VERSION 5.7 ;
BUSBITCHARS "[]" ;
DIVIDERCHAR "/" ;

PROPERTYDEFINITIONS
  MACRO CatenaDesignType STRING ;
END PROPERTYDEFINITIONS

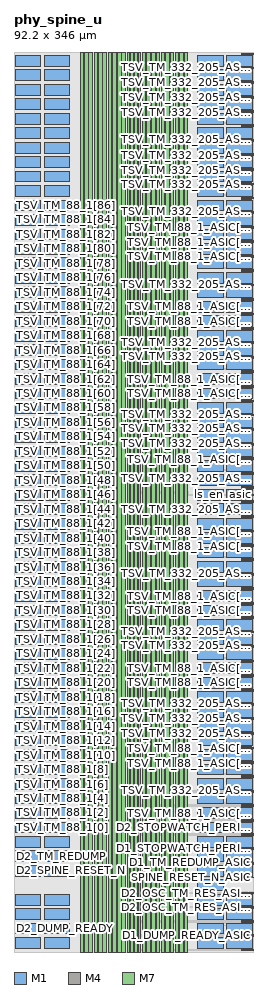
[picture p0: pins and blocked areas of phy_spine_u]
MACRO phy_spine_u
  CLASS RING ;
  ORIGIN 0 0 ;
  FOREIGN phy_spine_u 0 0 ;
  SIZE 92.2 BY 346 ;
  SYMMETRY X Y R90 ;
  PIN D1_DUMP_READY
    DIRECTION INPUT ;
    USE SIGNAL ;
    PORT
      LAYER M1 ;
        RECT 70.7 6.925 80.38 11.045 ;
    END
  END D1_DUMP_READY
  PIN D1_OSC_TM_RES[0]
    DIRECTION INPUT ;
    USE SIGNAL ;
    PORT
      LAYER M1 ;
        RECT 70.7 18.045 80.38 22.165 ;
    END
  END D1_OSC_TM_RES[0]
  PIN D1_OSC_TM_RES[1]
    DIRECTION INPUT ;
    USE SIGNAL ;
    PORT
      LAYER M1 ;
        RECT 70.7 12.485 80.38 16.605 ;
    END
  END D1_OSC_TM_RES[1]
  PIN D1_SPINE_RESET_N
    DIRECTION OUTPUT ;
    USE SIGNAL ;
    PORT
      LAYER M1 ;
        RECT 70.7 29.165 80.38 33.285 ;
    END
  END D1_SPINE_RESET_N
  PIN D1_STOPWATCH_PERIOD
    DIRECTION OUTPUT ;
    USE SIGNAL ;
    PORT
      LAYER M1 ;
        RECT 70.7 40.285 80.38 44.405 ;
    END
  END D1_STOPWATCH_PERIOD
  PIN D1_STOPWATCH_RINGO
    DIRECTION INPUT ;
    USE SIGNAL ;
    PORT
      LAYER M1 ;
        RECT 70.7 1.365 80.38 5.485 ;
    END
  END D1_STOPWATCH_RINGO
  PIN D1_TM_REDUMP
    DIRECTION OUTPUT ;
    USE SIGNAL ;
    PORT
      LAYER M1 ;
        RECT 70.7 34.725 80.38 38.845 ;
    END
  END D1_TM_REDUMP
  PIN D2_DUMP_READY
    DIRECTION INPUT ;
    USE SIGNAL ;
    PORT
      LAYER M1 ;
        RECT 11.79 6.925 21.47 11.045 ;
    END
  END D2_DUMP_READY
  PIN D2_OSC_TM_RES[0]
    DIRECTION INPUT ;
    USE SIGNAL ;
    PORT
      LAYER M1 ;
        RECT 11.79 18.045 21.47 22.165 ;
    END
  END D2_OSC_TM_RES[0]
  PIN D2_OSC_TM_RES[1]
    DIRECTION INPUT ;
    USE SIGNAL ;
    PORT
      LAYER M1 ;
        RECT 11.79 12.485 21.47 16.605 ;
    END
  END D2_OSC_TM_RES[1]
  PIN D2_SPINE_RESET_N
    DIRECTION OUTPUT ;
    USE SIGNAL ;
    PORT
      LAYER M1 ;
        RECT 11.79 29.165 21.47 33.285 ;
    END
  END D2_SPINE_RESET_N
  PIN D2_STOPWATCH_PERIOD
    DIRECTION OUTPUT ;
    USE SIGNAL ;
    PORT
      LAYER M1 ;
        RECT 11.79 40.285 21.47 44.405 ;
    END
  END D2_STOPWATCH_PERIOD
  PIN D2_STOPWATCH_RINGO
    DIRECTION INPUT ;
    USE SIGNAL ;
    PORT
      LAYER M1 ;
        RECT 11.79 1.365 21.47 5.485 ;
    END
  END D2_STOPWATCH_RINGO
  PIN D2_TM_REDUMP
    DIRECTION OUTPUT ;
    USE SIGNAL ;
    PORT
      LAYER M1 ;
        RECT 11.79 34.725 21.47 38.845 ;
    END
  END D2_TM_REDUMP
  PIN D3_DUMP_READY
    DIRECTION INPUT ;
    USE SIGNAL ;
    PORT
      LAYER M1 ;
        RECT 0.67 6.925 10.35 11.045 ;
    END
  END D3_DUMP_READY
  PIN D3_OSC_TM_RES[0]
    DIRECTION INPUT ;
    USE SIGNAL ;
    PORT
      LAYER M1 ;
        RECT 0.67 18.045 10.35 22.165 ;
    END
  END D3_OSC_TM_RES[0]
  PIN D3_OSC_TM_RES[1]
    DIRECTION INPUT ;
    USE SIGNAL ;
    PORT
      LAYER M1 ;
        RECT 0.67 12.485 10.35 16.605 ;
    END
  END D3_OSC_TM_RES[1]
  PIN D3_SPINE_RESET_N
    DIRECTION OUTPUT ;
    USE SIGNAL ;
    PORT
      LAYER M1 ;
        RECT 0.67 29.165 10.35 33.285 ;
    END
  END D3_SPINE_RESET_N
  PIN D3_STOPWATCH_PERIOD
    DIRECTION OUTPUT ;
    USE SIGNAL ;
    PORT
      LAYER M1 ;
        RECT 0.67 40.285 10.35 44.405 ;
    END
  END D3_STOPWATCH_PERIOD
  PIN D3_STOPWATCH_RINGO
    DIRECTION INPUT ;
    USE SIGNAL ;
    PORT
      LAYER M1 ;
        RECT 0.67 1.365 10.35 5.485 ;
    END
  END D3_STOPWATCH_RINGO
  PIN D3_TM_REDUMP
    DIRECTION OUTPUT ;
    USE SIGNAL ;
    PORT
      LAYER M1 ;
        RECT 0.67 34.725 10.35 38.845 ;
    END
  END D3_TM_REDUMP
  PIN DUMP_READY
    DIRECTION INPUT ;
    USE SIGNAL ;
    PORT
      LAYER M1 ;
        RECT 81.82 6.925 91.5 11.045 ;
    END
  END DUMP_READY
  PIN OSC_TM_RES[0]
    DIRECTION INPUT ;
    USE SIGNAL ;
    PORT
      LAYER M1 ;
        RECT 81.82 18.045 91.5 22.165 ;
    END
  END OSC_TM_RES[0]
  PIN OSC_TM_RES[1]
    DIRECTION INPUT ;
    USE SIGNAL ;
    PORT
      LAYER M1 ;
        RECT 81.82 12.485 91.5 16.605 ;
    END
  END OSC_TM_RES[1]
  PIN SPINE_RESET_N
    DIRECTION OUTPUT ;
    USE SIGNAL ;
    PORT
      LAYER M1 ;
        RECT 81.82 29.165 91.5 33.285 ;
    END
  END SPINE_RESET_N
  PIN STOPWATCH_PERIOD
    DIRECTION OUTPUT ;
    USE SIGNAL ;
    PORT
      LAYER M1 ;
        RECT 81.82 40.285 91.5 44.405 ;
    END
  END STOPWATCH_PERIOD
  PIN STOPWATCH_RINGO
    DIRECTION INPUT ;
    USE SIGNAL ;
    PORT
      LAYER M1 ;
        RECT 81.82 1.365 91.5 5.485 ;
    END
  END STOPWATCH_RINGO
  PIN TM_REDUMP
    DIRECTION OUTPUT ;
    USE SIGNAL ;
    PORT
      LAYER M1 ;
        RECT 81.82 34.725 91.5 38.845 ;
    END
  END TM_REDUMP
  PIN TSV_TM_332_205[0]
    DIRECTION OUTPUT ;
    USE SIGNAL ;
    PORT
      LAYER M1 ;
        RECT 81.82 45.845 91.5 49.965 ;
    END
  END TSV_TM_332_205[0]
  PIN TSV_TM_332_205[100]
    DIRECTION OUTPUT ;
    USE SIGNAL ;
    PORT
      LAYER M1 ;
        RECT 81.82 323.845 91.5 327.965 ;
    END
  END TSV_TM_332_205[100]
  PIN TSV_TM_332_205[101]
    DIRECTION OUTPUT ;
    USE SIGNAL ;
    PORT
      LAYER M1 ;
        RECT 70.7 323.845 80.38 327.965 ;
    END
  END TSV_TM_332_205[101]
  PIN TSV_TM_332_205[102]
    DIRECTION OUTPUT ;
    USE SIGNAL ;
    PORT
      LAYER M1 ;
        RECT 81.82 329.405 91.5 333.525 ;
    END
  END TSV_TM_332_205[102]
  PIN TSV_TM_332_205[103]
    DIRECTION OUTPUT ;
    USE SIGNAL ;
    PORT
      LAYER M1 ;
        RECT 70.7 329.405 80.38 333.525 ;
    END
  END TSV_TM_332_205[103]
  PIN TSV_TM_332_205[104]
    DIRECTION OUTPUT ;
    USE SIGNAL ;
    PORT
      LAYER M1 ;
        RECT 81.82 334.965 91.5 339.085 ;
    END
  END TSV_TM_332_205[104]
  PIN TSV_TM_332_205[105]
    DIRECTION OUTPUT ;
    USE SIGNAL ;
    PORT
      LAYER M1 ;
        RECT 70.7 334.965 80.38 339.085 ;
    END
  END TSV_TM_332_205[105]
  PIN TSV_TM_332_205[106]
    DIRECTION OUTPUT ;
    USE SIGNAL ;
    PORT
      LAYER M1 ;
        RECT 81.82 340.525 91.5 344.645 ;
    END
  END TSV_TM_332_205[106]
  PIN TSV_TM_332_205[107]
    DIRECTION OUTPUT ;
    USE SIGNAL ;
    PORT
      LAYER M1 ;
        RECT 70.7 340.525 80.38 344.645 ;
    END
  END TSV_TM_332_205[107]
  PIN TSV_TM_332_205[108]
    DIRECTION OUTPUT ;
    USE SIGNAL ;
    PORT
      LAYER M1 ;
        RECT 11.79 340.525 21.47 344.645 ;
    END
  END TSV_TM_332_205[108]
  PIN TSV_TM_332_205[109]
    DIRECTION OUTPUT ;
    USE SIGNAL ;
    PORT
      LAYER M1 ;
        RECT 0.67 340.525 10.35 344.645 ;
    END
  END TSV_TM_332_205[109]
  PIN TSV_TM_332_205[10]
    DIRECTION OUTPUT ;
    USE SIGNAL ;
    PORT
      LAYER M1 ;
        RECT 81.82 73.645 91.5 77.765 ;
    END
  END TSV_TM_332_205[10]
  PIN TSV_TM_332_205[110]
    DIRECTION OUTPUT ;
    USE SIGNAL ;
    PORT
      LAYER M1 ;
        RECT 11.79 334.965 21.47 339.085 ;
    END
  END TSV_TM_332_205[110]
  PIN TSV_TM_332_205[111]
    DIRECTION OUTPUT ;
    USE SIGNAL ;
    PORT
      LAYER M1 ;
        RECT 0.67 334.965 10.35 339.085 ;
    END
  END TSV_TM_332_205[111]
  PIN TSV_TM_332_205[112]
    DIRECTION OUTPUT ;
    USE SIGNAL ;
    PORT
      LAYER M1 ;
        RECT 11.79 329.405 21.47 333.525 ;
    END
  END TSV_TM_332_205[112]
  PIN TSV_TM_332_205[113]
    DIRECTION OUTPUT ;
    USE SIGNAL ;
    PORT
      LAYER M1 ;
        RECT 0.67 329.405 10.35 333.525 ;
    END
  END TSV_TM_332_205[113]
  PIN TSV_TM_332_205[114]
    DIRECTION OUTPUT ;
    USE SIGNAL ;
    PORT
      LAYER M1 ;
        RECT 11.79 323.845 21.47 327.965 ;
    END
  END TSV_TM_332_205[114]
  PIN TSV_TM_332_205[115]
    DIRECTION OUTPUT ;
    USE SIGNAL ;
    PORT
      LAYER M1 ;
        RECT 0.67 323.845 10.35 327.965 ;
    END
  END TSV_TM_332_205[115]
  PIN TSV_TM_332_205[116]
    DIRECTION OUTPUT ;
    USE SIGNAL ;
    PORT
      LAYER M1 ;
        RECT 11.79 318.285 21.47 322.405 ;
    END
  END TSV_TM_332_205[116]
  PIN TSV_TM_332_205[117]
    DIRECTION OUTPUT ;
    USE SIGNAL ;
    PORT
      LAYER M1 ;
        RECT 0.67 318.285 10.35 322.405 ;
    END
  END TSV_TM_332_205[117]
  PIN TSV_TM_332_205[118]
    DIRECTION OUTPUT ;
    USE SIGNAL ;
    PORT
      LAYER M1 ;
        RECT 11.79 312.725 21.47 316.845 ;
    END
  END TSV_TM_332_205[118]
  PIN TSV_TM_332_205[119]
    DIRECTION OUTPUT ;
    USE SIGNAL ;
    PORT
      LAYER M1 ;
        RECT 0.67 312.725 10.35 316.845 ;
    END
  END TSV_TM_332_205[119]
  PIN TSV_TM_332_205[11]
    DIRECTION OUTPUT ;
    USE SIGNAL ;
    PORT
      LAYER M1 ;
        RECT 70.7 73.645 80.38 77.765 ;
    END
  END TSV_TM_332_205[11]
  PIN TSV_TM_332_205[120]
    DIRECTION OUTPUT ;
    USE SIGNAL ;
    PORT
      LAYER M1 ;
        RECT 11.79 307.165 21.47 311.285 ;
    END
  END TSV_TM_332_205[120]
  PIN TSV_TM_332_205[121]
    DIRECTION OUTPUT ;
    USE SIGNAL ;
    PORT
      LAYER M1 ;
        RECT 0.67 307.165 10.35 311.285 ;
    END
  END TSV_TM_332_205[121]
  PIN TSV_TM_332_205[122]
    DIRECTION OUTPUT ;
    USE SIGNAL ;
    PORT
      LAYER M1 ;
        RECT 11.79 301.605 21.47 305.725 ;
    END
  END TSV_TM_332_205[122]
  PIN TSV_TM_332_205[123]
    DIRECTION OUTPUT ;
    USE SIGNAL ;
    PORT
      LAYER M1 ;
        RECT 0.67 301.605 10.35 305.725 ;
    END
  END TSV_TM_332_205[123]
  PIN TSV_TM_332_205[124]
    DIRECTION OUTPUT ;
    USE SIGNAL ;
    PORT
      LAYER M1 ;
        RECT 11.79 296.045 21.47 300.165 ;
    END
  END TSV_TM_332_205[124]
  PIN TSV_TM_332_205[125]
    DIRECTION OUTPUT ;
    USE SIGNAL ;
    PORT
      LAYER M1 ;
        RECT 0.67 296.045 10.35 300.165 ;
    END
  END TSV_TM_332_205[125]
  PIN TSV_TM_332_205[126]
    DIRECTION OUTPUT ;
    USE SIGNAL ;
    PORT
      LAYER M1 ;
        RECT 11.79 290.485 21.47 294.605 ;
    END
  END TSV_TM_332_205[126]
  PIN TSV_TM_332_205[127]
    DIRECTION OUTPUT ;
    USE SIGNAL ;
    PORT
      LAYER M1 ;
        RECT 0.67 290.485 10.35 294.605 ;
    END
  END TSV_TM_332_205[127]
  PIN TSV_TM_332_205[12]
    DIRECTION OUTPUT ;
    USE SIGNAL ;
    PORT
      LAYER M1 ;
        RECT 81.82 79.205 91.5 83.325 ;
    END
  END TSV_TM_332_205[12]
  PIN TSV_TM_332_205[13]
    DIRECTION OUTPUT ;
    USE SIGNAL ;
    PORT
      LAYER M1 ;
        RECT 70.7 79.205 80.38 83.325 ;
    END
  END TSV_TM_332_205[13]
  PIN TSV_TM_332_205[14]
    DIRECTION OUTPUT ;
    USE SIGNAL ;
    PORT
      LAYER M1 ;
        RECT 81.82 84.765 91.5 88.885 ;
    END
  END TSV_TM_332_205[14]
  PIN TSV_TM_332_205[15]
    DIRECTION OUTPUT ;
    USE SIGNAL ;
    PORT
      LAYER M1 ;
        RECT 70.7 84.765 80.38 88.885 ;
    END
  END TSV_TM_332_205[15]
  PIN TSV_TM_332_205[16]
    DIRECTION OUTPUT ;
    USE SIGNAL ;
    PORT
      LAYER M1 ;
        RECT 81.82 90.325 91.5 94.445 ;
    END
  END TSV_TM_332_205[16]
  PIN TSV_TM_332_205[17]
    DIRECTION OUTPUT ;
    USE SIGNAL ;
    PORT
      LAYER M1 ;
        RECT 70.7 90.325 80.38 94.445 ;
    END
  END TSV_TM_332_205[17]
  PIN TSV_TM_332_205[18]
    DIRECTION OUTPUT ;
    USE SIGNAL ;
    PORT
      LAYER M1 ;
        RECT 81.82 95.885 91.5 100.005 ;
    END
  END TSV_TM_332_205[18]
  PIN TSV_TM_332_205[19]
    DIRECTION OUTPUT ;
    USE SIGNAL ;
    PORT
      LAYER M1 ;
        RECT 70.7 95.885 80.38 100.005 ;
    END
  END TSV_TM_332_205[19]
  PIN TSV_TM_332_205[1]
    DIRECTION OUTPUT ;
    USE SIGNAL ;
    PORT
      LAYER M1 ;
        RECT 70.7 45.845 80.38 49.965 ;
    END
  END TSV_TM_332_205[1]
  PIN TSV_TM_332_205[20]
    DIRECTION OUTPUT ;
    USE SIGNAL ;
    PORT
      LAYER M1 ;
        RECT 81.82 101.445 91.5 105.565 ;
    END
  END TSV_TM_332_205[20]
  PIN TSV_TM_332_205[21]
    DIRECTION OUTPUT ;
    USE SIGNAL ;
    PORT
      LAYER M1 ;
        RECT 70.7 101.445 80.38 105.565 ;
    END
  END TSV_TM_332_205[21]
  PIN TSV_TM_332_205[22]
    DIRECTION OUTPUT ;
    USE SIGNAL ;
    PORT
      LAYER M1 ;
        RECT 81.82 107.005 91.5 111.125 ;
    END
  END TSV_TM_332_205[22]
  PIN TSV_TM_332_205[23]
    DIRECTION OUTPUT ;
    USE SIGNAL ;
    PORT
      LAYER M1 ;
        RECT 70.7 107.005 80.38 111.125 ;
    END
  END TSV_TM_332_205[23]
  PIN TSV_TM_332_205[24]
    DIRECTION OUTPUT ;
    USE SIGNAL ;
    PORT
      LAYER M1 ;
        RECT 81.82 112.565 91.5 116.685 ;
    END
  END TSV_TM_332_205[24]
  PIN TSV_TM_332_205[25]
    DIRECTION OUTPUT ;
    USE SIGNAL ;
    PORT
      LAYER M1 ;
        RECT 70.7 112.565 80.38 116.685 ;
    END
  END TSV_TM_332_205[25]
  PIN TSV_TM_332_205[26]
    DIRECTION OUTPUT ;
    USE SIGNAL ;
    PORT
      LAYER M1 ;
        RECT 81.82 118.125 91.5 122.245 ;
    END
  END TSV_TM_332_205[26]
  PIN TSV_TM_332_205[27]
    DIRECTION OUTPUT ;
    USE SIGNAL ;
    PORT
      LAYER M1 ;
        RECT 70.7 118.125 80.38 122.245 ;
    END
  END TSV_TM_332_205[27]
  PIN TSV_TM_332_205[28]
    DIRECTION OUTPUT ;
    USE SIGNAL ;
    PORT
      LAYER M1 ;
        RECT 81.82 123.685 91.5 127.805 ;
    END
  END TSV_TM_332_205[28]
  PIN TSV_TM_332_205[29]
    DIRECTION OUTPUT ;
    USE SIGNAL ;
    PORT
      LAYER M1 ;
        RECT 70.7 123.685 80.38 127.805 ;
    END
  END TSV_TM_332_205[29]
  PIN TSV_TM_332_205[2]
    DIRECTION OUTPUT ;
    USE SIGNAL ;
    PORT
      LAYER M1 ;
        RECT 81.82 51.405 91.5 55.525 ;
    END
  END TSV_TM_332_205[2]
  PIN TSV_TM_332_205[30]
    DIRECTION OUTPUT ;
    USE SIGNAL ;
    PORT
      LAYER M1 ;
        RECT 81.82 129.245 91.5 133.365 ;
    END
  END TSV_TM_332_205[30]
  PIN TSV_TM_332_205[31]
    DIRECTION OUTPUT ;
    USE SIGNAL ;
    PORT
      LAYER M1 ;
        RECT 70.7 129.245 80.38 133.365 ;
    END
  END TSV_TM_332_205[31]
  PIN TSV_TM_332_205[32]
    DIRECTION OUTPUT ;
    USE SIGNAL ;
    PORT
      LAYER M1 ;
        RECT 81.82 134.805 91.5 138.925 ;
    END
  END TSV_TM_332_205[32]
  PIN TSV_TM_332_205[33]
    DIRECTION OUTPUT ;
    USE SIGNAL ;
    PORT
      LAYER M1 ;
        RECT 70.7 134.805 80.38 138.925 ;
    END
  END TSV_TM_332_205[33]
  PIN TSV_TM_332_205[34]
    DIRECTION OUTPUT ;
    USE SIGNAL ;
    PORT
      LAYER M1 ;
        RECT 81.82 140.365 91.5 144.485 ;
    END
  END TSV_TM_332_205[34]
  PIN TSV_TM_332_205[35]
    DIRECTION OUTPUT ;
    USE SIGNAL ;
    PORT
      LAYER M1 ;
        RECT 70.7 140.365 80.38 144.485 ;
    END
  END TSV_TM_332_205[35]
  PIN TSV_TM_332_205[36]
    DIRECTION OUTPUT ;
    USE SIGNAL ;
    PORT
      LAYER M1 ;
        RECT 81.82 145.925 91.5 150.045 ;
    END
  END TSV_TM_332_205[36]
  PIN TSV_TM_332_205[37]
    DIRECTION OUTPUT ;
    USE SIGNAL ;
    PORT
      LAYER M1 ;
        RECT 70.7 145.925 80.38 150.045 ;
    END
  END TSV_TM_332_205[37]
  PIN TSV_TM_332_205[38]
    DIRECTION OUTPUT ;
    USE SIGNAL ;
    PORT
      LAYER M1 ;
        RECT 81.82 151.485 91.5 155.605 ;
    END
  END TSV_TM_332_205[38]
  PIN TSV_TM_332_205[39]
    DIRECTION OUTPUT ;
    USE SIGNAL ;
    PORT
      LAYER M1 ;
        RECT 70.7 151.485 80.38 155.605 ;
    END
  END TSV_TM_332_205[39]
  PIN TSV_TM_332_205[3]
    DIRECTION OUTPUT ;
    USE SIGNAL ;
    PORT
      LAYER M1 ;
        RECT 70.7 51.405 80.38 55.525 ;
    END
  END TSV_TM_332_205[3]
  PIN TSV_TM_332_205[40]
    DIRECTION OUTPUT ;
    USE SIGNAL ;
    PORT
      LAYER M1 ;
        RECT 81.82 157.045 91.5 161.165 ;
    END
  END TSV_TM_332_205[40]
  PIN TSV_TM_332_205[41]
    DIRECTION OUTPUT ;
    USE SIGNAL ;
    PORT
      LAYER M1 ;
        RECT 70.7 157.045 80.38 161.165 ;
    END
  END TSV_TM_332_205[41]
  PIN TSV_TM_332_205[42]
    DIRECTION OUTPUT ;
    USE SIGNAL ;
    PORT
      LAYER M1 ;
        RECT 81.82 162.605 91.5 166.725 ;
    END
  END TSV_TM_332_205[42]
  PIN TSV_TM_332_205[43]
    DIRECTION OUTPUT ;
    USE SIGNAL ;
    PORT
      LAYER M1 ;
        RECT 70.7 162.605 80.38 166.725 ;
    END
  END TSV_TM_332_205[43]
  PIN TSV_TM_332_205[44]
    DIRECTION OUTPUT ;
    USE SIGNAL ;
    PORT
      LAYER M1 ;
        RECT 81.82 168.165 91.5 172.285 ;
    END
  END TSV_TM_332_205[44]
  PIN TSV_TM_332_205[45]
    DIRECTION OUTPUT ;
    USE SIGNAL ;
    PORT
      LAYER M1 ;
        RECT 70.7 168.165 80.38 172.285 ;
    END
  END TSV_TM_332_205[45]
  PIN TSV_TM_332_205[46]
    DIRECTION OUTPUT ;
    USE SIGNAL ;
    PORT
      LAYER M1 ;
        RECT 81.82 173.725 91.5 177.845 ;
    END
  END TSV_TM_332_205[46]
  PIN TSV_TM_332_205[47]
    DIRECTION OUTPUT ;
    USE SIGNAL ;
    PORT
      LAYER M1 ;
        RECT 70.7 173.725 80.38 177.845 ;
    END
  END TSV_TM_332_205[47]
  PIN TSV_TM_332_205[48]
    DIRECTION OUTPUT ;
    USE SIGNAL ;
    PORT
      LAYER M1 ;
        RECT 81.82 179.285 91.5 183.405 ;
    END
  END TSV_TM_332_205[48]
  PIN TSV_TM_332_205[49]
    DIRECTION OUTPUT ;
    USE SIGNAL ;
    PORT
      LAYER M1 ;
        RECT 70.7 179.285 80.38 183.405 ;
    END
  END TSV_TM_332_205[49]
  PIN TSV_TM_332_205[4]
    DIRECTION OUTPUT ;
    USE SIGNAL ;
    PORT
      LAYER M1 ;
        RECT 81.82 56.965 91.5 61.085 ;
    END
  END TSV_TM_332_205[4]
  PIN TSV_TM_332_205[50]
    DIRECTION OUTPUT ;
    USE SIGNAL ;
    PORT
      LAYER M1 ;
        RECT 81.82 184.845 91.5 188.965 ;
    END
  END TSV_TM_332_205[50]
  PIN TSV_TM_332_205[51]
    DIRECTION OUTPUT ;
    USE SIGNAL ;
    PORT
      LAYER M1 ;
        RECT 70.7 184.845 80.38 188.965 ;
    END
  END TSV_TM_332_205[51]
  PIN TSV_TM_332_205[52]
    DIRECTION OUTPUT ;
    USE SIGNAL ;
    PORT
      LAYER M1 ;
        RECT 81.82 190.405 91.5 194.525 ;
    END
  END TSV_TM_332_205[52]
  PIN TSV_TM_332_205[53]
    DIRECTION OUTPUT ;
    USE SIGNAL ;
    PORT
      LAYER M1 ;
        RECT 70.7 190.405 80.38 194.525 ;
    END
  END TSV_TM_332_205[53]
  PIN TSV_TM_332_205[54]
    DIRECTION OUTPUT ;
    USE SIGNAL ;
    PORT
      LAYER M1 ;
        RECT 81.82 195.965 91.5 200.085 ;
    END
  END TSV_TM_332_205[54]
  PIN TSV_TM_332_205[55]
    DIRECTION OUTPUT ;
    USE SIGNAL ;
    PORT
      LAYER M1 ;
        RECT 70.7 195.965 80.38 200.085 ;
    END
  END TSV_TM_332_205[55]
  PIN TSV_TM_332_205[56]
    DIRECTION OUTPUT ;
    USE SIGNAL ;
    PORT
      LAYER M1 ;
        RECT 81.82 201.525 91.5 205.645 ;
    END
  END TSV_TM_332_205[56]
  PIN TSV_TM_332_205[57]
    DIRECTION OUTPUT ;
    USE SIGNAL ;
    PORT
      LAYER M1 ;
        RECT 70.7 201.525 80.38 205.645 ;
    END
  END TSV_TM_332_205[57]
  PIN TSV_TM_332_205[58]
    DIRECTION OUTPUT ;
    USE SIGNAL ;
    PORT
      LAYER M1 ;
        RECT 81.82 207.085 91.5 211.205 ;
    END
  END TSV_TM_332_205[58]
  PIN TSV_TM_332_205[59]
    DIRECTION OUTPUT ;
    USE SIGNAL ;
    PORT
      LAYER M1 ;
        RECT 70.7 207.085 80.38 211.205 ;
    END
  END TSV_TM_332_205[59]
  PIN TSV_TM_332_205[5]
    DIRECTION OUTPUT ;
    USE SIGNAL ;
    PORT
      LAYER M1 ;
        RECT 70.7 56.965 80.38 61.085 ;
    END
  END TSV_TM_332_205[5]
  PIN TSV_TM_332_205[60]
    DIRECTION OUTPUT ;
    USE SIGNAL ;
    PORT
      LAYER M1 ;
        RECT 81.82 212.645 91.5 216.765 ;
    END
  END TSV_TM_332_205[60]
  PIN TSV_TM_332_205[61]
    DIRECTION OUTPUT ;
    USE SIGNAL ;
    PORT
      LAYER M1 ;
        RECT 70.7 212.645 80.38 216.765 ;
    END
  END TSV_TM_332_205[61]
  PIN TSV_TM_332_205[62]
    DIRECTION OUTPUT ;
    USE SIGNAL ;
    PORT
      LAYER M1 ;
        RECT 81.82 218.205 91.5 222.325 ;
    END
  END TSV_TM_332_205[62]
  PIN TSV_TM_332_205[63]
    DIRECTION OUTPUT ;
    USE SIGNAL ;
    PORT
      LAYER M1 ;
        RECT 70.7 218.205 80.38 222.325 ;
    END
  END TSV_TM_332_205[63]
  PIN TSV_TM_332_205[64]
    DIRECTION OUTPUT ;
    USE SIGNAL ;
    PORT
      LAYER M1 ;
        RECT 81.82 223.765 91.5 227.885 ;
    END
  END TSV_TM_332_205[64]
  PIN TSV_TM_332_205[65]
    DIRECTION OUTPUT ;
    USE SIGNAL ;
    PORT
      LAYER M1 ;
        RECT 70.7 223.765 80.38 227.885 ;
    END
  END TSV_TM_332_205[65]
  PIN TSV_TM_332_205[66]
    DIRECTION OUTPUT ;
    USE SIGNAL ;
    PORT
      LAYER M1 ;
        RECT 81.82 229.325 91.5 233.445 ;
    END
  END TSV_TM_332_205[66]
  PIN TSV_TM_332_205[67]
    DIRECTION OUTPUT ;
    USE SIGNAL ;
    PORT
      LAYER M1 ;
        RECT 70.7 229.325 80.38 233.445 ;
    END
  END TSV_TM_332_205[67]
  PIN TSV_TM_332_205[68]
    DIRECTION OUTPUT ;
    USE SIGNAL ;
    PORT
      LAYER M1 ;
        RECT 81.82 234.885 91.5 239.005 ;
    END
  END TSV_TM_332_205[68]
  PIN TSV_TM_332_205[69]
    DIRECTION OUTPUT ;
    USE SIGNAL ;
    PORT
      LAYER M1 ;
        RECT 70.7 234.885 80.38 239.005 ;
    END
  END TSV_TM_332_205[69]
  PIN TSV_TM_332_205[6]
    DIRECTION OUTPUT ;
    USE SIGNAL ;
    PORT
      LAYER M1 ;
        RECT 81.82 62.525 91.5 66.645 ;
    END
  END TSV_TM_332_205[6]
  PIN TSV_TM_332_205[70]
    DIRECTION OUTPUT ;
    USE SIGNAL ;
    PORT
      LAYER M1 ;
        RECT 81.82 240.445 91.5 244.565 ;
    END
  END TSV_TM_332_205[70]
  PIN TSV_TM_332_205[71]
    DIRECTION OUTPUT ;
    USE SIGNAL ;
    PORT
      LAYER M1 ;
        RECT 70.7 240.445 80.38 244.565 ;
    END
  END TSV_TM_332_205[71]
  PIN TSV_TM_332_205[72]
    DIRECTION OUTPUT ;
    USE SIGNAL ;
    PORT
      LAYER M1 ;
        RECT 81.82 246.005 91.5 250.125 ;
    END
  END TSV_TM_332_205[72]
  PIN TSV_TM_332_205[73]
    DIRECTION OUTPUT ;
    USE SIGNAL ;
    PORT
      LAYER M1 ;
        RECT 70.7 246.005 80.38 250.125 ;
    END
  END TSV_TM_332_205[73]
  PIN TSV_TM_332_205[74]
    DIRECTION OUTPUT ;
    USE SIGNAL ;
    PORT
      LAYER M1 ;
        RECT 81.82 251.565 91.5 255.685 ;
    END
  END TSV_TM_332_205[74]
  PIN TSV_TM_332_205[75]
    DIRECTION OUTPUT ;
    USE SIGNAL ;
    PORT
      LAYER M1 ;
        RECT 70.7 251.565 80.38 255.685 ;
    END
  END TSV_TM_332_205[75]
  PIN TSV_TM_332_205[76]
    DIRECTION OUTPUT ;
    USE SIGNAL ;
    PORT
      LAYER M1 ;
        RECT 81.82 257.125 91.5 261.245 ;
    END
  END TSV_TM_332_205[76]
  PIN TSV_TM_332_205[77]
    DIRECTION OUTPUT ;
    USE SIGNAL ;
    PORT
      LAYER M1 ;
        RECT 70.7 257.125 80.38 261.245 ;
    END
  END TSV_TM_332_205[77]
  PIN TSV_TM_332_205[78]
    DIRECTION OUTPUT ;
    USE SIGNAL ;
    PORT
      LAYER M1 ;
        RECT 81.82 262.685 91.5 266.805 ;
    END
  END TSV_TM_332_205[78]
  PIN TSV_TM_332_205[79]
    DIRECTION OUTPUT ;
    USE SIGNAL ;
    PORT
      LAYER M1 ;
        RECT 70.7 262.685 80.38 266.805 ;
    END
  END TSV_TM_332_205[79]
  PIN TSV_TM_332_205[7]
    DIRECTION OUTPUT ;
    USE SIGNAL ;
    PORT
      LAYER M1 ;
        RECT 70.7 62.525 80.38 66.645 ;
    END
  END TSV_TM_332_205[7]
  PIN TSV_TM_332_205[80]
    DIRECTION OUTPUT ;
    USE SIGNAL ;
    PORT
      LAYER M1 ;
        RECT 81.82 268.245 91.5 272.365 ;
    END
  END TSV_TM_332_205[80]
  PIN TSV_TM_332_205[81]
    DIRECTION OUTPUT ;
    USE SIGNAL ;
    PORT
      LAYER M1 ;
        RECT 70.7 268.245 80.38 272.365 ;
    END
  END TSV_TM_332_205[81]
  PIN TSV_TM_332_205[82]
    DIRECTION OUTPUT ;
    USE SIGNAL ;
    PORT
      LAYER M1 ;
        RECT 81.82 273.805 91.5 277.925 ;
    END
  END TSV_TM_332_205[82]
  PIN TSV_TM_332_205[83]
    DIRECTION OUTPUT ;
    USE SIGNAL ;
    PORT
      LAYER M1 ;
        RECT 70.7 273.805 80.38 277.925 ;
    END
  END TSV_TM_332_205[83]
  PIN TSV_TM_332_205[84]
    DIRECTION OUTPUT ;
    USE SIGNAL ;
    PORT
      LAYER M1 ;
        RECT 81.82 279.365 91.5 283.485 ;
    END
  END TSV_TM_332_205[84]
  PIN TSV_TM_332_205[85]
    DIRECTION OUTPUT ;
    USE SIGNAL ;
    PORT
      LAYER M1 ;
        RECT 70.7 279.365 80.38 283.485 ;
    END
  END TSV_TM_332_205[85]
  PIN TSV_TM_332_205[86]
    DIRECTION OUTPUT ;
    USE SIGNAL ;
    PORT
      LAYER M1 ;
        RECT 81.82 284.925 91.5 289.045 ;
    END
  END TSV_TM_332_205[86]
  PIN TSV_TM_332_205[87]
    DIRECTION OUTPUT ;
    USE SIGNAL ;
    PORT
      LAYER M1 ;
        RECT 70.7 284.925 80.38 289.045 ;
    END
  END TSV_TM_332_205[87]
  PIN TSV_TM_332_205[88]
    DIRECTION OUTPUT ;
    USE SIGNAL ;
    PORT
      LAYER M1 ;
        RECT 81.82 290.485 91.5 294.605 ;
    END
  END TSV_TM_332_205[88]
  PIN TSV_TM_332_205[89]
    DIRECTION OUTPUT ;
    USE SIGNAL ;
    PORT
      LAYER M1 ;
        RECT 70.7 290.485 80.38 294.605 ;
    END
  END TSV_TM_332_205[89]
  PIN TSV_TM_332_205[8]
    DIRECTION OUTPUT ;
    USE SIGNAL ;
    PORT
      LAYER M1 ;
        RECT 81.82 68.085 91.5 72.205 ;
    END
  END TSV_TM_332_205[8]
  PIN TSV_TM_332_205[90]
    DIRECTION OUTPUT ;
    USE SIGNAL ;
    PORT
      LAYER M1 ;
        RECT 81.82 296.045 91.5 300.165 ;
    END
  END TSV_TM_332_205[90]
  PIN TSV_TM_332_205[91]
    DIRECTION OUTPUT ;
    USE SIGNAL ;
    PORT
      LAYER M1 ;
        RECT 70.7 296.045 80.38 300.165 ;
    END
  END TSV_TM_332_205[91]
  PIN TSV_TM_332_205[92]
    DIRECTION OUTPUT ;
    USE SIGNAL ;
    PORT
      LAYER M1 ;
        RECT 81.82 301.605 91.5 305.725 ;
    END
  END TSV_TM_332_205[92]
  PIN TSV_TM_332_205[93]
    DIRECTION OUTPUT ;
    USE SIGNAL ;
    PORT
      LAYER M1 ;
        RECT 70.7 301.605 80.38 305.725 ;
    END
  END TSV_TM_332_205[93]
  PIN TSV_TM_332_205[94]
    DIRECTION OUTPUT ;
    USE SIGNAL ;
    PORT
      LAYER M1 ;
        RECT 81.82 307.165 91.5 311.285 ;
    END
  END TSV_TM_332_205[94]
  PIN TSV_TM_332_205[95]
    DIRECTION OUTPUT ;
    USE SIGNAL ;
    PORT
      LAYER M1 ;
        RECT 70.7 307.165 80.38 311.285 ;
    END
  END TSV_TM_332_205[95]
  PIN TSV_TM_332_205[96]
    DIRECTION OUTPUT ;
    USE SIGNAL ;
    PORT
      LAYER M1 ;
        RECT 81.82 312.725 91.5 316.845 ;
    END
  END TSV_TM_332_205[96]
  PIN TSV_TM_332_205[97]
    DIRECTION OUTPUT ;
    USE SIGNAL ;
    PORT
      LAYER M1 ;
        RECT 70.7 312.725 80.38 316.845 ;
    END
  END TSV_TM_332_205[97]
  PIN TSV_TM_332_205[98]
    DIRECTION OUTPUT ;
    USE SIGNAL ;
    PORT
      LAYER M1 ;
        RECT 81.82 318.285 91.5 322.405 ;
    END
  END TSV_TM_332_205[98]
  PIN TSV_TM_332_205[99]
    DIRECTION OUTPUT ;
    USE SIGNAL ;
    PORT
      LAYER M1 ;
        RECT 70.7 318.285 80.38 322.405 ;
    END
  END TSV_TM_332_205[99]
  PIN TSV_TM_332_205[9]
    DIRECTION OUTPUT ;
    USE SIGNAL ;
    PORT
      LAYER M1 ;
        RECT 70.7 68.085 80.38 72.205 ;
    END
  END TSV_TM_332_205[9]
  PIN TSV_TM_88_1[0]
    DIRECTION OUTPUT ;
    USE SIGNAL ;
    PORT
      LAYER M1 ;
        RECT 11.79 45.845 21.47 49.965 ;
    END
  END TSV_TM_88_1[0]
  PIN TSV_TM_88_1[10]
    DIRECTION OUTPUT ;
    USE SIGNAL ;
    PORT
      LAYER M1 ;
        RECT 11.79 73.645 21.47 77.765 ;
    END
  END TSV_TM_88_1[10]
  PIN TSV_TM_88_1[11]
    DIRECTION OUTPUT ;
    USE SIGNAL ;
    PORT
      LAYER M1 ;
        RECT 0.67 73.645 10.35 77.765 ;
    END
  END TSV_TM_88_1[11]
  PIN TSV_TM_88_1[12]
    DIRECTION OUTPUT ;
    USE SIGNAL ;
    PORT
      LAYER M1 ;
        RECT 11.79 79.205 21.47 83.325 ;
    END
  END TSV_TM_88_1[12]
  PIN TSV_TM_88_1[13]
    DIRECTION OUTPUT ;
    USE SIGNAL ;
    PORT
      LAYER M1 ;
        RECT 0.67 79.205 10.35 83.325 ;
    END
  END TSV_TM_88_1[13]
  PIN TSV_TM_88_1[14]
    DIRECTION OUTPUT ;
    USE SIGNAL ;
    PORT
      LAYER M1 ;
        RECT 11.79 84.765 21.47 88.885 ;
    END
  END TSV_TM_88_1[14]
  PIN TSV_TM_88_1[15]
    DIRECTION OUTPUT ;
    USE SIGNAL ;
    PORT
      LAYER M1 ;
        RECT 0.67 84.765 10.35 88.885 ;
    END
  END TSV_TM_88_1[15]
  PIN TSV_TM_88_1[16]
    DIRECTION OUTPUT ;
    USE SIGNAL ;
    PORT
      LAYER M1 ;
        RECT 11.79 90.325 21.47 94.445 ;
    END
  END TSV_TM_88_1[16]
  PIN TSV_TM_88_1[17]
    DIRECTION OUTPUT ;
    USE SIGNAL ;
    PORT
      LAYER M1 ;
        RECT 0.67 90.325 10.35 94.445 ;
    END
  END TSV_TM_88_1[17]
  PIN TSV_TM_88_1[18]
    DIRECTION OUTPUT ;
    USE SIGNAL ;
    PORT
      LAYER M1 ;
        RECT 11.79 95.885 21.47 100.005 ;
    END
  END TSV_TM_88_1[18]
  PIN TSV_TM_88_1[19]
    DIRECTION OUTPUT ;
    USE SIGNAL ;
    PORT
      LAYER M1 ;
        RECT 0.67 95.885 10.35 100.005 ;
    END
  END TSV_TM_88_1[19]
  PIN TSV_TM_88_1[1]
    DIRECTION OUTPUT ;
    USE SIGNAL ;
    PORT
      LAYER M1 ;
        RECT 0.67 45.845 10.35 49.965 ;
    END
  END TSV_TM_88_1[1]
  PIN TSV_TM_88_1[20]
    DIRECTION OUTPUT ;
    USE SIGNAL ;
    PORT
      LAYER M1 ;
        RECT 11.79 101.445 21.47 105.565 ;
    END
  END TSV_TM_88_1[20]
  PIN TSV_TM_88_1[21]
    DIRECTION OUTPUT ;
    USE SIGNAL ;
    PORT
      LAYER M1 ;
        RECT 0.67 101.445 10.35 105.565 ;
    END
  END TSV_TM_88_1[21]
  PIN TSV_TM_88_1[22]
    DIRECTION OUTPUT ;
    USE SIGNAL ;
    PORT
      LAYER M1 ;
        RECT 11.79 107.005 21.47 111.125 ;
    END
  END TSV_TM_88_1[22]
  PIN TSV_TM_88_1[23]
    DIRECTION OUTPUT ;
    USE SIGNAL ;
    PORT
      LAYER M1 ;
        RECT 0.67 107.005 10.35 111.125 ;
    END
  END TSV_TM_88_1[23]
  PIN TSV_TM_88_1[24]
    DIRECTION OUTPUT ;
    USE SIGNAL ;
    PORT
      LAYER M1 ;
        RECT 11.79 112.565 21.47 116.685 ;
    END
  END TSV_TM_88_1[24]
  PIN TSV_TM_88_1[25]
    DIRECTION OUTPUT ;
    USE SIGNAL ;
    PORT
      LAYER M1 ;
        RECT 0.67 112.565 10.35 116.685 ;
    END
  END TSV_TM_88_1[25]
  PIN TSV_TM_88_1[26]
    DIRECTION OUTPUT ;
    USE SIGNAL ;
    PORT
      LAYER M1 ;
        RECT 11.79 118.125 21.47 122.245 ;
    END
  END TSV_TM_88_1[26]
  PIN TSV_TM_88_1[27]
    DIRECTION OUTPUT ;
    USE SIGNAL ;
    PORT
      LAYER M1 ;
        RECT 0.67 118.125 10.35 122.245 ;
    END
  END TSV_TM_88_1[27]
  PIN TSV_TM_88_1[28]
    DIRECTION OUTPUT ;
    USE SIGNAL ;
    PORT
      LAYER M1 ;
        RECT 11.79 123.685 21.47 127.805 ;
    END
  END TSV_TM_88_1[28]
  PIN TSV_TM_88_1[29]
    DIRECTION OUTPUT ;
    USE SIGNAL ;
    PORT
      LAYER M1 ;
        RECT 0.67 123.685 10.35 127.805 ;
    END
  END TSV_TM_88_1[29]
  PIN TSV_TM_88_1[2]
    DIRECTION OUTPUT ;
    USE SIGNAL ;
    PORT
      LAYER M1 ;
        RECT 11.79 51.405 21.47 55.525 ;
    END
  END TSV_TM_88_1[2]
  PIN TSV_TM_88_1[30]
    DIRECTION OUTPUT ;
    USE SIGNAL ;
    PORT
      LAYER M1 ;
        RECT 11.79 129.245 21.47 133.365 ;
    END
  END TSV_TM_88_1[30]
  PIN TSV_TM_88_1[31]
    DIRECTION OUTPUT ;
    USE SIGNAL ;
    PORT
      LAYER M1 ;
        RECT 0.67 129.245 10.35 133.365 ;
    END
  END TSV_TM_88_1[31]
  PIN TSV_TM_88_1[32]
    DIRECTION OUTPUT ;
    USE SIGNAL ;
    PORT
      LAYER M1 ;
        RECT 11.79 134.805 21.47 138.925 ;
    END
  END TSV_TM_88_1[32]
  PIN TSV_TM_88_1[33]
    DIRECTION OUTPUT ;
    USE SIGNAL ;
    PORT
      LAYER M1 ;
        RECT 0.67 134.805 10.35 138.925 ;
    END
  END TSV_TM_88_1[33]
  PIN TSV_TM_88_1[34]
    DIRECTION OUTPUT ;
    USE SIGNAL ;
    PORT
      LAYER M1 ;
        RECT 11.79 140.365 21.47 144.485 ;
    END
  END TSV_TM_88_1[34]
  PIN TSV_TM_88_1[35]
    DIRECTION OUTPUT ;
    USE SIGNAL ;
    PORT
      LAYER M1 ;
        RECT 0.67 140.365 10.35 144.485 ;
    END
  END TSV_TM_88_1[35]
  PIN TSV_TM_88_1[36]
    DIRECTION OUTPUT ;
    USE SIGNAL ;
    PORT
      LAYER M1 ;
        RECT 11.79 145.925 21.47 150.045 ;
    END
  END TSV_TM_88_1[36]
  PIN TSV_TM_88_1[37]
    DIRECTION OUTPUT ;
    USE SIGNAL ;
    PORT
      LAYER M1 ;
        RECT 0.67 145.925 10.35 150.045 ;
    END
  END TSV_TM_88_1[37]
  PIN TSV_TM_88_1[38]
    DIRECTION OUTPUT ;
    USE SIGNAL ;
    PORT
      LAYER M1 ;
        RECT 11.79 151.485 21.47 155.605 ;
    END
  END TSV_TM_88_1[38]
  PIN TSV_TM_88_1[39]
    DIRECTION OUTPUT ;
    USE SIGNAL ;
    PORT
      LAYER M1 ;
        RECT 0.67 151.485 10.35 155.605 ;
    END
  END TSV_TM_88_1[39]
  PIN TSV_TM_88_1[3]
    DIRECTION OUTPUT ;
    USE SIGNAL ;
    PORT
      LAYER M1 ;
        RECT 0.67 51.405 10.35 55.525 ;
    END
  END TSV_TM_88_1[3]
  PIN TSV_TM_88_1[40]
    DIRECTION OUTPUT ;
    USE SIGNAL ;
    PORT
      LAYER M1 ;
        RECT 11.79 157.045 21.47 161.165 ;
    END
  END TSV_TM_88_1[40]
  PIN TSV_TM_88_1[41]
    DIRECTION OUTPUT ;
    USE SIGNAL ;
    PORT
      LAYER M1 ;
        RECT 0.67 157.045 10.35 161.165 ;
    END
  END TSV_TM_88_1[41]
  PIN TSV_TM_88_1[42]
    DIRECTION OUTPUT ;
    USE SIGNAL ;
    PORT
      LAYER M1 ;
        RECT 11.79 162.605 21.47 166.725 ;
    END
  END TSV_TM_88_1[42]
  PIN TSV_TM_88_1[43]
    DIRECTION OUTPUT ;
    USE SIGNAL ;
    PORT
      LAYER M1 ;
        RECT 0.67 162.605 10.35 166.725 ;
    END
  END TSV_TM_88_1[43]
  PIN TSV_TM_88_1[44]
    DIRECTION OUTPUT ;
    USE SIGNAL ;
    PORT
      LAYER M1 ;
        RECT 11.79 168.165 21.47 172.285 ;
    END
  END TSV_TM_88_1[44]
  PIN TSV_TM_88_1[45]
    DIRECTION OUTPUT ;
    USE SIGNAL ;
    PORT
      LAYER M1 ;
        RECT 0.67 168.165 10.35 172.285 ;
    END
  END TSV_TM_88_1[45]
  PIN TSV_TM_88_1[46]
    DIRECTION OUTPUT ;
    USE SIGNAL ;
    PORT
      LAYER M1 ;
        RECT 11.79 173.725 21.47 177.845 ;
    END
  END TSV_TM_88_1[46]
  PIN TSV_TM_88_1[47]
    DIRECTION OUTPUT ;
    USE SIGNAL ;
    PORT
      LAYER M1 ;
        RECT 0.67 173.725 10.35 177.845 ;
    END
  END TSV_TM_88_1[47]
  PIN TSV_TM_88_1[48]
    DIRECTION OUTPUT ;
    USE SIGNAL ;
    PORT
      LAYER M1 ;
        RECT 11.79 179.285 21.47 183.405 ;
    END
  END TSV_TM_88_1[48]
  PIN TSV_TM_88_1[49]
    DIRECTION OUTPUT ;
    USE SIGNAL ;
    PORT
      LAYER M1 ;
        RECT 0.67 179.285 10.35 183.405 ;
    END
  END TSV_TM_88_1[49]
  PIN TSV_TM_88_1[4]
    DIRECTION OUTPUT ;
    USE SIGNAL ;
    PORT
      LAYER M1 ;
        RECT 11.79 56.965 21.47 61.085 ;
    END
  END TSV_TM_88_1[4]
  PIN TSV_TM_88_1[50]
    DIRECTION OUTPUT ;
    USE SIGNAL ;
    PORT
      LAYER M1 ;
        RECT 11.79 184.845 21.47 188.965 ;
    END
  END TSV_TM_88_1[50]
  PIN TSV_TM_88_1[51]
    DIRECTION OUTPUT ;
    USE SIGNAL ;
    PORT
      LAYER M1 ;
        RECT 0.67 184.845 10.35 188.965 ;
    END
  END TSV_TM_88_1[51]
  PIN TSV_TM_88_1[52]
    DIRECTION OUTPUT ;
    USE SIGNAL ;
    PORT
      LAYER M1 ;
        RECT 11.79 190.405 21.47 194.525 ;
    END
  END TSV_TM_88_1[52]
  PIN TSV_TM_88_1[53]
    DIRECTION OUTPUT ;
    USE SIGNAL ;
    PORT
      LAYER M1 ;
        RECT 0.67 190.405 10.35 194.525 ;
    END
  END TSV_TM_88_1[53]
  PIN TSV_TM_88_1[54]
    DIRECTION OUTPUT ;
    USE SIGNAL ;
    PORT
      LAYER M1 ;
        RECT 11.79 195.965 21.47 200.085 ;
    END
  END TSV_TM_88_1[54]
  PIN TSV_TM_88_1[55]
    DIRECTION OUTPUT ;
    USE SIGNAL ;
    PORT
      LAYER M1 ;
        RECT 0.67 195.965 10.35 200.085 ;
    END
  END TSV_TM_88_1[55]
  PIN TSV_TM_88_1[56]
    DIRECTION OUTPUT ;
    USE SIGNAL ;
    PORT
      LAYER M1 ;
        RECT 11.79 201.525 21.47 205.645 ;
    END
  END TSV_TM_88_1[56]
  PIN TSV_TM_88_1[57]
    DIRECTION OUTPUT ;
    USE SIGNAL ;
    PORT
      LAYER M1 ;
        RECT 0.67 201.525 10.35 205.645 ;
    END
  END TSV_TM_88_1[57]
  PIN TSV_TM_88_1[58]
    DIRECTION OUTPUT ;
    USE SIGNAL ;
    PORT
      LAYER M1 ;
        RECT 11.79 207.085 21.47 211.205 ;
    END
  END TSV_TM_88_1[58]
  PIN TSV_TM_88_1[59]
    DIRECTION OUTPUT ;
    USE SIGNAL ;
    PORT
      LAYER M1 ;
        RECT 0.67 207.085 10.35 211.205 ;
    END
  END TSV_TM_88_1[59]
  PIN TSV_TM_88_1[5]
    DIRECTION OUTPUT ;
    USE SIGNAL ;
    PORT
      LAYER M1 ;
        RECT 0.67 56.965 10.35 61.085 ;
    END
  END TSV_TM_88_1[5]
  PIN TSV_TM_88_1[60]
    DIRECTION OUTPUT ;
    USE SIGNAL ;
    PORT
      LAYER M1 ;
        RECT 11.79 212.645 21.47 216.765 ;
    END
  END TSV_TM_88_1[60]
  PIN TSV_TM_88_1[61]
    DIRECTION OUTPUT ;
    USE SIGNAL ;
    PORT
      LAYER M1 ;
        RECT 0.67 212.645 10.35 216.765 ;
    END
  END TSV_TM_88_1[61]
  PIN TSV_TM_88_1[62]
    DIRECTION OUTPUT ;
    USE SIGNAL ;
    PORT
      LAYER M1 ;
        RECT 11.79 218.205 21.47 222.325 ;
    END
  END TSV_TM_88_1[62]
  PIN TSV_TM_88_1[63]
    DIRECTION OUTPUT ;
    USE SIGNAL ;
    PORT
      LAYER M1 ;
        RECT 0.67 218.205 10.35 222.325 ;
    END
  END TSV_TM_88_1[63]
  PIN TSV_TM_88_1[64]
    DIRECTION OUTPUT ;
    USE SIGNAL ;
    PORT
      LAYER M1 ;
        RECT 11.79 223.765 21.47 227.885 ;
    END
  END TSV_TM_88_1[64]
  PIN TSV_TM_88_1[65]
    DIRECTION OUTPUT ;
    USE SIGNAL ;
    PORT
      LAYER M1 ;
        RECT 0.67 223.765 10.35 227.885 ;
    END
  END TSV_TM_88_1[65]
  PIN TSV_TM_88_1[66]
    DIRECTION OUTPUT ;
    USE SIGNAL ;
    PORT
      LAYER M1 ;
        RECT 11.79 229.325 21.47 233.445 ;
    END
  END TSV_TM_88_1[66]
  PIN TSV_TM_88_1[67]
    DIRECTION OUTPUT ;
    USE SIGNAL ;
    PORT
      LAYER M1 ;
        RECT 0.67 229.325 10.35 233.445 ;
    END
  END TSV_TM_88_1[67]
  PIN TSV_TM_88_1[68]
    DIRECTION OUTPUT ;
    USE SIGNAL ;
    PORT
      LAYER M1 ;
        RECT 11.79 234.885 21.47 239.005 ;
    END
  END TSV_TM_88_1[68]
  PIN TSV_TM_88_1[69]
    DIRECTION OUTPUT ;
    USE SIGNAL ;
    PORT
      LAYER M1 ;
        RECT 0.67 234.885 10.35 239.005 ;
    END
  END TSV_TM_88_1[69]
  PIN TSV_TM_88_1[6]
    DIRECTION OUTPUT ;
    USE SIGNAL ;
    PORT
      LAYER M1 ;
        RECT 11.79 62.525 21.47 66.645 ;
    END
  END TSV_TM_88_1[6]
  PIN TSV_TM_88_1[70]
    DIRECTION OUTPUT ;
    USE SIGNAL ;
    PORT
      LAYER M1 ;
        RECT 11.79 240.445 21.47 244.565 ;
    END
  END TSV_TM_88_1[70]
  PIN TSV_TM_88_1[71]
    DIRECTION OUTPUT ;
    USE SIGNAL ;
    PORT
      LAYER M1 ;
        RECT 0.67 240.445 10.35 244.565 ;
    END
  END TSV_TM_88_1[71]
  PIN TSV_TM_88_1[72]
    DIRECTION OUTPUT ;
    USE SIGNAL ;
    PORT
      LAYER M1 ;
        RECT 11.79 246.005 21.47 250.125 ;
    END
  END TSV_TM_88_1[72]
  PIN TSV_TM_88_1[73]
    DIRECTION OUTPUT ;
    USE SIGNAL ;
    PORT
      LAYER M1 ;
        RECT 0.67 246.005 10.35 250.125 ;
    END
  END TSV_TM_88_1[73]
  PIN TSV_TM_88_1[74]
    DIRECTION OUTPUT ;
    USE SIGNAL ;
    PORT
      LAYER M1 ;
        RECT 11.79 251.565 21.47 255.685 ;
    END
  END TSV_TM_88_1[74]
  PIN TSV_TM_88_1[75]
    DIRECTION OUTPUT ;
    USE SIGNAL ;
    PORT
      LAYER M1 ;
        RECT 0.67 251.565 10.35 255.685 ;
    END
  END TSV_TM_88_1[75]
  PIN TSV_TM_88_1[76]
    DIRECTION OUTPUT ;
    USE SIGNAL ;
    PORT
      LAYER M1 ;
        RECT 11.79 257.125 21.47 261.245 ;
    END
  END TSV_TM_88_1[76]
  PIN TSV_TM_88_1[77]
    DIRECTION OUTPUT ;
    USE SIGNAL ;
    PORT
      LAYER M1 ;
        RECT 0.67 257.125 10.35 261.245 ;
    END
  END TSV_TM_88_1[77]
  PIN TSV_TM_88_1[78]
    DIRECTION OUTPUT ;
    USE SIGNAL ;
    PORT
      LAYER M1 ;
        RECT 11.79 262.685 21.47 266.805 ;
    END
  END TSV_TM_88_1[78]
  PIN TSV_TM_88_1[79]
    DIRECTION OUTPUT ;
    USE SIGNAL ;
    PORT
      LAYER M1 ;
        RECT 0.67 262.685 10.35 266.805 ;
    END
  END TSV_TM_88_1[79]
  PIN TSV_TM_88_1[7]
    DIRECTION OUTPUT ;
    USE SIGNAL ;
    PORT
      LAYER M1 ;
        RECT 0.67 62.525 10.35 66.645 ;
    END
  END TSV_TM_88_1[7]
  PIN TSV_TM_88_1[80]
    DIRECTION OUTPUT ;
    USE SIGNAL ;
    PORT
      LAYER M1 ;
        RECT 11.79 268.245 21.47 272.365 ;
    END
  END TSV_TM_88_1[80]
  PIN TSV_TM_88_1[81]
    DIRECTION OUTPUT ;
    USE SIGNAL ;
    PORT
      LAYER M1 ;
        RECT 0.67 268.245 10.35 272.365 ;
    END
  END TSV_TM_88_1[81]
  PIN TSV_TM_88_1[82]
    DIRECTION OUTPUT ;
    USE SIGNAL ;
    PORT
      LAYER M1 ;
        RECT 11.79 273.805 21.47 277.925 ;
    END
  END TSV_TM_88_1[82]
  PIN TSV_TM_88_1[83]
    DIRECTION OUTPUT ;
    USE SIGNAL ;
    PORT
      LAYER M1 ;
        RECT 0.67 273.805 10.35 277.925 ;
    END
  END TSV_TM_88_1[83]
  PIN TSV_TM_88_1[84]
    DIRECTION OUTPUT ;
    USE SIGNAL ;
    PORT
      LAYER M1 ;
        RECT 11.79 279.365 21.47 283.485 ;
    END
  END TSV_TM_88_1[84]
  PIN TSV_TM_88_1[85]
    DIRECTION OUTPUT ;
    USE SIGNAL ;
    PORT
      LAYER M1 ;
        RECT 0.67 279.365 10.35 283.485 ;
    END
  END TSV_TM_88_1[85]
  PIN TSV_TM_88_1[86]
    DIRECTION OUTPUT ;
    USE SIGNAL ;
    PORT
      LAYER M1 ;
        RECT 11.79 284.925 21.47 289.045 ;
    END
  END TSV_TM_88_1[86]
  PIN TSV_TM_88_1[87]
    DIRECTION OUTPUT ;
    USE SIGNAL ;
    PORT
      LAYER M1 ;
        RECT 0.67 284.925 10.35 289.045 ;
    END
  END TSV_TM_88_1[87]
  PIN TSV_TM_88_1[8]
    DIRECTION OUTPUT ;
    USE SIGNAL ;
    PORT
      LAYER M1 ;
        RECT 11.79 68.085 21.47 72.205 ;
    END
  END TSV_TM_88_1[8]
  PIN TSV_TM_88_1[9]
    DIRECTION OUTPUT ;
    USE SIGNAL ;
    PORT
      LAYER M1 ;
        RECT 0.67 68.085 10.35 72.205 ;
    END
  END TSV_TM_88_1[9]
  PIN VMON
    DIRECTION INOUT ;
    USE SIGNAL ;
    PORT
      LAYER M1 ;
        RECT 70.7 23.605 80.38 27.725 ;
    END
  END VMON
  PIN D1_DUMP_READY_ASIC
    DIRECTION OUTPUT ;
    USE SIGNAL ;
    PORT
      LAYER M4 ;
        RECT 90.8 6.495 92.2 6.595 ;
        RECT 87.505 6.455 90.9 6.555 ;
    END
  END D1_DUMP_READY_ASIC
  PIN D1_OSC_TM_RES_ASIC[0]
    DIRECTION OUTPUT ;
    USE SIGNAL ;
    PORT
      LAYER M4 ;
        RECT 91.4 17.495 92.2 17.595 ;
        RECT 87.505 17.575 91.5 17.675 ;
    END
  END D1_OSC_TM_RES_ASIC[0]
  PIN D1_OSC_TM_RES_ASIC[1]
    DIRECTION OUTPUT ;
    USE SIGNAL ;
    PORT
      LAYER M4 ;
        RECT 91.4 11.895 92.2 11.995 ;
        RECT 87.505 12.015 91.5 12.115 ;
        RECT 91.4 11.895 91.5 12.115 ;
    END
  END D1_OSC_TM_RES_ASIC[1]
  PIN D1_SPINE_RESET_N_ASIC
    DIRECTION INPUT ;
    USE SIGNAL ;
    PORT
      LAYER M4 ;
        RECT 87.505 28.695 92.2 28.795 ;
    END
  END D1_SPINE_RESET_N_ASIC
  PIN D1_STOPWATCH_PERIOD_ASIC
    DIRECTION INPUT ;
    USE SIGNAL ;
    PORT
      LAYER M4 ;
        RECT 90.665 39.895 92.2 39.995 ;
        RECT 87.505 39.815 90.765 39.915 ;
    END
  END D1_STOPWATCH_PERIOD_ASIC
  PIN D1_STOPWATCH_RINGO_ASIC
    DIRECTION OUTPUT ;
    USE SIGNAL ;
    PORT
      LAYER M4 ;
        RECT 87.505 0.895 92.2 0.995 ;
    END
  END D1_STOPWATCH_RINGO_ASIC
  PIN D1_TM_REDUMP_ASIC
    DIRECTION INPUT ;
    USE SIGNAL ;
    PORT
      LAYER M4 ;
        RECT 90.665 34.295 92.2 34.395 ;
        RECT 87.505 34.255 90.765 34.355 ;
    END
  END D1_TM_REDUMP_ASIC
  PIN D2_DUMP_READY_ASIC
    DIRECTION OUTPUT ;
    USE SIGNAL ;
    PORT
      LAYER M4 ;
        RECT 90.8 11.295 92.2 11.395 ;
        RECT 87.505 11.415 90.9 11.515 ;
        RECT 90.8 11.295 90.9 11.515 ;
    END
  END D2_DUMP_READY_ASIC
  PIN D2_OSC_TM_RES_ASIC[0]
    DIRECTION OUTPUT ;
    USE SIGNAL ;
    PORT
      LAYER M4 ;
        RECT 90.825 22.495 92.2 22.595 ;
        RECT 87.505 22.535 90.925 22.635 ;
    END
  END D2_OSC_TM_RES_ASIC[0]
  PIN D2_OSC_TM_RES_ASIC[1]
    DIRECTION OUTPUT ;
    USE SIGNAL ;
    PORT
      LAYER M4 ;
        RECT 90.8 16.895 92.2 16.995 ;
        RECT 87.505 16.975 90.9 17.075 ;
    END
  END D2_OSC_TM_RES_ASIC[1]
  PIN D2_SPINE_RESET_N_ASIC
    DIRECTION INPUT ;
    USE SIGNAL ;
    PORT
      LAYER M4 ;
        RECT 91.265 33.695 92.2 33.795 ;
        RECT 87.505 33.655 91.365 33.755 ;
    END
  END D2_SPINE_RESET_N_ASIC
  PIN D2_STOPWATCH_PERIOD_ASIC
    DIRECTION INPUT ;
    USE SIGNAL ;
    PORT
      LAYER M4 ;
        RECT 90.665 44.695 92.2 44.795 ;
        RECT 87.505 44.775 90.765 44.875 ;
    END
  END D2_STOPWATCH_PERIOD_ASIC
  PIN D2_STOPWATCH_RINGO_ASIC
    DIRECTION OUTPUT ;
    USE SIGNAL ;
    PORT
      LAYER M4 ;
        RECT 91.4 5.895 92.2 5.995 ;
        RECT 87.505 5.855 91.5 5.955 ;
    END
  END D2_STOPWATCH_RINGO_ASIC
  PIN D2_TM_REDUMP_ASIC
    DIRECTION INPUT ;
    USE SIGNAL ;
    PORT
      LAYER M4 ;
        RECT 91.265 39.295 92.2 39.395 ;
        RECT 87.505 39.215 91.365 39.315 ;
    END
  END D2_TM_REDUMP_ASIC
  PIN D3_DUMP_READY_ASIC
    DIRECTION OUTPUT ;
    USE SIGNAL ;
    PORT
      LAYER M4 ;
        RECT 91 11.495 92.2 11.595 ;
        RECT 87.505 11.615 91.1 11.715 ;
        RECT 91 11.495 91.1 11.715 ;
    END
  END D3_DUMP_READY_ASIC
  PIN D3_OSC_TM_RES_ASIC[0]
    DIRECTION OUTPUT ;
    USE SIGNAL ;
    PORT
      LAYER M4 ;
        RECT 91.025 22.695 92.2 22.795 ;
        RECT 87.505 22.735 91.125 22.835 ;
    END
  END D3_OSC_TM_RES_ASIC[0]
  PIN D3_OSC_TM_RES_ASIC[1]
    DIRECTION OUTPUT ;
    USE SIGNAL ;
    PORT
      LAYER M4 ;
        RECT 91 17.095 92.2 17.195 ;
        RECT 87.505 17.175 91.1 17.275 ;
    END
  END D3_OSC_TM_RES_ASIC[1]
  PIN D3_SPINE_RESET_N_ASIC
    DIRECTION INPUT ;
    USE SIGNAL ;
    PORT
      LAYER M4 ;
        RECT 91.065 33.895 92.2 33.995 ;
        RECT 87.505 33.855 91.165 33.955 ;
    END
  END D3_SPINE_RESET_N_ASIC
  PIN D3_STOPWATCH_PERIOD_ASIC
    DIRECTION INPUT ;
    USE SIGNAL ;
    PORT
      LAYER M4 ;
        RECT 90.865 44.895 92.2 44.995 ;
        RECT 87.505 44.975 90.965 45.075 ;
    END
  END D3_STOPWATCH_PERIOD_ASIC
  PIN D3_STOPWATCH_RINGO_ASIC
    DIRECTION OUTPUT ;
    USE SIGNAL ;
    PORT
      LAYER M4 ;
        RECT 91.2 6.095 92.2 6.195 ;
        RECT 87.505 6.055 91.3 6.155 ;
    END
  END D3_STOPWATCH_RINGO_ASIC
  PIN D3_TM_REDUMP_ASIC
    DIRECTION INPUT ;
    USE SIGNAL ;
    PORT
      LAYER M4 ;
        RECT 91.065 39.495 92.2 39.595 ;
        RECT 87.505 39.415 91.165 39.515 ;
    END
  END D3_TM_REDUMP_ASIC
  PIN DUMP_READY_ASIC
    DIRECTION OUTPUT ;
    USE SIGNAL ;
    PORT
      LAYER M4 ;
        RECT 91 6.295 92.2 6.395 ;
        RECT 87.505 6.255 91.1 6.355 ;
    END
  END DUMP_READY_ASIC
  PIN OSC_TM_RES_ASIC[0]
    DIRECTION OUTPUT ;
    USE SIGNAL ;
    PORT
      LAYER M4 ;
        RECT 91.2 17.295 92.2 17.395 ;
        RECT 87.505 17.375 91.3 17.475 ;
    END
  END OSC_TM_RES_ASIC[0]
  PIN OSC_TM_RES_ASIC[1]
    DIRECTION OUTPUT ;
    USE SIGNAL ;
    PORT
      LAYER M4 ;
        RECT 91.2 11.695 92.2 11.795 ;
        RECT 87.505 11.815 91.3 11.915 ;
        RECT 91.2 11.695 91.3 11.915 ;
    END
  END OSC_TM_RES_ASIC[1]
  PIN SPINE_RESET_N_ASIC
    DIRECTION INPUT ;
    USE SIGNAL ;
    PORT
      LAYER M4 ;
        RECT 87.505 28.495 92.2 28.595 ;
    END
  END SPINE_RESET_N_ASIC
  PIN STOPWATCH_PERIOD_ASIC
    DIRECTION INPUT ;
    USE SIGNAL ;
    PORT
      LAYER M4 ;
        RECT 90.865 39.695 92.2 39.795 ;
        RECT 87.505 39.615 90.965 39.715 ;
    END
  END STOPWATCH_PERIOD_ASIC
  PIN STOPWATCH_RINGO_ASIC
    DIRECTION OUTPUT ;
    USE SIGNAL ;
    PORT
      LAYER M4 ;
        RECT 87.505 0.695 92.2 0.795 ;
    END
  END STOPWATCH_RINGO_ASIC
  PIN TM_REDUMP_ASIC
    DIRECTION INPUT ;
    USE SIGNAL ;
    PORT
      LAYER M4 ;
        RECT 90.865 34.095 92.2 34.195 ;
        RECT 87.505 34.055 90.965 34.155 ;
    END
  END TM_REDUMP_ASIC
  PIN TSV_TM_332_205_ASIC[0]
    DIRECTION INPUT ;
    USE SIGNAL ;
    PORT
      LAYER M4 ;
        RECT 91.065 45.095 92.2 45.195 ;
        RECT 87.505 45.175 91.165 45.275 ;
    END
  END TSV_TM_332_205_ASIC[0]
  PIN TSV_TM_332_205_ASIC[100]
    DIRECTION INPUT ;
    USE SIGNAL ;
    PORT
      LAYER M4 ;
        RECT 91.065 323.095 92.2 323.195 ;
        RECT 87.505 323.175 91.165 323.275 ;
    END
  END TSV_TM_332_205_ASIC[100]
  PIN TSV_TM_332_205_ASIC[101]
    DIRECTION INPUT ;
    USE SIGNAL ;
    PORT
      LAYER M4 ;
        RECT 91.265 323.295 92.2 323.395 ;
        RECT 87.505 323.375 91.365 323.475 ;
    END
  END TSV_TM_332_205_ASIC[101]
  PIN TSV_TM_332_205_ASIC[102]
    DIRECTION INPUT ;
    USE SIGNAL ;
    PORT
      LAYER M4 ;
        RECT 91.065 328.695 92.2 328.795 ;
        RECT 87.505 328.735 91.165 328.835 ;
    END
  END TSV_TM_332_205_ASIC[102]
  PIN TSV_TM_332_205_ASIC[103]
    DIRECTION INPUT ;
    USE SIGNAL ;
    PORT
      LAYER M4 ;
        RECT 91.265 328.895 92.2 328.995 ;
        RECT 87.505 328.935 91.365 329.035 ;
    END
  END TSV_TM_332_205_ASIC[103]
  PIN TSV_TM_332_205_ASIC[104]
    DIRECTION INPUT ;
    USE SIGNAL ;
    PORT
      LAYER M4 ;
        RECT 87.505 334.295 92.2 334.395 ;
    END
  END TSV_TM_332_205_ASIC[104]
  PIN TSV_TM_332_205_ASIC[105]
    DIRECTION INPUT ;
    USE SIGNAL ;
    PORT
      LAYER M4 ;
        RECT 87.505 334.495 92.2 334.595 ;
    END
  END TSV_TM_332_205_ASIC[105]
  PIN TSV_TM_332_205_ASIC[106]
    DIRECTION INPUT ;
    USE SIGNAL ;
    PORT
      LAYER M4 ;
        RECT 90.865 339.895 92.2 339.995 ;
        RECT 87.505 339.855 90.965 339.955 ;
    END
  END TSV_TM_332_205_ASIC[106]
  PIN TSV_TM_332_205_ASIC[107]
    DIRECTION INPUT ;
    USE SIGNAL ;
    PORT
      LAYER M4 ;
        RECT 90.665 340.095 92.2 340.195 ;
        RECT 87.505 340.055 90.765 340.155 ;
    END
  END TSV_TM_332_205_ASIC[107]
  PIN TSV_TM_332_205_ASIC[108]
    DIRECTION INPUT ;
    USE SIGNAL ;
    PORT
      LAYER M4 ;
        RECT 91.065 345.295 92.2 345.395 ;
        RECT 87.505 345.215 91.165 345.315 ;
    END
  END TSV_TM_332_205_ASIC[108]
  PIN TSV_TM_332_205_ASIC[109]
    DIRECTION INPUT ;
    USE SIGNAL ;
    PORT
      LAYER M4 ;
        RECT 91.265 345.095 92.2 345.195 ;
        RECT 87.505 345.015 91.365 345.115 ;
    END
  END TSV_TM_332_205_ASIC[109]
  PIN TSV_TM_332_205_ASIC[10]
    DIRECTION INPUT ;
    USE SIGNAL ;
    PORT
      LAYER M4 ;
        RECT 91.065 72.895 92.2 72.995 ;
        RECT 87.505 72.975 91.165 73.075 ;
    END
  END TSV_TM_332_205_ASIC[10]
  PIN TSV_TM_332_205_ASIC[110]
    DIRECTION INPUT ;
    USE SIGNAL ;
    PORT
      LAYER M4 ;
        RECT 91.065 339.695 92.2 339.795 ;
        RECT 87.505 339.655 91.165 339.755 ;
    END
  END TSV_TM_332_205_ASIC[110]
  PIN TSV_TM_332_205_ASIC[111]
    DIRECTION INPUT ;
    USE SIGNAL ;
    PORT
      LAYER M4 ;
        RECT 91.265 339.495 92.2 339.595 ;
        RECT 87.505 339.455 91.365 339.555 ;
    END
  END TSV_TM_332_205_ASIC[111]
  PIN TSV_TM_332_205_ASIC[112]
    DIRECTION INPUT ;
    USE SIGNAL ;
    PORT
      LAYER M4 ;
        RECT 87.505 334.095 92.2 334.195 ;
    END
  END TSV_TM_332_205_ASIC[112]
  PIN TSV_TM_332_205_ASIC[113]
    DIRECTION INPUT ;
    USE SIGNAL ;
    PORT
      LAYER M4 ;
        RECT 87.505 333.895 92.2 333.995 ;
    END
  END TSV_TM_332_205_ASIC[113]
  PIN TSV_TM_332_205_ASIC[114]
    DIRECTION INPUT ;
    USE SIGNAL ;
    PORT
      LAYER M4 ;
        RECT 90.865 328.495 92.2 328.595 ;
        RECT 87.505 328.535 90.965 328.635 ;
    END
  END TSV_TM_332_205_ASIC[114]
  PIN TSV_TM_332_205_ASIC[115]
    DIRECTION INPUT ;
    USE SIGNAL ;
    PORT
      LAYER M4 ;
        RECT 90.665 328.295 92.2 328.395 ;
        RECT 87.505 328.335 90.765 328.435 ;
    END
  END TSV_TM_332_205_ASIC[115]
  PIN TSV_TM_332_205_ASIC[116]
    DIRECTION INPUT ;
    USE SIGNAL ;
    PORT
      LAYER M4 ;
        RECT 90.865 322.895 92.2 322.995 ;
        RECT 87.505 322.975 90.965 323.075 ;
    END
  END TSV_TM_332_205_ASIC[116]
  PIN TSV_TM_332_205_ASIC[117]
    DIRECTION INPUT ;
    USE SIGNAL ;
    PORT
      LAYER M4 ;
        RECT 90.665 322.695 92.2 322.795 ;
        RECT 87.505 322.775 90.765 322.875 ;
    END
  END TSV_TM_332_205_ASIC[117]
  PIN TSV_TM_332_205_ASIC[118]
    DIRECTION INPUT ;
    USE SIGNAL ;
    PORT
      LAYER M4 ;
        RECT 91.065 317.495 92.2 317.595 ;
        RECT 87.505 317.415 91.165 317.515 ;
    END
  END TSV_TM_332_205_ASIC[118]
  PIN TSV_TM_332_205_ASIC[119]
    DIRECTION INPUT ;
    USE SIGNAL ;
    PORT
      LAYER M4 ;
        RECT 91.265 317.295 92.2 317.395 ;
        RECT 87.505 317.215 91.365 317.315 ;
    END
  END TSV_TM_332_205_ASIC[119]
  PIN TSV_TM_332_205_ASIC[11]
    DIRECTION INPUT ;
    USE SIGNAL ;
    PORT
      LAYER M4 ;
        RECT 91.265 73.095 92.2 73.195 ;
        RECT 87.505 73.175 91.365 73.275 ;
    END
  END TSV_TM_332_205_ASIC[11]
  PIN TSV_TM_332_205_ASIC[120]
    DIRECTION INPUT ;
    USE SIGNAL ;
    PORT
      LAYER M4 ;
        RECT 91.065 311.895 92.2 311.995 ;
        RECT 87.505 311.855 91.165 311.955 ;
    END
  END TSV_TM_332_205_ASIC[120]
  PIN TSV_TM_332_205_ASIC[121]
    DIRECTION INPUT ;
    USE SIGNAL ;
    PORT
      LAYER M4 ;
        RECT 91.265 311.695 92.2 311.795 ;
        RECT 87.505 311.655 91.365 311.755 ;
    END
  END TSV_TM_332_205_ASIC[121]
  PIN TSV_TM_332_205_ASIC[122]
    DIRECTION INPUT ;
    USE SIGNAL ;
    PORT
      LAYER M4 ;
        RECT 87.505 306.295 92.2 306.395 ;
    END
  END TSV_TM_332_205_ASIC[122]
  PIN TSV_TM_332_205_ASIC[123]
    DIRECTION INPUT ;
    USE SIGNAL ;
    PORT
      LAYER M4 ;
        RECT 87.505 306.095 92.2 306.195 ;
    END
  END TSV_TM_332_205_ASIC[123]
  PIN TSV_TM_332_205_ASIC[124]
    DIRECTION INPUT ;
    USE SIGNAL ;
    PORT
      LAYER M4 ;
        RECT 90.865 300.695 92.2 300.795 ;
        RECT 87.505 300.735 90.965 300.835 ;
    END
  END TSV_TM_332_205_ASIC[124]
  PIN TSV_TM_332_205_ASIC[125]
    DIRECTION INPUT ;
    USE SIGNAL ;
    PORT
      LAYER M4 ;
        RECT 90.665 300.495 92.2 300.595 ;
        RECT 87.505 300.535 90.765 300.635 ;
    END
  END TSV_TM_332_205_ASIC[125]
  PIN TSV_TM_332_205_ASIC[126]
    DIRECTION INPUT ;
    USE SIGNAL ;
    PORT
      LAYER M4 ;
        RECT 90.865 295.095 92.2 295.195 ;
        RECT 87.505 295.175 90.965 295.275 ;
    END
  END TSV_TM_332_205_ASIC[126]
  PIN TSV_TM_332_205_ASIC[127]
    DIRECTION INPUT ;
    USE SIGNAL ;
    PORT
      LAYER M4 ;
        RECT 90.665 294.895 92.2 294.995 ;
        RECT 87.505 294.975 90.765 295.075 ;
    END
  END TSV_TM_332_205_ASIC[127]
  PIN TSV_TM_332_205_ASIC[12]
    DIRECTION INPUT ;
    USE SIGNAL ;
    PORT
      LAYER M4 ;
        RECT 91.065 78.495 92.2 78.595 ;
        RECT 87.505 78.535 91.165 78.635 ;
    END
  END TSV_TM_332_205_ASIC[12]
  PIN TSV_TM_332_205_ASIC[13]
    DIRECTION INPUT ;
    USE SIGNAL ;
    PORT
      LAYER M4 ;
        RECT 91.265 78.695 92.2 78.795 ;
        RECT 87.505 78.735 91.365 78.835 ;
    END
  END TSV_TM_332_205_ASIC[13]
  PIN TSV_TM_332_205_ASIC[14]
    DIRECTION INPUT ;
    USE SIGNAL ;
    PORT
      LAYER M4 ;
        RECT 87.505 84.095 92.2 84.195 ;
    END
  END TSV_TM_332_205_ASIC[14]
  PIN TSV_TM_332_205_ASIC[15]
    DIRECTION INPUT ;
    USE SIGNAL ;
    PORT
      LAYER M4 ;
        RECT 87.505 84.295 92.2 84.395 ;
    END
  END TSV_TM_332_205_ASIC[15]
  PIN TSV_TM_332_205_ASIC[16]
    DIRECTION INPUT ;
    USE SIGNAL ;
    PORT
      LAYER M4 ;
        RECT 90.865 89.695 92.2 89.795 ;
        RECT 87.505 89.655 90.965 89.755 ;
    END
  END TSV_TM_332_205_ASIC[16]
  PIN TSV_TM_332_205_ASIC[17]
    DIRECTION INPUT ;
    USE SIGNAL ;
    PORT
      LAYER M4 ;
        RECT 90.665 89.895 92.2 89.995 ;
        RECT 87.505 89.855 90.765 89.955 ;
    END
  END TSV_TM_332_205_ASIC[17]
  PIN TSV_TM_332_205_ASIC[18]
    DIRECTION INPUT ;
    USE SIGNAL ;
    PORT
      LAYER M4 ;
        RECT 90.865 95.295 92.2 95.395 ;
        RECT 87.505 95.215 90.965 95.315 ;
    END
  END TSV_TM_332_205_ASIC[18]
  PIN TSV_TM_332_205_ASIC[19]
    DIRECTION INPUT ;
    USE SIGNAL ;
    PORT
      LAYER M4 ;
        RECT 90.665 95.495 92.2 95.595 ;
        RECT 87.505 95.415 90.765 95.515 ;
    END
  END TSV_TM_332_205_ASIC[19]
  PIN TSV_TM_332_205_ASIC[1]
    DIRECTION INPUT ;
    USE SIGNAL ;
    PORT
      LAYER M4 ;
        RECT 91.265 45.295 92.2 45.395 ;
        RECT 87.505 45.375 91.365 45.475 ;
    END
  END TSV_TM_332_205_ASIC[1]
  PIN TSV_TM_332_205_ASIC[20]
    DIRECTION INPUT ;
    USE SIGNAL ;
    PORT
      LAYER M4 ;
        RECT 91.065 100.695 92.2 100.795 ;
        RECT 87.505 100.775 91.165 100.875 ;
    END
  END TSV_TM_332_205_ASIC[20]
  PIN TSV_TM_332_205_ASIC[21]
    DIRECTION INPUT ;
    USE SIGNAL ;
    PORT
      LAYER M4 ;
        RECT 91.265 100.895 92.2 100.995 ;
        RECT 87.505 100.975 91.365 101.075 ;
    END
  END TSV_TM_332_205_ASIC[21]
  PIN TSV_TM_332_205_ASIC[22]
    DIRECTION INPUT ;
    USE SIGNAL ;
    PORT
      LAYER M4 ;
        RECT 91.065 106.295 92.2 106.395 ;
        RECT 87.505 106.335 91.165 106.435 ;
    END
  END TSV_TM_332_205_ASIC[22]
  PIN TSV_TM_332_205_ASIC[23]
    DIRECTION INPUT ;
    USE SIGNAL ;
    PORT
      LAYER M4 ;
        RECT 91.265 106.495 92.2 106.595 ;
        RECT 87.505 106.535 91.365 106.635 ;
    END
  END TSV_TM_332_205_ASIC[23]
  PIN TSV_TM_332_205_ASIC[24]
    DIRECTION INPUT ;
    USE SIGNAL ;
    PORT
      LAYER M4 ;
        RECT 87.505 111.895 92.2 111.995 ;
    END
  END TSV_TM_332_205_ASIC[24]
  PIN TSV_TM_332_205_ASIC[25]
    DIRECTION INPUT ;
    USE SIGNAL ;
    PORT
      LAYER M4 ;
        RECT 87.505 112.095 92.2 112.195 ;
    END
  END TSV_TM_332_205_ASIC[25]
  PIN TSV_TM_332_205_ASIC[26]
    DIRECTION INPUT ;
    USE SIGNAL ;
    PORT
      LAYER M4 ;
        RECT 90.865 117.495 92.2 117.595 ;
        RECT 87.505 117.455 90.965 117.555 ;
    END
  END TSV_TM_332_205_ASIC[26]
  PIN TSV_TM_332_205_ASIC[27]
    DIRECTION INPUT ;
    USE SIGNAL ;
    PORT
      LAYER M4 ;
        RECT 90.665 117.695 92.2 117.795 ;
        RECT 87.505 117.655 90.765 117.755 ;
    END
  END TSV_TM_332_205_ASIC[27]
  PIN TSV_TM_332_205_ASIC[28]
    DIRECTION INPUT ;
    USE SIGNAL ;
    PORT
      LAYER M4 ;
        RECT 90.865 123.095 92.2 123.195 ;
        RECT 87.505 123.015 90.965 123.115 ;
    END
  END TSV_TM_332_205_ASIC[28]
  PIN TSV_TM_332_205_ASIC[29]
    DIRECTION INPUT ;
    USE SIGNAL ;
    PORT
      LAYER M4 ;
        RECT 90.665 123.295 92.2 123.395 ;
        RECT 87.505 123.215 90.765 123.315 ;
    END
  END TSV_TM_332_205_ASIC[29]
  PIN TSV_TM_332_205_ASIC[2]
    DIRECTION INPUT ;
    USE SIGNAL ;
    PORT
      LAYER M4 ;
        RECT 91.065 50.695 92.2 50.795 ;
        RECT 87.505 50.735 91.165 50.835 ;
    END
  END TSV_TM_332_205_ASIC[2]
  PIN TSV_TM_332_205_ASIC[30]
    DIRECTION INPUT ;
    USE SIGNAL ;
    PORT
      LAYER M4 ;
        RECT 91.065 128.495 92.2 128.595 ;
        RECT 87.505 128.575 91.165 128.675 ;
    END
  END TSV_TM_332_205_ASIC[30]
  PIN TSV_TM_332_205_ASIC[31]
    DIRECTION INPUT ;
    USE SIGNAL ;
    PORT
      LAYER M4 ;
        RECT 91.265 128.695 92.2 128.795 ;
        RECT 87.505 128.775 91.365 128.875 ;
    END
  END TSV_TM_332_205_ASIC[31]
  PIN TSV_TM_332_205_ASIC[32]
    DIRECTION INPUT ;
    USE SIGNAL ;
    PORT
      LAYER M4 ;
        RECT 91.065 134.095 92.2 134.195 ;
        RECT 87.505 134.135 91.165 134.235 ;
    END
  END TSV_TM_332_205_ASIC[32]
  PIN TSV_TM_332_205_ASIC[33]
    DIRECTION INPUT ;
    USE SIGNAL ;
    PORT
      LAYER M4 ;
        RECT 91.265 134.295 92.2 134.395 ;
        RECT 87.505 134.335 91.365 134.435 ;
    END
  END TSV_TM_332_205_ASIC[33]
  PIN TSV_TM_332_205_ASIC[34]
    DIRECTION INPUT ;
    USE SIGNAL ;
    PORT
      LAYER M4 ;
        RECT 87.505 139.695 92.2 139.795 ;
    END
  END TSV_TM_332_205_ASIC[34]
  PIN TSV_TM_332_205_ASIC[35]
    DIRECTION INPUT ;
    USE SIGNAL ;
    PORT
      LAYER M4 ;
        RECT 87.505 139.895 92.2 139.995 ;
    END
  END TSV_TM_332_205_ASIC[35]
  PIN TSV_TM_332_205_ASIC[36]
    DIRECTION INPUT ;
    USE SIGNAL ;
    PORT
      LAYER M4 ;
        RECT 90.865 145.295 92.2 145.395 ;
        RECT 87.505 145.255 90.965 145.355 ;
    END
  END TSV_TM_332_205_ASIC[36]
  PIN TSV_TM_332_205_ASIC[37]
    DIRECTION INPUT ;
    USE SIGNAL ;
    PORT
      LAYER M4 ;
        RECT 90.665 145.495 92.2 145.595 ;
        RECT 87.505 145.455 90.765 145.555 ;
    END
  END TSV_TM_332_205_ASIC[37]
  PIN TSV_TM_332_205_ASIC[38]
    DIRECTION INPUT ;
    USE SIGNAL ;
    PORT
      LAYER M4 ;
        RECT 90.865 150.895 92.2 150.995 ;
        RECT 87.505 150.815 90.965 150.915 ;
    END
  END TSV_TM_332_205_ASIC[38]
  PIN TSV_TM_332_205_ASIC[39]
    DIRECTION INPUT ;
    USE SIGNAL ;
    PORT
      LAYER M4 ;
        RECT 90.665 151.095 92.2 151.195 ;
        RECT 87.505 151.015 90.765 151.115 ;
    END
  END TSV_TM_332_205_ASIC[39]
  PIN TSV_TM_332_205_ASIC[3]
    DIRECTION INPUT ;
    USE SIGNAL ;
    PORT
      LAYER M4 ;
        RECT 91.265 50.895 92.2 50.995 ;
        RECT 87.505 50.935 91.365 51.035 ;
    END
  END TSV_TM_332_205_ASIC[3]
  PIN TSV_TM_332_205_ASIC[40]
    DIRECTION INPUT ;
    USE SIGNAL ;
    PORT
      LAYER M4 ;
        RECT 91.065 156.295 92.2 156.395 ;
        RECT 87.505 156.375 91.165 156.475 ;
    END
  END TSV_TM_332_205_ASIC[40]
  PIN TSV_TM_332_205_ASIC[41]
    DIRECTION INPUT ;
    USE SIGNAL ;
    PORT
      LAYER M4 ;
        RECT 91.265 156.495 92.2 156.595 ;
        RECT 87.505 156.575 91.365 156.675 ;
    END
  END TSV_TM_332_205_ASIC[41]
  PIN TSV_TM_332_205_ASIC[42]
    DIRECTION INPUT ;
    USE SIGNAL ;
    PORT
      LAYER M4 ;
        RECT 91.065 161.895 92.2 161.995 ;
        RECT 87.505 161.935 91.165 162.035 ;
    END
  END TSV_TM_332_205_ASIC[42]
  PIN TSV_TM_332_205_ASIC[43]
    DIRECTION INPUT ;
    USE SIGNAL ;
    PORT
      LAYER M4 ;
        RECT 91.265 162.095 92.2 162.195 ;
        RECT 87.505 162.135 91.365 162.235 ;
    END
  END TSV_TM_332_205_ASIC[43]
  PIN TSV_TM_332_205_ASIC[44]
    DIRECTION INPUT ;
    USE SIGNAL ;
    PORT
      LAYER M4 ;
        RECT 87.505 167.495 92.2 167.595 ;
    END
  END TSV_TM_332_205_ASIC[44]
  PIN TSV_TM_332_205_ASIC[45]
    DIRECTION INPUT ;
    USE SIGNAL ;
    PORT
      LAYER M4 ;
        RECT 87.505 167.695 92.2 167.795 ;
    END
  END TSV_TM_332_205_ASIC[45]
  PIN TSV_TM_332_205_ASIC[46]
    DIRECTION INPUT ;
    USE SIGNAL ;
    PORT
      LAYER M4 ;
        RECT 90.865 173.095 92.2 173.195 ;
        RECT 87.505 173.055 90.965 173.155 ;
    END
  END TSV_TM_332_205_ASIC[46]
  PIN TSV_TM_332_205_ASIC[47]
    DIRECTION INPUT ;
    USE SIGNAL ;
    PORT
      LAYER M4 ;
        RECT 90.665 173.295 92.2 173.395 ;
        RECT 87.505 173.255 90.765 173.355 ;
    END
  END TSV_TM_332_205_ASIC[47]
  PIN TSV_TM_332_205_ASIC[48]
    DIRECTION INPUT ;
    USE SIGNAL ;
    PORT
      LAYER M4 ;
        RECT 90.865 178.695 92.2 178.795 ;
        RECT 87.505 178.615 90.965 178.715 ;
    END
  END TSV_TM_332_205_ASIC[48]
  PIN TSV_TM_332_205_ASIC[49]
    DIRECTION INPUT ;
    USE SIGNAL ;
    PORT
      LAYER M4 ;
        RECT 90.665 178.895 92.2 178.995 ;
        RECT 87.505 178.815 90.765 178.915 ;
    END
  END TSV_TM_332_205_ASIC[49]
  PIN TSV_TM_332_205_ASIC[4]
    DIRECTION INPUT ;
    USE SIGNAL ;
    PORT
      LAYER M4 ;
        RECT 87.505 56.295 92.2 56.395 ;
    END
  END TSV_TM_332_205_ASIC[4]
  PIN TSV_TM_332_205_ASIC[50]
    DIRECTION INPUT ;
    USE SIGNAL ;
    PORT
      LAYER M4 ;
        RECT 91.065 184.095 92.2 184.195 ;
        RECT 87.505 184.175 91.165 184.275 ;
    END
  END TSV_TM_332_205_ASIC[50]
  PIN TSV_TM_332_205_ASIC[51]
    DIRECTION INPUT ;
    USE SIGNAL ;
    PORT
      LAYER M4 ;
        RECT 91.265 184.295 92.2 184.395 ;
        RECT 87.505 184.375 91.365 184.475 ;
    END
  END TSV_TM_332_205_ASIC[51]
  PIN TSV_TM_332_205_ASIC[52]
    DIRECTION INPUT ;
    USE SIGNAL ;
    PORT
      LAYER M4 ;
        RECT 91.065 189.695 92.2 189.795 ;
        RECT 87.505 189.735 91.165 189.835 ;
    END
  END TSV_TM_332_205_ASIC[52]
  PIN TSV_TM_332_205_ASIC[53]
    DIRECTION INPUT ;
    USE SIGNAL ;
    PORT
      LAYER M4 ;
        RECT 91.265 189.895 92.2 189.995 ;
        RECT 87.505 189.935 91.365 190.035 ;
    END
  END TSV_TM_332_205_ASIC[53]
  PIN TSV_TM_332_205_ASIC[54]
    DIRECTION INPUT ;
    USE SIGNAL ;
    PORT
      LAYER M4 ;
        RECT 87.505 195.295 92.2 195.395 ;
    END
  END TSV_TM_332_205_ASIC[54]
  PIN TSV_TM_332_205_ASIC[55]
    DIRECTION INPUT ;
    USE SIGNAL ;
    PORT
      LAYER M4 ;
        RECT 87.505 195.495 92.2 195.595 ;
    END
  END TSV_TM_332_205_ASIC[55]
  PIN TSV_TM_332_205_ASIC[56]
    DIRECTION INPUT ;
    USE SIGNAL ;
    PORT
      LAYER M4 ;
        RECT 90.865 200.895 92.2 200.995 ;
        RECT 87.505 200.855 90.965 200.955 ;
    END
  END TSV_TM_332_205_ASIC[56]
  PIN TSV_TM_332_205_ASIC[57]
    DIRECTION INPUT ;
    USE SIGNAL ;
    PORT
      LAYER M4 ;
        RECT 90.665 201.095 92.2 201.195 ;
        RECT 87.505 201.055 90.765 201.155 ;
    END
  END TSV_TM_332_205_ASIC[57]
  PIN TSV_TM_332_205_ASIC[58]
    DIRECTION INPUT ;
    USE SIGNAL ;
    PORT
      LAYER M4 ;
        RECT 90.865 206.495 92.2 206.595 ;
        RECT 87.505 206.415 90.965 206.515 ;
    END
  END TSV_TM_332_205_ASIC[58]
  PIN TSV_TM_332_205_ASIC[59]
    DIRECTION INPUT ;
    USE SIGNAL ;
    PORT
      LAYER M4 ;
        RECT 90.665 206.695 92.2 206.795 ;
        RECT 87.505 206.615 90.765 206.715 ;
    END
  END TSV_TM_332_205_ASIC[59]
  PIN TSV_TM_332_205_ASIC[5]
    DIRECTION INPUT ;
    USE SIGNAL ;
    PORT
      LAYER M4 ;
        RECT 87.505 56.495 92.2 56.595 ;
    END
  END TSV_TM_332_205_ASIC[5]
  PIN TSV_TM_332_205_ASIC[60]
    DIRECTION INPUT ;
    USE SIGNAL ;
    PORT
      LAYER M4 ;
        RECT 91.065 211.895 92.2 211.995 ;
        RECT 87.505 211.975 91.165 212.075 ;
    END
  END TSV_TM_332_205_ASIC[60]
  PIN TSV_TM_332_205_ASIC[61]
    DIRECTION INPUT ;
    USE SIGNAL ;
    PORT
      LAYER M4 ;
        RECT 91.265 212.095 92.2 212.195 ;
        RECT 87.505 212.175 91.365 212.275 ;
    END
  END TSV_TM_332_205_ASIC[61]
  PIN TSV_TM_332_205_ASIC[62]
    DIRECTION INPUT ;
    USE SIGNAL ;
    PORT
      LAYER M4 ;
        RECT 91.065 217.495 92.2 217.595 ;
        RECT 87.505 217.535 91.165 217.635 ;
    END
  END TSV_TM_332_205_ASIC[62]
  PIN TSV_TM_332_205_ASIC[63]
    DIRECTION INPUT ;
    USE SIGNAL ;
    PORT
      LAYER M4 ;
        RECT 91.265 217.695 92.2 217.795 ;
        RECT 87.505 217.735 91.365 217.835 ;
    END
  END TSV_TM_332_205_ASIC[63]
  PIN TSV_TM_332_205_ASIC[64]
    DIRECTION INPUT ;
    USE SIGNAL ;
    PORT
      LAYER M4 ;
        RECT 87.505 223.095 92.2 223.195 ;
    END
  END TSV_TM_332_205_ASIC[64]
  PIN TSV_TM_332_205_ASIC[65]
    DIRECTION INPUT ;
    USE SIGNAL ;
    PORT
      LAYER M4 ;
        RECT 87.505 223.295 92.2 223.395 ;
    END
  END TSV_TM_332_205_ASIC[65]
  PIN TSV_TM_332_205_ASIC[66]
    DIRECTION INPUT ;
    USE SIGNAL ;
    PORT
      LAYER M4 ;
        RECT 90.865 228.695 92.2 228.795 ;
        RECT 87.505 228.655 90.965 228.755 ;
    END
  END TSV_TM_332_205_ASIC[66]
  PIN TSV_TM_332_205_ASIC[67]
    DIRECTION INPUT ;
    USE SIGNAL ;
    PORT
      LAYER M4 ;
        RECT 90.665 228.895 92.2 228.995 ;
        RECT 87.505 228.855 90.765 228.955 ;
    END
  END TSV_TM_332_205_ASIC[67]
  PIN TSV_TM_332_205_ASIC[68]
    DIRECTION INPUT ;
    USE SIGNAL ;
    PORT
      LAYER M4 ;
        RECT 90.865 234.295 92.2 234.395 ;
        RECT 87.505 234.215 90.965 234.315 ;
    END
  END TSV_TM_332_205_ASIC[68]
  PIN TSV_TM_332_205_ASIC[69]
    DIRECTION INPUT ;
    USE SIGNAL ;
    PORT
      LAYER M4 ;
        RECT 90.665 234.495 92.2 234.595 ;
        RECT 87.505 234.415 90.765 234.515 ;
    END
  END TSV_TM_332_205_ASIC[69]
  PIN TSV_TM_332_205_ASIC[6]
    DIRECTION INPUT ;
    USE SIGNAL ;
    PORT
      LAYER M4 ;
        RECT 90.865 61.895 92.2 61.995 ;
        RECT 87.505 61.855 90.965 61.955 ;
    END
  END TSV_TM_332_205_ASIC[6]
  PIN TSV_TM_332_205_ASIC[70]
    DIRECTION INPUT ;
    USE SIGNAL ;
    PORT
      LAYER M4 ;
        RECT 91.065 239.695 92.2 239.795 ;
        RECT 87.505 239.775 91.165 239.875 ;
    END
  END TSV_TM_332_205_ASIC[70]
  PIN TSV_TM_332_205_ASIC[71]
    DIRECTION INPUT ;
    USE SIGNAL ;
    PORT
      LAYER M4 ;
        RECT 91.265 239.895 92.2 239.995 ;
        RECT 87.505 239.975 91.365 240.075 ;
    END
  END TSV_TM_332_205_ASIC[71]
  PIN TSV_TM_332_205_ASIC[72]
    DIRECTION INPUT ;
    USE SIGNAL ;
    PORT
      LAYER M4 ;
        RECT 91.065 245.295 92.2 245.395 ;
        RECT 87.505 245.335 91.165 245.435 ;
    END
  END TSV_TM_332_205_ASIC[72]
  PIN TSV_TM_332_205_ASIC[73]
    DIRECTION INPUT ;
    USE SIGNAL ;
    PORT
      LAYER M4 ;
        RECT 91.265 245.495 92.2 245.595 ;
        RECT 87.505 245.535 91.365 245.635 ;
    END
  END TSV_TM_332_205_ASIC[73]
  PIN TSV_TM_332_205_ASIC[74]
    DIRECTION INPUT ;
    USE SIGNAL ;
    PORT
      LAYER M4 ;
        RECT 87.505 250.895 92.2 250.995 ;
    END
  END TSV_TM_332_205_ASIC[74]
  PIN TSV_TM_332_205_ASIC[75]
    DIRECTION INPUT ;
    USE SIGNAL ;
    PORT
      LAYER M4 ;
        RECT 87.505 251.095 92.2 251.195 ;
    END
  END TSV_TM_332_205_ASIC[75]
  PIN TSV_TM_332_205_ASIC[76]
    DIRECTION INPUT ;
    USE SIGNAL ;
    PORT
      LAYER M4 ;
        RECT 90.865 256.495 92.2 256.595 ;
        RECT 87.505 256.455 90.965 256.555 ;
    END
  END TSV_TM_332_205_ASIC[76]
  PIN TSV_TM_332_205_ASIC[77]
    DIRECTION INPUT ;
    USE SIGNAL ;
    PORT
      LAYER M4 ;
        RECT 90.665 256.695 92.2 256.795 ;
        RECT 87.505 256.655 90.765 256.755 ;
    END
  END TSV_TM_332_205_ASIC[77]
  PIN TSV_TM_332_205_ASIC[78]
    DIRECTION INPUT ;
    USE SIGNAL ;
    PORT
      LAYER M4 ;
        RECT 90.865 262.095 92.2 262.195 ;
        RECT 87.505 262.015 90.965 262.115 ;
    END
  END TSV_TM_332_205_ASIC[78]
  PIN TSV_TM_332_205_ASIC[79]
    DIRECTION INPUT ;
    USE SIGNAL ;
    PORT
      LAYER M4 ;
        RECT 90.665 262.295 92.2 262.395 ;
        RECT 87.505 262.215 90.765 262.315 ;
    END
  END TSV_TM_332_205_ASIC[79]
  PIN TSV_TM_332_205_ASIC[7]
    DIRECTION INPUT ;
    USE SIGNAL ;
    PORT
      LAYER M4 ;
        RECT 90.665 62.095 92.2 62.195 ;
        RECT 87.505 62.055 90.765 62.155 ;
    END
  END TSV_TM_332_205_ASIC[7]
  PIN TSV_TM_332_205_ASIC[80]
    DIRECTION INPUT ;
    USE SIGNAL ;
    PORT
      LAYER M4 ;
        RECT 91.065 267.495 92.2 267.595 ;
        RECT 87.505 267.575 91.165 267.675 ;
    END
  END TSV_TM_332_205_ASIC[80]
  PIN TSV_TM_332_205_ASIC[81]
    DIRECTION INPUT ;
    USE SIGNAL ;
    PORT
      LAYER M4 ;
        RECT 91.265 267.695 92.2 267.795 ;
        RECT 87.505 267.775 91.365 267.875 ;
    END
  END TSV_TM_332_205_ASIC[81]
  PIN TSV_TM_332_205_ASIC[82]
    DIRECTION INPUT ;
    USE SIGNAL ;
    PORT
      LAYER M4 ;
        RECT 91.065 273.095 92.2 273.195 ;
        RECT 87.505 273.135 91.165 273.235 ;
    END
  END TSV_TM_332_205_ASIC[82]
  PIN TSV_TM_332_205_ASIC[83]
    DIRECTION INPUT ;
    USE SIGNAL ;
    PORT
      LAYER M4 ;
        RECT 91.265 273.295 92.2 273.395 ;
        RECT 87.505 273.335 91.365 273.435 ;
    END
  END TSV_TM_332_205_ASIC[83]
  PIN TSV_TM_332_205_ASIC[84]
    DIRECTION INPUT ;
    USE SIGNAL ;
    PORT
      LAYER M4 ;
        RECT 87.505 278.695 92.2 278.795 ;
    END
  END TSV_TM_332_205_ASIC[84]
  PIN TSV_TM_332_205_ASIC[85]
    DIRECTION INPUT ;
    USE SIGNAL ;
    PORT
      LAYER M4 ;
        RECT 87.505 278.895 92.2 278.995 ;
    END
  END TSV_TM_332_205_ASIC[85]
  PIN TSV_TM_332_205_ASIC[86]
    DIRECTION INPUT ;
    USE SIGNAL ;
    PORT
      LAYER M4 ;
        RECT 90.865 284.295 92.2 284.395 ;
        RECT 87.505 284.255 90.965 284.355 ;
    END
  END TSV_TM_332_205_ASIC[86]
  PIN TSV_TM_332_205_ASIC[87]
    DIRECTION INPUT ;
    USE SIGNAL ;
    PORT
      LAYER M4 ;
        RECT 90.665 284.495 92.2 284.595 ;
        RECT 87.505 284.455 90.765 284.555 ;
    END
  END TSV_TM_332_205_ASIC[87]
  PIN TSV_TM_332_205_ASIC[88]
    DIRECTION INPUT ;
    USE SIGNAL ;
    PORT
      LAYER M4 ;
        RECT 90.865 289.895 92.2 289.995 ;
        RECT 87.505 289.815 90.965 289.915 ;
    END
  END TSV_TM_332_205_ASIC[88]
  PIN TSV_TM_332_205_ASIC[89]
    DIRECTION INPUT ;
    USE SIGNAL ;
    PORT
      LAYER M4 ;
        RECT 90.665 290.095 92.2 290.195 ;
        RECT 87.505 290.015 90.765 290.115 ;
    END
  END TSV_TM_332_205_ASIC[89]
  PIN TSV_TM_332_205_ASIC[8]
    DIRECTION INPUT ;
    USE SIGNAL ;
    PORT
      LAYER M4 ;
        RECT 90.865 67.495 92.2 67.595 ;
        RECT 87.505 67.415 90.965 67.515 ;
    END
  END TSV_TM_332_205_ASIC[8]
  PIN TSV_TM_332_205_ASIC[90]
    DIRECTION INPUT ;
    USE SIGNAL ;
    PORT
      LAYER M4 ;
        RECT 91.065 295.295 92.2 295.395 ;
        RECT 87.505 295.375 91.165 295.475 ;
    END
  END TSV_TM_332_205_ASIC[90]
  PIN TSV_TM_332_205_ASIC[91]
    DIRECTION INPUT ;
    USE SIGNAL ;
    PORT
      LAYER M4 ;
        RECT 91.265 295.495 92.2 295.595 ;
        RECT 87.505 295.575 91.365 295.675 ;
    END
  END TSV_TM_332_205_ASIC[91]
  PIN TSV_TM_332_205_ASIC[92]
    DIRECTION INPUT ;
    USE SIGNAL ;
    PORT
      LAYER M4 ;
        RECT 91.065 300.895 92.2 300.995 ;
        RECT 87.505 300.935 91.165 301.035 ;
    END
  END TSV_TM_332_205_ASIC[92]
  PIN TSV_TM_332_205_ASIC[93]
    DIRECTION INPUT ;
    USE SIGNAL ;
    PORT
      LAYER M4 ;
        RECT 91.265 301.095 92.2 301.195 ;
        RECT 87.505 301.135 91.365 301.235 ;
    END
  END TSV_TM_332_205_ASIC[93]
  PIN TSV_TM_332_205_ASIC[94]
    DIRECTION INPUT ;
    USE SIGNAL ;
    PORT
      LAYER M4 ;
        RECT 87.505 306.495 92.2 306.595 ;
    END
  END TSV_TM_332_205_ASIC[94]
  PIN TSV_TM_332_205_ASIC[95]
    DIRECTION INPUT ;
    USE SIGNAL ;
    PORT
      LAYER M4 ;
        RECT 87.505 306.695 92.2 306.795 ;
    END
  END TSV_TM_332_205_ASIC[95]
  PIN TSV_TM_332_205_ASIC[96]
    DIRECTION INPUT ;
    USE SIGNAL ;
    PORT
      LAYER M4 ;
        RECT 90.865 312.095 92.2 312.195 ;
        RECT 87.505 312.055 90.965 312.155 ;
    END
  END TSV_TM_332_205_ASIC[96]
  PIN TSV_TM_332_205_ASIC[97]
    DIRECTION INPUT ;
    USE SIGNAL ;
    PORT
      LAYER M4 ;
        RECT 90.665 312.295 92.2 312.395 ;
        RECT 87.505 312.255 90.765 312.355 ;
    END
  END TSV_TM_332_205_ASIC[97]
  PIN TSV_TM_332_205_ASIC[98]
    DIRECTION INPUT ;
    USE SIGNAL ;
    PORT
      LAYER M4 ;
        RECT 90.865 317.695 92.2 317.795 ;
        RECT 87.505 317.615 90.965 317.715 ;
    END
  END TSV_TM_332_205_ASIC[98]
  PIN TSV_TM_332_205_ASIC[99]
    DIRECTION INPUT ;
    USE SIGNAL ;
    PORT
      LAYER M4 ;
        RECT 90.665 317.895 92.2 317.995 ;
        RECT 87.505 317.815 90.765 317.915 ;
    END
  END TSV_TM_332_205_ASIC[99]
  PIN TSV_TM_332_205_ASIC[9]
    DIRECTION INPUT ;
    USE SIGNAL ;
    PORT
      LAYER M4 ;
        RECT 90.665 67.695 92.2 67.795 ;
        RECT 87.505 67.615 90.765 67.715 ;
    END
  END TSV_TM_332_205_ASIC[9]
  PIN TSV_TM_88_1_ASIC[0]
    DIRECTION INPUT ;
    USE SIGNAL ;
    PORT
      LAYER M4 ;
        RECT 90.665 50.295 92.2 50.395 ;
        RECT 87.505 50.335 90.765 50.435 ;
    END
  END TSV_TM_88_1_ASIC[0]
  PIN TSV_TM_88_1_ASIC[10]
    DIRECTION INPUT ;
    USE SIGNAL ;
    PORT
      LAYER M4 ;
        RECT 90.665 78.095 92.2 78.195 ;
        RECT 87.505 78.135 90.765 78.235 ;
    END
  END TSV_TM_88_1_ASIC[10]
  PIN TSV_TM_88_1_ASIC[11]
    DIRECTION INPUT ;
    USE SIGNAL ;
    PORT
      LAYER M4 ;
        RECT 90.865 78.295 92.2 78.395 ;
        RECT 87.505 78.335 90.965 78.435 ;
    END
  END TSV_TM_88_1_ASIC[11]
  PIN TSV_TM_88_1_ASIC[12]
    DIRECTION INPUT ;
    USE SIGNAL ;
    PORT
      LAYER M4 ;
        RECT 87.505 83.695 92.2 83.795 ;
    END
  END TSV_TM_88_1_ASIC[12]
  PIN TSV_TM_88_1_ASIC[13]
    DIRECTION INPUT ;
    USE SIGNAL ;
    PORT
      LAYER M4 ;
        RECT 87.505 83.895 92.2 83.995 ;
    END
  END TSV_TM_88_1_ASIC[13]
  PIN TSV_TM_88_1_ASIC[14]
    DIRECTION INPUT ;
    USE SIGNAL ;
    PORT
      LAYER M4 ;
        RECT 91.265 89.295 92.2 89.395 ;
        RECT 87.505 89.255 91.365 89.355 ;
    END
  END TSV_TM_88_1_ASIC[14]
  PIN TSV_TM_88_1_ASIC[15]
    DIRECTION INPUT ;
    USE SIGNAL ;
    PORT
      LAYER M4 ;
        RECT 91.065 89.495 92.2 89.595 ;
        RECT 87.505 89.455 91.165 89.555 ;
    END
  END TSV_TM_88_1_ASIC[15]
  PIN TSV_TM_88_1_ASIC[16]
    DIRECTION INPUT ;
    USE SIGNAL ;
    PORT
      LAYER M4 ;
        RECT 91.265 94.895 92.2 94.995 ;
        RECT 87.505 94.815 91.365 94.915 ;
    END
  END TSV_TM_88_1_ASIC[16]
  PIN TSV_TM_88_1_ASIC[17]
    DIRECTION INPUT ;
    USE SIGNAL ;
    PORT
      LAYER M4 ;
        RECT 91.065 95.095 92.2 95.195 ;
        RECT 87.505 95.015 91.165 95.115 ;
    END
  END TSV_TM_88_1_ASIC[17]
  PIN TSV_TM_88_1_ASIC[18]
    DIRECTION INPUT ;
    USE SIGNAL ;
    PORT
      LAYER M4 ;
        RECT 90.665 100.295 92.2 100.395 ;
        RECT 87.505 100.375 90.765 100.475 ;
    END
  END TSV_TM_88_1_ASIC[18]
  PIN TSV_TM_88_1_ASIC[19]
    DIRECTION INPUT ;
    USE SIGNAL ;
    PORT
      LAYER M4 ;
        RECT 90.865 100.495 92.2 100.595 ;
        RECT 87.505 100.575 90.965 100.675 ;
    END
  END TSV_TM_88_1_ASIC[19]
  PIN TSV_TM_88_1_ASIC[1]
    DIRECTION INPUT ;
    USE SIGNAL ;
    PORT
      LAYER M4 ;
        RECT 90.865 50.495 92.2 50.595 ;
        RECT 87.505 50.535 90.965 50.635 ;
    END
  END TSV_TM_88_1_ASIC[1]
  PIN TSV_TM_88_1_ASIC[20]
    DIRECTION INPUT ;
    USE SIGNAL ;
    PORT
      LAYER M4 ;
        RECT 90.665 105.895 92.2 105.995 ;
        RECT 87.505 105.935 90.765 106.035 ;
    END
  END TSV_TM_88_1_ASIC[20]
  PIN TSV_TM_88_1_ASIC[21]
    DIRECTION INPUT ;
    USE SIGNAL ;
    PORT
      LAYER M4 ;
        RECT 90.865 106.095 92.2 106.195 ;
        RECT 87.505 106.135 90.965 106.235 ;
    END
  END TSV_TM_88_1_ASIC[21]
  PIN TSV_TM_88_1_ASIC[22]
    DIRECTION INPUT ;
    USE SIGNAL ;
    PORT
      LAYER M4 ;
        RECT 87.505 111.495 92.2 111.595 ;
    END
  END TSV_TM_88_1_ASIC[22]
  PIN TSV_TM_88_1_ASIC[23]
    DIRECTION INPUT ;
    USE SIGNAL ;
    PORT
      LAYER M4 ;
        RECT 87.505 111.695 92.2 111.795 ;
    END
  END TSV_TM_88_1_ASIC[23]
  PIN TSV_TM_88_1_ASIC[24]
    DIRECTION INPUT ;
    USE SIGNAL ;
    PORT
      LAYER M4 ;
        RECT 91.265 117.095 92.2 117.195 ;
        RECT 87.505 117.055 91.365 117.155 ;
    END
  END TSV_TM_88_1_ASIC[24]
  PIN TSV_TM_88_1_ASIC[25]
    DIRECTION INPUT ;
    USE SIGNAL ;
    PORT
      LAYER M4 ;
        RECT 91.065 117.295 92.2 117.395 ;
        RECT 87.505 117.255 91.165 117.355 ;
    END
  END TSV_TM_88_1_ASIC[25]
  PIN TSV_TM_88_1_ASIC[26]
    DIRECTION INPUT ;
    USE SIGNAL ;
    PORT
      LAYER M4 ;
        RECT 91.265 122.695 92.2 122.795 ;
        RECT 87.505 122.615 91.365 122.715 ;
    END
  END TSV_TM_88_1_ASIC[26]
  PIN TSV_TM_88_1_ASIC[27]
    DIRECTION INPUT ;
    USE SIGNAL ;
    PORT
      LAYER M4 ;
        RECT 91.065 122.895 92.2 122.995 ;
        RECT 87.505 122.815 91.165 122.915 ;
    END
  END TSV_TM_88_1_ASIC[27]
  PIN TSV_TM_88_1_ASIC[28]
    DIRECTION INPUT ;
    USE SIGNAL ;
    PORT
      LAYER M4 ;
        RECT 90.665 128.095 92.2 128.195 ;
        RECT 87.505 128.175 90.765 128.275 ;
    END
  END TSV_TM_88_1_ASIC[28]
  PIN TSV_TM_88_1_ASIC[29]
    DIRECTION INPUT ;
    USE SIGNAL ;
    PORT
      LAYER M4 ;
        RECT 90.865 128.295 92.2 128.395 ;
        RECT 87.505 128.375 90.965 128.475 ;
    END
  END TSV_TM_88_1_ASIC[29]
  PIN TSV_TM_88_1_ASIC[2]
    DIRECTION INPUT ;
    USE SIGNAL ;
    PORT
      LAYER M4 ;
        RECT 87.505 55.895 92.2 55.995 ;
    END
  END TSV_TM_88_1_ASIC[2]
  PIN TSV_TM_88_1_ASIC[30]
    DIRECTION INPUT ;
    USE SIGNAL ;
    PORT
      LAYER M4 ;
        RECT 90.665 133.695 92.2 133.795 ;
        RECT 87.505 133.735 90.765 133.835 ;
    END
  END TSV_TM_88_1_ASIC[30]
  PIN TSV_TM_88_1_ASIC[31]
    DIRECTION INPUT ;
    USE SIGNAL ;
    PORT
      LAYER M4 ;
        RECT 90.865 133.895 92.2 133.995 ;
        RECT 87.505 133.935 90.965 134.035 ;
    END
  END TSV_TM_88_1_ASIC[31]
  PIN TSV_TM_88_1_ASIC[32]
    DIRECTION INPUT ;
    USE SIGNAL ;
    PORT
      LAYER M4 ;
        RECT 87.505 139.295 92.2 139.395 ;
    END
  END TSV_TM_88_1_ASIC[32]
  PIN TSV_TM_88_1_ASIC[33]
    DIRECTION INPUT ;
    USE SIGNAL ;
    PORT
      LAYER M4 ;
        RECT 87.505 139.495 92.2 139.595 ;
    END
  END TSV_TM_88_1_ASIC[33]
  PIN TSV_TM_88_1_ASIC[34]
    DIRECTION INPUT ;
    USE SIGNAL ;
    PORT
      LAYER M4 ;
        RECT 91.265 144.895 92.2 144.995 ;
        RECT 87.505 144.855 91.365 144.955 ;
    END
  END TSV_TM_88_1_ASIC[34]
  PIN TSV_TM_88_1_ASIC[35]
    DIRECTION INPUT ;
    USE SIGNAL ;
    PORT
      LAYER M4 ;
        RECT 91.065 145.095 92.2 145.195 ;
        RECT 87.505 145.055 91.165 145.155 ;
    END
  END TSV_TM_88_1_ASIC[35]
  PIN TSV_TM_88_1_ASIC[36]
    DIRECTION INPUT ;
    USE SIGNAL ;
    PORT
      LAYER M4 ;
        RECT 91.265 150.495 92.2 150.595 ;
        RECT 87.505 150.415 91.365 150.515 ;
    END
  END TSV_TM_88_1_ASIC[36]
  PIN TSV_TM_88_1_ASIC[37]
    DIRECTION INPUT ;
    USE SIGNAL ;
    PORT
      LAYER M4 ;
        RECT 91.065 150.695 92.2 150.795 ;
        RECT 87.505 150.615 91.165 150.715 ;
    END
  END TSV_TM_88_1_ASIC[37]
  PIN TSV_TM_88_1_ASIC[38]
    DIRECTION INPUT ;
    USE SIGNAL ;
    PORT
      LAYER M4 ;
        RECT 90.665 155.895 92.2 155.995 ;
        RECT 87.505 155.975 90.765 156.075 ;
    END
  END TSV_TM_88_1_ASIC[38]
  PIN TSV_TM_88_1_ASIC[39]
    DIRECTION INPUT ;
    USE SIGNAL ;
    PORT
      LAYER M4 ;
        RECT 90.865 156.095 92.2 156.195 ;
        RECT 87.505 156.175 90.965 156.275 ;
    END
  END TSV_TM_88_1_ASIC[39]
  PIN TSV_TM_88_1_ASIC[3]
    DIRECTION INPUT ;
    USE SIGNAL ;
    PORT
      LAYER M4 ;
        RECT 87.505 56.095 92.2 56.195 ;
    END
  END TSV_TM_88_1_ASIC[3]
  PIN TSV_TM_88_1_ASIC[40]
    DIRECTION INPUT ;
    USE SIGNAL ;
    PORT
      LAYER M4 ;
        RECT 90.665 161.495 92.2 161.595 ;
        RECT 87.505 161.535 90.765 161.635 ;
    END
  END TSV_TM_88_1_ASIC[40]
  PIN TSV_TM_88_1_ASIC[41]
    DIRECTION INPUT ;
    USE SIGNAL ;
    PORT
      LAYER M4 ;
        RECT 90.865 161.695 92.2 161.795 ;
        RECT 87.505 161.735 90.965 161.835 ;
    END
  END TSV_TM_88_1_ASIC[41]
  PIN TSV_TM_88_1_ASIC[42]
    DIRECTION INPUT ;
    USE SIGNAL ;
    PORT
      LAYER M4 ;
        RECT 87.505 167.095 92.2 167.195 ;
    END
  END TSV_TM_88_1_ASIC[42]
  PIN TSV_TM_88_1_ASIC[43]
    DIRECTION INPUT ;
    USE SIGNAL ;
    PORT
      LAYER M4 ;
        RECT 87.505 167.295 92.2 167.395 ;
    END
  END TSV_TM_88_1_ASIC[43]
  PIN TSV_TM_88_1_ASIC[44]
    DIRECTION INPUT ;
    USE SIGNAL ;
    PORT
      LAYER M4 ;
        RECT 91.265 172.695 92.2 172.795 ;
        RECT 87.505 172.655 91.365 172.755 ;
    END
  END TSV_TM_88_1_ASIC[44]
  PIN TSV_TM_88_1_ASIC[45]
    DIRECTION INPUT ;
    USE SIGNAL ;
    PORT
      LAYER M4 ;
        RECT 91.065 172.895 92.2 172.995 ;
        RECT 87.505 172.855 91.165 172.955 ;
    END
  END TSV_TM_88_1_ASIC[45]
  PIN TSV_TM_88_1_ASIC[46]
    DIRECTION INPUT ;
    USE SIGNAL ;
    PORT
      LAYER M4 ;
        RECT 91.265 178.295 92.2 178.395 ;
        RECT 87.505 178.215 91.365 178.315 ;
    END
  END TSV_TM_88_1_ASIC[46]
  PIN TSV_TM_88_1_ASIC[47]
    DIRECTION INPUT ;
    USE SIGNAL ;
    PORT
      LAYER M4 ;
        RECT 91.065 178.495 92.2 178.595 ;
        RECT 87.505 178.415 91.165 178.515 ;
    END
  END TSV_TM_88_1_ASIC[47]
  PIN TSV_TM_88_1_ASIC[48]
    DIRECTION INPUT ;
    USE SIGNAL ;
    PORT
      LAYER M4 ;
        RECT 90.665 183.695 92.2 183.795 ;
        RECT 87.505 183.775 90.765 183.875 ;
    END
  END TSV_TM_88_1_ASIC[48]
  PIN TSV_TM_88_1_ASIC[49]
    DIRECTION INPUT ;
    USE SIGNAL ;
    PORT
      LAYER M4 ;
        RECT 90.865 183.895 92.2 183.995 ;
        RECT 87.505 183.975 90.965 184.075 ;
    END
  END TSV_TM_88_1_ASIC[49]
  PIN TSV_TM_88_1_ASIC[4]
    DIRECTION INPUT ;
    USE SIGNAL ;
    PORT
      LAYER M4 ;
        RECT 91.265 61.495 92.2 61.595 ;
        RECT 87.505 61.455 91.365 61.555 ;
    END
  END TSV_TM_88_1_ASIC[4]
  PIN TSV_TM_88_1_ASIC[50]
    DIRECTION INPUT ;
    USE SIGNAL ;
    PORT
      LAYER M4 ;
        RECT 90.665 189.295 92.2 189.395 ;
        RECT 87.505 189.335 90.765 189.435 ;
    END
  END TSV_TM_88_1_ASIC[50]
  PIN TSV_TM_88_1_ASIC[51]
    DIRECTION INPUT ;
    USE SIGNAL ;
    PORT
      LAYER M4 ;
        RECT 90.865 189.495 92.2 189.595 ;
        RECT 87.505 189.535 90.965 189.635 ;
    END
  END TSV_TM_88_1_ASIC[51]
  PIN TSV_TM_88_1_ASIC[52]
    DIRECTION INPUT ;
    USE SIGNAL ;
    PORT
      LAYER M4 ;
        RECT 87.505 194.895 92.2 194.995 ;
    END
  END TSV_TM_88_1_ASIC[52]
  PIN TSV_TM_88_1_ASIC[53]
    DIRECTION INPUT ;
    USE SIGNAL ;
    PORT
      LAYER M4 ;
        RECT 87.505 195.095 92.2 195.195 ;
    END
  END TSV_TM_88_1_ASIC[53]
  PIN TSV_TM_88_1_ASIC[54]
    DIRECTION INPUT ;
    USE SIGNAL ;
    PORT
      LAYER M4 ;
        RECT 91.265 200.495 92.2 200.595 ;
        RECT 87.505 200.455 91.365 200.555 ;
    END
  END TSV_TM_88_1_ASIC[54]
  PIN TSV_TM_88_1_ASIC[55]
    DIRECTION INPUT ;
    USE SIGNAL ;
    PORT
      LAYER M4 ;
        RECT 91.065 200.695 92.2 200.795 ;
        RECT 87.505 200.655 91.165 200.755 ;
    END
  END TSV_TM_88_1_ASIC[55]
  PIN TSV_TM_88_1_ASIC[56]
    DIRECTION INPUT ;
    USE SIGNAL ;
    PORT
      LAYER M4 ;
        RECT 91.265 206.095 92.2 206.195 ;
        RECT 87.505 206.015 91.365 206.115 ;
    END
  END TSV_TM_88_1_ASIC[56]
  PIN TSV_TM_88_1_ASIC[57]
    DIRECTION INPUT ;
    USE SIGNAL ;
    PORT
      LAYER M4 ;
        RECT 91.065 206.295 92.2 206.395 ;
        RECT 87.505 206.215 91.165 206.315 ;
    END
  END TSV_TM_88_1_ASIC[57]
  PIN TSV_TM_88_1_ASIC[58]
    DIRECTION INPUT ;
    USE SIGNAL ;
    PORT
      LAYER M4 ;
        RECT 90.665 211.495 92.2 211.595 ;
        RECT 87.505 211.575 90.765 211.675 ;
    END
  END TSV_TM_88_1_ASIC[58]
  PIN TSV_TM_88_1_ASIC[59]
    DIRECTION INPUT ;
    USE SIGNAL ;
    PORT
      LAYER M4 ;
        RECT 90.865 211.695 92.2 211.795 ;
        RECT 87.505 211.775 90.965 211.875 ;
    END
  END TSV_TM_88_1_ASIC[59]
  PIN TSV_TM_88_1_ASIC[5]
    DIRECTION INPUT ;
    USE SIGNAL ;
    PORT
      LAYER M4 ;
        RECT 91.065 61.695 92.2 61.795 ;
        RECT 87.505 61.655 91.165 61.755 ;
    END
  END TSV_TM_88_1_ASIC[5]
  PIN TSV_TM_88_1_ASIC[60]
    DIRECTION INPUT ;
    USE SIGNAL ;
    PORT
      LAYER M4 ;
        RECT 90.665 217.095 92.2 217.195 ;
        RECT 87.505 217.135 90.765 217.235 ;
    END
  END TSV_TM_88_1_ASIC[60]
  PIN TSV_TM_88_1_ASIC[61]
    DIRECTION INPUT ;
    USE SIGNAL ;
    PORT
      LAYER M4 ;
        RECT 90.865 217.295 92.2 217.395 ;
        RECT 87.505 217.335 90.965 217.435 ;
    END
  END TSV_TM_88_1_ASIC[61]
  PIN TSV_TM_88_1_ASIC[62]
    DIRECTION INPUT ;
    USE SIGNAL ;
    PORT
      LAYER M4 ;
        RECT 87.505 222.695 92.2 222.795 ;
    END
  END TSV_TM_88_1_ASIC[62]
  PIN TSV_TM_88_1_ASIC[63]
    DIRECTION INPUT ;
    USE SIGNAL ;
    PORT
      LAYER M4 ;
        RECT 87.505 222.895 92.2 222.995 ;
    END
  END TSV_TM_88_1_ASIC[63]
  PIN TSV_TM_88_1_ASIC[64]
    DIRECTION INPUT ;
    USE SIGNAL ;
    PORT
      LAYER M4 ;
        RECT 91.265 228.295 92.2 228.395 ;
        RECT 87.505 228.255 91.365 228.355 ;
    END
  END TSV_TM_88_1_ASIC[64]
  PIN TSV_TM_88_1_ASIC[65]
    DIRECTION INPUT ;
    USE SIGNAL ;
    PORT
      LAYER M4 ;
        RECT 91.065 228.495 92.2 228.595 ;
        RECT 87.505 228.455 91.165 228.555 ;
    END
  END TSV_TM_88_1_ASIC[65]
  PIN TSV_TM_88_1_ASIC[66]
    DIRECTION INPUT ;
    USE SIGNAL ;
    PORT
      LAYER M4 ;
        RECT 91.265 233.895 92.2 233.995 ;
        RECT 87.505 233.815 91.365 233.915 ;
    END
  END TSV_TM_88_1_ASIC[66]
  PIN TSV_TM_88_1_ASIC[67]
    DIRECTION INPUT ;
    USE SIGNAL ;
    PORT
      LAYER M4 ;
        RECT 91.065 234.095 92.2 234.195 ;
        RECT 87.505 234.015 91.165 234.115 ;
    END
  END TSV_TM_88_1_ASIC[67]
  PIN TSV_TM_88_1_ASIC[68]
    DIRECTION INPUT ;
    USE SIGNAL ;
    PORT
      LAYER M4 ;
        RECT 90.665 239.295 92.2 239.395 ;
        RECT 87.505 239.375 90.765 239.475 ;
    END
  END TSV_TM_88_1_ASIC[68]
  PIN TSV_TM_88_1_ASIC[69]
    DIRECTION INPUT ;
    USE SIGNAL ;
    PORT
      LAYER M4 ;
        RECT 90.865 239.495 92.2 239.595 ;
        RECT 87.505 239.575 90.965 239.675 ;
    END
  END TSV_TM_88_1_ASIC[69]
  PIN TSV_TM_88_1_ASIC[6]
    DIRECTION INPUT ;
    USE SIGNAL ;
    PORT
      LAYER M4 ;
        RECT 91.265 67.095 92.2 67.195 ;
        RECT 87.505 67.015 91.365 67.115 ;
    END
  END TSV_TM_88_1_ASIC[6]
  PIN TSV_TM_88_1_ASIC[70]
    DIRECTION INPUT ;
    USE SIGNAL ;
    PORT
      LAYER M4 ;
        RECT 90.665 244.895 92.2 244.995 ;
        RECT 87.505 244.935 90.765 245.035 ;
    END
  END TSV_TM_88_1_ASIC[70]
  PIN TSV_TM_88_1_ASIC[71]
    DIRECTION INPUT ;
    USE SIGNAL ;
    PORT
      LAYER M4 ;
        RECT 90.865 245.095 92.2 245.195 ;
        RECT 87.505 245.135 90.965 245.235 ;
    END
  END TSV_TM_88_1_ASIC[71]
  PIN TSV_TM_88_1_ASIC[72]
    DIRECTION INPUT ;
    USE SIGNAL ;
    PORT
      LAYER M4 ;
        RECT 87.505 250.495 92.2 250.595 ;
    END
  END TSV_TM_88_1_ASIC[72]
  PIN TSV_TM_88_1_ASIC[73]
    DIRECTION INPUT ;
    USE SIGNAL ;
    PORT
      LAYER M4 ;
        RECT 87.505 250.695 92.2 250.795 ;
    END
  END TSV_TM_88_1_ASIC[73]
  PIN TSV_TM_88_1_ASIC[74]
    DIRECTION INPUT ;
    USE SIGNAL ;
    PORT
      LAYER M4 ;
        RECT 91.265 256.095 92.2 256.195 ;
        RECT 87.505 256.055 91.365 256.155 ;
    END
  END TSV_TM_88_1_ASIC[74]
  PIN TSV_TM_88_1_ASIC[75]
    DIRECTION INPUT ;
    USE SIGNAL ;
    PORT
      LAYER M4 ;
        RECT 91.065 256.295 92.2 256.395 ;
        RECT 87.505 256.255 91.165 256.355 ;
    END
  END TSV_TM_88_1_ASIC[75]
  PIN TSV_TM_88_1_ASIC[76]
    DIRECTION INPUT ;
    USE SIGNAL ;
    PORT
      LAYER M4 ;
        RECT 91.265 261.695 92.2 261.795 ;
        RECT 87.505 261.615 91.365 261.715 ;
    END
  END TSV_TM_88_1_ASIC[76]
  PIN TSV_TM_88_1_ASIC[77]
    DIRECTION INPUT ;
    USE SIGNAL ;
    PORT
      LAYER M4 ;
        RECT 91.065 261.895 92.2 261.995 ;
        RECT 87.505 261.815 91.165 261.915 ;
    END
  END TSV_TM_88_1_ASIC[77]
  PIN TSV_TM_88_1_ASIC[78]
    DIRECTION INPUT ;
    USE SIGNAL ;
    PORT
      LAYER M4 ;
        RECT 90.665 267.095 92.2 267.195 ;
        RECT 87.505 267.175 90.765 267.275 ;
    END
  END TSV_TM_88_1_ASIC[78]
  PIN TSV_TM_88_1_ASIC[79]
    DIRECTION INPUT ;
    USE SIGNAL ;
    PORT
      LAYER M4 ;
        RECT 90.865 267.295 92.2 267.395 ;
        RECT 87.505 267.375 90.965 267.475 ;
    END
  END TSV_TM_88_1_ASIC[79]
  PIN TSV_TM_88_1_ASIC[7]
    DIRECTION INPUT ;
    USE SIGNAL ;
    PORT
      LAYER M4 ;
        RECT 91.065 67.295 92.2 67.395 ;
        RECT 87.505 67.215 91.165 67.315 ;
    END
  END TSV_TM_88_1_ASIC[7]
  PIN TSV_TM_88_1_ASIC[80]
    DIRECTION INPUT ;
    USE SIGNAL ;
    PORT
      LAYER M4 ;
        RECT 90.665 272.695 92.2 272.795 ;
        RECT 87.505 272.735 90.765 272.835 ;
    END
  END TSV_TM_88_1_ASIC[80]
  PIN TSV_TM_88_1_ASIC[81]
    DIRECTION INPUT ;
    USE SIGNAL ;
    PORT
      LAYER M4 ;
        RECT 90.865 272.895 92.2 272.995 ;
        RECT 87.505 272.935 90.965 273.035 ;
    END
  END TSV_TM_88_1_ASIC[81]
  PIN TSV_TM_88_1_ASIC[82]
    DIRECTION INPUT ;
    USE SIGNAL ;
    PORT
      LAYER M4 ;
        RECT 87.505 278.295 92.2 278.395 ;
    END
  END TSV_TM_88_1_ASIC[82]
  PIN TSV_TM_88_1_ASIC[83]
    DIRECTION INPUT ;
    USE SIGNAL ;
    PORT
      LAYER M4 ;
        RECT 87.505 278.495 92.2 278.595 ;
    END
  END TSV_TM_88_1_ASIC[83]
  PIN TSV_TM_88_1_ASIC[84]
    DIRECTION INPUT ;
    USE SIGNAL ;
    PORT
      LAYER M4 ;
        RECT 91.265 283.895 92.2 283.995 ;
        RECT 87.505 283.855 91.365 283.955 ;
    END
  END TSV_TM_88_1_ASIC[84]
  PIN TSV_TM_88_1_ASIC[85]
    DIRECTION INPUT ;
    USE SIGNAL ;
    PORT
      LAYER M4 ;
        RECT 91.065 284.095 92.2 284.195 ;
        RECT 87.505 284.055 91.165 284.155 ;
    END
  END TSV_TM_88_1_ASIC[85]
  PIN TSV_TM_88_1_ASIC[86]
    DIRECTION INPUT ;
    USE SIGNAL ;
    PORT
      LAYER M4 ;
        RECT 91.265 289.495 92.2 289.595 ;
        RECT 87.505 289.415 91.365 289.515 ;
    END
  END TSV_TM_88_1_ASIC[86]
  PIN TSV_TM_88_1_ASIC[87]
    DIRECTION INPUT ;
    USE SIGNAL ;
    PORT
      LAYER M4 ;
        RECT 91.065 289.695 92.2 289.795 ;
        RECT 87.505 289.615 91.165 289.715 ;
    END
  END TSV_TM_88_1_ASIC[87]
  PIN TSV_TM_88_1_ASIC[8]
    DIRECTION INPUT ;
    USE SIGNAL ;
    PORT
      LAYER M4 ;
        RECT 90.665 72.495 92.2 72.595 ;
        RECT 87.505 72.575 90.765 72.675 ;
    END
  END TSV_TM_88_1_ASIC[8]
  PIN TSV_TM_88_1_ASIC[9]
    DIRECTION INPUT ;
    USE SIGNAL ;
    PORT
      LAYER M4 ;
        RECT 90.865 72.695 92.2 72.795 ;
        RECT 87.505 72.775 90.965 72.875 ;
    END
  END TSV_TM_88_1_ASIC[9]
  PIN ls_en_asic
    DIRECTION INPUT ;
    USE SIGNAL ;
    PORT
      LAYER M4 ;
        RECT 90.54 175.735 92.2 175.835 ;
    END
  END ls_en_asic
  PIN vss
    DIRECTION INOUT ;
    USE GROUND ;
    SHAPE RING ;
    PORT
      LAYER M4 ;
        RECT 90.54 175.935 92.2 176.035 ;
    END
    PORT
      LAYER M4 ;
        RECT 90.54 175.535 92.2 175.635 ;
    END
    PORT
      LAYER M7 ;
        RECT 43.485 0 44.485 346 ;
    END
    PORT
      LAYER M7 ;
        RECT 47.685 0 48.685 346 ;
    END
  END vss
  PIN vdd
    DIRECTION INOUT ;
    USE POWER ;
    SHAPE RING ;
    PORT
      LAYER M7 ;
        RECT 44.785 0 45.785 346 ;
    END
    PORT
      LAYER M7 ;
        RECT 46.385 0 47.385 346 ;
    END
  END vdd
  PIN vdd_array
    DIRECTION INOUT ;
    USE SIGNAL ;
    PORT
      LAYER M7 ;
        RECT 25.385 0 26.785 346 ;
    END
    PORT
      LAYER M7 ;
        RECT 27.085 0 28.485 346 ;
    END
    PORT
      LAYER M7 ;
        RECT 28.785 0 30.185 346 ;
    END
    PORT
      LAYER M7 ;
        RECT 36.155 0 37.555 346 ;
    END
    PORT
      LAYER M7 ;
        RECT 37.855 0 39.255 346 ;
    END
    PORT
      LAYER M7 ;
        RECT 52.915 0 54.315 346 ;
    END
    PORT
      LAYER M7 ;
        RECT 54.615 0 56.015 346 ;
    END
    PORT
      LAYER M7 ;
        RECT 61.985 0 63.385 346 ;
    END
    PORT
      LAYER M7 ;
        RECT 63.685 0 65.085 346 ;
    END
    PORT
      LAYER M7 ;
        RECT 65.385 0 66.785 346 ;
    END
  END vdd_array
  PIN vss_array
    DIRECTION INOUT ;
    USE SIGNAL ;
    PORT
      LAYER M7 ;
        RECT 30.765 0 32.165 346 ;
    END
    PORT
      LAYER M7 ;
        RECT 32.465 0 33.865 346 ;
    END
    PORT
      LAYER M7 ;
        RECT 34.165 0 35.565 346 ;
    END
    PORT
      LAYER M7 ;
        RECT 39.755 0 41.155 346 ;
    END
    PORT
      LAYER M7 ;
        RECT 41.455 0 42.855 346 ;
    END
    PORT
      LAYER M7 ;
        RECT 49.315 0 50.715 346 ;
    END
    PORT
      LAYER M7 ;
        RECT 51.015 0 52.415 346 ;
    END
    PORT
      LAYER M7 ;
        RECT 56.605 0 58.005 346 ;
    END
    PORT
      LAYER M7 ;
        RECT 58.305 0 59.705 346 ;
    END
    PORT
      LAYER M7 ;
        RECT 60.005 0 61.405 346 ;
    END
  END vss_array
  OBS
    LAYER M1 ;
      RECT 67.8 0.045 68.03 27.925 ;
      RECT 24.14 0.045 24.37 27.925 ;
      RECT 38.065 0.045 54.105 0.825 ;
      RECT 24.14 0.045 68.03 0.275 ;
      RECT 24.14 345.725 68.03 345.955 ;
      RECT 67.8 345.415 68.03 345.955 ;
      RECT 42.89 345.405 49.28 345.955 ;
      RECT 24.14 345.415 24.37 345.955 ;
    LAYER M1 SPACING 0.05 ;
      RECT 0 344.75 92.2 346 ;
      RECT 91.605 0 92.2 346 ;
      RECT 80.485 0 81.715 346 ;
      RECT 21.575 0 70.595 346 ;
      RECT 10.455 0 11.685 346 ;
      RECT 0 0 0.565 346 ;
      RECT 0 339.19 92.2 340.42 ;
      RECT 0 333.63 92.2 334.86 ;
      RECT 0 328.07 92.2 329.3 ;
      RECT 0 322.51 92.2 323.74 ;
      RECT 0 316.95 92.2 318.18 ;
      RECT 0 311.39 92.2 312.62 ;
      RECT 0 305.83 92.2 307.06 ;
      RECT 0 300.27 92.2 301.5 ;
      RECT 0 294.71 92.2 295.94 ;
      RECT 0 289.15 92.2 290.38 ;
      RECT 0 283.59 92.2 284.82 ;
      RECT 0 278.03 92.2 279.26 ;
      RECT 0 272.47 92.2 273.7 ;
      RECT 0 266.91 92.2 268.14 ;
      RECT 0 261.35 92.2 262.58 ;
      RECT 0 255.79 92.2 257.02 ;
      RECT 0 250.23 92.2 251.46 ;
      RECT 0 244.67 92.2 245.9 ;
      RECT 0 239.11 92.2 240.34 ;
      RECT 0 233.55 92.2 234.78 ;
      RECT 0 227.99 92.2 229.22 ;
      RECT 0 222.43 92.2 223.66 ;
      RECT 0 216.87 92.2 218.1 ;
      RECT 0 211.31 92.2 212.54 ;
      RECT 0 205.75 92.2 206.98 ;
      RECT 0 200.19 92.2 201.42 ;
      RECT 0 194.63 92.2 195.86 ;
      RECT 0 189.07 92.2 190.3 ;
      RECT 0 183.51 92.2 184.74 ;
      RECT 0 177.95 92.2 179.18 ;
      RECT 0 172.39 92.2 173.62 ;
      RECT 0 166.83 92.2 168.06 ;
      RECT 0 161.27 92.2 162.5 ;
      RECT 0 155.71 92.2 156.94 ;
      RECT 0 150.15 92.2 151.38 ;
      RECT 0 144.59 92.2 145.82 ;
      RECT 0 139.03 92.2 140.26 ;
      RECT 0 133.47 92.2 134.7 ;
      RECT 0 127.91 92.2 129.14 ;
      RECT 0 122.35 92.2 123.58 ;
      RECT 0 116.79 92.2 118.02 ;
      RECT 0 111.23 92.2 112.46 ;
      RECT 0 105.67 92.2 106.9 ;
      RECT 0 100.11 92.2 101.34 ;
      RECT 0 94.55 92.2 95.78 ;
      RECT 0 88.99 92.2 90.22 ;
      RECT 0 83.43 92.2 84.66 ;
      RECT 0 77.87 92.2 79.1 ;
      RECT 0 72.31 92.2 73.54 ;
      RECT 0 66.75 92.2 67.98 ;
      RECT 0 61.19 92.2 62.42 ;
      RECT 0 55.63 92.2 56.86 ;
      RECT 0 50.07 92.2 51.3 ;
      RECT 0 44.51 92.2 45.74 ;
      RECT 0 38.95 92.2 40.18 ;
      RECT 0 33.39 92.2 34.62 ;
      RECT 0 27.83 92.2 29.06 ;
      RECT 80.485 22.27 92.2 29.06 ;
      RECT 0 22.27 70.595 29.06 ;
      RECT 0 22.27 92.2 23.5 ;
      RECT 0 16.71 92.2 17.94 ;
      RECT 0 11.15 92.2 12.38 ;
      RECT 0 5.59 92.2 6.82 ;
      RECT 0 0 92.2 1.26 ;
    LAYER M2 ;
      RECT 47.6 345.405 48.1 345.955 ;
      RECT 44.07 345.405 44.57 345.955 ;
    LAYER M2 SPACING 0.05 ;
      RECT 0 344.75 92.2 346 ;
      RECT 91.605 0 92.2 346 ;
      RECT 86.685 344.46 86.755 346 ;
      RECT 86.545 344.46 86.615 346 ;
      RECT 80.485 0 81.715 346 ;
      RECT 75.565 344.67 75.635 346 ;
      RECT 75.425 344.67 75.495 346 ;
      RECT 21.575 0 70.595 346 ;
      RECT 10.455 0 11.685 346 ;
      RECT 5.505 344.46 5.575 346 ;
      RECT 0 0 0.565 346 ;
      RECT 75.565 339.19 75.635 340.75 ;
      RECT 75.425 339.19 75.495 340.75 ;
      RECT 0 339.19 92.2 340.42 ;
      RECT 86.685 338.9 86.755 340.42 ;
      RECT 86.545 338.9 86.615 340.42 ;
      RECT 75.47 339.11 75.54 340.42 ;
      RECT 16.655 339.11 16.725 340.42 ;
      RECT 16.515 339.11 16.585 340.42 ;
      RECT 5.535 338.9 5.605 340.42 ;
      RECT 5.395 338.9 5.465 340.42 ;
      RECT 75.48 333.55 75.55 335.25 ;
      RECT 16.655 333.55 16.725 334.88 ;
      RECT 16.515 333.55 16.585 334.88 ;
      RECT 0 333.63 92.2 334.86 ;
      RECT 86.685 333.34 86.755 334.86 ;
      RECT 86.545 333.34 86.615 334.86 ;
      RECT 5.535 333.34 5.605 334.86 ;
      RECT 5.395 333.34 5.465 334.86 ;
      RECT 16.655 328.07 16.725 329.63 ;
      RECT 16.515 328.07 16.585 329.63 ;
      RECT 5.535 327.78 5.605 329.33 ;
      RECT 5.395 327.78 5.465 329.33 ;
      RECT 0 328.07 92.2 329.3 ;
      RECT 86.63 327.78 86.7 329.3 ;
      RECT 75.565 327.99 75.635 329.3 ;
      RECT 75.425 327.99 75.495 329.3 ;
      RECT 16.59 327.99 16.66 329.3 ;
      RECT 16.655 322.51 16.725 324.07 ;
      RECT 16.515 322.51 16.585 324.07 ;
      RECT 75.565 322.43 75.635 323.78 ;
      RECT 75.425 322.43 75.495 323.78 ;
      RECT 0 322.51 92.2 323.74 ;
      RECT 86.64 322.22 86.71 323.74 ;
      RECT 16.6 322.43 16.67 323.74 ;
      RECT 5.43 322.22 5.5 323.74 ;
      RECT 75.565 316.95 75.635 318.51 ;
      RECT 75.425 316.95 75.495 318.51 ;
      RECT 0 316.95 92.2 318.18 ;
      RECT 86.685 316.66 86.755 318.18 ;
      RECT 86.545 316.66 86.615 318.18 ;
      RECT 75.48 316.87 75.55 318.18 ;
      RECT 16.655 316.87 16.725 318.18 ;
      RECT 16.515 316.87 16.585 318.18 ;
      RECT 5.535 316.66 5.605 318.18 ;
      RECT 5.395 316.66 5.465 318.18 ;
      RECT 75.565 311.39 75.635 312.95 ;
      RECT 75.425 311.39 75.495 312.95 ;
      RECT 16.655 311.31 16.725 312.65 ;
      RECT 16.515 311.31 16.585 312.65 ;
      RECT 0 311.39 92.2 312.62 ;
      RECT 86.685 311.1 86.755 312.62 ;
      RECT 86.545 311.1 86.615 312.62 ;
      RECT 75.49 311.31 75.56 312.62 ;
      RECT 5.535 311.1 5.605 312.62 ;
      RECT 5.395 311.1 5.465 312.62 ;
      RECT 16.655 305.83 16.725 307.39 ;
      RECT 16.515 305.83 16.585 307.39 ;
      RECT 86.685 305.54 86.755 307.1 ;
      RECT 86.545 305.54 86.615 307.1 ;
      RECT 5.535 305.54 5.605 307.1 ;
      RECT 5.395 305.54 5.465 307.1 ;
      RECT 75.565 305.75 75.635 307.07 ;
      RECT 75.425 305.75 75.495 307.07 ;
      RECT 0 305.83 92.2 307.06 ;
      RECT 16.6 305.75 16.67 307.06 ;
      RECT 75.565 300.27 75.635 301.83 ;
      RECT 75.425 300.27 75.495 301.83 ;
      RECT 16.655 300.27 16.725 301.83 ;
      RECT 16.515 300.27 16.585 301.83 ;
      RECT 0 300.27 92.2 301.5 ;
      RECT 86.65 299.98 86.72 301.5 ;
      RECT 75.48 300.19 75.55 301.5 ;
      RECT 16.61 300.19 16.68 301.5 ;
      RECT 5.44 299.98 5.51 301.5 ;
      RECT 75.565 294.71 75.635 296.27 ;
      RECT 75.425 294.71 75.495 296.27 ;
      RECT 0 294.71 92.2 295.94 ;
      RECT 86.685 294.42 86.755 295.94 ;
      RECT 86.545 294.42 86.615 295.94 ;
      RECT 75.49 294.63 75.56 295.94 ;
      RECT 16.655 294.63 16.725 295.94 ;
      RECT 16.515 294.63 16.585 295.94 ;
      RECT 5.45 294.42 5.52 295.94 ;
      RECT 75.5 289.07 75.57 290.77 ;
      RECT 16.655 289.07 16.725 290.42 ;
      RECT 16.515 289.07 16.585 290.42 ;
      RECT 0 289.15 92.2 290.38 ;
      RECT 86.685 288.86 86.755 290.38 ;
      RECT 86.545 288.86 86.615 290.38 ;
      RECT 5.535 288.86 5.605 290.38 ;
      RECT 5.395 288.86 5.465 290.38 ;
      RECT 16.655 283.59 16.725 285.15 ;
      RECT 16.515 283.59 16.585 285.15 ;
      RECT 5.535 283.3 5.605 284.84 ;
      RECT 5.395 283.3 5.465 284.84 ;
      RECT 0 283.59 92.2 284.82 ;
      RECT 86.65 283.3 86.72 284.82 ;
      RECT 75.565 283.51 75.635 284.82 ;
      RECT 75.425 283.51 75.495 284.82 ;
      RECT 16.61 283.51 16.68 284.82 ;
      RECT 16.655 278.03 16.725 279.59 ;
      RECT 16.515 278.03 16.585 279.59 ;
      RECT 75.565 277.95 75.635 279.29 ;
      RECT 75.425 277.95 75.495 279.29 ;
      RECT 0 278.03 92.2 279.26 ;
      RECT 86.66 277.74 86.73 279.26 ;
      RECT 16.62 277.95 16.69 279.26 ;
      RECT 5.45 277.74 5.52 279.26 ;
      RECT 75.565 272.47 75.635 274.03 ;
      RECT 75.425 272.47 75.495 274.03 ;
      RECT 0 272.47 92.2 273.7 ;
      RECT 86.67 272.18 86.74 273.7 ;
      RECT 75.5 272.39 75.57 273.7 ;
      RECT 16.655 272.39 16.725 273.7 ;
      RECT 16.515 272.39 16.585 273.7 ;
      RECT 5.46 272.18 5.53 273.7 ;
      RECT 75.565 266.91 75.635 268.47 ;
      RECT 75.425 266.91 75.495 268.47 ;
      RECT 16.655 266.83 16.725 268.16 ;
      RECT 16.515 266.83 16.585 268.16 ;
      RECT 0 266.91 92.2 268.14 ;
      RECT 86.685 266.62 86.755 268.14 ;
      RECT 86.545 266.62 86.615 268.14 ;
      RECT 75.51 266.83 75.58 268.14 ;
      RECT 5.535 266.62 5.605 268.14 ;
      RECT 5.395 266.62 5.465 268.14 ;
      RECT 16.655 261.35 16.725 262.91 ;
      RECT 16.515 261.35 16.585 262.91 ;
      RECT 86.685 261.06 86.755 262.61 ;
      RECT 86.545 261.06 86.615 262.61 ;
      RECT 5.535 261.06 5.605 262.61 ;
      RECT 5.395 261.06 5.465 262.61 ;
      RECT 0 261.35 92.2 262.58 ;
      RECT 75.565 261.27 75.635 262.58 ;
      RECT 75.425 261.27 75.495 262.58 ;
      RECT 16.62 261.27 16.69 262.58 ;
      RECT 16.655 255.79 16.725 257.35 ;
      RECT 16.515 255.79 16.585 257.35 ;
      RECT 75.565 255.71 75.635 257.06 ;
      RECT 75.425 255.71 75.495 257.06 ;
      RECT 0 255.79 92.2 257.02 ;
      RECT 86.67 255.5 86.74 257.02 ;
      RECT 16.63 255.71 16.7 257.02 ;
      RECT 5.46 255.5 5.53 257.02 ;
      RECT 75.565 250.23 75.635 251.79 ;
      RECT 75.425 250.23 75.495 251.79 ;
      RECT 0 250.23 92.2 251.46 ;
      RECT 86.685 249.94 86.755 251.46 ;
      RECT 86.545 249.94 86.615 251.46 ;
      RECT 75.51 250.15 75.58 251.46 ;
      RECT 16.655 250.15 16.725 251.46 ;
      RECT 16.515 250.15 16.585 251.46 ;
      RECT 5.47 249.94 5.54 251.46 ;
      RECT 75.565 244.67 75.635 246.23 ;
      RECT 75.425 244.67 75.495 246.23 ;
      RECT 16.655 244.59 16.725 245.93 ;
      RECT 16.515 244.59 16.585 245.93 ;
      RECT 0 244.67 92.2 245.9 ;
      RECT 86.685 244.38 86.755 245.9 ;
      RECT 86.545 244.38 86.615 245.9 ;
      RECT 75.52 244.59 75.59 245.9 ;
      RECT 5.535 244.38 5.605 245.9 ;
      RECT 5.395 244.38 5.465 245.9 ;
      RECT 16.655 239.11 16.725 240.67 ;
      RECT 16.515 239.11 16.585 240.67 ;
      RECT 86.685 238.82 86.755 240.38 ;
      RECT 86.545 238.82 86.615 240.38 ;
      RECT 5.535 238.82 5.605 240.35 ;
      RECT 5.395 238.82 5.465 240.35 ;
      RECT 0 239.11 92.2 240.34 ;
      RECT 75.565 239.03 75.635 240.34 ;
      RECT 75.425 239.03 75.495 240.34 ;
      RECT 16.63 239.03 16.7 240.34 ;
      RECT 16.655 233.55 16.725 235.11 ;
      RECT 16.515 233.55 16.585 235.11 ;
      RECT 75.565 233.47 75.635 234.8 ;
      RECT 75.425 233.47 75.495 234.8 ;
      RECT 0 233.55 92.2 234.78 ;
      RECT 86.68 233.26 86.75 234.78 ;
      RECT 16.64 233.47 16.71 234.78 ;
      RECT 5.47 233.26 5.54 234.78 ;
      RECT 16.65 227.91 16.72 229.61 ;
      RECT 75.565 227.99 75.635 229.55 ;
      RECT 75.425 227.99 75.495 229.55 ;
      RECT 0 227.99 92.2 229.22 ;
      RECT 86.69 227.7 86.76 229.22 ;
      RECT 86.55 227.7 86.62 229.22 ;
      RECT 75.52 227.91 75.59 229.22 ;
      RECT 5.48 227.7 5.55 229.22 ;
      RECT 75.565 222.43 75.635 223.99 ;
      RECT 75.425 222.43 75.495 223.99 ;
      RECT 16.655 222.35 16.725 223.67 ;
      RECT 16.515 222.35 16.585 223.67 ;
      RECT 0 222.43 92.2 223.66 ;
      RECT 86.685 222.14 86.755 223.66 ;
      RECT 86.545 222.14 86.615 223.66 ;
      RECT 75.53 222.35 75.6 223.66 ;
      RECT 5.535 222.14 5.605 223.66 ;
      RECT 5.395 222.14 5.465 223.66 ;
      RECT 16.655 216.87 16.725 218.43 ;
      RECT 16.515 216.87 16.585 218.43 ;
      RECT 86.685 216.58 86.755 218.12 ;
      RECT 86.545 216.58 86.615 218.12 ;
      RECT 5.535 216.58 5.605 218.12 ;
      RECT 5.395 216.58 5.465 218.12 ;
      RECT 0 216.87 92.2 218.1 ;
      RECT 75.565 216.79 75.635 218.1 ;
      RECT 75.425 216.79 75.495 218.1 ;
      RECT 16.64 216.79 16.71 218.1 ;
      RECT 16.655 211.31 16.725 212.87 ;
      RECT 16.515 211.31 16.585 212.87 ;
      RECT 75.565 211.23 75.635 212.57 ;
      RECT 75.425 211.23 75.495 212.57 ;
      RECT 0 211.31 92.2 212.54 ;
      RECT 86.69 211.02 86.76 212.54 ;
      RECT 86.55 211.02 86.62 212.54 ;
      RECT 16.65 211.23 16.72 212.54 ;
      RECT 5.48 211.02 5.55 212.54 ;
      RECT 75.565 205.75 75.635 207.31 ;
      RECT 75.425 205.75 75.495 207.31 ;
      RECT 0 205.75 92.2 206.98 ;
      RECT 86.7 205.46 86.77 206.98 ;
      RECT 86.56 205.46 86.63 206.98 ;
      RECT 75.53 205.67 75.6 206.98 ;
      RECT 16.655 205.67 16.725 206.98 ;
      RECT 16.515 205.67 16.585 206.98 ;
      RECT 5.49 205.46 5.56 206.98 ;
      RECT 75.565 200.19 75.635 201.75 ;
      RECT 75.425 200.19 75.495 201.75 ;
      RECT 16.655 200.11 16.725 201.44 ;
      RECT 16.515 200.11 16.585 201.44 ;
      RECT 0 200.19 92.2 201.42 ;
      RECT 86.685 199.9 86.755 201.42 ;
      RECT 86.545 199.9 86.615 201.42 ;
      RECT 75.54 200.11 75.61 201.42 ;
      RECT 5.535 199.9 5.605 201.42 ;
      RECT 5.395 199.9 5.465 201.42 ;
      RECT 16.655 194.63 16.725 196.19 ;
      RECT 16.515 194.63 16.585 196.19 ;
      RECT 86.685 194.34 86.755 195.89 ;
      RECT 86.545 194.34 86.615 195.89 ;
      RECT 0 194.63 92.2 195.86 ;
      RECT 75.565 194.55 75.635 195.86 ;
      RECT 75.425 194.55 75.495 195.86 ;
      RECT 16.65 194.55 16.72 195.86 ;
      RECT 5.535 194.34 5.605 195.86 ;
      RECT 5.395 194.34 5.465 195.86 ;
      RECT 16.655 189.07 16.725 190.63 ;
      RECT 16.515 189.07 16.585 190.63 ;
      RECT 75.565 188.99 75.635 190.34 ;
      RECT 75.425 188.99 75.495 190.34 ;
      RECT 0 189.07 92.2 190.3 ;
      RECT 86.7 188.78 86.77 190.3 ;
      RECT 86.56 188.78 86.63 190.3 ;
      RECT 16.66 188.99 16.73 190.3 ;
      RECT 16.52 188.99 16.59 190.3 ;
      RECT 5.49 188.78 5.56 190.3 ;
      RECT 16.67 183.43 16.74 185.13 ;
      RECT 16.53 183.43 16.6 185.13 ;
      RECT 75.565 183.51 75.635 185.07 ;
      RECT 75.425 183.51 75.495 185.07 ;
      RECT 0 183.51 92.2 184.74 ;
      RECT 86.57 183.22 86.64 184.74 ;
      RECT 75.54 183.43 75.61 184.74 ;
      RECT 5.5 183.22 5.57 184.74 ;
      RECT 75.565 177.95 75.635 179.51 ;
      RECT 75.425 177.95 75.495 179.51 ;
      RECT 0 177.95 92.2 179.18 ;
      RECT 86.685 177.66 86.755 179.18 ;
      RECT 86.545 177.66 86.615 179.18 ;
      RECT 75.55 177.87 75.62 179.18 ;
      RECT 16.655 177.87 16.725 179.18 ;
      RECT 16.515 177.87 16.585 179.18 ;
      RECT 5.535 177.66 5.605 179.18 ;
      RECT 5.395 177.66 5.465 179.18 ;
      RECT 16.655 172.31 16.725 174.01 ;
      RECT 16.515 172.31 16.585 174.01 ;
      RECT 86.545 172.1 86.615 173.63 ;
      RECT 5.535 172.1 5.605 173.63 ;
      RECT 5.395 172.1 5.465 173.63 ;
      RECT 0 172.39 92.2 173.62 ;
      RECT 86.685 172.1 86.755 173.62 ;
      RECT 75.565 172.31 75.635 173.62 ;
      RECT 75.425 172.31 75.495 173.62 ;
      RECT 16.655 166.83 16.725 168.39 ;
      RECT 16.515 166.83 16.585 168.39 ;
      RECT 75.565 166.75 75.635 168.08 ;
      RECT 75.425 166.75 75.495 168.08 ;
      RECT 0 166.83 92.2 168.06 ;
      RECT 86.57 166.54 86.64 168.06 ;
      RECT 16.67 166.75 16.74 168.06 ;
      RECT 16.53 166.75 16.6 168.06 ;
      RECT 5.5 166.54 5.57 168.06 ;
      RECT 75.565 161.27 75.635 162.83 ;
      RECT 75.425 161.27 75.495 162.83 ;
      RECT 16.655 161.27 16.725 162.83 ;
      RECT 16.515 161.27 16.585 162.83 ;
      RECT 0 161.27 92.2 162.5 ;
      RECT 86.58 160.98 86.65 162.5 ;
      RECT 75.55 161.19 75.62 162.5 ;
      RECT 16.54 161.19 16.61 162.5 ;
      RECT 5.51 160.98 5.58 162.5 ;
      RECT 75.565 155.71 75.635 157.27 ;
      RECT 75.425 155.71 75.495 157.27 ;
      RECT 16.655 155.63 16.725 156.95 ;
      RECT 16.515 155.63 16.585 156.95 ;
      RECT 0 155.71 92.2 156.94 ;
      RECT 86.685 155.42 86.755 156.94 ;
      RECT 86.545 155.42 86.615 156.94 ;
      RECT 75.56 155.63 75.63 156.94 ;
      RECT 5.535 155.42 5.605 156.94 ;
      RECT 5.395 155.42 5.465 156.94 ;
      RECT 16.655 150.15 16.725 151.71 ;
      RECT 16.515 150.15 16.585 151.71 ;
      RECT 86.685 149.86 86.755 151.4 ;
      RECT 86.545 149.86 86.615 151.4 ;
      RECT 0 150.15 92.2 151.38 ;
      RECT 75.565 150.07 75.635 151.38 ;
      RECT 75.425 150.07 75.495 151.38 ;
      RECT 16.67 150.07 16.74 151.38 ;
      RECT 16.53 150.07 16.6 151.38 ;
      RECT 5.535 149.86 5.605 151.38 ;
      RECT 5.395 149.86 5.465 151.38 ;
      RECT 16.655 144.59 16.725 146.15 ;
      RECT 16.515 144.59 16.585 146.15 ;
      RECT 75.565 144.51 75.635 145.85 ;
      RECT 75.425 144.51 75.495 145.85 ;
      RECT 0 144.59 92.2 145.82 ;
      RECT 86.58 144.3 86.65 145.82 ;
      RECT 16.54 144.51 16.61 145.82 ;
      RECT 5.51 144.3 5.58 145.82 ;
      RECT 16.55 138.95 16.62 140.65 ;
      RECT 75.565 139.03 75.635 140.59 ;
      RECT 75.425 139.03 75.495 140.59 ;
      RECT 0 139.03 92.2 140.26 ;
      RECT 86.59 138.74 86.66 140.26 ;
      RECT 75.56 138.95 75.63 140.26 ;
      RECT 5.52 138.74 5.59 140.26 ;
      RECT 75.565 133.47 75.635 135.03 ;
      RECT 75.425 133.47 75.495 135.03 ;
      RECT 0 133.47 92.2 134.7 ;
      RECT 86.685 133.18 86.755 134.7 ;
      RECT 86.545 133.18 86.615 134.7 ;
      RECT 75.57 133.39 75.64 134.7 ;
      RECT 75.43 133.39 75.5 134.7 ;
      RECT 16.655 133.39 16.725 134.7 ;
      RECT 16.515 133.39 16.585 134.7 ;
      RECT 5.535 133.18 5.605 134.7 ;
      RECT 5.395 133.18 5.465 134.7 ;
      RECT 75.58 127.83 75.65 129.53 ;
      RECT 75.44 127.83 75.51 129.53 ;
      RECT 16.655 127.83 16.725 129.17 ;
      RECT 16.515 127.83 16.585 129.17 ;
      RECT 0 127.91 92.2 129.14 ;
      RECT 86.685 127.62 86.755 129.14 ;
      RECT 86.545 127.62 86.615 129.14 ;
      RECT 5.535 127.62 5.605 129.14 ;
      RECT 5.395 127.62 5.465 129.14 ;
      RECT 16.655 122.35 16.725 123.91 ;
      RECT 16.515 122.35 16.585 123.91 ;
      RECT 5.535 122.06 5.605 123.62 ;
      RECT 5.395 122.06 5.465 123.62 ;
      RECT 75.565 122.27 75.635 123.59 ;
      RECT 75.425 122.27 75.495 123.59 ;
      RECT 0 122.35 92.2 123.58 ;
      RECT 86.59 122.06 86.66 123.58 ;
      RECT 16.55 122.27 16.62 123.58 ;
      RECT 75.565 116.79 75.635 118.35 ;
      RECT 75.425 116.79 75.495 118.35 ;
      RECT 16.655 116.79 16.725 118.35 ;
      RECT 16.515 116.79 16.585 118.35 ;
      RECT 0 116.79 92.2 118.02 ;
      RECT 86.6 116.5 86.67 118.02 ;
      RECT 75.57 116.71 75.64 118.02 ;
      RECT 75.43 116.71 75.5 118.02 ;
      RECT 16.56 116.71 16.63 118.02 ;
      RECT 5.53 116.5 5.6 118.02 ;
      RECT 75.565 111.23 75.635 112.79 ;
      RECT 75.425 111.23 75.495 112.79 ;
      RECT 0 111.23 92.2 112.46 ;
      RECT 86.685 110.94 86.755 112.46 ;
      RECT 86.545 110.94 86.615 112.46 ;
      RECT 75.58 111.15 75.65 112.46 ;
      RECT 75.44 111.15 75.51 112.46 ;
      RECT 16.655 111.15 16.725 112.46 ;
      RECT 16.515 111.15 16.585 112.46 ;
      RECT 5.535 110.94 5.605 112.46 ;
      RECT 5.395 110.94 5.465 112.46 ;
      RECT 16.655 105.59 16.725 106.94 ;
      RECT 16.515 105.59 16.585 106.94 ;
      RECT 86.685 105.38 86.755 106.91 ;
      RECT 86.545 105.38 86.615 106.91 ;
      RECT 0 105.67 92.2 106.9 ;
      RECT 75.565 105.59 75.635 106.9 ;
      RECT 75.425 105.59 75.495 106.9 ;
      RECT 5.535 105.38 5.605 106.9 ;
      RECT 5.395 105.38 5.465 106.9 ;
      RECT 16.655 100.11 16.725 101.67 ;
      RECT 16.515 100.11 16.585 101.67 ;
      RECT 75.565 100.03 75.635 101.36 ;
      RECT 75.425 100.03 75.495 101.36 ;
      RECT 0 100.11 92.2 101.34 ;
      RECT 86.6 99.82 86.67 101.34 ;
      RECT 16.56 100.03 16.63 101.34 ;
      RECT 5.53 99.82 5.6 101.34 ;
      RECT 75.565 94.55 75.635 96.11 ;
      RECT 75.425 94.55 75.495 96.11 ;
      RECT 16.655 94.55 16.725 96.11 ;
      RECT 16.515 94.55 16.585 96.11 ;
      RECT 0 94.55 92.2 95.78 ;
      RECT 86.61 94.26 86.68 95.78 ;
      RECT 75.58 94.47 75.65 95.78 ;
      RECT 75.44 94.47 75.51 95.78 ;
      RECT 16.57 94.47 16.64 95.78 ;
      RECT 5.54 94.26 5.61 95.78 ;
      RECT 5.4 94.26 5.47 95.78 ;
      RECT 75.565 88.99 75.635 90.55 ;
      RECT 75.425 88.99 75.495 90.55 ;
      RECT 0 88.99 92.2 90.22 ;
      RECT 86.685 88.7 86.755 90.22 ;
      RECT 86.545 88.7 86.615 90.22 ;
      RECT 75.45 88.91 75.52 90.22 ;
      RECT 16.655 88.91 16.725 90.22 ;
      RECT 16.515 88.91 16.585 90.22 ;
      RECT 5.535 88.7 5.605 90.22 ;
      RECT 5.395 88.7 5.465 90.22 ;
      RECT 75.46 83.35 75.53 85.05 ;
      RECT 16.655 83.35 16.725 84.68 ;
      RECT 16.515 83.35 16.585 84.68 ;
      RECT 0 83.43 92.2 84.66 ;
      RECT 86.685 83.14 86.755 84.66 ;
      RECT 86.545 83.14 86.615 84.66 ;
      RECT 5.535 83.14 5.605 84.66 ;
      RECT 5.395 83.14 5.465 84.66 ;
      RECT 16.655 77.87 16.725 79.43 ;
      RECT 16.515 77.87 16.585 79.43 ;
      RECT 5.535 77.58 5.605 79.13 ;
      RECT 5.395 77.58 5.465 79.13 ;
      RECT 0 77.87 92.2 79.1 ;
      RECT 86.61 77.58 86.68 79.1 ;
      RECT 75.565 77.79 75.635 79.1 ;
      RECT 75.425 77.79 75.495 79.1 ;
      RECT 16.57 77.79 16.64 79.1 ;
      RECT 16.655 72.31 16.725 73.87 ;
      RECT 16.515 72.31 16.585 73.87 ;
      RECT 75.565 72.23 75.635 73.58 ;
      RECT 75.425 72.23 75.495 73.58 ;
      RECT 0 72.31 92.2 73.54 ;
      RECT 86.62 72.02 86.69 73.54 ;
      RECT 16.58 72.23 16.65 73.54 ;
      RECT 5.55 72.02 5.62 73.54 ;
      RECT 5.41 72.02 5.48 73.54 ;
      RECT 75.565 66.75 75.635 68.31 ;
      RECT 75.425 66.75 75.495 68.31 ;
      RECT 0 66.75 92.2 67.98 ;
      RECT 86.685 66.46 86.755 67.98 ;
      RECT 86.545 66.46 86.615 67.98 ;
      RECT 75.46 66.67 75.53 67.98 ;
      RECT 16.655 66.67 16.725 67.98 ;
      RECT 16.515 66.67 16.585 67.98 ;
      RECT 5.535 66.46 5.605 67.98 ;
      RECT 5.395 66.46 5.465 67.98 ;
      RECT 75.565 61.19 75.635 62.75 ;
      RECT 75.425 61.19 75.495 62.75 ;
      RECT 16.655 61.11 16.725 62.45 ;
      RECT 16.515 61.11 16.585 62.45 ;
      RECT 0 61.19 92.2 62.42 ;
      RECT 86.685 60.9 86.755 62.42 ;
      RECT 86.545 60.9 86.615 62.42 ;
      RECT 75.47 61.11 75.54 62.42 ;
      RECT 5.535 60.9 5.605 62.42 ;
      RECT 5.395 60.9 5.465 62.42 ;
      RECT 16.655 55.63 16.725 57.19 ;
      RECT 16.515 55.63 16.585 57.19 ;
      RECT 86.685 55.34 86.755 56.9 ;
      RECT 86.545 55.34 86.615 56.9 ;
      RECT 5.535 55.34 5.605 56.9 ;
      RECT 5.395 55.34 5.465 56.9 ;
      RECT 75.565 55.55 75.635 56.87 ;
      RECT 75.425 55.55 75.495 56.87 ;
      RECT 0 55.63 92.2 56.86 ;
      RECT 16.58 55.55 16.65 56.86 ;
      RECT 75.565 50.07 75.635 51.63 ;
      RECT 75.425 50.07 75.495 51.63 ;
      RECT 16.655 50.07 16.725 51.63 ;
      RECT 16.515 50.07 16.585 51.63 ;
      RECT 0 50.07 92.2 51.3 ;
      RECT 86.63 49.78 86.7 51.3 ;
      RECT 75.46 49.99 75.53 51.3 ;
      RECT 16.59 49.99 16.66 51.3 ;
      RECT 5.42 49.78 5.49 51.3 ;
      RECT 75.565 44.51 75.635 46.07 ;
      RECT 75.425 44.51 75.495 46.07 ;
      RECT 0 44.51 92.2 45.74 ;
      RECT 86.685 44.22 86.755 45.74 ;
      RECT 86.545 44.22 86.615 45.74 ;
      RECT 75.47 44.43 75.54 45.74 ;
      RECT 16.655 44.43 16.725 45.74 ;
      RECT 16.515 44.43 16.585 45.74 ;
      RECT 5.535 44.22 5.605 45.74 ;
      RECT 5.395 44.22 5.465 45.74 ;
      RECT 75.48 38.87 75.55 40.57 ;
      RECT 16.655 38.87 16.725 40.22 ;
      RECT 16.515 38.87 16.585 40.22 ;
      RECT 0 38.95 92.2 40.18 ;
      RECT 86.685 38.66 86.755 40.18 ;
      RECT 86.545 38.66 86.615 40.18 ;
      RECT 5.535 38.66 5.605 40.18 ;
      RECT 5.395 38.66 5.465 40.18 ;
      RECT 16.655 33.39 16.725 34.95 ;
      RECT 16.515 33.39 16.585 34.95 ;
      RECT 5.535 33.1 5.605 34.64 ;
      RECT 5.395 33.1 5.465 34.64 ;
      RECT 0 33.39 92.2 34.62 ;
      RECT 86.63 33.1 86.7 34.62 ;
      RECT 75.565 33.31 75.635 34.62 ;
      RECT 75.425 33.31 75.495 34.62 ;
      RECT 16.59 33.31 16.66 34.62 ;
      RECT 16.655 21.98 16.725 29.42 ;
      RECT 16.515 21.98 16.585 29.42 ;
      RECT 75.565 27.53 75.635 29.09 ;
      RECT 75.425 27.53 75.495 29.09 ;
      RECT 0 27.83 92.2 29.06 ;
      RECT 80.485 22.27 92.2 29.06 ;
      RECT 0 22.27 70.595 29.06 ;
      RECT 75.565 22.27 75.635 23.83 ;
      RECT 75.425 22.27 75.495 23.83 ;
      RECT 0 22.27 92.2 23.5 ;
      RECT 86.685 22.15 86.755 29.06 ;
      RECT 86.545 22.15 86.615 29.06 ;
      RECT 75.48 21.98 75.55 23.5 ;
      RECT 5.535 22.15 5.605 29.06 ;
      RECT 5.395 22.15 5.465 29.06 ;
      RECT 16.655 16.42 16.725 17.96 ;
      RECT 16.515 16.42 16.585 17.96 ;
      RECT 0 16.71 92.2 17.94 ;
      RECT 86.685 16.59 86.755 17.94 ;
      RECT 86.545 16.59 86.615 17.94 ;
      RECT 75.565 16.42 75.635 17.94 ;
      RECT 75.425 16.42 75.495 17.94 ;
      RECT 5.535 16.59 5.605 17.94 ;
      RECT 5.395 16.59 5.465 17.94 ;
      RECT 86.685 11.03 86.755 12.41 ;
      RECT 86.545 11.03 86.615 12.41 ;
      RECT 5.535 11.03 5.605 12.41 ;
      RECT 5.395 11.03 5.465 12.41 ;
      RECT 0 11.15 92.2 12.38 ;
      RECT 75.565 10.86 75.635 12.38 ;
      RECT 75.425 10.86 75.495 12.38 ;
      RECT 16.6 10.86 16.67 12.38 ;
      RECT 86.7 5.47 86.77 7.17 ;
      RECT 86.56 5.47 86.63 7.17 ;
      RECT 75.565 5.3 75.635 6.86 ;
      RECT 75.425 5.3 75.495 6.86 ;
      RECT 5.535 5.47 5.605 6.835 ;
      RECT 5.395 5.47 5.465 6.835 ;
      RECT 0 5.59 92.2 6.82 ;
      RECT 16.61 5.3 16.68 6.82 ;
      RECT 86.69 0 86.76 1.405 ;
      RECT 86.55 0 86.62 1.405 ;
      RECT 5.48 0 5.55 1.405 ;
      RECT 0 0 92.2 1.26 ;
      RECT 81.885 4.855 91.435 5.275 ;
      RECT 81.885 10.415 91.435 10.835 ;
      RECT 81.885 15.975 91.435 16.395 ;
      RECT 81.885 21.535 91.435 21.955 ;
      RECT 81.885 29.335 91.435 29.755 ;
      RECT 81.885 34.895 91.435 35.315 ;
      RECT 81.885 40.455 91.435 40.875 ;
      RECT 81.885 46.015 91.435 46.435 ;
      RECT 81.885 51.575 91.435 51.995 ;
      RECT 81.885 57.135 91.435 57.555 ;
      RECT 81.885 62.695 91.435 63.115 ;
      RECT 81.885 68.255 91.435 68.675 ;
      RECT 81.885 73.815 91.435 74.235 ;
      RECT 81.885 79.375 91.435 79.795 ;
      RECT 81.885 84.935 91.435 85.355 ;
      RECT 81.885 90.495 91.435 90.915 ;
      RECT 81.885 96.055 91.435 96.475 ;
      RECT 81.885 101.615 91.435 102.035 ;
      RECT 81.885 107.175 91.435 107.595 ;
      RECT 81.885 112.735 91.435 113.155 ;
      RECT 81.885 118.295 91.435 118.715 ;
      RECT 81.885 123.855 91.435 124.275 ;
      RECT 81.885 129.415 91.435 129.835 ;
      RECT 81.885 134.975 91.435 135.395 ;
      RECT 81.885 140.535 91.435 140.955 ;
      RECT 81.885 146.095 91.435 146.515 ;
      RECT 81.885 151.655 91.435 152.075 ;
      RECT 81.885 157.215 91.435 157.635 ;
      RECT 81.885 162.775 91.435 163.195 ;
      RECT 81.885 168.335 91.435 168.755 ;
      RECT 81.885 173.895 91.435 174.315 ;
      RECT 81.885 179.455 91.435 179.875 ;
      RECT 81.885 185.015 91.435 185.435 ;
      RECT 81.885 190.575 91.435 190.995 ;
      RECT 81.885 196.135 91.435 196.555 ;
      RECT 81.885 201.695 91.435 202.115 ;
      RECT 81.885 207.255 91.435 207.675 ;
      RECT 81.885 212.815 91.435 213.235 ;
      RECT 81.885 218.375 91.435 218.795 ;
      RECT 81.885 223.935 91.435 224.355 ;
      RECT 81.885 229.495 91.435 229.915 ;
      RECT 81.885 235.055 91.435 235.475 ;
      RECT 81.885 240.615 91.435 241.035 ;
      RECT 81.885 246.175 91.435 246.595 ;
      RECT 81.885 251.735 91.435 252.155 ;
      RECT 81.885 257.295 91.435 257.715 ;
      RECT 81.885 262.855 91.435 263.275 ;
      RECT 81.885 268.415 91.435 268.835 ;
      RECT 81.885 273.975 91.435 274.395 ;
      RECT 81.885 279.535 91.435 279.955 ;
      RECT 81.885 285.095 91.435 285.515 ;
      RECT 81.885 290.655 91.435 291.075 ;
      RECT 81.885 296.215 91.435 296.635 ;
      RECT 81.885 301.775 91.435 302.195 ;
      RECT 81.885 307.335 91.435 307.755 ;
      RECT 81.885 312.895 91.435 313.315 ;
      RECT 81.885 318.455 91.435 318.875 ;
      RECT 81.885 324.015 91.435 324.435 ;
      RECT 81.885 329.575 91.435 329.995 ;
      RECT 81.885 335.135 91.435 335.555 ;
      RECT 81.885 340.695 91.435 341.115 ;
      RECT 86.7 7.27 86.77 7.62 ;
      RECT 86.7 7.72 86.77 8.07 ;
      RECT 86.7 8.17 86.77 8.52 ;
      RECT 86.7 8.62 86.77 8.97 ;
      RECT 86.7 9.07 86.77 9.42 ;
      RECT 86.7 9.52 86.77 9.87 ;
      RECT 86.7 185.63 86.77 185.98 ;
      RECT 86.7 186.08 86.77 186.43 ;
      RECT 86.7 186.53 86.77 186.88 ;
      RECT 86.7 186.98 86.77 187.33 ;
      RECT 86.7 187.43 86.77 187.78 ;
      RECT 86.7 187.88 86.77 188.23 ;
      RECT 86.7 188.33 86.77 188.68 ;
      RECT 86.7 202.31 86.77 202.66 ;
      RECT 86.7 202.76 86.77 203.11 ;
      RECT 86.7 203.21 86.77 203.56 ;
      RECT 86.7 203.66 86.77 204.01 ;
      RECT 86.7 204.11 86.77 204.46 ;
      RECT 86.7 204.56 86.77 204.91 ;
      RECT 86.7 205.01 86.77 205.36 ;
      RECT 86.69 1.505 86.76 1.855 ;
      RECT 86.69 1.955 86.76 2.305 ;
      RECT 86.69 2.405 86.76 2.755 ;
      RECT 86.69 2.855 86.76 3.205 ;
      RECT 86.69 3.305 86.76 3.655 ;
      RECT 86.69 3.755 86.76 4.105 ;
      RECT 86.69 4.205 86.76 4.555 ;
      RECT 86.69 207.87 86.76 208.22 ;
      RECT 86.69 208.32 86.76 208.67 ;
      RECT 86.69 208.77 86.76 209.12 ;
      RECT 86.69 209.22 86.76 209.57 ;
      RECT 86.69 209.67 86.76 210.02 ;
      RECT 86.69 210.12 86.76 210.47 ;
      RECT 86.69 210.57 86.76 210.92 ;
      RECT 86.69 224.55 86.76 224.9 ;
      RECT 86.69 225 86.76 225.35 ;
      RECT 86.69 225.45 86.76 225.8 ;
      RECT 86.69 225.9 86.76 226.25 ;
      RECT 86.69 226.35 86.76 226.7 ;
      RECT 86.69 226.8 86.76 227.15 ;
      RECT 86.69 227.25 86.76 227.6 ;
      RECT 86.685 12.51 86.755 12.86 ;
      RECT 86.685 12.96 86.755 13.31 ;
      RECT 86.685 13.41 86.755 13.76 ;
      RECT 86.685 13.86 86.755 14.21 ;
      RECT 86.685 14.31 86.755 14.66 ;
      RECT 86.685 14.76 86.755 15.11 ;
      RECT 86.685 15.21 86.755 15.56 ;
      RECT 86.685 18.03 86.755 18.38 ;
      RECT 86.685 18.48 86.755 18.83 ;
      RECT 86.685 18.93 86.755 19.28 ;
      RECT 86.685 19.38 86.755 19.73 ;
      RECT 86.685 19.83 86.755 20.18 ;
      RECT 86.685 20.28 86.755 20.63 ;
      RECT 86.685 20.73 86.755 21.08 ;
      RECT 86.685 35.51 86.755 35.86 ;
      RECT 86.685 35.96 86.755 36.31 ;
      RECT 86.685 36.41 86.755 36.76 ;
      RECT 86.685 36.86 86.755 37.21 ;
      RECT 86.685 37.31 86.755 37.66 ;
      RECT 86.685 37.76 86.755 38.11 ;
      RECT 86.685 38.21 86.755 38.56 ;
      RECT 86.685 41.07 86.755 41.42 ;
      RECT 86.685 41.52 86.755 41.87 ;
      RECT 86.685 41.97 86.755 42.32 ;
      RECT 86.685 42.42 86.755 42.77 ;
      RECT 86.685 42.87 86.755 43.22 ;
      RECT 86.685 43.32 86.755 43.67 ;
      RECT 86.685 43.77 86.755 44.12 ;
      RECT 86.685 52.19 86.755 52.54 ;
      RECT 86.685 52.64 86.755 52.99 ;
      RECT 86.685 53.09 86.755 53.44 ;
      RECT 86.685 53.54 86.755 53.89 ;
      RECT 86.685 53.99 86.755 54.34 ;
      RECT 86.685 54.44 86.755 54.79 ;
      RECT 86.685 54.89 86.755 55.24 ;
      RECT 86.685 57.75 86.755 58.1 ;
      RECT 86.685 58.2 86.755 58.55 ;
      RECT 86.685 58.65 86.755 59 ;
      RECT 86.685 59.1 86.755 59.45 ;
      RECT 86.685 59.55 86.755 59.9 ;
      RECT 86.685 60 86.755 60.35 ;
      RECT 86.685 60.45 86.755 60.8 ;
      RECT 86.685 63.31 86.755 63.66 ;
      RECT 86.685 63.76 86.755 64.11 ;
      RECT 86.685 64.21 86.755 64.56 ;
      RECT 86.685 64.66 86.755 65.01 ;
      RECT 86.685 65.11 86.755 65.46 ;
      RECT 86.685 65.56 86.755 65.91 ;
      RECT 86.685 66.01 86.755 66.36 ;
      RECT 86.685 79.99 86.755 80.34 ;
      RECT 86.685 80.44 86.755 80.79 ;
      RECT 86.685 80.89 86.755 81.24 ;
      RECT 86.685 81.34 86.755 81.69 ;
      RECT 86.685 81.79 86.755 82.14 ;
      RECT 86.685 82.24 86.755 82.59 ;
      RECT 86.685 82.69 86.755 83.04 ;
      RECT 86.685 85.55 86.755 85.9 ;
      RECT 86.685 86 86.755 86.35 ;
      RECT 86.685 86.45 86.755 86.8 ;
      RECT 86.685 86.9 86.755 87.25 ;
      RECT 86.685 87.35 86.755 87.7 ;
      RECT 86.685 87.8 86.755 88.15 ;
      RECT 86.685 88.25 86.755 88.6 ;
      RECT 86.685 102.23 86.755 102.58 ;
      RECT 86.685 102.68 86.755 103.03 ;
      RECT 86.685 103.13 86.755 103.48 ;
      RECT 86.685 103.58 86.755 103.93 ;
      RECT 86.685 104.03 86.755 104.38 ;
      RECT 86.685 104.48 86.755 104.83 ;
      RECT 86.685 104.93 86.755 105.28 ;
      RECT 86.685 107.79 86.755 108.14 ;
      RECT 86.685 108.24 86.755 108.59 ;
      RECT 86.685 108.69 86.755 109.04 ;
      RECT 86.685 109.14 86.755 109.49 ;
      RECT 86.685 109.59 86.755 109.94 ;
      RECT 86.685 110.04 86.755 110.39 ;
      RECT 86.685 110.49 86.755 110.84 ;
      RECT 86.685 124.47 86.755 124.82 ;
      RECT 86.685 124.92 86.755 125.27 ;
      RECT 86.685 125.37 86.755 125.72 ;
      RECT 86.685 125.82 86.755 126.17 ;
      RECT 86.685 126.27 86.755 126.62 ;
      RECT 86.685 126.72 86.755 127.07 ;
      RECT 86.685 127.17 86.755 127.52 ;
      RECT 86.685 130.03 86.755 130.38 ;
      RECT 86.685 130.48 86.755 130.83 ;
      RECT 86.685 130.93 86.755 131.28 ;
      RECT 86.685 131.38 86.755 131.73 ;
      RECT 86.685 131.83 86.755 132.18 ;
      RECT 86.685 132.28 86.755 132.63 ;
      RECT 86.685 132.73 86.755 133.08 ;
      RECT 86.685 146.71 86.755 147.06 ;
      RECT 86.685 147.16 86.755 147.51 ;
      RECT 86.685 147.61 86.755 147.96 ;
      RECT 86.685 148.06 86.755 148.41 ;
      RECT 86.685 148.51 86.755 148.86 ;
      RECT 86.685 148.96 86.755 149.31 ;
      RECT 86.685 149.41 86.755 149.76 ;
      RECT 86.685 152.27 86.755 152.62 ;
      RECT 86.685 152.72 86.755 153.07 ;
      RECT 86.685 153.17 86.755 153.52 ;
      RECT 86.685 153.62 86.755 153.97 ;
      RECT 86.685 154.07 86.755 154.42 ;
      RECT 86.685 154.52 86.755 154.87 ;
      RECT 86.685 154.97 86.755 155.32 ;
      RECT 86.685 168.95 86.755 169.3 ;
      RECT 86.685 169.4 86.755 169.75 ;
      RECT 86.685 169.85 86.755 170.2 ;
      RECT 86.685 170.3 86.755 170.65 ;
      RECT 86.685 170.75 86.755 171.1 ;
      RECT 86.685 171.2 86.755 171.55 ;
      RECT 86.685 171.65 86.755 172 ;
      RECT 86.685 174.51 86.755 174.86 ;
      RECT 86.685 174.96 86.755 175.31 ;
      RECT 86.685 175.41 86.755 175.76 ;
      RECT 86.685 175.86 86.755 176.21 ;
      RECT 86.685 176.31 86.755 176.66 ;
      RECT 86.685 176.76 86.755 177.11 ;
      RECT 86.685 177.21 86.755 177.56 ;
      RECT 86.685 191.19 86.755 191.54 ;
      RECT 86.685 191.64 86.755 191.99 ;
      RECT 86.685 192.09 86.755 192.44 ;
      RECT 86.685 192.54 86.755 192.89 ;
      RECT 86.685 192.99 86.755 193.34 ;
      RECT 86.685 193.44 86.755 193.79 ;
      RECT 86.685 193.89 86.755 194.24 ;
      RECT 86.685 196.75 86.755 197.1 ;
      RECT 86.685 197.2 86.755 197.55 ;
      RECT 86.685 197.65 86.755 198 ;
      RECT 86.685 198.1 86.755 198.45 ;
      RECT 86.685 198.55 86.755 198.9 ;
      RECT 86.685 199 86.755 199.35 ;
      RECT 86.685 199.45 86.755 199.8 ;
      RECT 86.685 213.43 86.755 213.78 ;
      RECT 86.685 213.88 86.755 214.23 ;
      RECT 86.685 214.33 86.755 214.68 ;
      RECT 86.685 214.78 86.755 215.13 ;
      RECT 86.685 215.23 86.755 215.58 ;
      RECT 86.685 215.68 86.755 216.03 ;
      RECT 86.685 216.13 86.755 216.48 ;
      RECT 86.685 218.99 86.755 219.34 ;
      RECT 86.685 219.44 86.755 219.79 ;
      RECT 86.685 219.89 86.755 220.24 ;
      RECT 86.685 220.34 86.755 220.69 ;
      RECT 86.685 220.79 86.755 221.14 ;
      RECT 86.685 221.24 86.755 221.59 ;
      RECT 86.685 221.69 86.755 222.04 ;
      RECT 86.685 235.67 86.755 236.02 ;
      RECT 86.685 236.12 86.755 236.47 ;
      RECT 86.685 236.57 86.755 236.92 ;
      RECT 86.685 237.02 86.755 237.37 ;
      RECT 86.685 237.47 86.755 237.82 ;
      RECT 86.685 237.92 86.755 238.27 ;
      RECT 86.685 238.37 86.755 238.72 ;
      RECT 86.685 241.23 86.755 241.58 ;
      RECT 86.685 241.68 86.755 242.03 ;
      RECT 86.685 242.13 86.755 242.48 ;
      RECT 86.685 242.58 86.755 242.93 ;
      RECT 86.685 243.03 86.755 243.38 ;
      RECT 86.685 243.48 86.755 243.83 ;
      RECT 86.685 243.93 86.755 244.28 ;
      RECT 86.685 246.79 86.755 247.14 ;
      RECT 86.685 247.24 86.755 247.59 ;
      RECT 86.685 247.69 86.755 248.04 ;
      RECT 86.685 248.14 86.755 248.49 ;
      RECT 86.685 248.59 86.755 248.94 ;
      RECT 86.685 249.04 86.755 249.39 ;
      RECT 86.685 249.49 86.755 249.84 ;
      RECT 86.685 257.91 86.755 258.26 ;
      RECT 86.685 258.36 86.755 258.71 ;
      RECT 86.685 258.81 86.755 259.16 ;
      RECT 86.685 259.26 86.755 259.61 ;
      RECT 86.685 259.71 86.755 260.06 ;
      RECT 86.685 260.16 86.755 260.51 ;
      RECT 86.685 260.61 86.755 260.96 ;
      RECT 86.685 263.47 86.755 263.82 ;
      RECT 86.685 263.92 86.755 264.27 ;
      RECT 86.685 264.37 86.755 264.72 ;
      RECT 86.685 264.82 86.755 265.17 ;
      RECT 86.685 265.27 86.755 265.62 ;
      RECT 86.685 265.72 86.755 266.07 ;
      RECT 86.685 266.17 86.755 266.52 ;
      RECT 86.685 285.71 86.755 286.06 ;
      RECT 86.685 286.16 86.755 286.51 ;
      RECT 86.685 286.61 86.755 286.96 ;
      RECT 86.685 287.06 86.755 287.41 ;
      RECT 86.685 287.51 86.755 287.86 ;
      RECT 86.685 287.96 86.755 288.31 ;
      RECT 86.685 288.41 86.755 288.76 ;
      RECT 86.685 291.27 86.755 291.62 ;
      RECT 86.685 291.72 86.755 292.07 ;
      RECT 86.685 292.17 86.755 292.52 ;
      RECT 86.685 292.62 86.755 292.97 ;
      RECT 86.685 293.07 86.755 293.42 ;
      RECT 86.685 293.52 86.755 293.87 ;
      RECT 86.685 293.97 86.755 294.32 ;
      RECT 86.685 302.39 86.755 302.74 ;
      RECT 86.685 302.84 86.755 303.19 ;
      RECT 86.685 303.29 86.755 303.64 ;
      RECT 86.685 303.74 86.755 304.09 ;
      RECT 86.685 304.19 86.755 304.54 ;
      RECT 86.685 304.64 86.755 304.99 ;
      RECT 86.685 305.09 86.755 305.44 ;
      RECT 86.685 307.95 86.755 308.3 ;
      RECT 86.685 308.4 86.755 308.75 ;
      RECT 86.685 308.85 86.755 309.2 ;
      RECT 86.685 309.3 86.755 309.65 ;
      RECT 86.685 309.75 86.755 310.1 ;
      RECT 86.685 310.2 86.755 310.55 ;
      RECT 86.685 310.65 86.755 311 ;
      RECT 86.685 313.51 86.755 313.86 ;
      RECT 86.685 313.96 86.755 314.31 ;
      RECT 86.685 314.41 86.755 314.76 ;
      RECT 86.685 314.86 86.755 315.21 ;
      RECT 86.685 315.31 86.755 315.66 ;
      RECT 86.685 315.76 86.755 316.11 ;
      RECT 86.685 316.21 86.755 316.56 ;
      RECT 86.685 330.19 86.755 330.54 ;
      RECT 86.685 330.64 86.755 330.99 ;
      RECT 86.685 331.09 86.755 331.44 ;
      RECT 86.685 331.54 86.755 331.89 ;
      RECT 86.685 331.99 86.755 332.34 ;
      RECT 86.685 332.44 86.755 332.79 ;
      RECT 86.685 332.89 86.755 333.24 ;
      RECT 86.685 335.75 86.755 336.1 ;
      RECT 86.685 336.2 86.755 336.55 ;
      RECT 86.685 336.65 86.755 337 ;
      RECT 86.685 337.1 86.755 337.45 ;
      RECT 86.685 337.55 86.755 337.9 ;
      RECT 86.685 338 86.755 338.35 ;
      RECT 86.685 338.45 86.755 338.8 ;
      RECT 86.685 341.31 86.755 341.66 ;
      RECT 86.685 341.76 86.755 342.11 ;
      RECT 86.685 342.21 86.755 342.56 ;
      RECT 86.685 342.66 86.755 343.01 ;
      RECT 86.685 343.11 86.755 343.46 ;
      RECT 86.685 343.56 86.755 343.91 ;
      RECT 86.685 344.01 86.755 344.36 ;
      RECT 86.68 230.11 86.75 230.46 ;
      RECT 86.68 230.56 86.75 230.91 ;
      RECT 86.68 231.01 86.75 231.36 ;
      RECT 86.68 231.46 86.75 231.81 ;
      RECT 86.68 231.91 86.75 232.26 ;
      RECT 86.68 232.36 86.75 232.71 ;
      RECT 86.68 232.81 86.75 233.16 ;
      RECT 86.67 252.35 86.74 252.7 ;
      RECT 86.67 252.8 86.74 253.15 ;
      RECT 86.67 253.25 86.74 253.6 ;
      RECT 86.67 253.7 86.74 254.05 ;
      RECT 86.67 254.15 86.74 254.5 ;
      RECT 86.67 254.6 86.74 254.95 ;
      RECT 86.67 255.05 86.74 255.4 ;
      RECT 86.67 269.03 86.74 269.38 ;
      RECT 86.67 269.48 86.74 269.83 ;
      RECT 86.67 269.93 86.74 270.28 ;
      RECT 86.67 270.38 86.74 270.73 ;
      RECT 86.67 270.83 86.74 271.18 ;
      RECT 86.67 271.28 86.74 271.63 ;
      RECT 86.67 271.73 86.74 272.08 ;
      RECT 86.66 274.59 86.73 274.94 ;
      RECT 86.66 275.04 86.73 275.39 ;
      RECT 86.66 275.49 86.73 275.84 ;
      RECT 86.66 275.94 86.73 276.29 ;
      RECT 86.66 276.39 86.73 276.74 ;
      RECT 86.66 276.84 86.73 277.19 ;
      RECT 86.66 277.29 86.73 277.64 ;
      RECT 86.65 280.15 86.72 280.5 ;
      RECT 86.65 280.6 86.72 280.95 ;
      RECT 86.65 281.05 86.72 281.4 ;
      RECT 86.65 281.5 86.72 281.85 ;
      RECT 86.65 281.95 86.72 282.3 ;
      RECT 86.65 282.4 86.72 282.75 ;
      RECT 86.65 282.85 86.72 283.2 ;
      RECT 86.65 296.83 86.72 297.18 ;
      RECT 86.65 297.28 86.72 297.63 ;
      RECT 86.65 297.73 86.72 298.08 ;
      RECT 86.65 298.18 86.72 298.53 ;
      RECT 86.65 298.63 86.72 298.98 ;
      RECT 86.65 299.08 86.72 299.43 ;
      RECT 86.65 299.53 86.72 299.88 ;
      RECT 86.64 319.07 86.71 319.42 ;
      RECT 86.64 319.52 86.71 319.87 ;
      RECT 86.64 319.97 86.71 320.32 ;
      RECT 86.64 320.42 86.71 320.77 ;
      RECT 86.64 320.87 86.71 321.22 ;
      RECT 86.64 321.32 86.71 321.67 ;
      RECT 86.64 321.77 86.71 322.12 ;
      RECT 86.63 29.95 86.7 30.3 ;
      RECT 86.63 30.4 86.7 30.75 ;
      RECT 86.63 30.85 86.7 31.2 ;
      RECT 86.63 31.3 86.7 31.65 ;
      RECT 86.63 31.75 86.7 32.1 ;
      RECT 86.63 32.2 86.7 32.55 ;
      RECT 86.63 32.65 86.7 33 ;
      RECT 86.63 46.63 86.7 46.98 ;
      RECT 86.63 47.08 86.7 47.43 ;
      RECT 86.63 47.53 86.7 47.88 ;
      RECT 86.63 47.98 86.7 48.33 ;
      RECT 86.63 48.43 86.7 48.78 ;
      RECT 86.63 48.88 86.7 49.23 ;
      RECT 86.63 49.33 86.7 49.68 ;
      RECT 86.63 324.63 86.7 324.98 ;
      RECT 86.63 325.08 86.7 325.43 ;
      RECT 86.63 325.53 86.7 325.88 ;
      RECT 86.63 325.98 86.7 326.33 ;
      RECT 86.63 326.43 86.7 326.78 ;
      RECT 86.63 326.88 86.7 327.23 ;
      RECT 86.63 327.33 86.7 327.68 ;
      RECT 86.62 68.87 86.69 69.22 ;
      RECT 86.62 69.32 86.69 69.67 ;
      RECT 86.62 69.77 86.69 70.12 ;
      RECT 86.62 70.22 86.69 70.57 ;
      RECT 86.62 70.67 86.69 71.02 ;
      RECT 86.62 71.12 86.69 71.47 ;
      RECT 86.62 71.57 86.69 71.92 ;
      RECT 86.61 74.43 86.68 74.78 ;
      RECT 86.61 74.88 86.68 75.23 ;
      RECT 86.61 75.33 86.68 75.68 ;
      RECT 86.61 75.78 86.68 76.13 ;
      RECT 86.61 76.23 86.68 76.58 ;
      RECT 86.61 76.68 86.68 77.03 ;
      RECT 86.61 77.13 86.68 77.48 ;
      RECT 86.61 91.11 86.68 91.46 ;
      RECT 86.61 91.56 86.68 91.91 ;
      RECT 86.61 92.01 86.68 92.36 ;
      RECT 86.61 92.46 86.68 92.81 ;
      RECT 86.61 92.91 86.68 93.26 ;
      RECT 86.61 93.36 86.68 93.71 ;
      RECT 86.61 93.81 86.68 94.16 ;
      RECT 86.6 96.67 86.67 97.02 ;
      RECT 86.6 97.12 86.67 97.47 ;
      RECT 86.6 97.57 86.67 97.92 ;
      RECT 86.6 98.02 86.67 98.37 ;
      RECT 86.6 98.47 86.67 98.82 ;
      RECT 86.6 98.92 86.67 99.27 ;
      RECT 86.6 99.37 86.67 99.72 ;
      RECT 86.6 113.35 86.67 113.7 ;
      RECT 86.6 113.8 86.67 114.15 ;
      RECT 86.6 114.25 86.67 114.6 ;
      RECT 86.6 114.7 86.67 115.05 ;
      RECT 86.6 115.15 86.67 115.5 ;
      RECT 86.6 115.6 86.67 115.95 ;
      RECT 86.6 116.05 86.67 116.4 ;
      RECT 86.59 118.91 86.66 119.26 ;
      RECT 86.59 119.36 86.66 119.71 ;
      RECT 86.59 119.81 86.66 120.16 ;
      RECT 86.59 120.26 86.66 120.61 ;
      RECT 86.59 120.71 86.66 121.06 ;
      RECT 86.59 121.16 86.66 121.51 ;
      RECT 86.59 121.61 86.66 121.96 ;
      RECT 86.59 135.59 86.66 135.94 ;
      RECT 86.59 136.04 86.66 136.39 ;
      RECT 86.59 136.49 86.66 136.84 ;
      RECT 86.59 136.94 86.66 137.29 ;
      RECT 86.59 137.39 86.66 137.74 ;
      RECT 86.59 137.84 86.66 138.19 ;
      RECT 86.59 138.29 86.66 138.64 ;
      RECT 86.58 141.15 86.65 141.5 ;
      RECT 86.58 141.6 86.65 141.95 ;
      RECT 86.58 142.05 86.65 142.4 ;
      RECT 86.58 142.5 86.65 142.85 ;
      RECT 86.58 142.95 86.65 143.3 ;
      RECT 86.58 143.4 86.65 143.75 ;
      RECT 86.58 143.85 86.65 144.2 ;
      RECT 86.58 157.83 86.65 158.18 ;
      RECT 86.58 158.28 86.65 158.63 ;
      RECT 86.58 158.73 86.65 159.08 ;
      RECT 86.58 159.18 86.65 159.53 ;
      RECT 86.58 159.63 86.65 159.98 ;
      RECT 86.58 160.08 86.65 160.43 ;
      RECT 86.58 160.53 86.65 160.88 ;
      RECT 86.57 163.39 86.64 163.74 ;
      RECT 86.57 163.84 86.64 164.19 ;
      RECT 86.57 164.29 86.64 164.64 ;
      RECT 86.57 164.74 86.64 165.09 ;
      RECT 86.57 165.19 86.64 165.54 ;
      RECT 86.57 165.64 86.64 165.99 ;
      RECT 86.57 166.09 86.64 166.44 ;
      RECT 86.57 180.07 86.64 180.42 ;
      RECT 86.57 180.52 86.64 180.87 ;
      RECT 86.57 180.97 86.64 181.32 ;
      RECT 86.57 181.42 86.64 181.77 ;
      RECT 86.57 181.87 86.64 182.22 ;
      RECT 86.57 182.32 86.64 182.67 ;
      RECT 86.57 182.77 86.64 183.12 ;
      RECT 86.56 7.27 86.63 7.62 ;
      RECT 86.56 7.72 86.63 8.07 ;
      RECT 86.56 8.17 86.63 8.52 ;
      RECT 86.56 8.62 86.63 8.97 ;
      RECT 86.56 9.07 86.63 9.42 ;
      RECT 86.56 9.52 86.63 9.87 ;
      RECT 86.56 185.63 86.63 185.98 ;
      RECT 86.56 186.08 86.63 186.43 ;
      RECT 86.56 186.53 86.63 186.88 ;
      RECT 86.56 186.98 86.63 187.33 ;
      RECT 86.56 187.43 86.63 187.78 ;
      RECT 86.56 187.88 86.63 188.23 ;
      RECT 86.56 188.33 86.63 188.68 ;
      RECT 86.56 202.31 86.63 202.66 ;
      RECT 86.56 202.76 86.63 203.11 ;
      RECT 86.56 203.21 86.63 203.56 ;
      RECT 86.56 203.66 86.63 204.01 ;
      RECT 86.56 204.11 86.63 204.46 ;
      RECT 86.56 204.56 86.63 204.91 ;
      RECT 86.56 205.01 86.63 205.36 ;
      RECT 86.55 1.505 86.62 1.855 ;
      RECT 86.55 1.955 86.62 2.305 ;
      RECT 86.55 2.405 86.62 2.755 ;
      RECT 86.55 2.855 86.62 3.205 ;
      RECT 86.55 3.305 86.62 3.655 ;
      RECT 86.55 3.755 86.62 4.105 ;
      RECT 86.55 4.205 86.62 4.555 ;
      RECT 86.55 207.87 86.62 208.22 ;
      RECT 86.55 208.32 86.62 208.67 ;
      RECT 86.55 208.77 86.62 209.12 ;
      RECT 86.55 209.22 86.62 209.57 ;
      RECT 86.55 209.67 86.62 210.02 ;
      RECT 86.55 210.12 86.62 210.47 ;
      RECT 86.55 210.57 86.62 210.92 ;
      RECT 86.55 224.55 86.62 224.9 ;
      RECT 86.55 225 86.62 225.35 ;
      RECT 86.55 225.45 86.62 225.8 ;
      RECT 86.55 225.9 86.62 226.25 ;
      RECT 86.55 226.35 86.62 226.7 ;
      RECT 86.55 226.8 86.62 227.15 ;
      RECT 86.55 227.25 86.62 227.6 ;
      RECT 86.545 12.51 86.615 12.86 ;
      RECT 86.545 12.96 86.615 13.31 ;
      RECT 86.545 13.41 86.615 13.76 ;
      RECT 86.545 13.86 86.615 14.21 ;
      RECT 86.545 14.31 86.615 14.66 ;
      RECT 86.545 14.76 86.615 15.11 ;
      RECT 86.545 15.21 86.615 15.56 ;
      RECT 86.545 18.03 86.615 18.38 ;
      RECT 86.545 18.48 86.615 18.83 ;
      RECT 86.545 18.93 86.615 19.28 ;
      RECT 86.545 19.38 86.615 19.73 ;
      RECT 86.545 19.83 86.615 20.18 ;
      RECT 86.545 20.28 86.615 20.63 ;
      RECT 86.545 20.73 86.615 21.08 ;
      RECT 86.545 35.51 86.615 35.86 ;
      RECT 86.545 35.96 86.615 36.31 ;
      RECT 86.545 36.41 86.615 36.76 ;
      RECT 86.545 36.86 86.615 37.21 ;
      RECT 86.545 37.31 86.615 37.66 ;
      RECT 86.545 37.76 86.615 38.11 ;
      RECT 86.545 38.21 86.615 38.56 ;
      RECT 86.545 41.07 86.615 41.42 ;
      RECT 86.545 41.52 86.615 41.87 ;
      RECT 86.545 41.97 86.615 42.32 ;
      RECT 86.545 42.42 86.615 42.77 ;
      RECT 86.545 42.87 86.615 43.22 ;
      RECT 86.545 43.32 86.615 43.67 ;
      RECT 86.545 43.77 86.615 44.12 ;
      RECT 86.545 52.19 86.615 52.54 ;
      RECT 86.545 52.64 86.615 52.99 ;
      RECT 86.545 53.09 86.615 53.44 ;
      RECT 86.545 53.54 86.615 53.89 ;
      RECT 86.545 53.99 86.615 54.34 ;
      RECT 86.545 54.44 86.615 54.79 ;
      RECT 86.545 54.89 86.615 55.24 ;
      RECT 86.545 57.75 86.615 58.1 ;
      RECT 86.545 58.2 86.615 58.55 ;
      RECT 86.545 58.65 86.615 59 ;
      RECT 86.545 59.1 86.615 59.45 ;
      RECT 86.545 59.55 86.615 59.9 ;
      RECT 86.545 60 86.615 60.35 ;
      RECT 86.545 60.45 86.615 60.8 ;
      RECT 86.545 63.31 86.615 63.66 ;
      RECT 86.545 63.76 86.615 64.11 ;
      RECT 86.545 64.21 86.615 64.56 ;
      RECT 86.545 64.66 86.615 65.01 ;
      RECT 86.545 65.11 86.615 65.46 ;
      RECT 86.545 65.56 86.615 65.91 ;
      RECT 86.545 66.01 86.615 66.36 ;
      RECT 86.545 79.99 86.615 80.34 ;
      RECT 86.545 80.44 86.615 80.79 ;
      RECT 86.545 80.89 86.615 81.24 ;
      RECT 86.545 81.34 86.615 81.69 ;
      RECT 86.545 81.79 86.615 82.14 ;
      RECT 86.545 82.24 86.615 82.59 ;
      RECT 86.545 82.69 86.615 83.04 ;
      RECT 86.545 85.55 86.615 85.9 ;
      RECT 86.545 86 86.615 86.35 ;
      RECT 86.545 86.45 86.615 86.8 ;
      RECT 86.545 86.9 86.615 87.25 ;
      RECT 86.545 87.35 86.615 87.7 ;
      RECT 86.545 87.8 86.615 88.15 ;
      RECT 86.545 88.25 86.615 88.6 ;
      RECT 86.545 102.23 86.615 102.58 ;
      RECT 86.545 102.68 86.615 103.03 ;
      RECT 86.545 103.13 86.615 103.48 ;
      RECT 86.545 103.58 86.615 103.93 ;
      RECT 86.545 104.03 86.615 104.38 ;
      RECT 86.545 104.48 86.615 104.83 ;
      RECT 86.545 104.93 86.615 105.28 ;
      RECT 86.545 107.79 86.615 108.14 ;
      RECT 86.545 108.24 86.615 108.59 ;
      RECT 86.545 108.69 86.615 109.04 ;
      RECT 86.545 109.14 86.615 109.49 ;
      RECT 86.545 109.59 86.615 109.94 ;
      RECT 86.545 110.04 86.615 110.39 ;
      RECT 86.545 110.49 86.615 110.84 ;
      RECT 86.545 124.47 86.615 124.82 ;
      RECT 86.545 124.92 86.615 125.27 ;
      RECT 86.545 125.37 86.615 125.72 ;
      RECT 86.545 125.82 86.615 126.17 ;
      RECT 86.545 126.27 86.615 126.62 ;
      RECT 86.545 126.72 86.615 127.07 ;
      RECT 86.545 127.17 86.615 127.52 ;
      RECT 86.545 130.03 86.615 130.38 ;
      RECT 86.545 130.48 86.615 130.83 ;
      RECT 86.545 130.93 86.615 131.28 ;
      RECT 86.545 131.38 86.615 131.73 ;
      RECT 86.545 131.83 86.615 132.18 ;
      RECT 86.545 132.28 86.615 132.63 ;
      RECT 86.545 132.73 86.615 133.08 ;
      RECT 86.545 146.71 86.615 147.06 ;
      RECT 86.545 147.16 86.615 147.51 ;
      RECT 86.545 147.61 86.615 147.96 ;
      RECT 86.545 148.06 86.615 148.41 ;
      RECT 86.545 148.51 86.615 148.86 ;
      RECT 86.545 148.96 86.615 149.31 ;
      RECT 86.545 149.41 86.615 149.76 ;
      RECT 86.545 152.27 86.615 152.62 ;
      RECT 86.545 152.72 86.615 153.07 ;
      RECT 86.545 153.17 86.615 153.52 ;
      RECT 86.545 153.62 86.615 153.97 ;
      RECT 86.545 154.07 86.615 154.42 ;
      RECT 86.545 154.52 86.615 154.87 ;
      RECT 86.545 154.97 86.615 155.32 ;
      RECT 86.545 168.95 86.615 169.3 ;
      RECT 86.545 169.4 86.615 169.75 ;
      RECT 86.545 169.85 86.615 170.2 ;
      RECT 86.545 170.3 86.615 170.65 ;
      RECT 86.545 170.75 86.615 171.1 ;
      RECT 86.545 171.2 86.615 171.55 ;
      RECT 86.545 171.65 86.615 172 ;
      RECT 86.545 174.51 86.615 174.86 ;
      RECT 86.545 174.96 86.615 175.31 ;
      RECT 86.545 175.41 86.615 175.76 ;
      RECT 86.545 175.86 86.615 176.21 ;
      RECT 86.545 176.31 86.615 176.66 ;
      RECT 86.545 176.76 86.615 177.11 ;
      RECT 86.545 177.21 86.615 177.56 ;
      RECT 86.545 191.19 86.615 191.54 ;
      RECT 86.545 191.64 86.615 191.99 ;
      RECT 86.545 192.09 86.615 192.44 ;
      RECT 86.545 192.54 86.615 192.89 ;
      RECT 86.545 192.99 86.615 193.34 ;
      RECT 86.545 193.44 86.615 193.79 ;
      RECT 86.545 193.89 86.615 194.24 ;
      RECT 86.545 196.75 86.615 197.1 ;
      RECT 86.545 197.2 86.615 197.55 ;
      RECT 86.545 197.65 86.615 198 ;
      RECT 86.545 198.1 86.615 198.45 ;
      RECT 86.545 198.55 86.615 198.9 ;
      RECT 86.545 199 86.615 199.35 ;
      RECT 86.545 199.45 86.615 199.8 ;
      RECT 86.545 213.43 86.615 213.78 ;
      RECT 86.545 213.88 86.615 214.23 ;
      RECT 86.545 214.33 86.615 214.68 ;
      RECT 86.545 214.78 86.615 215.13 ;
      RECT 86.545 215.23 86.615 215.58 ;
      RECT 86.545 215.68 86.615 216.03 ;
      RECT 86.545 216.13 86.615 216.48 ;
      RECT 86.545 218.99 86.615 219.34 ;
      RECT 86.545 219.44 86.615 219.79 ;
      RECT 86.545 219.89 86.615 220.24 ;
      RECT 86.545 220.34 86.615 220.69 ;
      RECT 86.545 220.79 86.615 221.14 ;
      RECT 86.545 221.24 86.615 221.59 ;
      RECT 86.545 221.69 86.615 222.04 ;
      RECT 86.545 235.67 86.615 236.02 ;
      RECT 86.545 236.12 86.615 236.47 ;
      RECT 86.545 236.57 86.615 236.92 ;
      RECT 86.545 237.02 86.615 237.37 ;
      RECT 86.545 237.47 86.615 237.82 ;
      RECT 86.545 237.92 86.615 238.27 ;
      RECT 86.545 238.37 86.615 238.72 ;
      RECT 86.545 241.23 86.615 241.58 ;
      RECT 86.545 241.68 86.615 242.03 ;
      RECT 86.545 242.13 86.615 242.48 ;
      RECT 86.545 242.58 86.615 242.93 ;
      RECT 86.545 243.03 86.615 243.38 ;
      RECT 86.545 243.48 86.615 243.83 ;
      RECT 86.545 243.93 86.615 244.28 ;
      RECT 86.545 246.79 86.615 247.14 ;
      RECT 86.545 247.24 86.615 247.59 ;
      RECT 86.545 247.69 86.615 248.04 ;
      RECT 86.545 248.14 86.615 248.49 ;
      RECT 86.545 248.59 86.615 248.94 ;
      RECT 86.545 249.04 86.615 249.39 ;
      RECT 86.545 249.49 86.615 249.84 ;
      RECT 86.545 257.91 86.615 258.26 ;
      RECT 86.545 258.36 86.615 258.71 ;
      RECT 86.545 258.81 86.615 259.16 ;
      RECT 86.545 259.26 86.615 259.61 ;
      RECT 86.545 259.71 86.615 260.06 ;
      RECT 86.545 260.16 86.615 260.51 ;
      RECT 86.545 260.61 86.615 260.96 ;
      RECT 86.545 263.47 86.615 263.82 ;
      RECT 86.545 263.92 86.615 264.27 ;
      RECT 86.545 264.37 86.615 264.72 ;
      RECT 86.545 264.82 86.615 265.17 ;
      RECT 86.545 265.27 86.615 265.62 ;
      RECT 86.545 265.72 86.615 266.07 ;
      RECT 86.545 266.17 86.615 266.52 ;
      RECT 86.545 285.71 86.615 286.06 ;
      RECT 86.545 286.16 86.615 286.51 ;
      RECT 86.545 286.61 86.615 286.96 ;
      RECT 86.545 287.06 86.615 287.41 ;
      RECT 86.545 287.51 86.615 287.86 ;
      RECT 86.545 287.96 86.615 288.31 ;
      RECT 86.545 288.41 86.615 288.76 ;
      RECT 86.545 291.27 86.615 291.62 ;
      RECT 86.545 291.72 86.615 292.07 ;
      RECT 86.545 292.17 86.615 292.52 ;
      RECT 86.545 292.62 86.615 292.97 ;
      RECT 86.545 293.07 86.615 293.42 ;
      RECT 86.545 293.52 86.615 293.87 ;
      RECT 86.545 293.97 86.615 294.32 ;
      RECT 86.545 302.39 86.615 302.74 ;
      RECT 86.545 302.84 86.615 303.19 ;
      RECT 86.545 303.29 86.615 303.64 ;
      RECT 86.545 303.74 86.615 304.09 ;
      RECT 86.545 304.19 86.615 304.54 ;
      RECT 86.545 304.64 86.615 304.99 ;
      RECT 86.545 305.09 86.615 305.44 ;
      RECT 86.545 307.95 86.615 308.3 ;
      RECT 86.545 308.4 86.615 308.75 ;
      RECT 86.545 308.85 86.615 309.2 ;
      RECT 86.545 309.3 86.615 309.65 ;
      RECT 86.545 309.75 86.615 310.1 ;
      RECT 86.545 310.2 86.615 310.55 ;
      RECT 86.545 310.65 86.615 311 ;
      RECT 86.545 313.51 86.615 313.86 ;
      RECT 86.545 313.96 86.615 314.31 ;
      RECT 86.545 314.41 86.615 314.76 ;
      RECT 86.545 314.86 86.615 315.21 ;
      RECT 86.545 315.31 86.615 315.66 ;
      RECT 86.545 315.76 86.615 316.11 ;
      RECT 86.545 316.21 86.615 316.56 ;
      RECT 86.545 330.19 86.615 330.54 ;
      RECT 86.545 330.64 86.615 330.99 ;
      RECT 86.545 331.09 86.615 331.44 ;
      RECT 86.545 331.54 86.615 331.89 ;
      RECT 86.545 331.99 86.615 332.34 ;
      RECT 86.545 332.44 86.615 332.79 ;
      RECT 86.545 332.89 86.615 333.24 ;
      RECT 86.545 335.75 86.615 336.1 ;
      RECT 86.545 336.2 86.615 336.55 ;
      RECT 86.545 336.65 86.615 337 ;
      RECT 86.545 337.1 86.615 337.45 ;
      RECT 86.545 337.55 86.615 337.9 ;
      RECT 86.545 338 86.615 338.35 ;
      RECT 86.545 338.45 86.615 338.8 ;
      RECT 86.545 341.31 86.615 341.66 ;
      RECT 86.545 341.76 86.615 342.11 ;
      RECT 86.545 342.21 86.615 342.56 ;
      RECT 86.545 342.66 86.615 343.01 ;
      RECT 86.545 343.11 86.615 343.46 ;
      RECT 86.545 343.56 86.615 343.91 ;
      RECT 86.545 344.01 86.615 344.36 ;
      RECT 70.765 1.535 80.315 1.955 ;
      RECT 70.765 7.095 80.315 7.515 ;
      RECT 70.765 12.655 80.315 13.075 ;
      RECT 70.765 18.215 80.315 18.635 ;
      RECT 70.765 32.695 80.315 33.115 ;
      RECT 70.765 38.255 80.315 38.675 ;
      RECT 70.765 43.815 80.315 44.235 ;
      RECT 70.765 49.375 80.315 49.795 ;
      RECT 70.765 54.935 80.315 55.355 ;
      RECT 70.765 60.495 80.315 60.915 ;
      RECT 70.765 66.055 80.315 66.475 ;
      RECT 70.765 71.615 80.315 72.035 ;
      RECT 70.765 77.175 80.315 77.595 ;
      RECT 70.765 82.735 80.315 83.155 ;
      RECT 70.765 88.295 80.315 88.715 ;
      RECT 70.765 93.855 80.315 94.275 ;
      RECT 70.765 99.415 80.315 99.835 ;
      RECT 70.765 104.975 80.315 105.395 ;
      RECT 70.765 110.535 80.315 110.955 ;
      RECT 70.765 116.095 80.315 116.515 ;
      RECT 70.765 121.655 80.315 122.075 ;
      RECT 70.765 127.215 80.315 127.635 ;
      RECT 70.765 132.775 80.315 133.195 ;
      RECT 70.765 138.335 80.315 138.755 ;
      RECT 70.765 143.895 80.315 144.315 ;
      RECT 70.765 149.455 80.315 149.875 ;
      RECT 70.765 155.015 80.315 155.435 ;
      RECT 70.765 160.575 80.315 160.995 ;
      RECT 70.765 166.135 80.315 166.555 ;
      RECT 70.765 171.695 80.315 172.115 ;
      RECT 70.765 177.255 80.315 177.675 ;
      RECT 70.765 182.815 80.315 183.235 ;
      RECT 70.765 188.375 80.315 188.795 ;
      RECT 70.765 193.935 80.315 194.355 ;
      RECT 70.765 199.495 80.315 199.915 ;
      RECT 70.765 205.055 80.315 205.475 ;
      RECT 70.765 210.615 80.315 211.035 ;
      RECT 70.765 216.175 80.315 216.595 ;
      RECT 70.765 221.735 80.315 222.155 ;
      RECT 70.765 227.295 80.315 227.715 ;
      RECT 70.765 232.855 80.315 233.275 ;
      RECT 70.765 238.415 80.315 238.835 ;
      RECT 70.765 243.975 80.315 244.395 ;
      RECT 70.765 249.535 80.315 249.955 ;
      RECT 70.765 255.095 80.315 255.515 ;
      RECT 70.765 260.655 80.315 261.075 ;
      RECT 70.765 266.215 80.315 266.635 ;
      RECT 70.765 271.775 80.315 272.195 ;
      RECT 70.765 277.335 80.315 277.755 ;
      RECT 70.765 282.895 80.315 283.315 ;
      RECT 70.765 288.455 80.315 288.875 ;
      RECT 70.765 294.015 80.315 294.435 ;
      RECT 70.765 299.575 80.315 299.995 ;
      RECT 70.765 305.135 80.315 305.555 ;
      RECT 70.765 310.695 80.315 311.115 ;
      RECT 70.765 316.255 80.315 316.675 ;
      RECT 70.765 321.815 80.315 322.235 ;
      RECT 70.765 327.375 80.315 327.795 ;
      RECT 70.765 332.935 80.315 333.355 ;
      RECT 70.765 338.495 80.315 338.915 ;
      RECT 70.765 344.055 80.315 344.475 ;
      RECT 75.58 129.63 75.65 129.98 ;
      RECT 75.58 130.08 75.65 130.43 ;
      RECT 75.58 130.53 75.65 130.88 ;
      RECT 75.58 130.98 75.65 131.33 ;
      RECT 75.58 131.43 75.65 131.78 ;
      RECT 75.58 131.88 75.65 132.23 ;
      RECT 75.565 2.15 75.635 2.5 ;
      RECT 75.565 2.6 75.635 2.95 ;
      RECT 75.565 3.05 75.635 3.4 ;
      RECT 75.565 3.5 75.635 3.85 ;
      RECT 75.565 3.95 75.635 4.3 ;
      RECT 75.565 4.4 75.635 4.75 ;
      RECT 75.565 4.85 75.635 5.2 ;
      RECT 75.565 7.71 75.635 8.06 ;
      RECT 75.565 8.16 75.635 8.51 ;
      RECT 75.565 8.61 75.635 8.96 ;
      RECT 75.565 9.06 75.635 9.41 ;
      RECT 75.565 9.51 75.635 9.86 ;
      RECT 75.565 9.96 75.635 10.31 ;
      RECT 75.565 10.41 75.635 10.76 ;
      RECT 75.565 13.27 75.635 13.62 ;
      RECT 75.565 13.72 75.635 14.07 ;
      RECT 75.565 14.17 75.635 14.52 ;
      RECT 75.565 14.62 75.635 14.97 ;
      RECT 75.565 15.07 75.635 15.42 ;
      RECT 75.565 15.52 75.635 15.87 ;
      RECT 75.565 15.97 75.635 16.32 ;
      RECT 75.565 23.93 75.635 24.28 ;
      RECT 75.565 24.38 75.635 24.73 ;
      RECT 75.565 24.83 75.635 25.18 ;
      RECT 75.565 25.28 75.635 25.63 ;
      RECT 75.565 25.73 75.635 26.08 ;
      RECT 75.565 26.18 75.635 26.53 ;
      RECT 75.565 26.63 75.635 26.98 ;
      RECT 75.565 27.08 75.635 27.43 ;
      RECT 75.565 29.19 75.635 29.54 ;
      RECT 75.565 29.64 75.635 29.99 ;
      RECT 75.565 30.09 75.635 30.44 ;
      RECT 75.565 30.54 75.635 30.89 ;
      RECT 75.565 30.99 75.635 31.34 ;
      RECT 75.565 31.44 75.635 31.79 ;
      RECT 75.565 31.89 75.635 32.24 ;
      RECT 75.565 34.71 75.635 35.06 ;
      RECT 75.565 35.16 75.635 35.51 ;
      RECT 75.565 35.61 75.635 35.96 ;
      RECT 75.565 36.06 75.635 36.41 ;
      RECT 75.565 36.51 75.635 36.86 ;
      RECT 75.565 36.96 75.635 37.31 ;
      RECT 75.565 37.41 75.635 37.76 ;
      RECT 75.565 46.17 75.635 46.52 ;
      RECT 75.565 46.62 75.635 46.97 ;
      RECT 75.565 47.07 75.635 47.42 ;
      RECT 75.565 47.52 75.635 47.87 ;
      RECT 75.565 47.97 75.635 48.32 ;
      RECT 75.565 48.42 75.635 48.77 ;
      RECT 75.565 51.73 75.635 52.08 ;
      RECT 75.565 52.18 75.635 52.53 ;
      RECT 75.565 52.63 75.635 52.98 ;
      RECT 75.565 53.08 75.635 53.43 ;
      RECT 75.565 53.53 75.635 53.88 ;
      RECT 75.565 53.98 75.635 54.33 ;
      RECT 75.565 56.97 75.635 57.32 ;
      RECT 75.565 57.42 75.635 57.77 ;
      RECT 75.565 57.87 75.635 58.22 ;
      RECT 75.565 58.32 75.635 58.67 ;
      RECT 75.565 58.77 75.635 59.12 ;
      RECT 75.565 59.22 75.635 59.57 ;
      RECT 75.565 59.67 75.635 60.02 ;
      RECT 75.565 62.85 75.635 63.2 ;
      RECT 75.565 63.3 75.635 63.65 ;
      RECT 75.565 63.75 75.635 64.1 ;
      RECT 75.565 64.2 75.635 64.55 ;
      RECT 75.565 64.65 75.635 65 ;
      RECT 75.565 65.1 75.635 65.45 ;
      RECT 75.565 68.41 75.635 68.76 ;
      RECT 75.565 68.86 75.635 69.21 ;
      RECT 75.565 69.31 75.635 69.66 ;
      RECT 75.565 69.76 75.635 70.11 ;
      RECT 75.565 70.21 75.635 70.56 ;
      RECT 75.565 70.66 75.635 71.01 ;
      RECT 75.565 73.68 75.635 74.03 ;
      RECT 75.565 74.13 75.635 74.48 ;
      RECT 75.565 74.58 75.635 74.93 ;
      RECT 75.565 75.03 75.635 75.38 ;
      RECT 75.565 75.48 75.635 75.83 ;
      RECT 75.565 75.93 75.635 76.28 ;
      RECT 75.565 76.38 75.635 76.73 ;
      RECT 75.565 79.2 75.635 79.55 ;
      RECT 75.565 79.65 75.635 80 ;
      RECT 75.565 80.1 75.635 80.45 ;
      RECT 75.565 80.55 75.635 80.9 ;
      RECT 75.565 81 75.635 81.35 ;
      RECT 75.565 81.45 75.635 81.8 ;
      RECT 75.565 81.9 75.635 82.25 ;
      RECT 75.565 90.65 75.635 91 ;
      RECT 75.565 91.1 75.635 91.45 ;
      RECT 75.565 91.55 75.635 91.9 ;
      RECT 75.565 92 75.635 92.35 ;
      RECT 75.565 92.45 75.635 92.8 ;
      RECT 75.565 92.9 75.635 93.25 ;
      RECT 75.565 96.21 75.635 96.56 ;
      RECT 75.565 96.66 75.635 97.01 ;
      RECT 75.565 97.11 75.635 97.46 ;
      RECT 75.565 97.56 75.635 97.91 ;
      RECT 75.565 98.01 75.635 98.36 ;
      RECT 75.565 98.46 75.635 98.81 ;
      RECT 75.565 101.46 75.635 101.81 ;
      RECT 75.565 101.91 75.635 102.26 ;
      RECT 75.565 102.36 75.635 102.71 ;
      RECT 75.565 102.81 75.635 103.16 ;
      RECT 75.565 103.26 75.635 103.61 ;
      RECT 75.565 103.71 75.635 104.06 ;
      RECT 75.565 104.16 75.635 104.51 ;
      RECT 75.565 106.95 75.635 107.3 ;
      RECT 75.565 107.4 75.635 107.75 ;
      RECT 75.565 107.85 75.635 108.2 ;
      RECT 75.565 108.3 75.635 108.65 ;
      RECT 75.565 108.75 75.635 109.1 ;
      RECT 75.565 109.2 75.635 109.55 ;
      RECT 75.565 109.65 75.635 110 ;
      RECT 75.565 112.89 75.635 113.24 ;
      RECT 75.565 113.34 75.635 113.69 ;
      RECT 75.565 113.79 75.635 114.14 ;
      RECT 75.565 114.24 75.635 114.59 ;
      RECT 75.565 114.69 75.635 115.04 ;
      RECT 75.565 115.14 75.635 115.49 ;
      RECT 75.565 118.45 75.635 118.8 ;
      RECT 75.565 118.9 75.635 119.25 ;
      RECT 75.565 119.35 75.635 119.7 ;
      RECT 75.565 119.8 75.635 120.15 ;
      RECT 75.565 120.25 75.635 120.6 ;
      RECT 75.565 120.7 75.635 121.05 ;
      RECT 75.565 123.69 75.635 124.04 ;
      RECT 75.565 124.14 75.635 124.49 ;
      RECT 75.565 124.59 75.635 124.94 ;
      RECT 75.565 125.04 75.635 125.39 ;
      RECT 75.565 125.49 75.635 125.84 ;
      RECT 75.565 125.94 75.635 126.29 ;
      RECT 75.565 126.39 75.635 126.74 ;
      RECT 75.565 135.13 75.635 135.48 ;
      RECT 75.565 135.58 75.635 135.93 ;
      RECT 75.565 136.03 75.635 136.38 ;
      RECT 75.565 136.48 75.635 136.83 ;
      RECT 75.565 136.93 75.635 137.28 ;
      RECT 75.565 137.38 75.635 137.73 ;
      RECT 75.565 140.69 75.635 141.04 ;
      RECT 75.565 141.14 75.635 141.49 ;
      RECT 75.565 141.59 75.635 141.94 ;
      RECT 75.565 142.04 75.635 142.39 ;
      RECT 75.565 142.49 75.635 142.84 ;
      RECT 75.565 142.94 75.635 143.29 ;
      RECT 75.565 145.95 75.635 146.3 ;
      RECT 75.565 146.4 75.635 146.75 ;
      RECT 75.565 146.85 75.635 147.2 ;
      RECT 75.565 147.3 75.635 147.65 ;
      RECT 75.565 147.75 75.635 148.1 ;
      RECT 75.565 148.2 75.635 148.55 ;
      RECT 75.565 148.65 75.635 149 ;
      RECT 75.565 151.44 75.635 151.79 ;
      RECT 75.565 151.89 75.635 152.24 ;
      RECT 75.565 152.34 75.635 152.69 ;
      RECT 75.565 152.79 75.635 153.14 ;
      RECT 75.565 153.24 75.635 153.59 ;
      RECT 75.565 153.69 75.635 154.04 ;
      RECT 75.565 154.14 75.635 154.49 ;
      RECT 75.565 157.37 75.635 157.72 ;
      RECT 75.565 157.82 75.635 158.17 ;
      RECT 75.565 158.27 75.635 158.62 ;
      RECT 75.565 158.72 75.635 159.07 ;
      RECT 75.565 159.17 75.635 159.52 ;
      RECT 75.565 159.62 75.635 159.97 ;
      RECT 75.565 162.93 75.635 163.28 ;
      RECT 75.565 163.38 75.635 163.73 ;
      RECT 75.565 163.83 75.635 164.18 ;
      RECT 75.565 164.28 75.635 164.63 ;
      RECT 75.565 164.73 75.635 165.08 ;
      RECT 75.565 165.18 75.635 165.53 ;
      RECT 75.565 168.18 75.635 168.53 ;
      RECT 75.565 168.63 75.635 168.98 ;
      RECT 75.565 169.08 75.635 169.43 ;
      RECT 75.565 169.53 75.635 169.88 ;
      RECT 75.565 169.98 75.635 170.33 ;
      RECT 75.565 170.43 75.635 170.78 ;
      RECT 75.565 170.88 75.635 171.23 ;
      RECT 75.565 173.67 75.635 174.02 ;
      RECT 75.565 174.12 75.635 174.47 ;
      RECT 75.565 174.57 75.635 174.92 ;
      RECT 75.565 175.02 75.635 175.37 ;
      RECT 75.565 175.47 75.635 175.82 ;
      RECT 75.565 175.92 75.635 176.27 ;
      RECT 75.565 176.37 75.635 176.72 ;
      RECT 75.565 179.61 75.635 179.96 ;
      RECT 75.565 180.06 75.635 180.41 ;
      RECT 75.565 180.51 75.635 180.86 ;
      RECT 75.565 180.96 75.635 181.31 ;
      RECT 75.565 181.41 75.635 181.76 ;
      RECT 75.565 181.86 75.635 182.21 ;
      RECT 75.565 185.17 75.635 185.52 ;
      RECT 75.565 185.62 75.635 185.97 ;
      RECT 75.565 186.07 75.635 186.42 ;
      RECT 75.565 186.52 75.635 186.87 ;
      RECT 75.565 186.97 75.635 187.32 ;
      RECT 75.565 187.42 75.635 187.77 ;
      RECT 75.565 190.44 75.635 190.79 ;
      RECT 75.565 190.89 75.635 191.24 ;
      RECT 75.565 191.34 75.635 191.69 ;
      RECT 75.565 191.79 75.635 192.14 ;
      RECT 75.565 192.24 75.635 192.59 ;
      RECT 75.565 192.69 75.635 193.04 ;
      RECT 75.565 193.14 75.635 193.49 ;
      RECT 75.565 195.93 75.635 196.28 ;
      RECT 75.565 196.38 75.635 196.73 ;
      RECT 75.565 196.83 75.635 197.18 ;
      RECT 75.565 197.28 75.635 197.63 ;
      RECT 75.565 197.73 75.635 198.08 ;
      RECT 75.565 198.18 75.635 198.53 ;
      RECT 75.565 198.63 75.635 198.98 ;
      RECT 75.565 201.85 75.635 202.2 ;
      RECT 75.565 202.3 75.635 202.65 ;
      RECT 75.565 202.75 75.635 203.1 ;
      RECT 75.565 203.2 75.635 203.55 ;
      RECT 75.565 203.65 75.635 204 ;
      RECT 75.565 204.1 75.635 204.45 ;
      RECT 75.565 207.41 75.635 207.76 ;
      RECT 75.565 207.86 75.635 208.21 ;
      RECT 75.565 208.31 75.635 208.66 ;
      RECT 75.565 208.76 75.635 209.11 ;
      RECT 75.565 209.21 75.635 209.56 ;
      RECT 75.565 209.66 75.635 210.01 ;
      RECT 75.565 212.67 75.635 213.02 ;
      RECT 75.565 213.12 75.635 213.47 ;
      RECT 75.565 213.57 75.635 213.92 ;
      RECT 75.565 214.02 75.635 214.37 ;
      RECT 75.565 214.47 75.635 214.82 ;
      RECT 75.565 214.92 75.635 215.27 ;
      RECT 75.565 215.37 75.635 215.72 ;
      RECT 75.565 218.16 75.635 218.51 ;
      RECT 75.565 218.61 75.635 218.96 ;
      RECT 75.565 219.06 75.635 219.41 ;
      RECT 75.565 219.51 75.635 219.86 ;
      RECT 75.565 219.96 75.635 220.31 ;
      RECT 75.565 220.41 75.635 220.76 ;
      RECT 75.565 220.86 75.635 221.21 ;
      RECT 75.565 224.09 75.635 224.44 ;
      RECT 75.565 224.54 75.635 224.89 ;
      RECT 75.565 224.99 75.635 225.34 ;
      RECT 75.565 225.44 75.635 225.79 ;
      RECT 75.565 225.89 75.635 226.24 ;
      RECT 75.565 226.34 75.635 226.69 ;
      RECT 75.565 229.65 75.635 230 ;
      RECT 75.565 230.1 75.635 230.45 ;
      RECT 75.565 230.55 75.635 230.9 ;
      RECT 75.565 231 75.635 231.35 ;
      RECT 75.565 231.45 75.635 231.8 ;
      RECT 75.565 231.9 75.635 232.25 ;
      RECT 75.565 234.9 75.635 235.25 ;
      RECT 75.565 235.35 75.635 235.7 ;
      RECT 75.565 235.8 75.635 236.15 ;
      RECT 75.565 236.25 75.635 236.6 ;
      RECT 75.565 236.7 75.635 237.05 ;
      RECT 75.565 237.15 75.635 237.5 ;
      RECT 75.565 237.6 75.635 237.95 ;
      RECT 75.565 240.42 75.635 240.77 ;
      RECT 75.565 240.87 75.635 241.22 ;
      RECT 75.565 241.32 75.635 241.67 ;
      RECT 75.565 241.77 75.635 242.12 ;
      RECT 75.565 242.22 75.635 242.57 ;
      RECT 75.565 242.67 75.635 243.02 ;
      RECT 75.565 243.12 75.635 243.47 ;
      RECT 75.565 246.33 75.635 246.68 ;
      RECT 75.565 246.78 75.635 247.13 ;
      RECT 75.565 247.23 75.635 247.58 ;
      RECT 75.565 247.68 75.635 248.03 ;
      RECT 75.565 248.13 75.635 248.48 ;
      RECT 75.565 248.58 75.635 248.93 ;
      RECT 75.565 251.89 75.635 252.24 ;
      RECT 75.565 252.34 75.635 252.69 ;
      RECT 75.565 252.79 75.635 253.14 ;
      RECT 75.565 253.24 75.635 253.59 ;
      RECT 75.565 253.69 75.635 254.04 ;
      RECT 75.565 254.14 75.635 254.49 ;
      RECT 75.565 257.16 75.635 257.51 ;
      RECT 75.565 257.61 75.635 257.96 ;
      RECT 75.565 258.06 75.635 258.41 ;
      RECT 75.565 258.51 75.635 258.86 ;
      RECT 75.565 258.96 75.635 259.31 ;
      RECT 75.565 259.41 75.635 259.76 ;
      RECT 75.565 259.86 75.635 260.21 ;
      RECT 75.565 262.68 75.635 263.03 ;
      RECT 75.565 263.13 75.635 263.48 ;
      RECT 75.565 263.58 75.635 263.93 ;
      RECT 75.565 264.03 75.635 264.38 ;
      RECT 75.565 264.48 75.635 264.83 ;
      RECT 75.565 264.93 75.635 265.28 ;
      RECT 75.565 265.38 75.635 265.73 ;
      RECT 75.565 268.57 75.635 268.92 ;
      RECT 75.565 269.02 75.635 269.37 ;
      RECT 75.565 269.47 75.635 269.82 ;
      RECT 75.565 269.92 75.635 270.27 ;
      RECT 75.565 270.37 75.635 270.72 ;
      RECT 75.565 270.82 75.635 271.17 ;
      RECT 75.565 274.13 75.635 274.48 ;
      RECT 75.565 274.58 75.635 274.93 ;
      RECT 75.565 275.03 75.635 275.38 ;
      RECT 75.565 275.48 75.635 275.83 ;
      RECT 75.565 275.93 75.635 276.28 ;
      RECT 75.565 276.38 75.635 276.73 ;
      RECT 75.565 279.39 75.635 279.74 ;
      RECT 75.565 279.84 75.635 280.19 ;
      RECT 75.565 280.29 75.635 280.64 ;
      RECT 75.565 280.74 75.635 281.09 ;
      RECT 75.565 281.19 75.635 281.54 ;
      RECT 75.565 281.64 75.635 281.99 ;
      RECT 75.565 282.09 75.635 282.44 ;
      RECT 75.565 284.91 75.635 285.26 ;
      RECT 75.565 285.36 75.635 285.71 ;
      RECT 75.565 285.81 75.635 286.16 ;
      RECT 75.565 286.26 75.635 286.61 ;
      RECT 75.565 286.71 75.635 287.06 ;
      RECT 75.565 287.16 75.635 287.51 ;
      RECT 75.565 287.61 75.635 287.96 ;
      RECT 75.565 296.37 75.635 296.72 ;
      RECT 75.565 296.82 75.635 297.17 ;
      RECT 75.565 297.27 75.635 297.62 ;
      RECT 75.565 297.72 75.635 298.07 ;
      RECT 75.565 298.17 75.635 298.52 ;
      RECT 75.565 298.62 75.635 298.97 ;
      RECT 75.565 301.93 75.635 302.28 ;
      RECT 75.565 302.38 75.635 302.73 ;
      RECT 75.565 302.83 75.635 303.18 ;
      RECT 75.565 303.28 75.635 303.63 ;
      RECT 75.565 303.73 75.635 304.08 ;
      RECT 75.565 304.18 75.635 304.53 ;
      RECT 75.565 307.17 75.635 307.52 ;
      RECT 75.565 307.62 75.635 307.97 ;
      RECT 75.565 308.07 75.635 308.42 ;
      RECT 75.565 308.52 75.635 308.87 ;
      RECT 75.565 308.97 75.635 309.32 ;
      RECT 75.565 309.42 75.635 309.77 ;
      RECT 75.565 309.87 75.635 310.22 ;
      RECT 75.565 313.05 75.635 313.4 ;
      RECT 75.565 313.5 75.635 313.85 ;
      RECT 75.565 313.95 75.635 314.3 ;
      RECT 75.565 314.4 75.635 314.75 ;
      RECT 75.565 314.85 75.635 315.2 ;
      RECT 75.565 315.3 75.635 315.65 ;
      RECT 75.565 318.61 75.635 318.96 ;
      RECT 75.565 319.06 75.635 319.41 ;
      RECT 75.565 319.51 75.635 319.86 ;
      RECT 75.565 319.96 75.635 320.31 ;
      RECT 75.565 320.41 75.635 320.76 ;
      RECT 75.565 320.86 75.635 321.21 ;
      RECT 75.565 323.88 75.635 324.23 ;
      RECT 75.565 324.33 75.635 324.68 ;
      RECT 75.565 324.78 75.635 325.13 ;
      RECT 75.565 325.23 75.635 325.58 ;
      RECT 75.565 325.68 75.635 326.03 ;
      RECT 75.565 326.13 75.635 326.48 ;
      RECT 75.565 326.58 75.635 326.93 ;
      RECT 75.565 329.4 75.635 329.75 ;
      RECT 75.565 329.85 75.635 330.2 ;
      RECT 75.565 330.3 75.635 330.65 ;
      RECT 75.565 330.75 75.635 331.1 ;
      RECT 75.565 331.2 75.635 331.55 ;
      RECT 75.565 331.65 75.635 332 ;
      RECT 75.565 332.1 75.635 332.45 ;
      RECT 75.565 340.85 75.635 341.2 ;
      RECT 75.565 341.3 75.635 341.65 ;
      RECT 75.565 341.75 75.635 342.1 ;
      RECT 75.565 342.2 75.635 342.55 ;
      RECT 75.565 342.65 75.635 343 ;
      RECT 75.565 343.1 75.635 343.45 ;
      RECT 75.5 290.87 75.57 291.22 ;
      RECT 75.5 291.32 75.57 291.67 ;
      RECT 75.5 291.77 75.57 292.12 ;
      RECT 75.5 292.22 75.57 292.57 ;
      RECT 75.5 292.67 75.57 293.02 ;
      RECT 75.5 293.12 75.57 293.47 ;
      RECT 75.48 18.83 75.55 19.18 ;
      RECT 75.48 19.28 75.55 19.63 ;
      RECT 75.48 19.73 75.55 20.08 ;
      RECT 75.48 20.18 75.55 20.53 ;
      RECT 75.48 20.63 75.55 20.98 ;
      RECT 75.48 21.08 75.55 21.43 ;
      RECT 75.48 21.53 75.55 21.88 ;
      RECT 75.48 40.67 75.55 41.02 ;
      RECT 75.48 41.12 75.55 41.47 ;
      RECT 75.48 41.57 75.55 41.92 ;
      RECT 75.48 42.02 75.55 42.37 ;
      RECT 75.48 42.47 75.55 42.82 ;
      RECT 75.48 42.92 75.55 43.27 ;
      RECT 75.48 335.35 75.55 335.7 ;
      RECT 75.48 335.8 75.55 336.15 ;
      RECT 75.48 336.25 75.55 336.6 ;
      RECT 75.48 336.7 75.55 337.05 ;
      RECT 75.48 337.15 75.55 337.5 ;
      RECT 75.48 337.6 75.55 337.95 ;
      RECT 75.46 85.15 75.53 85.5 ;
      RECT 75.46 85.6 75.53 85.95 ;
      RECT 75.46 86.05 75.53 86.4 ;
      RECT 75.46 86.5 75.53 86.85 ;
      RECT 75.46 86.95 75.53 87.3 ;
      RECT 75.46 87.4 75.53 87.75 ;
      RECT 75.44 129.63 75.51 129.98 ;
      RECT 75.44 130.08 75.51 130.43 ;
      RECT 75.44 130.53 75.51 130.88 ;
      RECT 75.44 130.98 75.51 131.33 ;
      RECT 75.44 131.43 75.51 131.78 ;
      RECT 75.44 131.88 75.51 132.23 ;
      RECT 75.425 2.15 75.495 2.5 ;
      RECT 75.425 2.6 75.495 2.95 ;
      RECT 75.425 3.05 75.495 3.4 ;
      RECT 75.425 3.5 75.495 3.85 ;
      RECT 75.425 3.95 75.495 4.3 ;
      RECT 75.425 4.4 75.495 4.75 ;
      RECT 75.425 4.85 75.495 5.2 ;
      RECT 75.425 7.71 75.495 8.06 ;
      RECT 75.425 8.16 75.495 8.51 ;
      RECT 75.425 8.61 75.495 8.96 ;
      RECT 75.425 9.06 75.495 9.41 ;
      RECT 75.425 9.51 75.495 9.86 ;
      RECT 75.425 9.96 75.495 10.31 ;
      RECT 75.425 10.41 75.495 10.76 ;
      RECT 75.425 13.27 75.495 13.62 ;
      RECT 75.425 13.72 75.495 14.07 ;
      RECT 75.425 14.17 75.495 14.52 ;
      RECT 75.425 14.62 75.495 14.97 ;
      RECT 75.425 15.07 75.495 15.42 ;
      RECT 75.425 15.52 75.495 15.87 ;
      RECT 75.425 15.97 75.495 16.32 ;
      RECT 75.425 23.93 75.495 24.28 ;
      RECT 75.425 24.38 75.495 24.73 ;
      RECT 75.425 24.83 75.495 25.18 ;
      RECT 75.425 25.28 75.495 25.63 ;
      RECT 75.425 25.73 75.495 26.08 ;
      RECT 75.425 26.18 75.495 26.53 ;
      RECT 75.425 26.63 75.495 26.98 ;
      RECT 75.425 27.08 75.495 27.43 ;
      RECT 75.425 29.19 75.495 29.54 ;
      RECT 75.425 29.64 75.495 29.99 ;
      RECT 75.425 30.09 75.495 30.44 ;
      RECT 75.425 30.54 75.495 30.89 ;
      RECT 75.425 30.99 75.495 31.34 ;
      RECT 75.425 31.44 75.495 31.79 ;
      RECT 75.425 31.89 75.495 32.24 ;
      RECT 75.425 34.71 75.495 35.06 ;
      RECT 75.425 35.16 75.495 35.51 ;
      RECT 75.425 35.61 75.495 35.96 ;
      RECT 75.425 36.06 75.495 36.41 ;
      RECT 75.425 36.51 75.495 36.86 ;
      RECT 75.425 36.96 75.495 37.31 ;
      RECT 75.425 37.41 75.495 37.76 ;
      RECT 75.425 46.17 75.495 46.52 ;
      RECT 75.425 46.62 75.495 46.97 ;
      RECT 75.425 47.07 75.495 47.42 ;
      RECT 75.425 47.52 75.495 47.87 ;
      RECT 75.425 47.97 75.495 48.32 ;
      RECT 75.425 48.42 75.495 48.77 ;
      RECT 75.425 51.73 75.495 52.08 ;
      RECT 75.425 52.18 75.495 52.53 ;
      RECT 75.425 52.63 75.495 52.98 ;
      RECT 75.425 53.08 75.495 53.43 ;
      RECT 75.425 53.53 75.495 53.88 ;
      RECT 75.425 53.98 75.495 54.33 ;
      RECT 75.425 56.97 75.495 57.32 ;
      RECT 75.425 57.42 75.495 57.77 ;
      RECT 75.425 57.87 75.495 58.22 ;
      RECT 75.425 58.32 75.495 58.67 ;
      RECT 75.425 58.77 75.495 59.12 ;
      RECT 75.425 59.22 75.495 59.57 ;
      RECT 75.425 59.67 75.495 60.02 ;
      RECT 75.425 62.85 75.495 63.2 ;
      RECT 75.425 63.3 75.495 63.65 ;
      RECT 75.425 63.75 75.495 64.1 ;
      RECT 75.425 64.2 75.495 64.55 ;
      RECT 75.425 64.65 75.495 65 ;
      RECT 75.425 65.1 75.495 65.45 ;
      RECT 75.425 68.41 75.495 68.76 ;
      RECT 75.425 68.86 75.495 69.21 ;
      RECT 75.425 69.31 75.495 69.66 ;
      RECT 75.425 69.76 75.495 70.11 ;
      RECT 75.425 70.21 75.495 70.56 ;
      RECT 75.425 70.66 75.495 71.01 ;
      RECT 75.425 73.68 75.495 74.03 ;
      RECT 75.425 74.13 75.495 74.48 ;
      RECT 75.425 74.58 75.495 74.93 ;
      RECT 75.425 75.03 75.495 75.38 ;
      RECT 75.425 75.48 75.495 75.83 ;
      RECT 75.425 75.93 75.495 76.28 ;
      RECT 75.425 76.38 75.495 76.73 ;
      RECT 75.425 79.2 75.495 79.55 ;
      RECT 75.425 79.65 75.495 80 ;
      RECT 75.425 80.1 75.495 80.45 ;
      RECT 75.425 80.55 75.495 80.9 ;
      RECT 75.425 81 75.495 81.35 ;
      RECT 75.425 81.45 75.495 81.8 ;
      RECT 75.425 81.9 75.495 82.25 ;
      RECT 75.425 90.65 75.495 91 ;
      RECT 75.425 91.1 75.495 91.45 ;
      RECT 75.425 91.55 75.495 91.9 ;
      RECT 75.425 92 75.495 92.35 ;
      RECT 75.425 92.45 75.495 92.8 ;
      RECT 75.425 92.9 75.495 93.25 ;
      RECT 75.425 96.21 75.495 96.56 ;
      RECT 75.425 96.66 75.495 97.01 ;
      RECT 75.425 97.11 75.495 97.46 ;
      RECT 75.425 97.56 75.495 97.91 ;
      RECT 75.425 98.01 75.495 98.36 ;
      RECT 75.425 98.46 75.495 98.81 ;
      RECT 75.425 101.46 75.495 101.81 ;
      RECT 75.425 101.91 75.495 102.26 ;
      RECT 75.425 102.36 75.495 102.71 ;
      RECT 75.425 102.81 75.495 103.16 ;
      RECT 75.425 103.26 75.495 103.61 ;
      RECT 75.425 103.71 75.495 104.06 ;
      RECT 75.425 104.16 75.495 104.51 ;
      RECT 75.425 106.95 75.495 107.3 ;
      RECT 75.425 107.4 75.495 107.75 ;
      RECT 75.425 107.85 75.495 108.2 ;
      RECT 75.425 108.3 75.495 108.65 ;
      RECT 75.425 108.75 75.495 109.1 ;
      RECT 75.425 109.2 75.495 109.55 ;
      RECT 75.425 109.65 75.495 110 ;
      RECT 75.425 112.89 75.495 113.24 ;
      RECT 75.425 113.34 75.495 113.69 ;
      RECT 75.425 113.79 75.495 114.14 ;
      RECT 75.425 114.24 75.495 114.59 ;
      RECT 75.425 114.69 75.495 115.04 ;
      RECT 75.425 115.14 75.495 115.49 ;
      RECT 75.425 118.45 75.495 118.8 ;
      RECT 75.425 118.9 75.495 119.25 ;
      RECT 75.425 119.35 75.495 119.7 ;
      RECT 75.425 119.8 75.495 120.15 ;
      RECT 75.425 120.25 75.495 120.6 ;
      RECT 75.425 120.7 75.495 121.05 ;
      RECT 75.425 123.69 75.495 124.04 ;
      RECT 75.425 124.14 75.495 124.49 ;
      RECT 75.425 124.59 75.495 124.94 ;
      RECT 75.425 125.04 75.495 125.39 ;
      RECT 75.425 125.49 75.495 125.84 ;
      RECT 75.425 125.94 75.495 126.29 ;
      RECT 75.425 126.39 75.495 126.74 ;
      RECT 75.425 135.13 75.495 135.48 ;
      RECT 75.425 135.58 75.495 135.93 ;
      RECT 75.425 136.03 75.495 136.38 ;
      RECT 75.425 136.48 75.495 136.83 ;
      RECT 75.425 136.93 75.495 137.28 ;
      RECT 75.425 137.38 75.495 137.73 ;
      RECT 75.425 140.69 75.495 141.04 ;
      RECT 75.425 141.14 75.495 141.49 ;
      RECT 75.425 141.59 75.495 141.94 ;
      RECT 75.425 142.04 75.495 142.39 ;
      RECT 75.425 142.49 75.495 142.84 ;
      RECT 75.425 142.94 75.495 143.29 ;
      RECT 75.425 145.95 75.495 146.3 ;
      RECT 75.425 146.4 75.495 146.75 ;
      RECT 75.425 146.85 75.495 147.2 ;
      RECT 75.425 147.3 75.495 147.65 ;
      RECT 75.425 147.75 75.495 148.1 ;
      RECT 75.425 148.2 75.495 148.55 ;
      RECT 75.425 148.65 75.495 149 ;
      RECT 75.425 151.44 75.495 151.79 ;
      RECT 75.425 151.89 75.495 152.24 ;
      RECT 75.425 152.34 75.495 152.69 ;
      RECT 75.425 152.79 75.495 153.14 ;
      RECT 75.425 153.24 75.495 153.59 ;
      RECT 75.425 153.69 75.495 154.04 ;
      RECT 75.425 154.14 75.495 154.49 ;
      RECT 75.425 157.37 75.495 157.72 ;
      RECT 75.425 157.82 75.495 158.17 ;
      RECT 75.425 158.27 75.495 158.62 ;
      RECT 75.425 158.72 75.495 159.07 ;
      RECT 75.425 159.17 75.495 159.52 ;
      RECT 75.425 159.62 75.495 159.97 ;
      RECT 75.425 162.93 75.495 163.28 ;
      RECT 75.425 163.38 75.495 163.73 ;
      RECT 75.425 163.83 75.495 164.18 ;
      RECT 75.425 164.28 75.495 164.63 ;
      RECT 75.425 164.73 75.495 165.08 ;
      RECT 75.425 165.18 75.495 165.53 ;
      RECT 75.425 168.18 75.495 168.53 ;
      RECT 75.425 168.63 75.495 168.98 ;
      RECT 75.425 169.08 75.495 169.43 ;
      RECT 75.425 169.53 75.495 169.88 ;
      RECT 75.425 169.98 75.495 170.33 ;
      RECT 75.425 170.43 75.495 170.78 ;
      RECT 75.425 170.88 75.495 171.23 ;
      RECT 75.425 173.67 75.495 174.02 ;
      RECT 75.425 174.12 75.495 174.47 ;
      RECT 75.425 174.57 75.495 174.92 ;
      RECT 75.425 175.02 75.495 175.37 ;
      RECT 75.425 175.47 75.495 175.82 ;
      RECT 75.425 175.92 75.495 176.27 ;
      RECT 75.425 176.37 75.495 176.72 ;
      RECT 75.425 179.61 75.495 179.96 ;
      RECT 75.425 180.06 75.495 180.41 ;
      RECT 75.425 180.51 75.495 180.86 ;
      RECT 75.425 180.96 75.495 181.31 ;
      RECT 75.425 181.41 75.495 181.76 ;
      RECT 75.425 181.86 75.495 182.21 ;
      RECT 75.425 185.17 75.495 185.52 ;
      RECT 75.425 185.62 75.495 185.97 ;
      RECT 75.425 186.07 75.495 186.42 ;
      RECT 75.425 186.52 75.495 186.87 ;
      RECT 75.425 186.97 75.495 187.32 ;
      RECT 75.425 187.42 75.495 187.77 ;
      RECT 75.425 190.44 75.495 190.79 ;
      RECT 75.425 190.89 75.495 191.24 ;
      RECT 75.425 191.34 75.495 191.69 ;
      RECT 75.425 191.79 75.495 192.14 ;
      RECT 75.425 192.24 75.495 192.59 ;
      RECT 75.425 192.69 75.495 193.04 ;
      RECT 75.425 193.14 75.495 193.49 ;
      RECT 75.425 195.93 75.495 196.28 ;
      RECT 75.425 196.38 75.495 196.73 ;
      RECT 75.425 196.83 75.495 197.18 ;
      RECT 75.425 197.28 75.495 197.63 ;
      RECT 75.425 197.73 75.495 198.08 ;
      RECT 75.425 198.18 75.495 198.53 ;
      RECT 75.425 198.63 75.495 198.98 ;
      RECT 75.425 201.85 75.495 202.2 ;
      RECT 75.425 202.3 75.495 202.65 ;
      RECT 75.425 202.75 75.495 203.1 ;
      RECT 75.425 203.2 75.495 203.55 ;
      RECT 75.425 203.65 75.495 204 ;
      RECT 75.425 204.1 75.495 204.45 ;
      RECT 75.425 207.41 75.495 207.76 ;
      RECT 75.425 207.86 75.495 208.21 ;
      RECT 75.425 208.31 75.495 208.66 ;
      RECT 75.425 208.76 75.495 209.11 ;
      RECT 75.425 209.21 75.495 209.56 ;
      RECT 75.425 209.66 75.495 210.01 ;
      RECT 75.425 212.67 75.495 213.02 ;
      RECT 75.425 213.12 75.495 213.47 ;
      RECT 75.425 213.57 75.495 213.92 ;
      RECT 75.425 214.02 75.495 214.37 ;
      RECT 75.425 214.47 75.495 214.82 ;
      RECT 75.425 214.92 75.495 215.27 ;
      RECT 75.425 215.37 75.495 215.72 ;
      RECT 75.425 218.16 75.495 218.51 ;
      RECT 75.425 218.61 75.495 218.96 ;
      RECT 75.425 219.06 75.495 219.41 ;
      RECT 75.425 219.51 75.495 219.86 ;
      RECT 75.425 219.96 75.495 220.31 ;
      RECT 75.425 220.41 75.495 220.76 ;
      RECT 75.425 220.86 75.495 221.21 ;
      RECT 75.425 224.09 75.495 224.44 ;
      RECT 75.425 224.54 75.495 224.89 ;
      RECT 75.425 224.99 75.495 225.34 ;
      RECT 75.425 225.44 75.495 225.79 ;
      RECT 75.425 225.89 75.495 226.24 ;
      RECT 75.425 226.34 75.495 226.69 ;
      RECT 75.425 229.65 75.495 230 ;
      RECT 75.425 230.1 75.495 230.45 ;
      RECT 75.425 230.55 75.495 230.9 ;
      RECT 75.425 231 75.495 231.35 ;
      RECT 75.425 231.45 75.495 231.8 ;
      RECT 75.425 231.9 75.495 232.25 ;
      RECT 75.425 234.9 75.495 235.25 ;
      RECT 75.425 235.35 75.495 235.7 ;
      RECT 75.425 235.8 75.495 236.15 ;
      RECT 75.425 236.25 75.495 236.6 ;
      RECT 75.425 236.7 75.495 237.05 ;
      RECT 75.425 237.15 75.495 237.5 ;
      RECT 75.425 237.6 75.495 237.95 ;
      RECT 75.425 240.42 75.495 240.77 ;
      RECT 75.425 240.87 75.495 241.22 ;
      RECT 75.425 241.32 75.495 241.67 ;
      RECT 75.425 241.77 75.495 242.12 ;
      RECT 75.425 242.22 75.495 242.57 ;
      RECT 75.425 242.67 75.495 243.02 ;
      RECT 75.425 243.12 75.495 243.47 ;
      RECT 75.425 246.33 75.495 246.68 ;
      RECT 75.425 246.78 75.495 247.13 ;
      RECT 75.425 247.23 75.495 247.58 ;
      RECT 75.425 247.68 75.495 248.03 ;
      RECT 75.425 248.13 75.495 248.48 ;
      RECT 75.425 248.58 75.495 248.93 ;
      RECT 75.425 251.89 75.495 252.24 ;
      RECT 75.425 252.34 75.495 252.69 ;
      RECT 75.425 252.79 75.495 253.14 ;
      RECT 75.425 253.24 75.495 253.59 ;
      RECT 75.425 253.69 75.495 254.04 ;
      RECT 75.425 254.14 75.495 254.49 ;
      RECT 75.425 257.16 75.495 257.51 ;
      RECT 75.425 257.61 75.495 257.96 ;
      RECT 75.425 258.06 75.495 258.41 ;
      RECT 75.425 258.51 75.495 258.86 ;
      RECT 75.425 258.96 75.495 259.31 ;
      RECT 75.425 259.41 75.495 259.76 ;
      RECT 75.425 259.86 75.495 260.21 ;
      RECT 75.425 262.68 75.495 263.03 ;
      RECT 75.425 263.13 75.495 263.48 ;
      RECT 75.425 263.58 75.495 263.93 ;
      RECT 75.425 264.03 75.495 264.38 ;
      RECT 75.425 264.48 75.495 264.83 ;
      RECT 75.425 264.93 75.495 265.28 ;
      RECT 75.425 265.38 75.495 265.73 ;
      RECT 75.425 268.57 75.495 268.92 ;
      RECT 75.425 269.02 75.495 269.37 ;
      RECT 75.425 269.47 75.495 269.82 ;
      RECT 75.425 269.92 75.495 270.27 ;
      RECT 75.425 270.37 75.495 270.72 ;
      RECT 75.425 270.82 75.495 271.17 ;
      RECT 75.425 274.13 75.495 274.48 ;
      RECT 75.425 274.58 75.495 274.93 ;
      RECT 75.425 275.03 75.495 275.38 ;
      RECT 75.425 275.48 75.495 275.83 ;
      RECT 75.425 275.93 75.495 276.28 ;
      RECT 75.425 276.38 75.495 276.73 ;
      RECT 75.425 279.39 75.495 279.74 ;
      RECT 75.425 279.84 75.495 280.19 ;
      RECT 75.425 280.29 75.495 280.64 ;
      RECT 75.425 280.74 75.495 281.09 ;
      RECT 75.425 281.19 75.495 281.54 ;
      RECT 75.425 281.64 75.495 281.99 ;
      RECT 75.425 282.09 75.495 282.44 ;
      RECT 75.425 284.91 75.495 285.26 ;
      RECT 75.425 285.36 75.495 285.71 ;
      RECT 75.425 285.81 75.495 286.16 ;
      RECT 75.425 286.26 75.495 286.61 ;
      RECT 75.425 286.71 75.495 287.06 ;
      RECT 75.425 287.16 75.495 287.51 ;
      RECT 75.425 287.61 75.495 287.96 ;
      RECT 75.425 296.37 75.495 296.72 ;
      RECT 75.425 296.82 75.495 297.17 ;
      RECT 75.425 297.27 75.495 297.62 ;
      RECT 75.425 297.72 75.495 298.07 ;
      RECT 75.425 298.17 75.495 298.52 ;
      RECT 75.425 298.62 75.495 298.97 ;
      RECT 75.425 301.93 75.495 302.28 ;
      RECT 75.425 302.38 75.495 302.73 ;
      RECT 75.425 302.83 75.495 303.18 ;
      RECT 75.425 303.28 75.495 303.63 ;
      RECT 75.425 303.73 75.495 304.08 ;
      RECT 75.425 304.18 75.495 304.53 ;
      RECT 75.425 307.17 75.495 307.52 ;
      RECT 75.425 307.62 75.495 307.97 ;
      RECT 75.425 308.07 75.495 308.42 ;
      RECT 75.425 308.52 75.495 308.87 ;
      RECT 75.425 308.97 75.495 309.32 ;
      RECT 75.425 309.42 75.495 309.77 ;
      RECT 75.425 309.87 75.495 310.22 ;
      RECT 75.425 313.05 75.495 313.4 ;
      RECT 75.425 313.5 75.495 313.85 ;
      RECT 75.425 313.95 75.495 314.3 ;
      RECT 75.425 314.4 75.495 314.75 ;
      RECT 75.425 314.85 75.495 315.2 ;
      RECT 75.425 315.3 75.495 315.65 ;
      RECT 75.425 318.61 75.495 318.96 ;
      RECT 75.425 319.06 75.495 319.41 ;
      RECT 75.425 319.51 75.495 319.86 ;
      RECT 75.425 319.96 75.495 320.31 ;
      RECT 75.425 320.41 75.495 320.76 ;
      RECT 75.425 320.86 75.495 321.21 ;
      RECT 75.425 323.88 75.495 324.23 ;
      RECT 75.425 324.33 75.495 324.68 ;
      RECT 75.425 324.78 75.495 325.13 ;
      RECT 75.425 325.23 75.495 325.58 ;
      RECT 75.425 325.68 75.495 326.03 ;
      RECT 75.425 326.13 75.495 326.48 ;
      RECT 75.425 326.58 75.495 326.93 ;
      RECT 75.425 329.4 75.495 329.75 ;
      RECT 75.425 329.85 75.495 330.2 ;
      RECT 75.425 330.3 75.495 330.65 ;
      RECT 75.425 330.75 75.495 331.1 ;
      RECT 75.425 331.2 75.495 331.55 ;
      RECT 75.425 331.65 75.495 332 ;
      RECT 75.425 332.1 75.495 332.45 ;
      RECT 75.425 340.85 75.495 341.2 ;
      RECT 75.425 341.3 75.495 341.65 ;
      RECT 75.425 341.75 75.495 342.1 ;
      RECT 75.425 342.2 75.495 342.55 ;
      RECT 75.425 342.65 75.495 343 ;
      RECT 75.425 343.1 75.495 343.45 ;
      RECT 11.855 1.535 21.405 1.955 ;
      RECT 11.855 7.095 21.405 7.515 ;
      RECT 11.855 12.655 21.405 13.075 ;
      RECT 11.855 18.215 21.405 18.635 ;
      RECT 11.855 32.695 21.405 33.115 ;
      RECT 11.855 38.255 21.405 38.675 ;
      RECT 11.855 43.815 21.405 44.235 ;
      RECT 11.855 49.375 21.405 49.795 ;
      RECT 11.855 54.935 21.405 55.355 ;
      RECT 11.855 60.495 21.405 60.915 ;
      RECT 11.855 66.055 21.405 66.475 ;
      RECT 11.855 71.615 21.405 72.035 ;
      RECT 11.855 77.175 21.405 77.595 ;
      RECT 11.855 82.735 21.405 83.155 ;
      RECT 11.855 88.295 21.405 88.715 ;
      RECT 11.855 93.855 21.405 94.275 ;
      RECT 11.855 99.415 21.405 99.835 ;
      RECT 11.855 104.975 21.405 105.395 ;
      RECT 11.855 110.535 21.405 110.955 ;
      RECT 11.855 116.095 21.405 116.515 ;
      RECT 11.855 121.655 21.405 122.075 ;
      RECT 11.855 127.215 21.405 127.635 ;
      RECT 11.855 132.775 21.405 133.195 ;
      RECT 11.855 138.335 21.405 138.755 ;
      RECT 11.855 143.895 21.405 144.315 ;
      RECT 11.855 149.455 21.405 149.875 ;
      RECT 11.855 155.015 21.405 155.435 ;
      RECT 11.855 160.575 21.405 160.995 ;
      RECT 11.855 166.135 21.405 166.555 ;
      RECT 11.855 171.695 21.405 172.115 ;
      RECT 11.855 177.255 21.405 177.675 ;
      RECT 11.855 182.815 21.405 183.235 ;
      RECT 11.855 188.375 21.405 188.795 ;
      RECT 11.855 193.935 21.405 194.355 ;
      RECT 11.855 199.495 21.405 199.915 ;
      RECT 11.855 205.055 21.405 205.475 ;
      RECT 11.855 210.615 21.405 211.035 ;
      RECT 11.855 216.175 21.405 216.595 ;
      RECT 11.855 221.735 21.405 222.155 ;
      RECT 11.855 227.295 21.405 227.715 ;
      RECT 11.855 232.855 21.405 233.275 ;
      RECT 11.855 238.415 21.405 238.835 ;
      RECT 11.855 243.975 21.405 244.395 ;
      RECT 11.855 249.535 21.405 249.955 ;
      RECT 11.855 255.095 21.405 255.515 ;
      RECT 11.855 260.655 21.405 261.075 ;
      RECT 11.855 266.215 21.405 266.635 ;
      RECT 11.855 271.775 21.405 272.195 ;
      RECT 11.855 277.335 21.405 277.755 ;
      RECT 11.855 282.895 21.405 283.315 ;
      RECT 11.855 288.455 21.405 288.875 ;
      RECT 11.855 294.015 21.405 294.435 ;
      RECT 11.855 299.575 21.405 299.995 ;
      RECT 11.855 305.135 21.405 305.555 ;
      RECT 11.855 310.695 21.405 311.115 ;
      RECT 11.855 316.255 21.405 316.675 ;
      RECT 11.855 321.815 21.405 322.235 ;
      RECT 11.855 327.375 21.405 327.795 ;
      RECT 11.855 332.935 21.405 333.355 ;
      RECT 11.855 338.495 21.405 338.915 ;
      RECT 11.855 344.055 21.405 344.475 ;
      RECT 16.67 185.23 16.74 185.58 ;
      RECT 16.67 185.68 16.74 186.03 ;
      RECT 16.67 186.13 16.74 186.48 ;
      RECT 16.67 186.58 16.74 186.93 ;
      RECT 16.67 187.03 16.74 187.38 ;
      RECT 16.67 187.48 16.74 187.83 ;
      RECT 16.655 13.27 16.725 13.62 ;
      RECT 16.655 13.72 16.725 14.07 ;
      RECT 16.655 14.17 16.725 14.52 ;
      RECT 16.655 14.62 16.725 14.97 ;
      RECT 16.655 15.07 16.725 15.42 ;
      RECT 16.655 15.52 16.725 15.87 ;
      RECT 16.655 15.97 16.725 16.32 ;
      RECT 16.655 18.83 16.725 19.18 ;
      RECT 16.655 19.28 16.725 19.63 ;
      RECT 16.655 19.73 16.725 20.08 ;
      RECT 16.655 20.18 16.725 20.53 ;
      RECT 16.655 20.63 16.725 20.98 ;
      RECT 16.655 21.08 16.725 21.43 ;
      RECT 16.655 21.53 16.725 21.88 ;
      RECT 16.655 29.52 16.725 29.87 ;
      RECT 16.655 29.97 16.725 30.32 ;
      RECT 16.655 30.42 16.725 30.77 ;
      RECT 16.655 30.87 16.725 31.22 ;
      RECT 16.655 31.32 16.725 31.67 ;
      RECT 16.655 31.77 16.725 32.12 ;
      RECT 16.655 35.05 16.725 35.4 ;
      RECT 16.655 35.5 16.725 35.85 ;
      RECT 16.655 35.95 16.725 36.3 ;
      RECT 16.655 36.4 16.725 36.75 ;
      RECT 16.655 36.85 16.725 37.2 ;
      RECT 16.655 37.3 16.725 37.65 ;
      RECT 16.655 40.32 16.725 40.67 ;
      RECT 16.655 40.77 16.725 41.12 ;
      RECT 16.655 41.22 16.725 41.57 ;
      RECT 16.655 41.67 16.725 42.02 ;
      RECT 16.655 42.12 16.725 42.47 ;
      RECT 16.655 42.57 16.725 42.92 ;
      RECT 16.655 43.02 16.725 43.37 ;
      RECT 16.655 45.81 16.725 46.16 ;
      RECT 16.655 46.26 16.725 46.61 ;
      RECT 16.655 46.71 16.725 47.06 ;
      RECT 16.655 47.16 16.725 47.51 ;
      RECT 16.655 47.61 16.725 47.96 ;
      RECT 16.655 48.06 16.725 48.41 ;
      RECT 16.655 48.51 16.725 48.86 ;
      RECT 16.655 51.73 16.725 52.08 ;
      RECT 16.655 52.18 16.725 52.53 ;
      RECT 16.655 52.63 16.725 52.98 ;
      RECT 16.655 53.08 16.725 53.43 ;
      RECT 16.655 53.53 16.725 53.88 ;
      RECT 16.655 53.98 16.725 54.33 ;
      RECT 16.655 57.29 16.725 57.64 ;
      RECT 16.655 57.74 16.725 58.09 ;
      RECT 16.655 58.19 16.725 58.54 ;
      RECT 16.655 58.64 16.725 58.99 ;
      RECT 16.655 59.09 16.725 59.44 ;
      RECT 16.655 59.54 16.725 59.89 ;
      RECT 16.655 62.55 16.725 62.9 ;
      RECT 16.655 63 16.725 63.35 ;
      RECT 16.655 63.45 16.725 63.8 ;
      RECT 16.655 63.9 16.725 64.25 ;
      RECT 16.655 64.35 16.725 64.7 ;
      RECT 16.655 64.8 16.725 65.15 ;
      RECT 16.655 65.25 16.725 65.6 ;
      RECT 16.655 68.07 16.725 68.42 ;
      RECT 16.655 68.52 16.725 68.87 ;
      RECT 16.655 68.97 16.725 69.32 ;
      RECT 16.655 69.42 16.725 69.77 ;
      RECT 16.655 69.87 16.725 70.22 ;
      RECT 16.655 70.32 16.725 70.67 ;
      RECT 16.655 70.77 16.725 71.12 ;
      RECT 16.655 73.97 16.725 74.32 ;
      RECT 16.655 74.42 16.725 74.77 ;
      RECT 16.655 74.87 16.725 75.22 ;
      RECT 16.655 75.32 16.725 75.67 ;
      RECT 16.655 75.77 16.725 76.12 ;
      RECT 16.655 76.22 16.725 76.57 ;
      RECT 16.655 79.53 16.725 79.88 ;
      RECT 16.655 79.98 16.725 80.33 ;
      RECT 16.655 80.43 16.725 80.78 ;
      RECT 16.655 80.88 16.725 81.23 ;
      RECT 16.655 81.33 16.725 81.68 ;
      RECT 16.655 81.78 16.725 82.13 ;
      RECT 16.655 84.78 16.725 85.13 ;
      RECT 16.655 85.23 16.725 85.58 ;
      RECT 16.655 85.68 16.725 86.03 ;
      RECT 16.655 86.13 16.725 86.48 ;
      RECT 16.655 86.58 16.725 86.93 ;
      RECT 16.655 87.03 16.725 87.38 ;
      RECT 16.655 87.48 16.725 87.83 ;
      RECT 16.655 90.3 16.725 90.65 ;
      RECT 16.655 90.75 16.725 91.1 ;
      RECT 16.655 91.2 16.725 91.55 ;
      RECT 16.655 91.65 16.725 92 ;
      RECT 16.655 92.1 16.725 92.45 ;
      RECT 16.655 92.55 16.725 92.9 ;
      RECT 16.655 93 16.725 93.35 ;
      RECT 16.655 96.21 16.725 96.56 ;
      RECT 16.655 96.66 16.725 97.01 ;
      RECT 16.655 97.11 16.725 97.46 ;
      RECT 16.655 97.56 16.725 97.91 ;
      RECT 16.655 98.01 16.725 98.36 ;
      RECT 16.655 98.46 16.725 98.81 ;
      RECT 16.655 101.77 16.725 102.12 ;
      RECT 16.655 102.22 16.725 102.57 ;
      RECT 16.655 102.67 16.725 103.02 ;
      RECT 16.655 103.12 16.725 103.47 ;
      RECT 16.655 103.57 16.725 103.92 ;
      RECT 16.655 104.02 16.725 104.37 ;
      RECT 16.655 107.04 16.725 107.39 ;
      RECT 16.655 107.49 16.725 107.84 ;
      RECT 16.655 107.94 16.725 108.29 ;
      RECT 16.655 108.39 16.725 108.74 ;
      RECT 16.655 108.84 16.725 109.19 ;
      RECT 16.655 109.29 16.725 109.64 ;
      RECT 16.655 109.74 16.725 110.09 ;
      RECT 16.655 112.56 16.725 112.91 ;
      RECT 16.655 113.01 16.725 113.36 ;
      RECT 16.655 113.46 16.725 113.81 ;
      RECT 16.655 113.91 16.725 114.26 ;
      RECT 16.655 114.36 16.725 114.71 ;
      RECT 16.655 114.81 16.725 115.16 ;
      RECT 16.655 115.26 16.725 115.61 ;
      RECT 16.655 118.45 16.725 118.8 ;
      RECT 16.655 118.9 16.725 119.25 ;
      RECT 16.655 119.35 16.725 119.7 ;
      RECT 16.655 119.8 16.725 120.15 ;
      RECT 16.655 120.25 16.725 120.6 ;
      RECT 16.655 120.7 16.725 121.05 ;
      RECT 16.655 124.01 16.725 124.36 ;
      RECT 16.655 124.46 16.725 124.81 ;
      RECT 16.655 124.91 16.725 125.26 ;
      RECT 16.655 125.36 16.725 125.71 ;
      RECT 16.655 125.81 16.725 126.16 ;
      RECT 16.655 126.26 16.725 126.61 ;
      RECT 16.655 129.27 16.725 129.62 ;
      RECT 16.655 129.72 16.725 130.07 ;
      RECT 16.655 130.17 16.725 130.52 ;
      RECT 16.655 130.62 16.725 130.97 ;
      RECT 16.655 131.07 16.725 131.42 ;
      RECT 16.655 131.52 16.725 131.87 ;
      RECT 16.655 131.97 16.725 132.32 ;
      RECT 16.655 134.79 16.725 135.14 ;
      RECT 16.655 135.24 16.725 135.59 ;
      RECT 16.655 135.69 16.725 136.04 ;
      RECT 16.655 136.14 16.725 136.49 ;
      RECT 16.655 136.59 16.725 136.94 ;
      RECT 16.655 137.04 16.725 137.39 ;
      RECT 16.655 137.49 16.725 137.84 ;
      RECT 16.655 146.25 16.725 146.6 ;
      RECT 16.655 146.7 16.725 147.05 ;
      RECT 16.655 147.15 16.725 147.5 ;
      RECT 16.655 147.6 16.725 147.95 ;
      RECT 16.655 148.05 16.725 148.4 ;
      RECT 16.655 148.5 16.725 148.85 ;
      RECT 16.655 151.81 16.725 152.16 ;
      RECT 16.655 152.26 16.725 152.61 ;
      RECT 16.655 152.71 16.725 153.06 ;
      RECT 16.655 153.16 16.725 153.51 ;
      RECT 16.655 153.61 16.725 153.96 ;
      RECT 16.655 154.06 16.725 154.41 ;
      RECT 16.655 157.05 16.725 157.4 ;
      RECT 16.655 157.5 16.725 157.85 ;
      RECT 16.655 157.95 16.725 158.3 ;
      RECT 16.655 158.4 16.725 158.75 ;
      RECT 16.655 158.85 16.725 159.2 ;
      RECT 16.655 159.3 16.725 159.65 ;
      RECT 16.655 159.75 16.725 160.1 ;
      RECT 16.655 162.93 16.725 163.28 ;
      RECT 16.655 163.38 16.725 163.73 ;
      RECT 16.655 163.83 16.725 164.18 ;
      RECT 16.655 164.28 16.725 164.63 ;
      RECT 16.655 164.73 16.725 165.08 ;
      RECT 16.655 165.18 16.725 165.53 ;
      RECT 16.655 168.49 16.725 168.84 ;
      RECT 16.655 168.94 16.725 169.29 ;
      RECT 16.655 169.39 16.725 169.74 ;
      RECT 16.655 169.84 16.725 170.19 ;
      RECT 16.655 170.29 16.725 170.64 ;
      RECT 16.655 170.74 16.725 171.09 ;
      RECT 16.655 174.11 16.725 174.46 ;
      RECT 16.655 174.56 16.725 174.91 ;
      RECT 16.655 175.01 16.725 175.36 ;
      RECT 16.655 175.46 16.725 175.81 ;
      RECT 16.655 175.91 16.725 176.26 ;
      RECT 16.655 176.36 16.725 176.71 ;
      RECT 16.655 179.28 16.725 179.63 ;
      RECT 16.655 179.73 16.725 180.08 ;
      RECT 16.655 180.18 16.725 180.53 ;
      RECT 16.655 180.63 16.725 180.98 ;
      RECT 16.655 181.08 16.725 181.43 ;
      RECT 16.655 181.53 16.725 181.88 ;
      RECT 16.655 181.98 16.725 182.33 ;
      RECT 16.655 190.73 16.725 191.08 ;
      RECT 16.655 191.18 16.725 191.53 ;
      RECT 16.655 191.63 16.725 191.98 ;
      RECT 16.655 192.08 16.725 192.43 ;
      RECT 16.655 192.53 16.725 192.88 ;
      RECT 16.655 192.98 16.725 193.33 ;
      RECT 16.655 196.29 16.725 196.64 ;
      RECT 16.655 196.74 16.725 197.09 ;
      RECT 16.655 197.19 16.725 197.54 ;
      RECT 16.655 197.64 16.725 197.99 ;
      RECT 16.655 198.09 16.725 198.44 ;
      RECT 16.655 198.54 16.725 198.89 ;
      RECT 16.655 201.54 16.725 201.89 ;
      RECT 16.655 201.99 16.725 202.34 ;
      RECT 16.655 202.44 16.725 202.79 ;
      RECT 16.655 202.89 16.725 203.24 ;
      RECT 16.655 203.34 16.725 203.69 ;
      RECT 16.655 203.79 16.725 204.14 ;
      RECT 16.655 204.24 16.725 204.59 ;
      RECT 16.655 207.03 16.725 207.38 ;
      RECT 16.655 207.48 16.725 207.83 ;
      RECT 16.655 207.93 16.725 208.28 ;
      RECT 16.655 208.38 16.725 208.73 ;
      RECT 16.655 208.83 16.725 209.18 ;
      RECT 16.655 209.28 16.725 209.63 ;
      RECT 16.655 209.73 16.725 210.08 ;
      RECT 16.655 212.97 16.725 213.32 ;
      RECT 16.655 213.42 16.725 213.77 ;
      RECT 16.655 213.87 16.725 214.22 ;
      RECT 16.655 214.32 16.725 214.67 ;
      RECT 16.655 214.77 16.725 215.12 ;
      RECT 16.655 215.22 16.725 215.57 ;
      RECT 16.655 218.53 16.725 218.88 ;
      RECT 16.655 218.98 16.725 219.33 ;
      RECT 16.655 219.43 16.725 219.78 ;
      RECT 16.655 219.88 16.725 220.23 ;
      RECT 16.655 220.33 16.725 220.68 ;
      RECT 16.655 220.78 16.725 221.13 ;
      RECT 16.655 223.77 16.725 224.12 ;
      RECT 16.655 224.22 16.725 224.57 ;
      RECT 16.655 224.67 16.725 225.02 ;
      RECT 16.655 225.12 16.725 225.47 ;
      RECT 16.655 225.57 16.725 225.92 ;
      RECT 16.655 226.02 16.725 226.37 ;
      RECT 16.655 226.47 16.725 226.82 ;
      RECT 16.655 235.21 16.725 235.56 ;
      RECT 16.655 235.66 16.725 236.01 ;
      RECT 16.655 236.11 16.725 236.46 ;
      RECT 16.655 236.56 16.725 236.91 ;
      RECT 16.655 237.01 16.725 237.36 ;
      RECT 16.655 237.46 16.725 237.81 ;
      RECT 16.655 240.77 16.725 241.12 ;
      RECT 16.655 241.22 16.725 241.57 ;
      RECT 16.655 241.67 16.725 242.02 ;
      RECT 16.655 242.12 16.725 242.47 ;
      RECT 16.655 242.57 16.725 242.92 ;
      RECT 16.655 243.02 16.725 243.37 ;
      RECT 16.655 246.03 16.725 246.38 ;
      RECT 16.655 246.48 16.725 246.83 ;
      RECT 16.655 246.93 16.725 247.28 ;
      RECT 16.655 247.38 16.725 247.73 ;
      RECT 16.655 247.83 16.725 248.18 ;
      RECT 16.655 248.28 16.725 248.63 ;
      RECT 16.655 248.73 16.725 249.08 ;
      RECT 16.655 251.52 16.725 251.87 ;
      RECT 16.655 251.97 16.725 252.32 ;
      RECT 16.655 252.42 16.725 252.77 ;
      RECT 16.655 252.87 16.725 253.22 ;
      RECT 16.655 253.32 16.725 253.67 ;
      RECT 16.655 253.77 16.725 254.12 ;
      RECT 16.655 254.22 16.725 254.57 ;
      RECT 16.655 257.45 16.725 257.8 ;
      RECT 16.655 257.9 16.725 258.25 ;
      RECT 16.655 258.35 16.725 258.7 ;
      RECT 16.655 258.8 16.725 259.15 ;
      RECT 16.655 259.25 16.725 259.6 ;
      RECT 16.655 259.7 16.725 260.05 ;
      RECT 16.655 263.01 16.725 263.36 ;
      RECT 16.655 263.46 16.725 263.81 ;
      RECT 16.655 263.91 16.725 264.26 ;
      RECT 16.655 264.36 16.725 264.71 ;
      RECT 16.655 264.81 16.725 265.16 ;
      RECT 16.655 265.26 16.725 265.61 ;
      RECT 16.655 268.26 16.725 268.61 ;
      RECT 16.655 268.71 16.725 269.06 ;
      RECT 16.655 269.16 16.725 269.51 ;
      RECT 16.655 269.61 16.725 269.96 ;
      RECT 16.655 270.06 16.725 270.41 ;
      RECT 16.655 270.51 16.725 270.86 ;
      RECT 16.655 270.96 16.725 271.31 ;
      RECT 16.655 273.75 16.725 274.1 ;
      RECT 16.655 274.2 16.725 274.55 ;
      RECT 16.655 274.65 16.725 275 ;
      RECT 16.655 275.1 16.725 275.45 ;
      RECT 16.655 275.55 16.725 275.9 ;
      RECT 16.655 276 16.725 276.35 ;
      RECT 16.655 276.45 16.725 276.8 ;
      RECT 16.655 279.69 16.725 280.04 ;
      RECT 16.655 280.14 16.725 280.49 ;
      RECT 16.655 280.59 16.725 280.94 ;
      RECT 16.655 281.04 16.725 281.39 ;
      RECT 16.655 281.49 16.725 281.84 ;
      RECT 16.655 281.94 16.725 282.29 ;
      RECT 16.655 285.25 16.725 285.6 ;
      RECT 16.655 285.7 16.725 286.05 ;
      RECT 16.655 286.15 16.725 286.5 ;
      RECT 16.655 286.6 16.725 286.95 ;
      RECT 16.655 287.05 16.725 287.4 ;
      RECT 16.655 287.5 16.725 287.85 ;
      RECT 16.655 290.52 16.725 290.87 ;
      RECT 16.655 290.97 16.725 291.32 ;
      RECT 16.655 291.42 16.725 291.77 ;
      RECT 16.655 291.87 16.725 292.22 ;
      RECT 16.655 292.32 16.725 292.67 ;
      RECT 16.655 292.77 16.725 293.12 ;
      RECT 16.655 293.22 16.725 293.57 ;
      RECT 16.655 296.01 16.725 296.36 ;
      RECT 16.655 296.46 16.725 296.81 ;
      RECT 16.655 296.91 16.725 297.26 ;
      RECT 16.655 297.36 16.725 297.71 ;
      RECT 16.655 297.81 16.725 298.16 ;
      RECT 16.655 298.26 16.725 298.61 ;
      RECT 16.655 298.71 16.725 299.06 ;
      RECT 16.655 301.93 16.725 302.28 ;
      RECT 16.655 302.38 16.725 302.73 ;
      RECT 16.655 302.83 16.725 303.18 ;
      RECT 16.655 303.28 16.725 303.63 ;
      RECT 16.655 303.73 16.725 304.08 ;
      RECT 16.655 304.18 16.725 304.53 ;
      RECT 16.655 307.49 16.725 307.84 ;
      RECT 16.655 307.94 16.725 308.29 ;
      RECT 16.655 308.39 16.725 308.74 ;
      RECT 16.655 308.84 16.725 309.19 ;
      RECT 16.655 309.29 16.725 309.64 ;
      RECT 16.655 309.74 16.725 310.09 ;
      RECT 16.655 312.75 16.725 313.1 ;
      RECT 16.655 313.2 16.725 313.55 ;
      RECT 16.655 313.65 16.725 314 ;
      RECT 16.655 314.1 16.725 314.45 ;
      RECT 16.655 314.55 16.725 314.9 ;
      RECT 16.655 315 16.725 315.35 ;
      RECT 16.655 315.45 16.725 315.8 ;
      RECT 16.655 318.27 16.725 318.62 ;
      RECT 16.655 318.72 16.725 319.07 ;
      RECT 16.655 319.17 16.725 319.52 ;
      RECT 16.655 319.62 16.725 319.97 ;
      RECT 16.655 320.07 16.725 320.42 ;
      RECT 16.655 320.52 16.725 320.87 ;
      RECT 16.655 320.97 16.725 321.32 ;
      RECT 16.655 324.17 16.725 324.52 ;
      RECT 16.655 324.62 16.725 324.97 ;
      RECT 16.655 325.07 16.725 325.42 ;
      RECT 16.655 325.52 16.725 325.87 ;
      RECT 16.655 325.97 16.725 326.32 ;
      RECT 16.655 326.42 16.725 326.77 ;
      RECT 16.655 329.73 16.725 330.08 ;
      RECT 16.655 330.18 16.725 330.53 ;
      RECT 16.655 330.63 16.725 330.98 ;
      RECT 16.655 331.08 16.725 331.43 ;
      RECT 16.655 331.53 16.725 331.88 ;
      RECT 16.655 331.98 16.725 332.33 ;
      RECT 16.655 334.98 16.725 335.33 ;
      RECT 16.655 335.43 16.725 335.78 ;
      RECT 16.655 335.88 16.725 336.23 ;
      RECT 16.655 336.33 16.725 336.68 ;
      RECT 16.655 336.78 16.725 337.13 ;
      RECT 16.655 337.23 16.725 337.58 ;
      RECT 16.655 337.68 16.725 338.03 ;
      RECT 16.655 340.5 16.725 340.85 ;
      RECT 16.655 340.95 16.725 341.3 ;
      RECT 16.655 341.4 16.725 341.75 ;
      RECT 16.655 341.85 16.725 342.2 ;
      RECT 16.655 342.3 16.725 342.65 ;
      RECT 16.655 342.75 16.725 343.1 ;
      RECT 16.655 343.2 16.725 343.55 ;
      RECT 16.65 229.71 16.72 230.06 ;
      RECT 16.65 230.16 16.72 230.51 ;
      RECT 16.65 230.61 16.72 230.96 ;
      RECT 16.65 231.06 16.72 231.41 ;
      RECT 16.65 231.51 16.72 231.86 ;
      RECT 16.65 231.96 16.72 232.31 ;
      RECT 16.61 2.15 16.68 2.5 ;
      RECT 16.61 2.6 16.68 2.95 ;
      RECT 16.61 3.05 16.68 3.4 ;
      RECT 16.61 3.5 16.68 3.85 ;
      RECT 16.61 3.95 16.68 4.3 ;
      RECT 16.61 4.4 16.68 4.75 ;
      RECT 16.61 4.85 16.68 5.2 ;
      RECT 16.6 7.71 16.67 8.06 ;
      RECT 16.6 8.16 16.67 8.51 ;
      RECT 16.6 8.61 16.67 8.96 ;
      RECT 16.6 9.06 16.67 9.41 ;
      RECT 16.6 9.51 16.67 9.86 ;
      RECT 16.6 9.96 16.67 10.31 ;
      RECT 16.6 10.41 16.67 10.76 ;
      RECT 16.55 140.75 16.62 141.1 ;
      RECT 16.55 141.2 16.62 141.55 ;
      RECT 16.55 141.65 16.62 142 ;
      RECT 16.55 142.1 16.62 142.45 ;
      RECT 16.55 142.55 16.62 142.9 ;
      RECT 16.55 143 16.62 143.35 ;
      RECT 16.53 185.23 16.6 185.58 ;
      RECT 16.53 185.68 16.6 186.03 ;
      RECT 16.53 186.13 16.6 186.48 ;
      RECT 16.53 186.58 16.6 186.93 ;
      RECT 16.53 187.03 16.6 187.38 ;
      RECT 16.53 187.48 16.6 187.83 ;
      RECT 16.515 13.27 16.585 13.62 ;
      RECT 16.515 13.72 16.585 14.07 ;
      RECT 16.515 14.17 16.585 14.52 ;
      RECT 16.515 14.62 16.585 14.97 ;
      RECT 16.515 15.07 16.585 15.42 ;
      RECT 16.515 15.52 16.585 15.87 ;
      RECT 16.515 15.97 16.585 16.32 ;
      RECT 16.515 18.83 16.585 19.18 ;
      RECT 16.515 19.28 16.585 19.63 ;
      RECT 16.515 19.73 16.585 20.08 ;
      RECT 16.515 20.18 16.585 20.53 ;
      RECT 16.515 20.63 16.585 20.98 ;
      RECT 16.515 21.08 16.585 21.43 ;
      RECT 16.515 21.53 16.585 21.88 ;
      RECT 16.515 29.52 16.585 29.87 ;
      RECT 16.515 29.97 16.585 30.32 ;
      RECT 16.515 30.42 16.585 30.77 ;
      RECT 16.515 30.87 16.585 31.22 ;
      RECT 16.515 31.32 16.585 31.67 ;
      RECT 16.515 31.77 16.585 32.12 ;
      RECT 16.515 35.05 16.585 35.4 ;
      RECT 16.515 35.5 16.585 35.85 ;
      RECT 16.515 35.95 16.585 36.3 ;
      RECT 16.515 36.4 16.585 36.75 ;
      RECT 16.515 36.85 16.585 37.2 ;
      RECT 16.515 37.3 16.585 37.65 ;
      RECT 16.515 40.32 16.585 40.67 ;
      RECT 16.515 40.77 16.585 41.12 ;
      RECT 16.515 41.22 16.585 41.57 ;
      RECT 16.515 41.67 16.585 42.02 ;
      RECT 16.515 42.12 16.585 42.47 ;
      RECT 16.515 42.57 16.585 42.92 ;
      RECT 16.515 43.02 16.585 43.37 ;
      RECT 16.515 45.81 16.585 46.16 ;
      RECT 16.515 46.26 16.585 46.61 ;
      RECT 16.515 46.71 16.585 47.06 ;
      RECT 16.515 47.16 16.585 47.51 ;
      RECT 16.515 47.61 16.585 47.96 ;
      RECT 16.515 48.06 16.585 48.41 ;
      RECT 16.515 48.51 16.585 48.86 ;
      RECT 16.515 51.73 16.585 52.08 ;
      RECT 16.515 52.18 16.585 52.53 ;
      RECT 16.515 52.63 16.585 52.98 ;
      RECT 16.515 53.08 16.585 53.43 ;
      RECT 16.515 53.53 16.585 53.88 ;
      RECT 16.515 53.98 16.585 54.33 ;
      RECT 16.515 57.29 16.585 57.64 ;
      RECT 16.515 57.74 16.585 58.09 ;
      RECT 16.515 58.19 16.585 58.54 ;
      RECT 16.515 58.64 16.585 58.99 ;
      RECT 16.515 59.09 16.585 59.44 ;
      RECT 16.515 59.54 16.585 59.89 ;
      RECT 16.515 62.55 16.585 62.9 ;
      RECT 16.515 63 16.585 63.35 ;
      RECT 16.515 63.45 16.585 63.8 ;
      RECT 16.515 63.9 16.585 64.25 ;
      RECT 16.515 64.35 16.585 64.7 ;
      RECT 16.515 64.8 16.585 65.15 ;
      RECT 16.515 65.25 16.585 65.6 ;
      RECT 16.515 68.07 16.585 68.42 ;
      RECT 16.515 68.52 16.585 68.87 ;
      RECT 16.515 68.97 16.585 69.32 ;
      RECT 16.515 69.42 16.585 69.77 ;
      RECT 16.515 69.87 16.585 70.22 ;
      RECT 16.515 70.32 16.585 70.67 ;
      RECT 16.515 70.77 16.585 71.12 ;
      RECT 16.515 73.97 16.585 74.32 ;
      RECT 16.515 74.42 16.585 74.77 ;
      RECT 16.515 74.87 16.585 75.22 ;
      RECT 16.515 75.32 16.585 75.67 ;
      RECT 16.515 75.77 16.585 76.12 ;
      RECT 16.515 76.22 16.585 76.57 ;
      RECT 16.515 79.53 16.585 79.88 ;
      RECT 16.515 79.98 16.585 80.33 ;
      RECT 16.515 80.43 16.585 80.78 ;
      RECT 16.515 80.88 16.585 81.23 ;
      RECT 16.515 81.33 16.585 81.68 ;
      RECT 16.515 81.78 16.585 82.13 ;
      RECT 16.515 84.78 16.585 85.13 ;
      RECT 16.515 85.23 16.585 85.58 ;
      RECT 16.515 85.68 16.585 86.03 ;
      RECT 16.515 86.13 16.585 86.48 ;
      RECT 16.515 86.58 16.585 86.93 ;
      RECT 16.515 87.03 16.585 87.38 ;
      RECT 16.515 87.48 16.585 87.83 ;
      RECT 16.515 90.3 16.585 90.65 ;
      RECT 16.515 90.75 16.585 91.1 ;
      RECT 16.515 91.2 16.585 91.55 ;
      RECT 16.515 91.65 16.585 92 ;
      RECT 16.515 92.1 16.585 92.45 ;
      RECT 16.515 92.55 16.585 92.9 ;
      RECT 16.515 93 16.585 93.35 ;
      RECT 16.515 96.21 16.585 96.56 ;
      RECT 16.515 96.66 16.585 97.01 ;
      RECT 16.515 97.11 16.585 97.46 ;
      RECT 16.515 97.56 16.585 97.91 ;
      RECT 16.515 98.01 16.585 98.36 ;
      RECT 16.515 98.46 16.585 98.81 ;
      RECT 16.515 101.77 16.585 102.12 ;
      RECT 16.515 102.22 16.585 102.57 ;
      RECT 16.515 102.67 16.585 103.02 ;
      RECT 16.515 103.12 16.585 103.47 ;
      RECT 16.515 103.57 16.585 103.92 ;
      RECT 16.515 104.02 16.585 104.37 ;
      RECT 16.515 107.04 16.585 107.39 ;
      RECT 16.515 107.49 16.585 107.84 ;
      RECT 16.515 107.94 16.585 108.29 ;
      RECT 16.515 108.39 16.585 108.74 ;
      RECT 16.515 108.84 16.585 109.19 ;
      RECT 16.515 109.29 16.585 109.64 ;
      RECT 16.515 109.74 16.585 110.09 ;
      RECT 16.515 112.56 16.585 112.91 ;
      RECT 16.515 113.01 16.585 113.36 ;
      RECT 16.515 113.46 16.585 113.81 ;
      RECT 16.515 113.91 16.585 114.26 ;
      RECT 16.515 114.36 16.585 114.71 ;
      RECT 16.515 114.81 16.585 115.16 ;
      RECT 16.515 115.26 16.585 115.61 ;
      RECT 16.515 118.45 16.585 118.8 ;
      RECT 16.515 118.9 16.585 119.25 ;
      RECT 16.515 119.35 16.585 119.7 ;
      RECT 16.515 119.8 16.585 120.15 ;
      RECT 16.515 120.25 16.585 120.6 ;
      RECT 16.515 120.7 16.585 121.05 ;
      RECT 16.515 124.01 16.585 124.36 ;
      RECT 16.515 124.46 16.585 124.81 ;
      RECT 16.515 124.91 16.585 125.26 ;
      RECT 16.515 125.36 16.585 125.71 ;
      RECT 16.515 125.81 16.585 126.16 ;
      RECT 16.515 126.26 16.585 126.61 ;
      RECT 16.515 129.27 16.585 129.62 ;
      RECT 16.515 129.72 16.585 130.07 ;
      RECT 16.515 130.17 16.585 130.52 ;
      RECT 16.515 130.62 16.585 130.97 ;
      RECT 16.515 131.07 16.585 131.42 ;
      RECT 16.515 131.52 16.585 131.87 ;
      RECT 16.515 131.97 16.585 132.32 ;
      RECT 16.515 134.79 16.585 135.14 ;
      RECT 16.515 135.24 16.585 135.59 ;
      RECT 16.515 135.69 16.585 136.04 ;
      RECT 16.515 136.14 16.585 136.49 ;
      RECT 16.515 136.59 16.585 136.94 ;
      RECT 16.515 137.04 16.585 137.39 ;
      RECT 16.515 137.49 16.585 137.84 ;
      RECT 16.515 146.25 16.585 146.6 ;
      RECT 16.515 146.7 16.585 147.05 ;
      RECT 16.515 147.15 16.585 147.5 ;
      RECT 16.515 147.6 16.585 147.95 ;
      RECT 16.515 148.05 16.585 148.4 ;
      RECT 16.515 148.5 16.585 148.85 ;
      RECT 16.515 151.81 16.585 152.16 ;
      RECT 16.515 152.26 16.585 152.61 ;
      RECT 16.515 152.71 16.585 153.06 ;
      RECT 16.515 153.16 16.585 153.51 ;
      RECT 16.515 153.61 16.585 153.96 ;
      RECT 16.515 154.06 16.585 154.41 ;
      RECT 16.515 157.05 16.585 157.4 ;
      RECT 16.515 157.5 16.585 157.85 ;
      RECT 16.515 157.95 16.585 158.3 ;
      RECT 16.515 158.4 16.585 158.75 ;
      RECT 16.515 158.85 16.585 159.2 ;
      RECT 16.515 159.3 16.585 159.65 ;
      RECT 16.515 159.75 16.585 160.1 ;
      RECT 16.515 162.93 16.585 163.28 ;
      RECT 16.515 163.38 16.585 163.73 ;
      RECT 16.515 163.83 16.585 164.18 ;
      RECT 16.515 164.28 16.585 164.63 ;
      RECT 16.515 164.73 16.585 165.08 ;
      RECT 16.515 165.18 16.585 165.53 ;
      RECT 16.515 168.49 16.585 168.84 ;
      RECT 16.515 168.94 16.585 169.29 ;
      RECT 16.515 169.39 16.585 169.74 ;
      RECT 16.515 169.84 16.585 170.19 ;
      RECT 16.515 170.29 16.585 170.64 ;
      RECT 16.515 170.74 16.585 171.09 ;
      RECT 16.515 174.11 16.585 174.46 ;
      RECT 16.515 174.56 16.585 174.91 ;
      RECT 16.515 175.01 16.585 175.36 ;
      RECT 16.515 175.46 16.585 175.81 ;
      RECT 16.515 175.91 16.585 176.26 ;
      RECT 16.515 176.36 16.585 176.71 ;
      RECT 16.515 179.28 16.585 179.63 ;
      RECT 16.515 179.73 16.585 180.08 ;
      RECT 16.515 180.18 16.585 180.53 ;
      RECT 16.515 180.63 16.585 180.98 ;
      RECT 16.515 181.08 16.585 181.43 ;
      RECT 16.515 181.53 16.585 181.88 ;
      RECT 16.515 181.98 16.585 182.33 ;
      RECT 16.515 190.73 16.585 191.08 ;
      RECT 16.515 191.18 16.585 191.53 ;
      RECT 16.515 191.63 16.585 191.98 ;
      RECT 16.515 192.08 16.585 192.43 ;
      RECT 16.515 192.53 16.585 192.88 ;
      RECT 16.515 192.98 16.585 193.33 ;
      RECT 16.515 196.29 16.585 196.64 ;
      RECT 16.515 196.74 16.585 197.09 ;
      RECT 16.515 197.19 16.585 197.54 ;
      RECT 16.515 197.64 16.585 197.99 ;
      RECT 16.515 198.09 16.585 198.44 ;
      RECT 16.515 198.54 16.585 198.89 ;
      RECT 16.515 201.54 16.585 201.89 ;
      RECT 16.515 201.99 16.585 202.34 ;
      RECT 16.515 202.44 16.585 202.79 ;
      RECT 16.515 202.89 16.585 203.24 ;
      RECT 16.515 203.34 16.585 203.69 ;
      RECT 16.515 203.79 16.585 204.14 ;
      RECT 16.515 204.24 16.585 204.59 ;
      RECT 16.515 207.03 16.585 207.38 ;
      RECT 16.515 207.48 16.585 207.83 ;
      RECT 16.515 207.93 16.585 208.28 ;
      RECT 16.515 208.38 16.585 208.73 ;
      RECT 16.515 208.83 16.585 209.18 ;
      RECT 16.515 209.28 16.585 209.63 ;
      RECT 16.515 209.73 16.585 210.08 ;
      RECT 16.515 212.97 16.585 213.32 ;
      RECT 16.515 213.42 16.585 213.77 ;
      RECT 16.515 213.87 16.585 214.22 ;
      RECT 16.515 214.32 16.585 214.67 ;
      RECT 16.515 214.77 16.585 215.12 ;
      RECT 16.515 215.22 16.585 215.57 ;
      RECT 16.515 218.53 16.585 218.88 ;
      RECT 16.515 218.98 16.585 219.33 ;
      RECT 16.515 219.43 16.585 219.78 ;
      RECT 16.515 219.88 16.585 220.23 ;
      RECT 16.515 220.33 16.585 220.68 ;
      RECT 16.515 220.78 16.585 221.13 ;
      RECT 16.515 223.77 16.585 224.12 ;
      RECT 16.515 224.22 16.585 224.57 ;
      RECT 16.515 224.67 16.585 225.02 ;
      RECT 16.515 225.12 16.585 225.47 ;
      RECT 16.515 225.57 16.585 225.92 ;
      RECT 16.515 226.02 16.585 226.37 ;
      RECT 16.515 226.47 16.585 226.82 ;
      RECT 16.515 235.21 16.585 235.56 ;
      RECT 16.515 235.66 16.585 236.01 ;
      RECT 16.515 236.11 16.585 236.46 ;
      RECT 16.515 236.56 16.585 236.91 ;
      RECT 16.515 237.01 16.585 237.36 ;
      RECT 16.515 237.46 16.585 237.81 ;
      RECT 16.515 240.77 16.585 241.12 ;
      RECT 16.515 241.22 16.585 241.57 ;
      RECT 16.515 241.67 16.585 242.02 ;
      RECT 16.515 242.12 16.585 242.47 ;
      RECT 16.515 242.57 16.585 242.92 ;
      RECT 16.515 243.02 16.585 243.37 ;
      RECT 16.515 246.03 16.585 246.38 ;
      RECT 16.515 246.48 16.585 246.83 ;
      RECT 16.515 246.93 16.585 247.28 ;
      RECT 16.515 247.38 16.585 247.73 ;
      RECT 16.515 247.83 16.585 248.18 ;
      RECT 16.515 248.28 16.585 248.63 ;
      RECT 16.515 248.73 16.585 249.08 ;
      RECT 16.515 251.52 16.585 251.87 ;
      RECT 16.515 251.97 16.585 252.32 ;
      RECT 16.515 252.42 16.585 252.77 ;
      RECT 16.515 252.87 16.585 253.22 ;
      RECT 16.515 253.32 16.585 253.67 ;
      RECT 16.515 253.77 16.585 254.12 ;
      RECT 16.515 254.22 16.585 254.57 ;
      RECT 16.515 257.45 16.585 257.8 ;
      RECT 16.515 257.9 16.585 258.25 ;
      RECT 16.515 258.35 16.585 258.7 ;
      RECT 16.515 258.8 16.585 259.15 ;
      RECT 16.515 259.25 16.585 259.6 ;
      RECT 16.515 259.7 16.585 260.05 ;
      RECT 16.515 263.01 16.585 263.36 ;
      RECT 16.515 263.46 16.585 263.81 ;
      RECT 16.515 263.91 16.585 264.26 ;
      RECT 16.515 264.36 16.585 264.71 ;
      RECT 16.515 264.81 16.585 265.16 ;
      RECT 16.515 265.26 16.585 265.61 ;
      RECT 16.515 268.26 16.585 268.61 ;
      RECT 16.515 268.71 16.585 269.06 ;
      RECT 16.515 269.16 16.585 269.51 ;
      RECT 16.515 269.61 16.585 269.96 ;
      RECT 16.515 270.06 16.585 270.41 ;
      RECT 16.515 270.51 16.585 270.86 ;
      RECT 16.515 270.96 16.585 271.31 ;
      RECT 16.515 273.75 16.585 274.1 ;
      RECT 16.515 274.2 16.585 274.55 ;
      RECT 16.515 274.65 16.585 275 ;
      RECT 16.515 275.1 16.585 275.45 ;
      RECT 16.515 275.55 16.585 275.9 ;
      RECT 16.515 276 16.585 276.35 ;
      RECT 16.515 276.45 16.585 276.8 ;
      RECT 16.515 279.69 16.585 280.04 ;
      RECT 16.515 280.14 16.585 280.49 ;
      RECT 16.515 280.59 16.585 280.94 ;
      RECT 16.515 281.04 16.585 281.39 ;
      RECT 16.515 281.49 16.585 281.84 ;
      RECT 16.515 281.94 16.585 282.29 ;
      RECT 16.515 285.25 16.585 285.6 ;
      RECT 16.515 285.7 16.585 286.05 ;
      RECT 16.515 286.15 16.585 286.5 ;
      RECT 16.515 286.6 16.585 286.95 ;
      RECT 16.515 287.05 16.585 287.4 ;
      RECT 16.515 287.5 16.585 287.85 ;
      RECT 16.515 290.52 16.585 290.87 ;
      RECT 16.515 290.97 16.585 291.32 ;
      RECT 16.515 291.42 16.585 291.77 ;
      RECT 16.515 291.87 16.585 292.22 ;
      RECT 16.515 292.32 16.585 292.67 ;
      RECT 16.515 292.77 16.585 293.12 ;
      RECT 16.515 293.22 16.585 293.57 ;
      RECT 16.515 296.01 16.585 296.36 ;
      RECT 16.515 296.46 16.585 296.81 ;
      RECT 16.515 296.91 16.585 297.26 ;
      RECT 16.515 297.36 16.585 297.71 ;
      RECT 16.515 297.81 16.585 298.16 ;
      RECT 16.515 298.26 16.585 298.61 ;
      RECT 16.515 298.71 16.585 299.06 ;
      RECT 16.515 301.93 16.585 302.28 ;
      RECT 16.515 302.38 16.585 302.73 ;
      RECT 16.515 302.83 16.585 303.18 ;
      RECT 16.515 303.28 16.585 303.63 ;
      RECT 16.515 303.73 16.585 304.08 ;
      RECT 16.515 304.18 16.585 304.53 ;
      RECT 16.515 307.49 16.585 307.84 ;
      RECT 16.515 307.94 16.585 308.29 ;
      RECT 16.515 308.39 16.585 308.74 ;
      RECT 16.515 308.84 16.585 309.19 ;
      RECT 16.515 309.29 16.585 309.64 ;
      RECT 16.515 309.74 16.585 310.09 ;
      RECT 16.515 312.75 16.585 313.1 ;
      RECT 16.515 313.2 16.585 313.55 ;
      RECT 16.515 313.65 16.585 314 ;
      RECT 16.515 314.1 16.585 314.45 ;
      RECT 16.515 314.55 16.585 314.9 ;
      RECT 16.515 315 16.585 315.35 ;
      RECT 16.515 315.45 16.585 315.8 ;
      RECT 16.515 318.27 16.585 318.62 ;
      RECT 16.515 318.72 16.585 319.07 ;
      RECT 16.515 319.17 16.585 319.52 ;
      RECT 16.515 319.62 16.585 319.97 ;
      RECT 16.515 320.07 16.585 320.42 ;
      RECT 16.515 320.52 16.585 320.87 ;
      RECT 16.515 320.97 16.585 321.32 ;
      RECT 16.515 324.17 16.585 324.52 ;
      RECT 16.515 324.62 16.585 324.97 ;
      RECT 16.515 325.07 16.585 325.42 ;
      RECT 16.515 325.52 16.585 325.87 ;
      RECT 16.515 325.97 16.585 326.32 ;
      RECT 16.515 326.42 16.585 326.77 ;
      RECT 16.515 329.73 16.585 330.08 ;
      RECT 16.515 330.18 16.585 330.53 ;
      RECT 16.515 330.63 16.585 330.98 ;
      RECT 16.515 331.08 16.585 331.43 ;
      RECT 16.515 331.53 16.585 331.88 ;
      RECT 16.515 331.98 16.585 332.33 ;
      RECT 16.515 334.98 16.585 335.33 ;
      RECT 16.515 335.43 16.585 335.78 ;
      RECT 16.515 335.88 16.585 336.23 ;
      RECT 16.515 336.33 16.585 336.68 ;
      RECT 16.515 336.78 16.585 337.13 ;
      RECT 16.515 337.23 16.585 337.58 ;
      RECT 16.515 337.68 16.585 338.03 ;
      RECT 16.515 340.5 16.585 340.85 ;
      RECT 16.515 340.95 16.585 341.3 ;
      RECT 16.515 341.4 16.585 341.75 ;
      RECT 16.515 341.85 16.585 342.2 ;
      RECT 16.515 342.3 16.585 342.65 ;
      RECT 16.515 342.75 16.585 343.1 ;
      RECT 16.515 343.2 16.585 343.55 ;
      RECT 0.735 4.855 10.285 5.275 ;
      RECT 0.735 10.415 10.285 10.835 ;
      RECT 0.735 15.975 10.285 16.395 ;
      RECT 0.735 21.535 10.285 21.955 ;
      RECT 0.735 29.335 10.285 29.755 ;
      RECT 0.735 34.895 10.285 35.315 ;
      RECT 0.735 40.455 10.285 40.875 ;
      RECT 0.735 46.015 10.285 46.435 ;
      RECT 0.735 51.575 10.285 51.995 ;
      RECT 0.735 57.135 10.285 57.555 ;
      RECT 0.735 62.695 10.285 63.115 ;
      RECT 0.735 68.255 10.285 68.675 ;
      RECT 0.735 73.815 10.285 74.235 ;
      RECT 0.735 79.375 10.285 79.795 ;
      RECT 0.735 84.935 10.285 85.355 ;
      RECT 0.735 90.495 10.285 90.915 ;
      RECT 0.735 96.055 10.285 96.475 ;
      RECT 0.735 101.615 10.285 102.035 ;
      RECT 0.735 107.175 10.285 107.595 ;
      RECT 0.735 112.735 10.285 113.155 ;
      RECT 0.735 118.295 10.285 118.715 ;
      RECT 0.735 123.855 10.285 124.275 ;
      RECT 0.735 129.415 10.285 129.835 ;
      RECT 0.735 134.975 10.285 135.395 ;
      RECT 0.735 140.535 10.285 140.955 ;
      RECT 0.735 146.095 10.285 146.515 ;
      RECT 0.735 151.655 10.285 152.075 ;
      RECT 0.735 157.215 10.285 157.635 ;
      RECT 0.735 162.775 10.285 163.195 ;
      RECT 0.735 168.335 10.285 168.755 ;
      RECT 0.735 173.895 10.285 174.315 ;
      RECT 0.735 179.455 10.285 179.875 ;
      RECT 0.735 185.015 10.285 185.435 ;
      RECT 0.735 190.575 10.285 190.995 ;
      RECT 0.735 196.135 10.285 196.555 ;
      RECT 0.735 201.695 10.285 202.115 ;
      RECT 0.735 207.255 10.285 207.675 ;
      RECT 0.735 212.815 10.285 213.235 ;
      RECT 0.735 218.375 10.285 218.795 ;
      RECT 0.735 223.935 10.285 224.355 ;
      RECT 0.735 229.495 10.285 229.915 ;
      RECT 0.735 235.055 10.285 235.475 ;
      RECT 0.735 240.615 10.285 241.035 ;
      RECT 0.735 246.175 10.285 246.595 ;
      RECT 0.735 251.735 10.285 252.155 ;
      RECT 0.735 257.295 10.285 257.715 ;
      RECT 0.735 262.855 10.285 263.275 ;
      RECT 0.735 268.415 10.285 268.835 ;
      RECT 0.735 273.975 10.285 274.395 ;
      RECT 0.735 279.535 10.285 279.955 ;
      RECT 0.735 285.095 10.285 285.515 ;
      RECT 0.735 290.655 10.285 291.075 ;
      RECT 0.735 296.215 10.285 296.635 ;
      RECT 0.735 301.775 10.285 302.195 ;
      RECT 0.735 307.335 10.285 307.755 ;
      RECT 0.735 312.895 10.285 313.315 ;
      RECT 0.735 318.455 10.285 318.875 ;
      RECT 0.735 324.015 10.285 324.435 ;
      RECT 0.735 329.575 10.285 329.995 ;
      RECT 0.735 335.135 10.285 335.555 ;
      RECT 0.735 340.695 10.285 341.115 ;
      RECT 5.55 68.87 5.62 69.22 ;
      RECT 5.55 69.32 5.62 69.67 ;
      RECT 5.55 69.77 5.62 70.12 ;
      RECT 5.55 70.22 5.62 70.57 ;
      RECT 5.55 70.67 5.62 71.02 ;
      RECT 5.55 71.12 5.62 71.47 ;
      RECT 5.55 71.57 5.62 71.92 ;
      RECT 5.54 91.11 5.61 91.46 ;
      RECT 5.54 91.56 5.61 91.91 ;
      RECT 5.54 92.01 5.61 92.36 ;
      RECT 5.54 92.46 5.61 92.81 ;
      RECT 5.54 92.91 5.61 93.26 ;
      RECT 5.54 93.36 5.61 93.71 ;
      RECT 5.54 93.81 5.61 94.16 ;
      RECT 5.535 6.935 5.605 7.285 ;
      RECT 5.535 7.385 5.605 7.735 ;
      RECT 5.535 7.835 5.605 8.185 ;
      RECT 5.535 8.285 5.605 8.635 ;
      RECT 5.535 8.735 5.605 9.085 ;
      RECT 5.535 9.185 5.605 9.535 ;
      RECT 5.535 9.635 5.605 9.985 ;
      RECT 5.535 12.51 5.605 12.86 ;
      RECT 5.535 12.96 5.605 13.31 ;
      RECT 5.535 13.41 5.605 13.76 ;
      RECT 5.535 13.86 5.605 14.21 ;
      RECT 5.535 14.31 5.605 14.66 ;
      RECT 5.535 14.76 5.605 15.11 ;
      RECT 5.535 15.21 5.605 15.56 ;
      RECT 5.535 18 5.605 18.35 ;
      RECT 5.535 18.45 5.605 18.8 ;
      RECT 5.535 18.9 5.605 19.25 ;
      RECT 5.535 19.35 5.605 19.7 ;
      RECT 5.535 19.8 5.605 20.15 ;
      RECT 5.535 20.25 5.605 20.6 ;
      RECT 5.535 20.7 5.605 21.05 ;
      RECT 5.535 29.95 5.605 30.3 ;
      RECT 5.535 30.4 5.605 30.75 ;
      RECT 5.535 30.85 5.605 31.2 ;
      RECT 5.535 31.3 5.605 31.65 ;
      RECT 5.535 31.75 5.605 32.1 ;
      RECT 5.535 32.2 5.605 32.55 ;
      RECT 5.535 32.65 5.605 33 ;
      RECT 5.535 35.51 5.605 35.86 ;
      RECT 5.535 35.96 5.605 36.31 ;
      RECT 5.535 36.41 5.605 36.76 ;
      RECT 5.535 36.86 5.605 37.21 ;
      RECT 5.535 37.31 5.605 37.66 ;
      RECT 5.535 37.76 5.605 38.11 ;
      RECT 5.535 38.21 5.605 38.56 ;
      RECT 5.535 41.07 5.605 41.42 ;
      RECT 5.535 41.52 5.605 41.87 ;
      RECT 5.535 41.97 5.605 42.32 ;
      RECT 5.535 42.42 5.605 42.77 ;
      RECT 5.535 42.87 5.605 43.22 ;
      RECT 5.535 43.32 5.605 43.67 ;
      RECT 5.535 43.77 5.605 44.12 ;
      RECT 5.535 52.19 5.605 52.54 ;
      RECT 5.535 52.64 5.605 52.99 ;
      RECT 5.535 53.09 5.605 53.44 ;
      RECT 5.535 53.54 5.605 53.89 ;
      RECT 5.535 53.99 5.605 54.34 ;
      RECT 5.535 54.44 5.605 54.79 ;
      RECT 5.535 54.89 5.605 55.24 ;
      RECT 5.535 57.75 5.605 58.1 ;
      RECT 5.535 58.2 5.605 58.55 ;
      RECT 5.535 58.65 5.605 59 ;
      RECT 5.535 59.1 5.605 59.45 ;
      RECT 5.535 59.55 5.605 59.9 ;
      RECT 5.535 60 5.605 60.35 ;
      RECT 5.535 60.45 5.605 60.8 ;
      RECT 5.535 63.31 5.605 63.66 ;
      RECT 5.535 63.76 5.605 64.11 ;
      RECT 5.535 64.21 5.605 64.56 ;
      RECT 5.535 64.66 5.605 65.01 ;
      RECT 5.535 65.11 5.605 65.46 ;
      RECT 5.535 65.56 5.605 65.91 ;
      RECT 5.535 66.01 5.605 66.36 ;
      RECT 5.535 74.43 5.605 74.78 ;
      RECT 5.535 74.88 5.605 75.23 ;
      RECT 5.535 75.33 5.605 75.68 ;
      RECT 5.535 75.78 5.605 76.13 ;
      RECT 5.535 76.23 5.605 76.58 ;
      RECT 5.535 76.68 5.605 77.03 ;
      RECT 5.535 77.13 5.605 77.48 ;
      RECT 5.535 79.99 5.605 80.34 ;
      RECT 5.535 80.44 5.605 80.79 ;
      RECT 5.535 80.89 5.605 81.24 ;
      RECT 5.535 81.34 5.605 81.69 ;
      RECT 5.535 81.79 5.605 82.14 ;
      RECT 5.535 82.24 5.605 82.59 ;
      RECT 5.535 82.69 5.605 83.04 ;
      RECT 5.535 85.55 5.605 85.9 ;
      RECT 5.535 86 5.605 86.35 ;
      RECT 5.535 86.45 5.605 86.8 ;
      RECT 5.535 86.9 5.605 87.25 ;
      RECT 5.535 87.35 5.605 87.7 ;
      RECT 5.535 87.8 5.605 88.15 ;
      RECT 5.535 88.25 5.605 88.6 ;
      RECT 5.535 102.23 5.605 102.58 ;
      RECT 5.535 102.68 5.605 103.03 ;
      RECT 5.535 103.13 5.605 103.48 ;
      RECT 5.535 103.58 5.605 103.93 ;
      RECT 5.535 104.03 5.605 104.38 ;
      RECT 5.535 104.48 5.605 104.83 ;
      RECT 5.535 104.93 5.605 105.28 ;
      RECT 5.535 107.79 5.605 108.14 ;
      RECT 5.535 108.24 5.605 108.59 ;
      RECT 5.535 108.69 5.605 109.04 ;
      RECT 5.535 109.14 5.605 109.49 ;
      RECT 5.535 109.59 5.605 109.94 ;
      RECT 5.535 110.04 5.605 110.39 ;
      RECT 5.535 110.49 5.605 110.84 ;
      RECT 5.535 118.91 5.605 119.26 ;
      RECT 5.535 119.36 5.605 119.71 ;
      RECT 5.535 119.81 5.605 120.16 ;
      RECT 5.535 120.26 5.605 120.61 ;
      RECT 5.535 120.71 5.605 121.06 ;
      RECT 5.535 121.16 5.605 121.51 ;
      RECT 5.535 121.61 5.605 121.96 ;
      RECT 5.535 124.47 5.605 124.82 ;
      RECT 5.535 124.92 5.605 125.27 ;
      RECT 5.535 125.37 5.605 125.72 ;
      RECT 5.535 125.82 5.605 126.17 ;
      RECT 5.535 126.27 5.605 126.62 ;
      RECT 5.535 126.72 5.605 127.07 ;
      RECT 5.535 127.17 5.605 127.52 ;
      RECT 5.535 130.03 5.605 130.38 ;
      RECT 5.535 130.48 5.605 130.83 ;
      RECT 5.535 130.93 5.605 131.28 ;
      RECT 5.535 131.38 5.605 131.73 ;
      RECT 5.535 131.83 5.605 132.18 ;
      RECT 5.535 132.28 5.605 132.63 ;
      RECT 5.535 132.73 5.605 133.08 ;
      RECT 5.535 146.71 5.605 147.06 ;
      RECT 5.535 147.16 5.605 147.51 ;
      RECT 5.535 147.61 5.605 147.96 ;
      RECT 5.535 148.06 5.605 148.41 ;
      RECT 5.535 148.51 5.605 148.86 ;
      RECT 5.535 148.96 5.605 149.31 ;
      RECT 5.535 149.41 5.605 149.76 ;
      RECT 5.535 152.27 5.605 152.62 ;
      RECT 5.535 152.72 5.605 153.07 ;
      RECT 5.535 153.17 5.605 153.52 ;
      RECT 5.535 153.62 5.605 153.97 ;
      RECT 5.535 154.07 5.605 154.42 ;
      RECT 5.535 154.52 5.605 154.87 ;
      RECT 5.535 154.97 5.605 155.32 ;
      RECT 5.535 168.95 5.605 169.3 ;
      RECT 5.535 169.4 5.605 169.75 ;
      RECT 5.535 169.85 5.605 170.2 ;
      RECT 5.535 170.3 5.605 170.65 ;
      RECT 5.535 170.75 5.605 171.1 ;
      RECT 5.535 171.2 5.605 171.55 ;
      RECT 5.535 171.65 5.605 172 ;
      RECT 5.535 174.51 5.605 174.86 ;
      RECT 5.535 174.96 5.605 175.31 ;
      RECT 5.535 175.41 5.605 175.76 ;
      RECT 5.535 175.86 5.605 176.21 ;
      RECT 5.535 176.31 5.605 176.66 ;
      RECT 5.535 176.76 5.605 177.11 ;
      RECT 5.535 177.21 5.605 177.56 ;
      RECT 5.535 191.19 5.605 191.54 ;
      RECT 5.535 191.64 5.605 191.99 ;
      RECT 5.535 192.09 5.605 192.44 ;
      RECT 5.535 192.54 5.605 192.89 ;
      RECT 5.535 192.99 5.605 193.34 ;
      RECT 5.535 193.44 5.605 193.79 ;
      RECT 5.535 193.89 5.605 194.24 ;
      RECT 5.535 196.75 5.605 197.1 ;
      RECT 5.535 197.2 5.605 197.55 ;
      RECT 5.535 197.65 5.605 198 ;
      RECT 5.535 198.1 5.605 198.45 ;
      RECT 5.535 198.55 5.605 198.9 ;
      RECT 5.535 199 5.605 199.35 ;
      RECT 5.535 199.45 5.605 199.8 ;
      RECT 5.535 213.43 5.605 213.78 ;
      RECT 5.535 213.88 5.605 214.23 ;
      RECT 5.535 214.33 5.605 214.68 ;
      RECT 5.535 214.78 5.605 215.13 ;
      RECT 5.535 215.23 5.605 215.58 ;
      RECT 5.535 215.68 5.605 216.03 ;
      RECT 5.535 216.13 5.605 216.48 ;
      RECT 5.535 218.99 5.605 219.34 ;
      RECT 5.535 219.44 5.605 219.79 ;
      RECT 5.535 219.89 5.605 220.24 ;
      RECT 5.535 220.34 5.605 220.69 ;
      RECT 5.535 220.79 5.605 221.14 ;
      RECT 5.535 221.24 5.605 221.59 ;
      RECT 5.535 221.69 5.605 222.04 ;
      RECT 5.535 235.67 5.605 236.02 ;
      RECT 5.535 236.12 5.605 236.47 ;
      RECT 5.535 236.57 5.605 236.92 ;
      RECT 5.535 237.02 5.605 237.37 ;
      RECT 5.535 237.47 5.605 237.82 ;
      RECT 5.535 237.92 5.605 238.27 ;
      RECT 5.535 238.37 5.605 238.72 ;
      RECT 5.535 241.23 5.605 241.58 ;
      RECT 5.535 241.68 5.605 242.03 ;
      RECT 5.535 242.13 5.605 242.48 ;
      RECT 5.535 242.58 5.605 242.93 ;
      RECT 5.535 243.03 5.605 243.38 ;
      RECT 5.535 243.48 5.605 243.83 ;
      RECT 5.535 243.93 5.605 244.28 ;
      RECT 5.535 257.91 5.605 258.26 ;
      RECT 5.535 258.36 5.605 258.71 ;
      RECT 5.535 258.81 5.605 259.16 ;
      RECT 5.535 259.26 5.605 259.61 ;
      RECT 5.535 259.71 5.605 260.06 ;
      RECT 5.535 260.16 5.605 260.51 ;
      RECT 5.535 260.61 5.605 260.96 ;
      RECT 5.535 263.47 5.605 263.82 ;
      RECT 5.535 263.92 5.605 264.27 ;
      RECT 5.535 264.37 5.605 264.72 ;
      RECT 5.535 264.82 5.605 265.17 ;
      RECT 5.535 265.27 5.605 265.62 ;
      RECT 5.535 265.72 5.605 266.07 ;
      RECT 5.535 266.17 5.605 266.52 ;
      RECT 5.535 280.15 5.605 280.5 ;
      RECT 5.535 280.6 5.605 280.95 ;
      RECT 5.535 281.05 5.605 281.4 ;
      RECT 5.535 281.5 5.605 281.85 ;
      RECT 5.535 281.95 5.605 282.3 ;
      RECT 5.535 282.4 5.605 282.75 ;
      RECT 5.535 282.85 5.605 283.2 ;
      RECT 5.535 285.71 5.605 286.06 ;
      RECT 5.535 286.16 5.605 286.51 ;
      RECT 5.535 286.61 5.605 286.96 ;
      RECT 5.535 287.06 5.605 287.41 ;
      RECT 5.535 287.51 5.605 287.86 ;
      RECT 5.535 287.96 5.605 288.31 ;
      RECT 5.535 288.41 5.605 288.76 ;
      RECT 5.535 302.39 5.605 302.74 ;
      RECT 5.535 302.84 5.605 303.19 ;
      RECT 5.535 303.29 5.605 303.64 ;
      RECT 5.535 303.74 5.605 304.09 ;
      RECT 5.535 304.19 5.605 304.54 ;
      RECT 5.535 304.64 5.605 304.99 ;
      RECT 5.535 305.09 5.605 305.44 ;
      RECT 5.535 307.95 5.605 308.3 ;
      RECT 5.535 308.4 5.605 308.75 ;
      RECT 5.535 308.85 5.605 309.2 ;
      RECT 5.535 309.3 5.605 309.65 ;
      RECT 5.535 309.75 5.605 310.1 ;
      RECT 5.535 310.2 5.605 310.55 ;
      RECT 5.535 310.65 5.605 311 ;
      RECT 5.535 313.51 5.605 313.86 ;
      RECT 5.535 313.96 5.605 314.31 ;
      RECT 5.535 314.41 5.605 314.76 ;
      RECT 5.535 314.86 5.605 315.21 ;
      RECT 5.535 315.31 5.605 315.66 ;
      RECT 5.535 315.76 5.605 316.11 ;
      RECT 5.535 316.21 5.605 316.56 ;
      RECT 5.535 324.63 5.605 324.98 ;
      RECT 5.535 325.08 5.605 325.43 ;
      RECT 5.535 325.53 5.605 325.88 ;
      RECT 5.535 325.98 5.605 326.33 ;
      RECT 5.535 326.43 5.605 326.78 ;
      RECT 5.535 326.88 5.605 327.23 ;
      RECT 5.535 327.33 5.605 327.68 ;
      RECT 5.535 330.19 5.605 330.54 ;
      RECT 5.535 330.64 5.605 330.99 ;
      RECT 5.535 331.09 5.605 331.44 ;
      RECT 5.535 331.54 5.605 331.89 ;
      RECT 5.535 331.99 5.605 332.34 ;
      RECT 5.535 332.44 5.605 332.79 ;
      RECT 5.535 332.89 5.605 333.24 ;
      RECT 5.535 335.75 5.605 336.1 ;
      RECT 5.535 336.2 5.605 336.55 ;
      RECT 5.535 336.65 5.605 337 ;
      RECT 5.535 337.1 5.605 337.45 ;
      RECT 5.535 337.55 5.605 337.9 ;
      RECT 5.535 338 5.605 338.35 ;
      RECT 5.535 338.45 5.605 338.8 ;
      RECT 5.53 96.67 5.6 97.02 ;
      RECT 5.53 97.12 5.6 97.47 ;
      RECT 5.53 97.57 5.6 97.92 ;
      RECT 5.53 98.02 5.6 98.37 ;
      RECT 5.53 98.47 5.6 98.82 ;
      RECT 5.53 98.92 5.6 99.27 ;
      RECT 5.53 99.37 5.6 99.72 ;
      RECT 5.53 113.35 5.6 113.7 ;
      RECT 5.53 113.8 5.6 114.15 ;
      RECT 5.53 114.25 5.6 114.6 ;
      RECT 5.53 114.7 5.6 115.05 ;
      RECT 5.53 115.15 5.6 115.5 ;
      RECT 5.53 115.6 5.6 115.95 ;
      RECT 5.53 116.05 5.6 116.4 ;
      RECT 5.52 135.59 5.59 135.94 ;
      RECT 5.52 136.04 5.59 136.39 ;
      RECT 5.52 136.49 5.59 136.84 ;
      RECT 5.52 136.94 5.59 137.29 ;
      RECT 5.52 137.39 5.59 137.74 ;
      RECT 5.52 137.84 5.59 138.19 ;
      RECT 5.52 138.29 5.59 138.64 ;
      RECT 5.51 141.15 5.58 141.5 ;
      RECT 5.51 141.6 5.58 141.95 ;
      RECT 5.51 142.05 5.58 142.4 ;
      RECT 5.51 142.5 5.58 142.85 ;
      RECT 5.51 142.95 5.58 143.3 ;
      RECT 5.51 143.4 5.58 143.75 ;
      RECT 5.51 143.85 5.58 144.2 ;
      RECT 5.51 157.83 5.58 158.18 ;
      RECT 5.51 158.28 5.58 158.63 ;
      RECT 5.51 158.73 5.58 159.08 ;
      RECT 5.51 159.18 5.58 159.53 ;
      RECT 5.51 159.63 5.58 159.98 ;
      RECT 5.51 160.08 5.58 160.43 ;
      RECT 5.51 160.53 5.58 160.88 ;
      RECT 5.505 341.31 5.575 341.66 ;
      RECT 5.505 341.76 5.575 342.11 ;
      RECT 5.505 342.21 5.575 342.56 ;
      RECT 5.505 342.66 5.575 343.01 ;
      RECT 5.505 343.11 5.575 343.46 ;
      RECT 5.505 343.56 5.575 343.91 ;
      RECT 5.505 344.01 5.575 344.36 ;
      RECT 5.5 163.39 5.57 163.74 ;
      RECT 5.5 163.84 5.57 164.19 ;
      RECT 5.5 164.29 5.57 164.64 ;
      RECT 5.5 164.74 5.57 165.09 ;
      RECT 5.5 165.19 5.57 165.54 ;
      RECT 5.5 165.64 5.57 165.99 ;
      RECT 5.5 166.09 5.57 166.44 ;
      RECT 5.5 180.07 5.57 180.42 ;
      RECT 5.5 180.52 5.57 180.87 ;
      RECT 5.5 180.97 5.57 181.32 ;
      RECT 5.5 181.42 5.57 181.77 ;
      RECT 5.5 181.87 5.57 182.22 ;
      RECT 5.5 182.32 5.57 182.67 ;
      RECT 5.5 182.77 5.57 183.12 ;
      RECT 5.49 185.63 5.56 185.98 ;
      RECT 5.49 186.08 5.56 186.43 ;
      RECT 5.49 186.53 5.56 186.88 ;
      RECT 5.49 186.98 5.56 187.33 ;
      RECT 5.49 187.43 5.56 187.78 ;
      RECT 5.49 187.88 5.56 188.23 ;
      RECT 5.49 188.33 5.56 188.68 ;
      RECT 5.49 202.31 5.56 202.66 ;
      RECT 5.49 202.76 5.56 203.11 ;
      RECT 5.49 203.21 5.56 203.56 ;
      RECT 5.49 203.66 5.56 204.01 ;
      RECT 5.49 204.11 5.56 204.46 ;
      RECT 5.49 204.56 5.56 204.91 ;
      RECT 5.49 205.01 5.56 205.36 ;
      RECT 5.48 1.505 5.55 1.855 ;
      RECT 5.48 1.955 5.55 2.305 ;
      RECT 5.48 2.405 5.55 2.755 ;
      RECT 5.48 2.855 5.55 3.205 ;
      RECT 5.48 3.305 5.55 3.655 ;
      RECT 5.48 3.755 5.55 4.105 ;
      RECT 5.48 4.205 5.55 4.555 ;
      RECT 5.48 207.87 5.55 208.22 ;
      RECT 5.48 208.32 5.55 208.67 ;
      RECT 5.48 208.77 5.55 209.12 ;
      RECT 5.48 209.22 5.55 209.57 ;
      RECT 5.48 209.67 5.55 210.02 ;
      RECT 5.48 210.12 5.55 210.47 ;
      RECT 5.48 210.57 5.55 210.92 ;
      RECT 5.48 224.55 5.55 224.9 ;
      RECT 5.48 225 5.55 225.35 ;
      RECT 5.48 225.45 5.55 225.8 ;
      RECT 5.48 225.9 5.55 226.25 ;
      RECT 5.48 226.35 5.55 226.7 ;
      RECT 5.48 226.8 5.55 227.15 ;
      RECT 5.48 227.25 5.55 227.6 ;
      RECT 5.47 230.11 5.54 230.46 ;
      RECT 5.47 230.56 5.54 230.91 ;
      RECT 5.47 231.01 5.54 231.36 ;
      RECT 5.47 231.46 5.54 231.81 ;
      RECT 5.47 231.91 5.54 232.26 ;
      RECT 5.47 232.36 5.54 232.71 ;
      RECT 5.47 232.81 5.54 233.16 ;
      RECT 5.47 246.79 5.54 247.14 ;
      RECT 5.47 247.24 5.54 247.59 ;
      RECT 5.47 247.69 5.54 248.04 ;
      RECT 5.47 248.14 5.54 248.49 ;
      RECT 5.47 248.59 5.54 248.94 ;
      RECT 5.47 249.04 5.54 249.39 ;
      RECT 5.47 249.49 5.54 249.84 ;
      RECT 5.46 252.35 5.53 252.7 ;
      RECT 5.46 252.8 5.53 253.15 ;
      RECT 5.46 253.25 5.53 253.6 ;
      RECT 5.46 253.7 5.53 254.05 ;
      RECT 5.46 254.15 5.53 254.5 ;
      RECT 5.46 254.6 5.53 254.95 ;
      RECT 5.46 255.05 5.53 255.4 ;
      RECT 5.46 269.03 5.53 269.38 ;
      RECT 5.46 269.48 5.53 269.83 ;
      RECT 5.46 269.93 5.53 270.28 ;
      RECT 5.46 270.38 5.53 270.73 ;
      RECT 5.46 270.83 5.53 271.18 ;
      RECT 5.46 271.28 5.53 271.63 ;
      RECT 5.46 271.73 5.53 272.08 ;
      RECT 5.45 274.59 5.52 274.94 ;
      RECT 5.45 275.04 5.52 275.39 ;
      RECT 5.45 275.49 5.52 275.84 ;
      RECT 5.45 275.94 5.52 276.29 ;
      RECT 5.45 276.39 5.52 276.74 ;
      RECT 5.45 276.84 5.52 277.19 ;
      RECT 5.45 277.29 5.52 277.64 ;
      RECT 5.45 291.27 5.52 291.62 ;
      RECT 5.45 291.72 5.52 292.07 ;
      RECT 5.45 292.17 5.52 292.52 ;
      RECT 5.45 292.62 5.52 292.97 ;
      RECT 5.45 293.07 5.52 293.42 ;
      RECT 5.45 293.52 5.52 293.87 ;
      RECT 5.45 293.97 5.52 294.32 ;
      RECT 5.44 296.83 5.51 297.18 ;
      RECT 5.44 297.28 5.51 297.63 ;
      RECT 5.44 297.73 5.51 298.08 ;
      RECT 5.44 298.18 5.51 298.53 ;
      RECT 5.44 298.63 5.51 298.98 ;
      RECT 5.44 299.08 5.51 299.43 ;
      RECT 5.44 299.53 5.51 299.88 ;
      RECT 5.43 319.07 5.5 319.42 ;
      RECT 5.43 319.52 5.5 319.87 ;
      RECT 5.43 319.97 5.5 320.32 ;
      RECT 5.43 320.42 5.5 320.77 ;
      RECT 5.43 320.87 5.5 321.22 ;
      RECT 5.43 321.32 5.5 321.67 ;
      RECT 5.43 321.77 5.5 322.12 ;
      RECT 5.42 46.63 5.49 46.98 ;
      RECT 5.42 47.08 5.49 47.43 ;
      RECT 5.42 47.53 5.49 47.88 ;
      RECT 5.42 47.98 5.49 48.33 ;
      RECT 5.42 48.43 5.49 48.78 ;
      RECT 5.42 48.88 5.49 49.23 ;
      RECT 5.42 49.33 5.49 49.68 ;
      RECT 5.41 68.87 5.48 69.22 ;
      RECT 5.41 69.32 5.48 69.67 ;
      RECT 5.41 69.77 5.48 70.12 ;
      RECT 5.41 70.22 5.48 70.57 ;
      RECT 5.41 70.67 5.48 71.02 ;
      RECT 5.41 71.12 5.48 71.47 ;
      RECT 5.41 71.57 5.48 71.92 ;
      RECT 5.4 91.11 5.47 91.46 ;
      RECT 5.4 91.56 5.47 91.91 ;
      RECT 5.4 92.01 5.47 92.36 ;
      RECT 5.4 92.46 5.47 92.81 ;
      RECT 5.4 92.91 5.47 93.26 ;
      RECT 5.4 93.36 5.47 93.71 ;
      RECT 5.4 93.81 5.47 94.16 ;
      RECT 5.395 6.935 5.465 7.285 ;
      RECT 5.395 7.385 5.465 7.735 ;
      RECT 5.395 7.835 5.465 8.185 ;
      RECT 5.395 8.285 5.465 8.635 ;
      RECT 5.395 8.735 5.465 9.085 ;
      RECT 5.395 9.185 5.465 9.535 ;
      RECT 5.395 9.635 5.465 9.985 ;
      RECT 5.395 12.51 5.465 12.86 ;
      RECT 5.395 12.96 5.465 13.31 ;
      RECT 5.395 13.41 5.465 13.76 ;
      RECT 5.395 13.86 5.465 14.21 ;
      RECT 5.395 14.31 5.465 14.66 ;
      RECT 5.395 14.76 5.465 15.11 ;
      RECT 5.395 15.21 5.465 15.56 ;
      RECT 5.395 18 5.465 18.35 ;
      RECT 5.395 18.45 5.465 18.8 ;
      RECT 5.395 18.9 5.465 19.25 ;
      RECT 5.395 19.35 5.465 19.7 ;
      RECT 5.395 19.8 5.465 20.15 ;
      RECT 5.395 20.25 5.465 20.6 ;
      RECT 5.395 20.7 5.465 21.05 ;
      RECT 5.395 29.95 5.465 30.3 ;
      RECT 5.395 30.4 5.465 30.75 ;
      RECT 5.395 30.85 5.465 31.2 ;
      RECT 5.395 31.3 5.465 31.65 ;
      RECT 5.395 31.75 5.465 32.1 ;
      RECT 5.395 32.2 5.465 32.55 ;
      RECT 5.395 32.65 5.465 33 ;
      RECT 5.395 35.51 5.465 35.86 ;
      RECT 5.395 35.96 5.465 36.31 ;
      RECT 5.395 36.41 5.465 36.76 ;
      RECT 5.395 36.86 5.465 37.21 ;
      RECT 5.395 37.31 5.465 37.66 ;
      RECT 5.395 37.76 5.465 38.11 ;
      RECT 5.395 38.21 5.465 38.56 ;
      RECT 5.395 41.07 5.465 41.42 ;
      RECT 5.395 41.52 5.465 41.87 ;
      RECT 5.395 41.97 5.465 42.32 ;
      RECT 5.395 42.42 5.465 42.77 ;
      RECT 5.395 42.87 5.465 43.22 ;
      RECT 5.395 43.32 5.465 43.67 ;
      RECT 5.395 43.77 5.465 44.12 ;
      RECT 5.395 52.19 5.465 52.54 ;
      RECT 5.395 52.64 5.465 52.99 ;
      RECT 5.395 53.09 5.465 53.44 ;
      RECT 5.395 53.54 5.465 53.89 ;
      RECT 5.395 53.99 5.465 54.34 ;
      RECT 5.395 54.44 5.465 54.79 ;
      RECT 5.395 54.89 5.465 55.24 ;
      RECT 5.395 57.75 5.465 58.1 ;
      RECT 5.395 58.2 5.465 58.55 ;
      RECT 5.395 58.65 5.465 59 ;
      RECT 5.395 59.1 5.465 59.45 ;
      RECT 5.395 59.55 5.465 59.9 ;
      RECT 5.395 60 5.465 60.35 ;
      RECT 5.395 60.45 5.465 60.8 ;
      RECT 5.395 63.31 5.465 63.66 ;
      RECT 5.395 63.76 5.465 64.11 ;
      RECT 5.395 64.21 5.465 64.56 ;
      RECT 5.395 64.66 5.465 65.01 ;
      RECT 5.395 65.11 5.465 65.46 ;
      RECT 5.395 65.56 5.465 65.91 ;
      RECT 5.395 66.01 5.465 66.36 ;
      RECT 5.395 74.43 5.465 74.78 ;
      RECT 5.395 74.88 5.465 75.23 ;
      RECT 5.395 75.33 5.465 75.68 ;
      RECT 5.395 75.78 5.465 76.13 ;
      RECT 5.395 76.23 5.465 76.58 ;
      RECT 5.395 76.68 5.465 77.03 ;
      RECT 5.395 77.13 5.465 77.48 ;
      RECT 5.395 79.99 5.465 80.34 ;
      RECT 5.395 80.44 5.465 80.79 ;
      RECT 5.395 80.89 5.465 81.24 ;
      RECT 5.395 81.34 5.465 81.69 ;
      RECT 5.395 81.79 5.465 82.14 ;
      RECT 5.395 82.24 5.465 82.59 ;
      RECT 5.395 82.69 5.465 83.04 ;
      RECT 5.395 85.55 5.465 85.9 ;
      RECT 5.395 86 5.465 86.35 ;
      RECT 5.395 86.45 5.465 86.8 ;
      RECT 5.395 86.9 5.465 87.25 ;
      RECT 5.395 87.35 5.465 87.7 ;
      RECT 5.395 87.8 5.465 88.15 ;
      RECT 5.395 88.25 5.465 88.6 ;
      RECT 5.395 102.23 5.465 102.58 ;
      RECT 5.395 102.68 5.465 103.03 ;
      RECT 5.395 103.13 5.465 103.48 ;
      RECT 5.395 103.58 5.465 103.93 ;
      RECT 5.395 104.03 5.465 104.38 ;
      RECT 5.395 104.48 5.465 104.83 ;
      RECT 5.395 104.93 5.465 105.28 ;
      RECT 5.395 107.79 5.465 108.14 ;
      RECT 5.395 108.24 5.465 108.59 ;
      RECT 5.395 108.69 5.465 109.04 ;
      RECT 5.395 109.14 5.465 109.49 ;
      RECT 5.395 109.59 5.465 109.94 ;
      RECT 5.395 110.04 5.465 110.39 ;
      RECT 5.395 110.49 5.465 110.84 ;
      RECT 5.395 118.91 5.465 119.26 ;
      RECT 5.395 119.36 5.465 119.71 ;
      RECT 5.395 119.81 5.465 120.16 ;
      RECT 5.395 120.26 5.465 120.61 ;
      RECT 5.395 120.71 5.465 121.06 ;
      RECT 5.395 121.16 5.465 121.51 ;
      RECT 5.395 121.61 5.465 121.96 ;
      RECT 5.395 124.47 5.465 124.82 ;
      RECT 5.395 124.92 5.465 125.27 ;
      RECT 5.395 125.37 5.465 125.72 ;
      RECT 5.395 125.82 5.465 126.17 ;
      RECT 5.395 126.27 5.465 126.62 ;
      RECT 5.395 126.72 5.465 127.07 ;
      RECT 5.395 127.17 5.465 127.52 ;
      RECT 5.395 130.03 5.465 130.38 ;
      RECT 5.395 130.48 5.465 130.83 ;
      RECT 5.395 130.93 5.465 131.28 ;
      RECT 5.395 131.38 5.465 131.73 ;
      RECT 5.395 131.83 5.465 132.18 ;
      RECT 5.395 132.28 5.465 132.63 ;
      RECT 5.395 132.73 5.465 133.08 ;
      RECT 5.395 146.71 5.465 147.06 ;
      RECT 5.395 147.16 5.465 147.51 ;
      RECT 5.395 147.61 5.465 147.96 ;
      RECT 5.395 148.06 5.465 148.41 ;
      RECT 5.395 148.51 5.465 148.86 ;
      RECT 5.395 148.96 5.465 149.31 ;
      RECT 5.395 149.41 5.465 149.76 ;
      RECT 5.395 152.27 5.465 152.62 ;
      RECT 5.395 152.72 5.465 153.07 ;
      RECT 5.395 153.17 5.465 153.52 ;
      RECT 5.395 153.62 5.465 153.97 ;
      RECT 5.395 154.07 5.465 154.42 ;
      RECT 5.395 154.52 5.465 154.87 ;
      RECT 5.395 154.97 5.465 155.32 ;
      RECT 5.395 168.95 5.465 169.3 ;
      RECT 5.395 169.4 5.465 169.75 ;
      RECT 5.395 169.85 5.465 170.2 ;
      RECT 5.395 170.3 5.465 170.65 ;
      RECT 5.395 170.75 5.465 171.1 ;
      RECT 5.395 171.2 5.465 171.55 ;
      RECT 5.395 171.65 5.465 172 ;
      RECT 5.395 174.51 5.465 174.86 ;
      RECT 5.395 174.96 5.465 175.31 ;
      RECT 5.395 175.41 5.465 175.76 ;
      RECT 5.395 175.86 5.465 176.21 ;
      RECT 5.395 176.31 5.465 176.66 ;
      RECT 5.395 176.76 5.465 177.11 ;
      RECT 5.395 177.21 5.465 177.56 ;
      RECT 5.395 191.19 5.465 191.54 ;
      RECT 5.395 191.64 5.465 191.99 ;
      RECT 5.395 192.09 5.465 192.44 ;
      RECT 5.395 192.54 5.465 192.89 ;
      RECT 5.395 192.99 5.465 193.34 ;
      RECT 5.395 193.44 5.465 193.79 ;
      RECT 5.395 193.89 5.465 194.24 ;
      RECT 5.395 196.75 5.465 197.1 ;
      RECT 5.395 197.2 5.465 197.55 ;
      RECT 5.395 197.65 5.465 198 ;
      RECT 5.395 198.1 5.465 198.45 ;
      RECT 5.395 198.55 5.465 198.9 ;
      RECT 5.395 199 5.465 199.35 ;
      RECT 5.395 199.45 5.465 199.8 ;
      RECT 5.395 213.43 5.465 213.78 ;
      RECT 5.395 213.88 5.465 214.23 ;
      RECT 5.395 214.33 5.465 214.68 ;
      RECT 5.395 214.78 5.465 215.13 ;
      RECT 5.395 215.23 5.465 215.58 ;
      RECT 5.395 215.68 5.465 216.03 ;
      RECT 5.395 216.13 5.465 216.48 ;
      RECT 5.395 218.99 5.465 219.34 ;
      RECT 5.395 219.44 5.465 219.79 ;
      RECT 5.395 219.89 5.465 220.24 ;
      RECT 5.395 220.34 5.465 220.69 ;
      RECT 5.395 220.79 5.465 221.14 ;
      RECT 5.395 221.24 5.465 221.59 ;
      RECT 5.395 221.69 5.465 222.04 ;
      RECT 5.395 235.67 5.465 236.02 ;
      RECT 5.395 236.12 5.465 236.47 ;
      RECT 5.395 236.57 5.465 236.92 ;
      RECT 5.395 237.02 5.465 237.37 ;
      RECT 5.395 237.47 5.465 237.82 ;
      RECT 5.395 237.92 5.465 238.27 ;
      RECT 5.395 238.37 5.465 238.72 ;
      RECT 5.395 241.23 5.465 241.58 ;
      RECT 5.395 241.68 5.465 242.03 ;
      RECT 5.395 242.13 5.465 242.48 ;
      RECT 5.395 242.58 5.465 242.93 ;
      RECT 5.395 243.03 5.465 243.38 ;
      RECT 5.395 243.48 5.465 243.83 ;
      RECT 5.395 243.93 5.465 244.28 ;
      RECT 5.395 257.91 5.465 258.26 ;
      RECT 5.395 258.36 5.465 258.71 ;
      RECT 5.395 258.81 5.465 259.16 ;
      RECT 5.395 259.26 5.465 259.61 ;
      RECT 5.395 259.71 5.465 260.06 ;
      RECT 5.395 260.16 5.465 260.51 ;
      RECT 5.395 260.61 5.465 260.96 ;
      RECT 5.395 263.47 5.465 263.82 ;
      RECT 5.395 263.92 5.465 264.27 ;
      RECT 5.395 264.37 5.465 264.72 ;
      RECT 5.395 264.82 5.465 265.17 ;
      RECT 5.395 265.27 5.465 265.62 ;
      RECT 5.395 265.72 5.465 266.07 ;
      RECT 5.395 266.17 5.465 266.52 ;
      RECT 5.395 280.15 5.465 280.5 ;
      RECT 5.395 280.6 5.465 280.95 ;
      RECT 5.395 281.05 5.465 281.4 ;
      RECT 5.395 281.5 5.465 281.85 ;
      RECT 5.395 281.95 5.465 282.3 ;
      RECT 5.395 282.4 5.465 282.75 ;
      RECT 5.395 282.85 5.465 283.2 ;
      RECT 5.395 285.71 5.465 286.06 ;
      RECT 5.395 286.16 5.465 286.51 ;
      RECT 5.395 286.61 5.465 286.96 ;
      RECT 5.395 287.06 5.465 287.41 ;
      RECT 5.395 287.51 5.465 287.86 ;
      RECT 5.395 287.96 5.465 288.31 ;
      RECT 5.395 288.41 5.465 288.76 ;
      RECT 5.395 302.39 5.465 302.74 ;
      RECT 5.395 302.84 5.465 303.19 ;
      RECT 5.395 303.29 5.465 303.64 ;
      RECT 5.395 303.74 5.465 304.09 ;
      RECT 5.395 304.19 5.465 304.54 ;
      RECT 5.395 304.64 5.465 304.99 ;
      RECT 5.395 305.09 5.465 305.44 ;
      RECT 5.395 307.95 5.465 308.3 ;
      RECT 5.395 308.4 5.465 308.75 ;
      RECT 5.395 308.85 5.465 309.2 ;
      RECT 5.395 309.3 5.465 309.65 ;
      RECT 5.395 309.75 5.465 310.1 ;
      RECT 5.395 310.2 5.465 310.55 ;
      RECT 5.395 310.65 5.465 311 ;
      RECT 5.395 313.51 5.465 313.86 ;
      RECT 5.395 313.96 5.465 314.31 ;
      RECT 5.395 314.41 5.465 314.76 ;
      RECT 5.395 314.86 5.465 315.21 ;
      RECT 5.395 315.31 5.465 315.66 ;
      RECT 5.395 315.76 5.465 316.11 ;
      RECT 5.395 316.21 5.465 316.56 ;
      RECT 5.395 324.63 5.465 324.98 ;
      RECT 5.395 325.08 5.465 325.43 ;
      RECT 5.395 325.53 5.465 325.88 ;
      RECT 5.395 325.98 5.465 326.33 ;
      RECT 5.395 326.43 5.465 326.78 ;
      RECT 5.395 326.88 5.465 327.23 ;
      RECT 5.395 327.33 5.465 327.68 ;
      RECT 5.395 330.19 5.465 330.54 ;
      RECT 5.395 330.64 5.465 330.99 ;
      RECT 5.395 331.09 5.465 331.44 ;
      RECT 5.395 331.54 5.465 331.89 ;
      RECT 5.395 331.99 5.465 332.34 ;
      RECT 5.395 332.44 5.465 332.79 ;
      RECT 5.395 332.89 5.465 333.24 ;
      RECT 5.395 335.75 5.465 336.1 ;
      RECT 5.395 336.2 5.465 336.55 ;
      RECT 5.395 336.65 5.465 337 ;
      RECT 5.395 337.1 5.465 337.45 ;
      RECT 5.395 337.55 5.465 337.9 ;
      RECT 5.395 338 5.465 338.35 ;
      RECT 5.395 338.45 5.465 338.8 ;
    LAYER M3 ;
      RECT 47.6 345.145 48.1 345.955 ;
      RECT 44.07 345.145 44.57 345.955 ;
    LAYER M3 SPACING 0.05 ;
      RECT 0 0 92.2 346 ;
    LAYER M4 ;
      RECT 47.6 176.45 66.555 176.55 ;
      RECT 66.455 175.535 66.555 176.55 ;
      RECT 66.455 175.535 90.04 175.635 ;
      RECT 48.215 176.65 66.755 176.75 ;
      RECT 66.655 175.735 66.755 176.75 ;
      RECT 66.655 175.735 90.04 175.835 ;
      RECT 47.6 176.85 66.955 176.95 ;
      RECT 66.855 175.935 66.955 176.95 ;
      RECT 66.855 175.935 90.04 176.035 ;
      RECT 91.485 22.96 91.555 23.31 ;
      RECT 70.7 4.815 91.5 5.315 ;
      RECT 70.7 10.375 91.5 10.875 ;
      RECT 70.7 15.935 91.5 16.435 ;
      RECT 70.7 21.495 91.5 21.995 ;
      RECT 70.7 29.335 91.5 29.755 ;
      RECT 70.7 34.895 91.5 35.315 ;
      RECT 70.7 40.455 91.5 40.875 ;
      RECT 70.7 46.015 91.5 46.435 ;
      RECT 70.7 51.575 91.5 51.995 ;
      RECT 70.7 57.135 91.5 57.555 ;
      RECT 70.7 62.695 91.5 63.115 ;
      RECT 70.7 68.255 91.5 68.675 ;
      RECT 70.7 73.815 91.5 74.235 ;
      RECT 70.7 79.375 91.5 79.795 ;
      RECT 70.7 84.935 91.5 85.355 ;
      RECT 70.7 90.495 91.5 90.915 ;
      RECT 70.7 96.055 91.5 96.475 ;
      RECT 70.7 101.615 91.5 102.035 ;
      RECT 70.7 107.175 91.5 107.595 ;
      RECT 70.7 112.735 91.5 113.155 ;
      RECT 70.7 118.295 91.5 118.715 ;
      RECT 70.7 123.855 91.5 124.275 ;
      RECT 70.7 129.415 91.5 129.835 ;
      RECT 70.7 134.975 91.5 135.395 ;
      RECT 70.7 140.535 91.5 140.955 ;
      RECT 70.7 146.095 91.5 146.515 ;
      RECT 70.7 151.655 91.5 152.075 ;
      RECT 70.7 157.215 91.5 157.635 ;
      RECT 70.7 162.775 91.5 163.195 ;
      RECT 70.7 168.335 91.5 168.755 ;
      RECT 70.7 173.895 91.5 174.315 ;
      RECT 70.7 179.455 91.5 179.875 ;
      RECT 70.7 185.015 91.5 185.435 ;
      RECT 70.7 190.575 91.5 190.995 ;
      RECT 70.7 196.135 91.5 196.555 ;
      RECT 70.7 201.695 91.5 202.115 ;
      RECT 70.7 207.255 91.5 207.675 ;
      RECT 70.7 212.815 91.5 213.235 ;
      RECT 70.7 218.375 91.5 218.795 ;
      RECT 70.7 223.935 91.5 224.355 ;
      RECT 70.7 229.495 91.5 229.915 ;
      RECT 70.7 235.055 91.5 235.475 ;
      RECT 70.7 240.615 91.5 241.035 ;
      RECT 70.7 246.175 91.5 246.595 ;
      RECT 70.7 251.735 91.5 252.155 ;
      RECT 70.7 257.295 91.5 257.715 ;
      RECT 70.7 262.855 91.5 263.275 ;
      RECT 70.7 268.415 91.5 268.835 ;
      RECT 70.7 273.975 91.5 274.395 ;
      RECT 70.7 279.535 91.5 279.955 ;
      RECT 70.7 285.095 91.5 285.515 ;
      RECT 70.7 290.655 91.5 291.075 ;
      RECT 70.7 296.215 91.5 296.635 ;
      RECT 70.7 301.775 91.5 302.195 ;
      RECT 70.7 307.335 91.5 307.755 ;
      RECT 70.7 312.895 91.5 313.315 ;
      RECT 70.7 318.455 91.5 318.875 ;
      RECT 70.7 324.015 91.5 324.435 ;
      RECT 70.7 329.575 91.5 329.995 ;
      RECT 70.7 335.135 91.5 335.555 ;
      RECT 70.7 340.695 91.5 341.115 ;
      RECT 90.885 23.1 91.235 23.17 ;
      RECT 90.885 28.105 91.235 28.175 ;
      RECT 90.885 28.245 91.235 28.315 ;
      RECT 90.435 23.1 90.785 23.17 ;
      RECT 90.435 28.105 90.785 28.175 ;
      RECT 90.435 28.245 90.785 28.315 ;
      RECT 89.985 23.1 90.335 23.17 ;
      RECT 89.985 27.965 90.335 28.035 ;
      RECT 89.985 28.105 90.335 28.175 ;
      RECT 89.985 28.245 90.335 28.315 ;
      RECT 89.535 23.1 89.885 23.17 ;
      RECT 89.535 27.965 89.885 28.035 ;
      RECT 89.535 28.105 89.885 28.175 ;
      RECT 89.535 28.245 89.885 28.315 ;
      RECT 89.085 23.1 89.435 23.17 ;
      RECT 89.085 27.965 89.435 28.035 ;
      RECT 89.085 28.105 89.435 28.175 ;
      RECT 89.085 28.245 89.435 28.315 ;
      RECT 88.635 23.1 88.985 23.17 ;
      RECT 88.635 27.965 88.985 28.035 ;
      RECT 88.635 28.105 88.985 28.175 ;
      RECT 88.635 28.245 88.985 28.315 ;
      RECT 88.185 23.1 88.535 23.17 ;
      RECT 88.185 23.24 88.535 23.31 ;
      RECT 88.185 23.38 88.535 23.45 ;
      RECT 88.185 27.965 88.535 28.035 ;
      RECT 88.185 28.105 88.535 28.175 ;
      RECT 88.185 28.245 88.535 28.315 ;
      RECT 87.735 23.1 88.085 23.17 ;
      RECT 87.735 23.24 88.085 23.31 ;
      RECT 87.735 27.965 88.085 28.035 ;
      RECT 87.735 28.105 88.085 28.175 ;
      RECT 87.735 28.245 88.085 28.315 ;
      RECT 87.285 23.1 87.635 23.17 ;
      RECT 87.285 23.24 87.635 23.31 ;
      RECT 87.285 27.965 87.635 28.035 ;
      RECT 87.285 28.105 87.635 28.175 ;
      RECT 87.285 28.245 87.635 28.315 ;
      RECT 86.835 23.1 87.185 23.17 ;
      RECT 86.835 23.24 87.185 23.31 ;
      RECT 86.835 27.965 87.185 28.035 ;
      RECT 86.835 28.105 87.185 28.175 ;
      RECT 86.835 28.245 87.185 28.315 ;
      RECT 48.28 0.695 87.005 0.795 ;
      RECT 48.48 0.895 87.005 0.995 ;
      RECT 43.79 5.855 87.005 5.955 ;
      RECT 43.59 6.055 87.005 6.155 ;
      RECT 48.28 6.255 87.005 6.355 ;
      RECT 48.48 6.455 87.005 6.555 ;
      RECT 43.79 11.415 87.005 11.515 ;
      RECT 43.59 11.615 87.005 11.715 ;
      RECT 48.28 11.815 87.005 11.915 ;
      RECT 48.48 12.015 87.005 12.115 ;
      RECT 43.79 16.975 87.005 17.075 ;
      RECT 43.59 17.175 87.005 17.275 ;
      RECT 48.28 17.375 87.005 17.475 ;
      RECT 48.48 17.575 87.005 17.675 ;
      RECT 43.79 22.535 87.005 22.635 ;
      RECT 43.59 22.735 87.005 22.835 ;
      RECT 46.685 28.495 87.005 28.595 ;
      RECT 46.485 28.695 87.005 28.795 ;
      RECT 45.385 33.655 87.005 33.755 ;
      RECT 45.585 33.855 87.005 33.955 ;
      RECT 46.685 34.055 87.005 34.155 ;
      RECT 46.485 34.255 87.005 34.355 ;
      RECT 45.385 39.215 87.005 39.315 ;
      RECT 45.585 39.415 87.005 39.515 ;
      RECT 46.685 39.615 87.005 39.715 ;
      RECT 46.485 39.815 87.005 39.915 ;
      RECT 45.385 44.775 87.005 44.875 ;
      RECT 45.585 44.975 87.005 45.075 ;
      RECT 46.685 45.175 87.005 45.275 ;
      RECT 46.485 45.375 87.005 45.475 ;
      RECT 45.385 50.335 87.005 50.435 ;
      RECT 45.585 50.535 87.005 50.635 ;
      RECT 46.685 50.735 87.005 50.835 ;
      RECT 46.485 50.935 87.005 51.035 ;
      RECT 45.385 55.895 87.005 55.995 ;
      RECT 45.585 56.095 87.005 56.195 ;
      RECT 46.685 56.295 87.005 56.395 ;
      RECT 46.485 56.495 87.005 56.595 ;
      RECT 45.385 61.455 87.005 61.555 ;
      RECT 45.585 61.655 87.005 61.755 ;
      RECT 46.685 61.855 87.005 61.955 ;
      RECT 46.485 62.055 87.005 62.155 ;
      RECT 45.385 67.015 87.005 67.115 ;
      RECT 45.585 67.215 87.005 67.315 ;
      RECT 46.685 67.415 87.005 67.515 ;
      RECT 46.485 67.615 87.005 67.715 ;
      RECT 45.385 72.575 87.005 72.675 ;
      RECT 45.585 72.775 87.005 72.875 ;
      RECT 46.685 72.975 87.005 73.075 ;
      RECT 46.485 73.175 87.005 73.275 ;
      RECT 45.385 78.135 87.005 78.235 ;
      RECT 45.585 78.335 87.005 78.435 ;
      RECT 46.685 78.535 87.005 78.635 ;
      RECT 46.485 78.735 87.005 78.835 ;
      RECT 45.385 83.695 87.005 83.795 ;
      RECT 45.585 83.895 87.005 83.995 ;
      RECT 46.685 84.095 87.005 84.195 ;
      RECT 46.485 84.295 87.005 84.395 ;
      RECT 45.385 89.255 87.005 89.355 ;
      RECT 45.585 89.455 87.005 89.555 ;
      RECT 46.685 89.655 87.005 89.755 ;
      RECT 46.485 89.855 87.005 89.955 ;
      RECT 45.385 94.815 87.005 94.915 ;
      RECT 45.585 95.015 87.005 95.115 ;
      RECT 46.685 95.215 87.005 95.315 ;
      RECT 46.485 95.415 87.005 95.515 ;
      RECT 45.385 100.375 87.005 100.475 ;
      RECT 45.585 100.575 87.005 100.675 ;
      RECT 46.685 100.775 87.005 100.875 ;
      RECT 46.485 100.975 87.005 101.075 ;
      RECT 45.385 105.935 87.005 106.035 ;
      RECT 45.585 106.135 87.005 106.235 ;
      RECT 46.685 106.335 87.005 106.435 ;
      RECT 46.485 106.535 87.005 106.635 ;
      RECT 45.385 111.495 87.005 111.595 ;
      RECT 45.585 111.695 87.005 111.795 ;
      RECT 46.685 111.895 87.005 111.995 ;
      RECT 46.485 112.095 87.005 112.195 ;
      RECT 45.385 117.055 87.005 117.155 ;
      RECT 45.585 117.255 87.005 117.355 ;
      RECT 46.685 117.455 87.005 117.555 ;
      RECT 46.485 117.655 87.005 117.755 ;
      RECT 45.385 122.615 87.005 122.715 ;
      RECT 45.585 122.815 87.005 122.915 ;
      RECT 46.685 123.015 87.005 123.115 ;
      RECT 46.485 123.215 87.005 123.315 ;
      RECT 45.385 128.175 87.005 128.275 ;
      RECT 45.585 128.375 87.005 128.475 ;
      RECT 46.685 128.575 87.005 128.675 ;
      RECT 46.485 128.775 87.005 128.875 ;
      RECT 45.385 133.735 87.005 133.835 ;
      RECT 45.585 133.935 87.005 134.035 ;
      RECT 46.685 134.135 87.005 134.235 ;
      RECT 46.485 134.335 87.005 134.435 ;
      RECT 45.385 139.295 87.005 139.395 ;
      RECT 45.585 139.495 87.005 139.595 ;
      RECT 46.685 139.695 87.005 139.795 ;
      RECT 46.485 139.895 87.005 139.995 ;
      RECT 45.385 144.855 87.005 144.955 ;
      RECT 45.585 145.055 87.005 145.155 ;
      RECT 46.685 145.255 87.005 145.355 ;
      RECT 46.485 145.455 87.005 145.555 ;
      RECT 45.385 150.415 87.005 150.515 ;
      RECT 45.585 150.615 87.005 150.715 ;
      RECT 46.685 150.815 87.005 150.915 ;
      RECT 46.485 151.015 87.005 151.115 ;
      RECT 45.385 155.975 87.005 156.075 ;
      RECT 45.585 156.175 87.005 156.275 ;
      RECT 46.685 156.375 87.005 156.475 ;
      RECT 46.485 156.575 87.005 156.675 ;
      RECT 45.385 161.535 87.005 161.635 ;
      RECT 45.585 161.735 87.005 161.835 ;
      RECT 46.685 161.935 87.005 162.035 ;
      RECT 46.485 162.135 87.005 162.235 ;
      RECT 45.385 167.095 87.005 167.195 ;
      RECT 45.585 167.295 87.005 167.395 ;
      RECT 46.685 167.495 87.005 167.595 ;
      RECT 46.485 167.695 87.005 167.795 ;
      RECT 45.385 172.655 87.005 172.755 ;
      RECT 45.585 172.855 87.005 172.955 ;
      RECT 46.685 173.055 87.005 173.155 ;
      RECT 46.485 173.255 87.005 173.355 ;
      RECT 45.385 178.215 87.005 178.315 ;
      RECT 45.585 178.415 87.005 178.515 ;
      RECT 46.685 178.615 87.005 178.715 ;
      RECT 46.485 178.815 87.005 178.915 ;
      RECT 45.385 183.775 87.005 183.875 ;
      RECT 45.585 183.975 87.005 184.075 ;
      RECT 46.685 184.175 87.005 184.275 ;
      RECT 46.485 184.375 87.005 184.475 ;
      RECT 45.385 189.335 87.005 189.435 ;
      RECT 45.585 189.535 87.005 189.635 ;
      RECT 46.685 189.735 87.005 189.835 ;
      RECT 46.485 189.935 87.005 190.035 ;
      RECT 45.385 194.895 87.005 194.995 ;
      RECT 45.585 195.095 87.005 195.195 ;
      RECT 46.685 195.295 87.005 195.395 ;
      RECT 46.485 195.495 87.005 195.595 ;
      RECT 45.385 200.455 87.005 200.555 ;
      RECT 45.585 200.655 87.005 200.755 ;
      RECT 46.685 200.855 87.005 200.955 ;
      RECT 46.485 201.055 87.005 201.155 ;
      RECT 45.385 206.015 87.005 206.115 ;
      RECT 45.585 206.215 87.005 206.315 ;
      RECT 46.685 206.415 87.005 206.515 ;
      RECT 46.485 206.615 87.005 206.715 ;
      RECT 45.385 211.575 87.005 211.675 ;
      RECT 45.585 211.775 87.005 211.875 ;
      RECT 46.685 211.975 87.005 212.075 ;
      RECT 46.485 212.175 87.005 212.275 ;
      RECT 45.385 217.135 87.005 217.235 ;
      RECT 45.585 217.335 87.005 217.435 ;
      RECT 46.685 217.535 87.005 217.635 ;
      RECT 46.485 217.735 87.005 217.835 ;
      RECT 45.385 222.695 87.005 222.795 ;
      RECT 45.585 222.895 87.005 222.995 ;
      RECT 46.685 223.095 87.005 223.195 ;
      RECT 46.485 223.295 87.005 223.395 ;
      RECT 45.385 228.255 87.005 228.355 ;
      RECT 45.585 228.455 87.005 228.555 ;
      RECT 46.685 228.655 87.005 228.755 ;
      RECT 46.485 228.855 87.005 228.955 ;
      RECT 45.385 233.815 87.005 233.915 ;
      RECT 45.585 234.015 87.005 234.115 ;
      RECT 46.685 234.215 87.005 234.315 ;
      RECT 46.485 234.415 87.005 234.515 ;
      RECT 45.385 239.375 87.005 239.475 ;
      RECT 45.585 239.575 87.005 239.675 ;
      RECT 46.685 239.775 87.005 239.875 ;
      RECT 46.485 239.975 87.005 240.075 ;
      RECT 45.385 244.935 87.005 245.035 ;
      RECT 45.585 245.135 87.005 245.235 ;
      RECT 46.685 245.335 87.005 245.435 ;
      RECT 46.485 245.535 87.005 245.635 ;
      RECT 45.385 250.495 87.005 250.595 ;
      RECT 45.585 250.695 87.005 250.795 ;
      RECT 46.685 250.895 87.005 250.995 ;
      RECT 46.485 251.095 87.005 251.195 ;
      RECT 45.385 256.055 87.005 256.155 ;
      RECT 45.585 256.255 87.005 256.355 ;
      RECT 46.685 256.455 87.005 256.555 ;
      RECT 46.485 256.655 87.005 256.755 ;
      RECT 45.385 261.615 87.005 261.715 ;
      RECT 45.585 261.815 87.005 261.915 ;
      RECT 46.685 262.015 87.005 262.115 ;
      RECT 46.485 262.215 87.005 262.315 ;
      RECT 45.385 267.175 87.005 267.275 ;
      RECT 45.585 267.375 87.005 267.475 ;
      RECT 46.685 267.575 87.005 267.675 ;
      RECT 46.485 267.775 87.005 267.875 ;
      RECT 45.385 272.735 87.005 272.835 ;
      RECT 45.585 272.935 87.005 273.035 ;
      RECT 46.685 273.135 87.005 273.235 ;
      RECT 46.485 273.335 87.005 273.435 ;
      RECT 45.385 278.295 87.005 278.395 ;
      RECT 45.585 278.495 87.005 278.595 ;
      RECT 46.685 278.695 87.005 278.795 ;
      RECT 46.485 278.895 87.005 278.995 ;
      RECT 45.385 283.855 87.005 283.955 ;
      RECT 45.585 284.055 87.005 284.155 ;
      RECT 46.685 284.255 87.005 284.355 ;
      RECT 46.485 284.455 87.005 284.555 ;
      RECT 45.385 289.415 87.005 289.515 ;
      RECT 45.585 289.615 87.005 289.715 ;
      RECT 46.685 289.815 87.005 289.915 ;
      RECT 46.485 290.015 87.005 290.115 ;
      RECT 45.585 294.975 87.005 295.075 ;
      RECT 45.385 295.175 87.005 295.275 ;
      RECT 46.685 295.375 87.005 295.475 ;
      RECT 46.485 295.575 87.005 295.675 ;
      RECT 45.585 300.535 87.005 300.635 ;
      RECT 45.385 300.735 87.005 300.835 ;
      RECT 46.685 300.935 87.005 301.035 ;
      RECT 46.485 301.135 87.005 301.235 ;
      RECT 45.585 306.095 87.005 306.195 ;
      RECT 45.385 306.295 87.005 306.395 ;
      RECT 46.685 306.495 87.005 306.595 ;
      RECT 46.485 306.695 87.005 306.795 ;
      RECT 45.585 311.655 87.005 311.755 ;
      RECT 45.385 311.855 87.005 311.955 ;
      RECT 46.685 312.055 87.005 312.155 ;
      RECT 46.485 312.255 87.005 312.355 ;
      RECT 45.585 317.215 87.005 317.315 ;
      RECT 45.385 317.415 87.005 317.515 ;
      RECT 46.685 317.615 87.005 317.715 ;
      RECT 46.485 317.815 87.005 317.915 ;
      RECT 45.585 322.775 87.005 322.875 ;
      RECT 45.385 322.975 87.005 323.075 ;
      RECT 46.685 323.175 87.005 323.275 ;
      RECT 46.485 323.375 87.005 323.475 ;
      RECT 45.585 328.335 87.005 328.435 ;
      RECT 45.385 328.535 87.005 328.635 ;
      RECT 46.685 328.735 87.005 328.835 ;
      RECT 46.485 328.935 87.005 329.035 ;
      RECT 45.585 333.895 87.005 333.995 ;
      RECT 45.385 334.095 87.005 334.195 ;
      RECT 46.685 334.295 87.005 334.395 ;
      RECT 46.485 334.495 87.005 334.595 ;
      RECT 45.585 339.455 87.005 339.555 ;
      RECT 45.385 339.655 87.005 339.755 ;
      RECT 46.685 339.855 87.005 339.955 ;
      RECT 46.485 340.055 87.005 340.155 ;
      RECT 45.585 345.015 87.005 345.115 ;
      RECT 45.385 345.215 87.005 345.315 ;
    LAYER M4 SPACING 0.05 ;
      RECT 0 345.5 92.2 346 ;
      RECT 0 345.42 90.96 346 ;
      RECT 0 0 87.4 346 ;
      RECT 91.47 340.3 92.2 344.99 ;
      RECT 0 340.3 92.2 344.91 ;
      RECT 0 340.26 90.56 344.91 ;
      RECT 91.47 334.7 92.2 339.39 ;
      RECT 0 334.7 92.2 339.35 ;
      RECT 0 329.14 92.2 333.79 ;
      RECT 91.47 329.1 92.2 333.79 ;
      RECT 0 323.58 90.56 328.23 ;
      RECT 0 323.58 92.2 328.19 ;
      RECT 91.47 323.5 92.2 328.19 ;
      RECT 0 318.02 90.56 322.67 ;
      RECT 0 318.1 92.2 322.59 ;
      RECT 91.47 312.5 92.2 317.19 ;
      RECT 0 312.5 92.2 317.11 ;
      RECT 0 312.46 90.56 317.11 ;
      RECT 91.47 306.9 92.2 311.59 ;
      RECT 0 306.9 92.2 311.55 ;
      RECT 0 301.34 92.2 305.99 ;
      RECT 91.47 301.3 92.2 305.99 ;
      RECT 0 295.78 90.56 300.43 ;
      RECT 0 295.78 92.2 300.39 ;
      RECT 91.47 295.7 92.2 300.39 ;
      RECT 0 290.22 90.56 294.87 ;
      RECT 0 290.3 92.2 294.79 ;
      RECT 91.47 284.7 92.2 289.39 ;
      RECT 0 284.7 92.2 289.31 ;
      RECT 0 284.66 90.56 289.31 ;
      RECT 91.47 279.1 92.2 283.79 ;
      RECT 0 279.1 92.2 283.75 ;
      RECT 0 273.54 92.2 278.19 ;
      RECT 91.47 273.5 92.2 278.19 ;
      RECT 0 267.98 90.56 272.63 ;
      RECT 0 267.98 92.2 272.59 ;
      RECT 91.47 267.9 92.2 272.59 ;
      RECT 0 262.42 90.56 267.07 ;
      RECT 0 262.5 92.2 266.99 ;
      RECT 91.47 256.9 92.2 261.59 ;
      RECT 0 256.9 92.2 261.51 ;
      RECT 0 256.86 90.56 261.51 ;
      RECT 91.47 251.3 92.2 255.99 ;
      RECT 0 251.3 92.2 255.95 ;
      RECT 0 245.74 92.2 250.39 ;
      RECT 91.47 245.7 92.2 250.39 ;
      RECT 0 240.18 90.56 244.83 ;
      RECT 0 240.18 92.2 244.79 ;
      RECT 91.47 240.1 92.2 244.79 ;
      RECT 0 234.62 90.56 239.27 ;
      RECT 0 234.7 92.2 239.19 ;
      RECT 91.47 229.1 92.2 233.79 ;
      RECT 0 229.1 92.2 233.71 ;
      RECT 0 229.06 90.56 233.71 ;
      RECT 91.47 223.5 92.2 228.19 ;
      RECT 0 223.5 92.2 228.15 ;
      RECT 0 217.94 92.2 222.59 ;
      RECT 91.47 217.9 92.2 222.59 ;
      RECT 0 212.38 90.56 217.03 ;
      RECT 0 212.38 92.2 216.99 ;
      RECT 91.47 212.3 92.2 216.99 ;
      RECT 0 206.82 90.56 211.47 ;
      RECT 0 206.9 92.2 211.39 ;
      RECT 91.47 201.3 92.2 205.99 ;
      RECT 0 201.3 92.2 205.91 ;
      RECT 0 201.26 90.56 205.91 ;
      RECT 91.47 195.7 92.2 200.39 ;
      RECT 0 195.7 92.2 200.35 ;
      RECT 0 190.14 92.2 194.79 ;
      RECT 91.47 190.1 92.2 194.79 ;
      RECT 0 184.58 90.56 189.23 ;
      RECT 0 184.58 92.2 189.19 ;
      RECT 91.47 184.5 92.2 189.19 ;
      RECT 0 179.02 90.56 183.67 ;
      RECT 0 179.1 92.2 183.59 ;
      RECT 91.47 176.14 92.2 178.19 ;
      RECT 0 176.14 92.2 178.11 ;
      RECT 0 173.46 90.435 178.11 ;
      RECT 0 173.5 92.2 175.43 ;
      RECT 0 173.46 90.56 175.43 ;
      RECT 91.47 167.9 92.2 172.59 ;
      RECT 0 167.9 92.2 172.55 ;
      RECT 0 162.34 92.2 166.99 ;
      RECT 91.47 162.3 92.2 166.99 ;
      RECT 0 156.78 90.56 161.43 ;
      RECT 0 156.78 92.2 161.39 ;
      RECT 91.47 156.7 92.2 161.39 ;
      RECT 0 151.22 90.56 155.87 ;
      RECT 0 151.3 92.2 155.79 ;
      RECT 91.47 145.7 92.2 150.39 ;
      RECT 0 145.7 92.2 150.31 ;
      RECT 0 145.66 90.56 150.31 ;
      RECT 91.47 140.1 92.2 144.79 ;
      RECT 0 140.1 92.2 144.75 ;
      RECT 0 134.54 92.2 139.19 ;
      RECT 91.47 134.5 92.2 139.19 ;
      RECT 0 128.98 90.56 133.63 ;
      RECT 0 128.98 92.2 133.59 ;
      RECT 91.47 128.9 92.2 133.59 ;
      RECT 0 123.42 90.56 128.07 ;
      RECT 0 123.5 92.2 127.99 ;
      RECT 91.47 117.9 92.2 122.59 ;
      RECT 0 117.9 92.2 122.51 ;
      RECT 0 117.86 90.56 122.51 ;
      RECT 91.47 112.3 92.2 116.99 ;
      RECT 0 112.3 92.2 116.95 ;
      RECT 0 106.74 92.2 111.39 ;
      RECT 91.47 106.7 92.2 111.39 ;
      RECT 0 101.18 90.56 105.83 ;
      RECT 0 101.18 92.2 105.79 ;
      RECT 91.47 101.1 92.2 105.79 ;
      RECT 0 95.62 90.56 100.27 ;
      RECT 0 95.7 92.2 100.19 ;
      RECT 91.47 90.1 92.2 94.79 ;
      RECT 0 90.1 92.2 94.71 ;
      RECT 0 90.06 90.56 94.71 ;
      RECT 91.47 84.5 92.2 89.19 ;
      RECT 0 84.5 92.2 89.15 ;
      RECT 0 78.94 92.2 83.59 ;
      RECT 91.47 78.9 92.2 83.59 ;
      RECT 0 73.38 90.56 78.03 ;
      RECT 0 73.38 92.2 77.99 ;
      RECT 91.47 73.3 92.2 77.99 ;
      RECT 0 67.82 90.56 72.47 ;
      RECT 0 67.9 92.2 72.39 ;
      RECT 91.47 62.3 92.2 66.99 ;
      RECT 0 62.3 92.2 66.91 ;
      RECT 0 62.26 90.56 66.91 ;
      RECT 91.47 56.7 92.2 61.39 ;
      RECT 0 56.7 92.2 61.35 ;
      RECT 0 51.14 92.2 55.79 ;
      RECT 91.47 51.1 92.2 55.79 ;
      RECT 0 45.58 90.56 50.23 ;
      RECT 0 45.58 92.2 50.19 ;
      RECT 91.47 45.5 92.2 50.19 ;
      RECT 0 40.02 90.56 44.67 ;
      RECT 0 40.1 92.2 44.59 ;
      RECT 91.47 34.5 92.2 39.19 ;
      RECT 0 34.5 92.2 39.11 ;
      RECT 0 34.46 90.56 39.11 ;
      RECT 91.47 28.9 92.2 33.59 ;
      RECT 0 28.9 92.2 33.55 ;
      RECT 0 22.94 92.2 28.39 ;
      RECT 91.23 22.9 92.2 28.39 ;
      RECT 0 17.78 90.72 22.43 ;
      RECT 0 17.78 92.2 22.39 ;
      RECT 91.605 17.7 92.2 22.39 ;
      RECT 0 12.22 90.695 16.87 ;
      RECT 0 12.22 92.2 16.79 ;
      RECT 91.605 12.1 92.2 16.79 ;
      RECT 0 6.66 90.695 11.31 ;
      RECT 0 6.7 92.2 11.19 ;
      RECT 91.605 1.1 92.2 5.79 ;
      RECT 0 1.1 92.2 5.75 ;
      RECT 0 0 92.2 0.59 ;
    LAYER M5 ;
      RECT 91.235 22.775 91.355 23.275 ;
      RECT 91.22 27.475 91.34 28.475 ;
      RECT 90.81 0.605 91.16 0.675 ;
      RECT 90.925 22.775 91.045 23.275 ;
      RECT 90.88 27.42 91 28.42 ;
      RECT 90.615 22.775 90.735 23.275 ;
      RECT 90.36 0.605 90.71 0.675 ;
      RECT 90.54 27.365 90.66 28.365 ;
      RECT 90.305 22.775 90.425 23.275 ;
      RECT 90.2 27.31 90.32 28.31 ;
      RECT 89.91 0.605 90.26 0.675 ;
      RECT 89.995 22.775 90.115 23.275 ;
      RECT 89.86 27.255 89.98 28.255 ;
      RECT 89.46 0.605 89.81 0.675 ;
      RECT 89.685 22.775 89.805 23.275 ;
      RECT 89.52 27.2 89.64 28.2 ;
      RECT 89.375 22.775 89.495 23.275 ;
      RECT 89.075 28.435 89.425 28.505 ;
      RECT 89.01 0.605 89.36 0.675 ;
      RECT 89.18 27.145 89.3 28.145 ;
      RECT 89.065 22.775 89.185 23.275 ;
      RECT 88.625 28.295 88.975 28.365 ;
      RECT 88.625 28.435 88.975 28.505 ;
      RECT 88.84 27.09 88.96 28.09 ;
      RECT 88.56 0.605 88.91 0.675 ;
      RECT 88.72 22.77 88.79 23.12 ;
      RECT 88.58 22.77 88.65 23.12 ;
      RECT 88.5 27.035 88.62 28.035 ;
      RECT 88.175 28.295 88.525 28.365 ;
      RECT 88.175 28.435 88.525 28.505 ;
      RECT 88.44 22.77 88.51 23.12 ;
      RECT 88.11 0.605 88.46 0.675 ;
      RECT 88.335 23.375 88.455 24.375 ;
      RECT 88.3 22.77 88.37 23.12 ;
      RECT 88.16 26.98 88.28 27.98 ;
      RECT 88.16 22.77 88.23 23.12 ;
      RECT 87.995 23.32 88.115 24.32 ;
      RECT 88.02 22.77 88.09 23.12 ;
      RECT 87.725 28.295 88.075 28.365 ;
      RECT 87.725 28.435 88.075 28.505 ;
      RECT 87.66 0.605 88.01 0.675 ;
      RECT 87.445 72.82 87.795 72.89 ;
      RECT 87.445 72.96 87.795 73.03 ;
      RECT 87.445 84.06 87.795 84.13 ;
      RECT 87.445 139.665 87.795 139.735 ;
      RECT 87.445 223 87.795 223.07 ;
      RECT 87.445 267.53 87.795 267.6 ;
      RECT 87.445 311.92 87.795 311.99 ;
      RECT 87.655 23.265 87.775 24.265 ;
      RECT 87.42 117.29 87.77 117.36 ;
      RECT 87.42 117.43 87.77 117.5 ;
      RECT 87.42 272.97 87.77 273.04 ;
      RECT 87.42 273.11 87.77 273.18 ;
      RECT 87.42 300.77 87.77 300.84 ;
      RECT 87.42 300.91 87.77 300.98 ;
      RECT 87.415 161.77 87.765 161.84 ;
      RECT 87.415 161.91 87.765 161.98 ;
      RECT 87.415 317.45 87.765 317.52 ;
      RECT 87.415 317.59 87.765 317.66 ;
      RECT 87.41 206.25 87.76 206.32 ;
      RECT 87.41 206.39 87.76 206.46 ;
      RECT 87.41 289.65 87.76 289.72 ;
      RECT 87.41 289.79 87.76 289.86 ;
      RECT 87.405 106.17 87.755 106.24 ;
      RECT 87.405 106.31 87.755 106.38 ;
      RECT 87.405 189.57 87.755 189.64 ;
      RECT 87.405 189.71 87.755 189.78 ;
      RECT 87.4 122.85 87.75 122.92 ;
      RECT 87.4 122.99 87.75 123.06 ;
      RECT 87.4 150.65 87.75 150.72 ;
      RECT 87.4 150.79 87.75 150.86 ;
      RECT 87.395 11.65 87.745 11.72 ;
      RECT 87.395 11.79 87.745 11.86 ;
      RECT 87.395 167.33 87.745 167.4 ;
      RECT 87.395 167.47 87.745 167.54 ;
      RECT 87.395 195.13 87.745 195.2 ;
      RECT 87.395 195.27 87.745 195.34 ;
      RECT 87.39 56.13 87.74 56.2 ;
      RECT 87.39 56.27 87.74 56.34 ;
      RECT 87.39 323.01 87.74 323.08 ;
      RECT 87.39 323.15 87.74 323.22 ;
      RECT 87.385 100.61 87.735 100.68 ;
      RECT 87.385 100.75 87.735 100.82 ;
      RECT 87.385 184.01 87.735 184.08 ;
      RECT 87.385 184.15 87.735 184.22 ;
      RECT 87.385 245.17 87.735 245.24 ;
      RECT 87.385 245.31 87.735 245.38 ;
      RECT 87.38 228.49 87.73 228.56 ;
      RECT 87.38 228.63 87.73 228.7 ;
      RECT 87.375 45.01 87.725 45.08 ;
      RECT 87.375 45.15 87.725 45.22 ;
      RECT 87.375 145.09 87.725 145.16 ;
      RECT 87.375 145.23 87.725 145.3 ;
      RECT 87.37 89.49 87.72 89.56 ;
      RECT 87.37 89.63 87.72 89.7 ;
      RECT 87.37 172.89 87.72 172.96 ;
      RECT 87.37 173.03 87.72 173.1 ;
      RECT 87.365 33.89 87.715 33.96 ;
      RECT 87.365 34.03 87.715 34.1 ;
      RECT 87.365 95.05 87.715 95.12 ;
      RECT 87.365 95.19 87.715 95.26 ;
      RECT 87.365 133.97 87.715 134.04 ;
      RECT 87.365 134.11 87.715 134.18 ;
      RECT 87.365 217.37 87.715 217.44 ;
      RECT 87.365 217.51 87.715 217.58 ;
      RECT 87.36 261.85 87.71 261.92 ;
      RECT 87.36 261.99 87.71 262.06 ;
      RECT 87.355 306.33 87.705 306.4 ;
      RECT 87.355 306.47 87.705 306.54 ;
      RECT 87.35 6.09 87.7 6.16 ;
      RECT 87.35 6.23 87.7 6.3 ;
      RECT 87.35 22.77 87.7 22.84 ;
      RECT 87.35 22.91 87.7 22.98 ;
      RECT 87.35 39.45 87.7 39.52 ;
      RECT 87.35 39.59 87.7 39.66 ;
      RECT 87.35 250.73 87.7 250.8 ;
      RECT 87.35 250.87 87.7 250.94 ;
      RECT 87.345 67.25 87.695 67.32 ;
      RECT 87.345 67.39 87.695 67.46 ;
      RECT 87.34 111.73 87.69 111.8 ;
      RECT 87.34 111.87 87.69 111.94 ;
      RECT 87.34 178.45 87.69 178.52 ;
      RECT 87.34 178.59 87.69 178.66 ;
      RECT 87.34 211.81 87.69 211.88 ;
      RECT 87.34 211.95 87.69 212.02 ;
      RECT 87.335 156.21 87.685 156.28 ;
      RECT 87.335 156.35 87.685 156.42 ;
      RECT 87.335 239.61 87.685 239.68 ;
      RECT 87.335 239.75 87.685 239.82 ;
      RECT 87.335 339.69 87.685 339.76 ;
      RECT 87.335 339.83 87.685 339.9 ;
      RECT 87.33 284.09 87.68 284.16 ;
      RECT 87.33 284.23 87.68 284.3 ;
      RECT 87.325 328.57 87.675 328.64 ;
      RECT 87.325 328.71 87.675 328.78 ;
      RECT 87.32 61.69 87.67 61.76 ;
      RECT 87.32 61.83 87.67 61.9 ;
      RECT 87.32 78.37 87.67 78.44 ;
      RECT 87.32 78.51 87.67 78.58 ;
      RECT 87.285 234.07 87.635 234.14 ;
      RECT 87.285 234.21 87.635 234.28 ;
      RECT 87.285 278.6 87.635 278.67 ;
      RECT 87.275 28.155 87.625 28.225 ;
      RECT 87.275 28.295 87.625 28.365 ;
      RECT 87.275 28.435 87.625 28.505 ;
      RECT 87.25 128.41 87.6 128.48 ;
      RECT 87.25 128.55 87.6 128.62 ;
      RECT 87.22 334.13 87.57 334.2 ;
      RECT 87.22 334.27 87.57 334.34 ;
      RECT 87.21 0.605 87.56 0.675 ;
      RECT 87.17 256.29 87.52 256.36 ;
      RECT 87.17 256.43 87.52 256.5 ;
      RECT 87.165 50.57 87.515 50.64 ;
      RECT 87.165 50.71 87.515 50.78 ;
      RECT 87.16 200.69 87.51 200.76 ;
      RECT 87.16 200.83 87.51 200.9 ;
      RECT 87.16 295.21 87.51 295.28 ;
      RECT 87.16 295.35 87.51 295.42 ;
      RECT 87.315 23.21 87.435 24.21 ;
      RECT 87.04 17.265 87.39 17.335 ;
      RECT 86.995 72.82 87.345 72.89 ;
      RECT 86.995 72.96 87.345 73.03 ;
      RECT 86.995 84.06 87.345 84.13 ;
      RECT 86.995 139.665 87.345 139.735 ;
      RECT 86.995 223 87.345 223.07 ;
      RECT 86.995 267.53 87.345 267.6 ;
      RECT 86.995 311.92 87.345 311.99 ;
      RECT 86.97 117.29 87.32 117.36 ;
      RECT 86.97 117.43 87.32 117.5 ;
      RECT 86.97 272.97 87.32 273.04 ;
      RECT 86.97 273.11 87.32 273.18 ;
      RECT 86.97 300.77 87.32 300.84 ;
      RECT 86.97 300.91 87.32 300.98 ;
      RECT 86.965 161.77 87.315 161.84 ;
      RECT 86.965 161.91 87.315 161.98 ;
      RECT 86.965 317.45 87.315 317.52 ;
      RECT 86.965 317.59 87.315 317.66 ;
      RECT 86.96 206.25 87.31 206.32 ;
      RECT 86.96 206.39 87.31 206.46 ;
      RECT 86.96 289.65 87.31 289.72 ;
      RECT 86.96 289.79 87.31 289.86 ;
      RECT 86.955 106.17 87.305 106.24 ;
      RECT 86.955 106.31 87.305 106.38 ;
      RECT 86.955 189.57 87.305 189.64 ;
      RECT 86.955 189.71 87.305 189.78 ;
      RECT 86.95 122.85 87.3 122.92 ;
      RECT 86.95 122.99 87.3 123.06 ;
      RECT 86.95 150.65 87.3 150.72 ;
      RECT 86.95 150.79 87.3 150.86 ;
      RECT 86.945 11.65 87.295 11.72 ;
      RECT 86.945 11.79 87.295 11.86 ;
      RECT 86.945 167.33 87.295 167.4 ;
      RECT 86.945 167.47 87.295 167.54 ;
      RECT 86.945 195.13 87.295 195.2 ;
      RECT 86.945 195.27 87.295 195.34 ;
      RECT 86.94 56.13 87.29 56.2 ;
      RECT 86.94 56.27 87.29 56.34 ;
      RECT 86.94 323.01 87.29 323.08 ;
      RECT 86.94 323.15 87.29 323.22 ;
      RECT 86.935 100.61 87.285 100.68 ;
      RECT 86.935 100.75 87.285 100.82 ;
      RECT 86.935 184.01 87.285 184.08 ;
      RECT 86.935 184.15 87.285 184.22 ;
      RECT 86.935 245.17 87.285 245.24 ;
      RECT 86.935 245.31 87.285 245.38 ;
      RECT 86.93 228.49 87.28 228.56 ;
      RECT 86.93 228.63 87.28 228.7 ;
      RECT 86.925 45.01 87.275 45.08 ;
      RECT 86.925 45.15 87.275 45.22 ;
      RECT 86.925 145.09 87.275 145.16 ;
      RECT 86.925 145.23 87.275 145.3 ;
      RECT 86.92 89.49 87.27 89.56 ;
      RECT 86.92 89.63 87.27 89.7 ;
      RECT 86.92 172.89 87.27 172.96 ;
      RECT 86.92 173.03 87.27 173.1 ;
      RECT 86.915 33.89 87.265 33.96 ;
      RECT 86.915 34.03 87.265 34.1 ;
      RECT 86.915 95.05 87.265 95.12 ;
      RECT 86.915 95.19 87.265 95.26 ;
      RECT 86.915 133.97 87.265 134.04 ;
      RECT 86.915 134.11 87.265 134.18 ;
      RECT 86.915 217.37 87.265 217.44 ;
      RECT 86.915 217.51 87.265 217.58 ;
      RECT 86.91 261.85 87.26 261.92 ;
      RECT 86.91 261.99 87.26 262.06 ;
      RECT 86.905 306.33 87.255 306.4 ;
      RECT 86.905 306.47 87.255 306.54 ;
      RECT 86.9 6.09 87.25 6.16 ;
      RECT 86.9 22.77 87.25 22.84 ;
      RECT 86.9 39.45 87.25 39.52 ;
      RECT 86.9 39.59 87.25 39.66 ;
      RECT 86.9 250.73 87.25 250.8 ;
      RECT 86.9 250.87 87.25 250.94 ;
      RECT 86.895 67.25 87.245 67.32 ;
      RECT 86.895 67.39 87.245 67.46 ;
      RECT 86.89 111.73 87.24 111.8 ;
      RECT 86.89 111.87 87.24 111.94 ;
      RECT 86.89 178.45 87.24 178.52 ;
      RECT 86.89 178.59 87.24 178.66 ;
      RECT 86.89 211.81 87.24 211.88 ;
      RECT 86.89 211.95 87.24 212.02 ;
      RECT 86.885 156.21 87.235 156.28 ;
      RECT 86.885 156.35 87.235 156.42 ;
      RECT 86.885 239.61 87.235 239.68 ;
      RECT 86.885 339.69 87.235 339.76 ;
      RECT 86.885 339.83 87.235 339.9 ;
      RECT 86.88 284.09 87.23 284.16 ;
      RECT 86.88 284.23 87.23 284.3 ;
      RECT 86.875 328.57 87.225 328.64 ;
      RECT 86.875 328.71 87.225 328.78 ;
      RECT 86.835 234.07 87.185 234.14 ;
      RECT 86.835 234.21 87.185 234.28 ;
      RECT 86.825 28.435 87.175 28.505 ;
      RECT 86.8 128.55 87.15 128.62 ;
      RECT 86.77 334.27 87.12 334.34 ;
      RECT 86.76 0.605 87.11 0.675 ;
      RECT 86.975 23.155 87.095 24.155 ;
      RECT 86.72 256.43 87.07 256.5 ;
      RECT 86.715 50.71 87.065 50.78 ;
      RECT 86.71 200.83 87.06 200.9 ;
      RECT 86.71 295.35 87.06 295.42 ;
      RECT 65.385 0.015 66.785 29.23 ;
      RECT 63.685 0.015 65.085 29.23 ;
      RECT 61.985 0.015 63.385 29.23 ;
      RECT 60.005 0.015 61.405 29.23 ;
      RECT 58.305 0.015 59.705 29.23 ;
      RECT 56.605 0.015 58.005 29.23 ;
      RECT 54.615 0.015 56.015 29.23 ;
      RECT 52.915 0.015 54.315 29.23 ;
      RECT 51.015 0.015 52.415 29.23 ;
      RECT 49.315 0.015 50.715 29.23 ;
      RECT 47.685 0.015 48.685 29.23 ;
      RECT 46.385 0.015 47.385 29.23 ;
      RECT 44.785 0.015 45.785 29.23 ;
      RECT 43.485 0.015 44.485 29.23 ;
      RECT 41.455 0.015 42.855 29.23 ;
      RECT 39.755 0.015 41.155 29.23 ;
      RECT 37.855 0.015 39.255 29.23 ;
      RECT 36.155 0.015 37.555 29.23 ;
      RECT 34.165 0.015 35.565 29.23 ;
      RECT 32.465 0.015 33.865 29.23 ;
      RECT 30.765 0.015 32.165 29.23 ;
      RECT 28.785 0.015 30.185 29.23 ;
      RECT 27.085 0.015 28.485 29.23 ;
      RECT 25.385 0.015 26.785 29.23 ;
    LAYER M5 SPACING 0.05 ;
      RECT 0 345.5 92.2 346 ;
      RECT 0 345.42 90.96 346 ;
      RECT 0 0 87.4 346 ;
      RECT 91.47 340.3 92.2 344.99 ;
      RECT 0 340.3 92.2 344.91 ;
      RECT 0 340.26 90.56 344.91 ;
      RECT 0 339.83 87.685 339.9 ;
      RECT 0 339.69 87.685 339.76 ;
      RECT 91.47 334.7 92.2 339.39 ;
      RECT 0 334.7 92.2 339.35 ;
      RECT 0 334.27 87.57 334.34 ;
      RECT 0 334.13 87.57 334.2 ;
      RECT 0 329.14 92.2 333.79 ;
      RECT 91.47 329.1 92.2 333.79 ;
      RECT 0 328.71 87.675 328.78 ;
      RECT 0 328.57 87.675 328.64 ;
      RECT 0 323.58 90.56 328.23 ;
      RECT 0 323.58 92.2 328.19 ;
      RECT 91.47 323.5 92.2 328.19 ;
      RECT 0 323.15 87.74 323.22 ;
      RECT 0 323.01 87.74 323.08 ;
      RECT 0 318.02 90.56 322.67 ;
      RECT 0 318.1 92.2 322.59 ;
      RECT 0 317.59 87.765 317.66 ;
      RECT 0 317.45 87.765 317.52 ;
      RECT 91.47 312.5 92.2 317.19 ;
      RECT 0 312.5 92.2 317.11 ;
      RECT 0 312.46 90.56 317.11 ;
      RECT 0 311.92 87.795 311.99 ;
      RECT 91.47 306.9 92.2 311.59 ;
      RECT 0 306.9 92.2 311.55 ;
      RECT 0 306.47 87.705 306.54 ;
      RECT 0 306.33 87.705 306.4 ;
      RECT 0 301.34 92.2 305.99 ;
      RECT 91.47 301.3 92.2 305.99 ;
      RECT 0 300.91 87.77 300.98 ;
      RECT 0 300.77 87.77 300.84 ;
      RECT 0 295.78 90.56 300.43 ;
      RECT 0 295.78 92.2 300.39 ;
      RECT 91.47 295.7 92.2 300.39 ;
      RECT 0 295.35 87.51 295.42 ;
      RECT 0 295.21 87.51 295.28 ;
      RECT 0 290.22 90.56 294.87 ;
      RECT 0 290.3 92.2 294.79 ;
      RECT 0 289.79 87.76 289.86 ;
      RECT 0 289.65 87.76 289.72 ;
      RECT 91.47 284.7 92.2 289.39 ;
      RECT 0 284.7 92.2 289.31 ;
      RECT 0 284.66 90.56 289.31 ;
      RECT 0 284.23 87.68 284.3 ;
      RECT 0 284.09 87.68 284.16 ;
      RECT 91.47 279.1 92.2 283.79 ;
      RECT 0 279.1 92.2 283.75 ;
      RECT 0 278.6 87.635 278.67 ;
      RECT 0 273.54 92.2 278.19 ;
      RECT 91.47 273.5 92.2 278.19 ;
      RECT 0 273.11 87.77 273.18 ;
      RECT 0 272.97 87.77 273.04 ;
      RECT 0 267.98 90.56 272.63 ;
      RECT 0 267.98 92.2 272.59 ;
      RECT 91.47 267.9 92.2 272.59 ;
      RECT 0 267.53 87.795 267.6 ;
      RECT 0 262.42 90.56 267.07 ;
      RECT 0 262.5 92.2 266.99 ;
      RECT 0 261.99 87.71 262.06 ;
      RECT 0 261.85 87.71 261.92 ;
      RECT 91.47 256.9 92.2 261.59 ;
      RECT 0 256.9 92.2 261.51 ;
      RECT 0 256.86 90.56 261.51 ;
      RECT 0 256.43 87.52 256.5 ;
      RECT 0 256.29 87.52 256.36 ;
      RECT 91.47 251.3 92.2 255.99 ;
      RECT 0 251.3 92.2 255.95 ;
      RECT 0 250.87 87.7 250.94 ;
      RECT 0 250.73 87.7 250.8 ;
      RECT 0 245.74 92.2 250.39 ;
      RECT 91.47 245.7 92.2 250.39 ;
      RECT 0 245.31 87.735 245.38 ;
      RECT 0 245.17 87.735 245.24 ;
      RECT 0 240.18 90.56 244.83 ;
      RECT 0 240.18 92.2 244.79 ;
      RECT 91.47 240.1 92.2 244.79 ;
      RECT 0 239.75 87.685 239.82 ;
      RECT 0 239.61 87.685 239.68 ;
      RECT 0 234.62 90.56 239.27 ;
      RECT 0 234.7 92.2 239.19 ;
      RECT 0 234.21 87.635 234.28 ;
      RECT 0 234.07 87.635 234.14 ;
      RECT 91.47 229.1 92.2 233.79 ;
      RECT 0 229.1 92.2 233.71 ;
      RECT 0 229.06 90.56 233.71 ;
      RECT 0 228.63 87.73 228.7 ;
      RECT 0 228.49 87.73 228.56 ;
      RECT 91.47 223.5 92.2 228.19 ;
      RECT 0 223.5 92.2 228.15 ;
      RECT 0 223 87.795 223.07 ;
      RECT 0 217.94 92.2 222.59 ;
      RECT 91.47 217.9 92.2 222.59 ;
      RECT 0 217.51 87.715 217.58 ;
      RECT 0 217.37 87.715 217.44 ;
      RECT 0 212.38 90.56 217.03 ;
      RECT 0 212.38 92.2 216.99 ;
      RECT 91.47 212.3 92.2 216.99 ;
      RECT 0 211.95 87.69 212.02 ;
      RECT 0 211.81 87.69 211.88 ;
      RECT 0 206.82 90.56 211.47 ;
      RECT 0 206.9 92.2 211.39 ;
      RECT 0 206.39 87.76 206.46 ;
      RECT 0 206.25 87.76 206.32 ;
      RECT 91.47 201.3 92.2 205.99 ;
      RECT 0 201.3 92.2 205.91 ;
      RECT 0 201.26 90.56 205.91 ;
      RECT 0 200.83 87.51 200.9 ;
      RECT 0 200.69 87.51 200.76 ;
      RECT 91.47 195.7 92.2 200.39 ;
      RECT 0 195.7 92.2 200.35 ;
      RECT 0 195.27 87.745 195.34 ;
      RECT 0 195.13 87.745 195.2 ;
      RECT 0 190.14 92.2 194.79 ;
      RECT 91.47 190.1 92.2 194.79 ;
      RECT 0 189.71 87.755 189.78 ;
      RECT 0 189.57 87.755 189.64 ;
      RECT 0 184.58 90.56 189.23 ;
      RECT 0 184.58 92.2 189.19 ;
      RECT 91.47 184.5 92.2 189.19 ;
      RECT 0 184.15 87.735 184.22 ;
      RECT 0 184.01 87.735 184.08 ;
      RECT 0 179.02 90.56 183.67 ;
      RECT 0 179.1 92.2 183.59 ;
      RECT 0 178.59 87.69 178.66 ;
      RECT 0 178.45 87.69 178.52 ;
      RECT 91.47 176.14 92.2 178.19 ;
      RECT 0 176.14 92.2 178.11 ;
      RECT 0 173.46 90.435 178.11 ;
      RECT 0 173.5 92.2 175.43 ;
      RECT 0 173.46 90.56 175.43 ;
      RECT 0 173.03 87.72 173.1 ;
      RECT 0 172.89 87.72 172.96 ;
      RECT 91.47 167.9 92.2 172.59 ;
      RECT 0 167.9 92.2 172.55 ;
      RECT 0 167.47 87.745 167.54 ;
      RECT 0 167.33 87.745 167.4 ;
      RECT 0 162.34 92.2 166.99 ;
      RECT 91.47 162.3 92.2 166.99 ;
      RECT 0 161.91 87.765 161.98 ;
      RECT 0 161.77 87.765 161.84 ;
      RECT 0 156.78 90.56 161.43 ;
      RECT 0 156.78 92.2 161.39 ;
      RECT 91.47 156.7 92.2 161.39 ;
      RECT 0 156.35 87.685 156.42 ;
      RECT 0 156.21 87.685 156.28 ;
      RECT 0 151.22 90.56 155.87 ;
      RECT 0 151.3 92.2 155.79 ;
      RECT 0 150.79 87.75 150.86 ;
      RECT 0 150.65 87.75 150.72 ;
      RECT 91.47 145.7 92.2 150.39 ;
      RECT 0 145.7 92.2 150.31 ;
      RECT 0 145.66 90.56 150.31 ;
      RECT 0 145.23 87.725 145.3 ;
      RECT 0 145.09 87.725 145.16 ;
      RECT 91.47 140.1 92.2 144.79 ;
      RECT 0 140.1 92.2 144.75 ;
      RECT 0 139.665 87.795 139.735 ;
      RECT 0 134.54 92.2 139.19 ;
      RECT 91.47 134.5 92.2 139.19 ;
      RECT 0 134.11 87.715 134.18 ;
      RECT 0 133.97 87.715 134.04 ;
      RECT 0 128.98 90.56 133.63 ;
      RECT 0 128.98 92.2 133.59 ;
      RECT 91.47 128.9 92.2 133.59 ;
      RECT 0 128.55 87.6 128.62 ;
      RECT 0 128.41 87.6 128.48 ;
      RECT 0 123.42 90.56 128.07 ;
      RECT 0 123.5 92.2 127.99 ;
      RECT 0 122.99 87.75 123.06 ;
      RECT 0 122.85 87.75 122.92 ;
      RECT 91.47 117.9 92.2 122.59 ;
      RECT 0 117.9 92.2 122.51 ;
      RECT 0 117.86 90.56 122.51 ;
      RECT 0 117.43 87.77 117.5 ;
      RECT 0 117.29 87.77 117.36 ;
      RECT 91.47 112.3 92.2 116.99 ;
      RECT 0 112.3 92.2 116.95 ;
      RECT 0 111.87 87.69 111.94 ;
      RECT 0 111.73 87.69 111.8 ;
      RECT 0 106.74 92.2 111.39 ;
      RECT 91.47 106.7 92.2 111.39 ;
      RECT 0 106.31 87.755 106.38 ;
      RECT 0 106.17 87.755 106.24 ;
      RECT 0 101.18 90.56 105.83 ;
      RECT 0 101.18 92.2 105.79 ;
      RECT 91.47 101.1 92.2 105.79 ;
      RECT 0 100.75 87.735 100.82 ;
      RECT 0 100.61 87.735 100.68 ;
      RECT 0 95.62 90.56 100.27 ;
      RECT 0 95.7 92.2 100.19 ;
      RECT 0 95.19 87.715 95.26 ;
      RECT 0 95.05 87.715 95.12 ;
      RECT 91.47 90.1 92.2 94.79 ;
      RECT 0 90.1 92.2 94.71 ;
      RECT 0 90.06 90.56 94.71 ;
      RECT 0 89.63 87.72 89.7 ;
      RECT 0 89.49 87.72 89.56 ;
      RECT 91.47 84.5 92.2 89.19 ;
      RECT 0 84.5 92.2 89.15 ;
      RECT 0 84.06 87.795 84.13 ;
      RECT 0 78.94 92.2 83.59 ;
      RECT 91.47 78.9 92.2 83.59 ;
      RECT 0 78.51 87.67 78.58 ;
      RECT 0 78.37 87.67 78.44 ;
      RECT 0 73.38 90.56 78.03 ;
      RECT 0 73.38 92.2 77.99 ;
      RECT 91.47 73.3 92.2 77.99 ;
      RECT 0 72.96 87.795 73.03 ;
      RECT 0 72.82 87.795 72.89 ;
      RECT 0 67.82 90.56 72.47 ;
      RECT 0 67.9 92.2 72.39 ;
      RECT 0 67.39 87.695 67.46 ;
      RECT 0 67.25 87.695 67.32 ;
      RECT 91.47 62.3 92.2 66.99 ;
      RECT 0 62.3 92.2 66.91 ;
      RECT 0 62.26 90.56 66.91 ;
      RECT 0 61.83 87.67 61.9 ;
      RECT 0 61.69 87.67 61.76 ;
      RECT 91.47 56.7 92.2 61.39 ;
      RECT 0 56.7 92.2 61.35 ;
      RECT 0 56.27 87.74 56.34 ;
      RECT 0 56.13 87.74 56.2 ;
      RECT 0 51.14 92.2 55.79 ;
      RECT 91.47 51.1 92.2 55.79 ;
      RECT 0 50.71 87.515 50.78 ;
      RECT 0 50.57 87.515 50.64 ;
      RECT 0 45.58 90.56 50.23 ;
      RECT 0 45.58 92.2 50.19 ;
      RECT 91.47 45.5 92.2 50.19 ;
      RECT 0 45.15 87.725 45.22 ;
      RECT 0 45.01 87.725 45.08 ;
      RECT 0 40.02 90.56 44.67 ;
      RECT 0 40.1 92.2 44.59 ;
      RECT 0 39.59 87.7 39.66 ;
      RECT 0 39.45 87.7 39.52 ;
      RECT 91.47 34.5 92.2 39.19 ;
      RECT 0 34.5 92.2 39.11 ;
      RECT 0 34.46 90.56 39.11 ;
      RECT 0 34.03 87.715 34.1 ;
      RECT 0 33.89 87.715 33.96 ;
      RECT 91.47 28.9 92.2 33.59 ;
      RECT 0 28.9 92.2 33.55 ;
      RECT 89.075 22.94 89.425 28.505 ;
      RECT 88.625 22.94 88.975 28.505 ;
      RECT 88.175 22.94 88.525 28.505 ;
      RECT 87.725 22.94 88.075 28.505 ;
      RECT 0 22.91 87.625 28.505 ;
      RECT 91.22 22.94 91.34 28.475 ;
      RECT 90.88 22.94 91 28.42 ;
      RECT 0 22.94 92.2 28.39 ;
      RECT 91.23 22.9 92.2 28.39 ;
      RECT 90.925 22.775 91.045 28.39 ;
      RECT 90.615 22.775 90.735 28.39 ;
      RECT 90.305 22.775 90.425 28.39 ;
      RECT 89.995 22.775 90.115 28.39 ;
      RECT 89.685 22.775 89.805 28.39 ;
      RECT 89.375 22.775 89.495 28.39 ;
      RECT 89.065 22.775 89.185 28.39 ;
      RECT 88.72 22.77 88.79 28.505 ;
      RECT 88.58 22.77 88.65 28.39 ;
      RECT 88.44 22.77 88.51 28.505 ;
      RECT 88.3 22.77 88.37 28.505 ;
      RECT 88.16 22.77 88.23 28.39 ;
      RECT 88.02 22.77 88.09 28.39 ;
      RECT 0 22.91 87.7 28.39 ;
      RECT 91.235 22.775 91.355 28.39 ;
      RECT 0 22.77 87.7 22.84 ;
      RECT 0 17.78 90.72 22.43 ;
      RECT 0 17.78 92.2 22.39 ;
      RECT 91.605 17.7 92.2 22.39 ;
      RECT 0 12.22 90.695 16.87 ;
      RECT 0 12.22 92.2 16.79 ;
      RECT 91.605 12.1 92.2 16.79 ;
      RECT 0 11.79 87.745 11.86 ;
      RECT 0 11.65 87.745 11.72 ;
      RECT 0 6.66 90.695 11.31 ;
      RECT 0 6.7 92.2 11.19 ;
      RECT 0 6.23 87.7 6.3 ;
      RECT 0 6.09 87.7 6.16 ;
      RECT 91.605 1.1 92.2 5.79 ;
      RECT 0 1.1 92.2 5.75 ;
      RECT 90.81 0 91.16 0.675 ;
      RECT 90.36 0 90.71 0.675 ;
      RECT 89.91 0 90.26 0.675 ;
      RECT 89.46 0 89.81 0.675 ;
      RECT 89.01 0 89.36 0.675 ;
      RECT 88.56 0 88.91 0.675 ;
      RECT 88.11 0 88.46 0.675 ;
      RECT 87.66 0 88.01 0.675 ;
      RECT 0 0 87.56 0.675 ;
      RECT 0 0 92.2 0.59 ;
      RECT 91.22 256.29 91.57 256.36 ;
      RECT 91.22 256.43 91.57 256.5 ;
      RECT 91.215 50.57 91.565 50.64 ;
      RECT 91.215 50.71 91.565 50.78 ;
      RECT 91.21 200.69 91.56 200.76 ;
      RECT 91.21 200.83 91.56 200.9 ;
      RECT 91.21 295.21 91.56 295.28 ;
      RECT 91.21 295.35 91.56 295.42 ;
      RECT 91.09 17.265 91.44 17.335 ;
      RECT 91.045 72.82 91.395 72.89 ;
      RECT 91.045 72.96 91.395 73.03 ;
      RECT 91.045 84.06 91.395 84.13 ;
      RECT 91.045 139.665 91.395 139.735 ;
      RECT 91.045 223 91.395 223.07 ;
      RECT 91.045 267.53 91.395 267.6 ;
      RECT 91.045 311.92 91.395 311.99 ;
      RECT 91.02 117.29 91.37 117.36 ;
      RECT 91.02 117.43 91.37 117.5 ;
      RECT 91.02 272.97 91.37 273.04 ;
      RECT 91.02 273.11 91.37 273.18 ;
      RECT 91.02 300.77 91.37 300.84 ;
      RECT 91.02 300.91 91.37 300.98 ;
      RECT 91.015 161.77 91.365 161.84 ;
      RECT 91.015 161.91 91.365 161.98 ;
      RECT 91.015 317.45 91.365 317.52 ;
      RECT 91.015 317.59 91.365 317.66 ;
      RECT 91.01 206.25 91.36 206.32 ;
      RECT 91.01 206.39 91.36 206.46 ;
      RECT 91.01 289.65 91.36 289.72 ;
      RECT 91.01 289.79 91.36 289.86 ;
      RECT 91.005 106.17 91.355 106.24 ;
      RECT 91.005 106.31 91.355 106.38 ;
      RECT 91.005 189.57 91.355 189.64 ;
      RECT 91.005 189.71 91.355 189.78 ;
      RECT 91 122.85 91.35 122.92 ;
      RECT 91 122.99 91.35 123.06 ;
      RECT 91 150.65 91.35 150.72 ;
      RECT 91 150.79 91.35 150.86 ;
      RECT 90.995 11.65 91.345 11.72 ;
      RECT 90.995 11.79 91.345 11.86 ;
      RECT 90.995 167.33 91.345 167.4 ;
      RECT 90.995 167.47 91.345 167.54 ;
      RECT 90.995 195.13 91.345 195.2 ;
      RECT 90.995 195.27 91.345 195.34 ;
      RECT 90.99 56.13 91.34 56.2 ;
      RECT 90.99 56.27 91.34 56.34 ;
      RECT 90.99 323.01 91.34 323.08 ;
      RECT 90.99 323.15 91.34 323.22 ;
      RECT 90.985 100.61 91.335 100.68 ;
      RECT 90.985 100.75 91.335 100.82 ;
      RECT 90.985 184.01 91.335 184.08 ;
      RECT 90.985 184.15 91.335 184.22 ;
      RECT 90.985 245.17 91.335 245.24 ;
      RECT 90.985 245.31 91.335 245.38 ;
      RECT 90.98 228.49 91.33 228.56 ;
      RECT 90.98 228.63 91.33 228.7 ;
      RECT 90.975 45.01 91.325 45.08 ;
      RECT 90.975 45.15 91.325 45.22 ;
      RECT 90.975 145.09 91.325 145.16 ;
      RECT 90.975 145.23 91.325 145.3 ;
      RECT 90.97 89.49 91.32 89.56 ;
      RECT 90.97 89.63 91.32 89.7 ;
      RECT 90.97 172.89 91.32 172.96 ;
      RECT 90.97 173.03 91.32 173.1 ;
      RECT 90.965 33.89 91.315 33.96 ;
      RECT 90.965 34.03 91.315 34.1 ;
      RECT 90.965 95.05 91.315 95.12 ;
      RECT 90.965 95.19 91.315 95.26 ;
      RECT 90.965 133.97 91.315 134.04 ;
      RECT 90.965 134.11 91.315 134.18 ;
      RECT 90.965 217.37 91.315 217.44 ;
      RECT 90.965 217.51 91.315 217.58 ;
      RECT 90.96 261.85 91.31 261.92 ;
      RECT 90.96 261.99 91.31 262.06 ;
      RECT 90.955 306.33 91.305 306.4 ;
      RECT 90.955 306.47 91.305 306.54 ;
      RECT 90.95 6.09 91.3 6.16 ;
      RECT 90.95 6.23 91.3 6.3 ;
      RECT 90.95 39.45 91.3 39.52 ;
      RECT 90.95 39.59 91.3 39.66 ;
      RECT 90.95 250.73 91.3 250.8 ;
      RECT 90.95 250.87 91.3 250.94 ;
      RECT 90.945 67.25 91.295 67.32 ;
      RECT 90.945 67.39 91.295 67.46 ;
      RECT 90.94 111.73 91.29 111.8 ;
      RECT 90.94 111.87 91.29 111.94 ;
      RECT 90.94 178.45 91.29 178.52 ;
      RECT 90.94 178.59 91.29 178.66 ;
      RECT 90.94 211.81 91.29 211.88 ;
      RECT 90.94 211.95 91.29 212.02 ;
      RECT 90.935 156.21 91.285 156.28 ;
      RECT 90.935 156.35 91.285 156.42 ;
      RECT 90.935 239.61 91.285 239.68 ;
      RECT 90.935 239.75 91.285 239.82 ;
      RECT 90.935 339.69 91.285 339.76 ;
      RECT 90.935 339.83 91.285 339.9 ;
      RECT 90.93 284.09 91.28 284.16 ;
      RECT 90.93 284.23 91.28 284.3 ;
      RECT 90.925 328.57 91.275 328.64 ;
      RECT 90.925 328.71 91.275 328.78 ;
      RECT 90.92 61.69 91.27 61.76 ;
      RECT 90.92 61.83 91.27 61.9 ;
      RECT 90.92 78.37 91.27 78.44 ;
      RECT 90.92 78.51 91.27 78.58 ;
      RECT 90.885 234.07 91.235 234.14 ;
      RECT 90.885 234.21 91.235 234.28 ;
      RECT 90.885 278.6 91.235 278.67 ;
      RECT 90.85 128.41 91.2 128.48 ;
      RECT 90.85 128.55 91.2 128.62 ;
      RECT 90.82 334.13 91.17 334.2 ;
      RECT 90.82 334.27 91.17 334.34 ;
      RECT 90.77 256.29 91.12 256.36 ;
      RECT 90.77 256.43 91.12 256.5 ;
      RECT 90.765 50.57 91.115 50.64 ;
      RECT 90.765 50.71 91.115 50.78 ;
      RECT 90.76 200.69 91.11 200.76 ;
      RECT 90.76 200.83 91.11 200.9 ;
      RECT 90.76 295.21 91.11 295.28 ;
      RECT 90.76 295.35 91.11 295.42 ;
      RECT 90.64 17.265 90.99 17.335 ;
      RECT 90.595 72.82 90.945 72.89 ;
      RECT 90.595 72.96 90.945 73.03 ;
      RECT 90.595 84.06 90.945 84.13 ;
      RECT 90.595 139.665 90.945 139.735 ;
      RECT 90.595 223 90.945 223.07 ;
      RECT 90.595 267.53 90.945 267.6 ;
      RECT 90.595 311.92 90.945 311.99 ;
      RECT 90.57 117.29 90.92 117.36 ;
      RECT 90.57 117.43 90.92 117.5 ;
      RECT 90.57 272.97 90.92 273.04 ;
      RECT 90.57 273.11 90.92 273.18 ;
      RECT 90.57 300.77 90.92 300.84 ;
      RECT 90.57 300.91 90.92 300.98 ;
      RECT 90.565 161.77 90.915 161.84 ;
      RECT 90.565 161.91 90.915 161.98 ;
      RECT 90.565 317.45 90.915 317.52 ;
      RECT 90.565 317.59 90.915 317.66 ;
      RECT 90.56 206.25 90.91 206.32 ;
      RECT 90.56 206.39 90.91 206.46 ;
      RECT 90.56 289.65 90.91 289.72 ;
      RECT 90.56 289.79 90.91 289.86 ;
      RECT 90.555 106.17 90.905 106.24 ;
      RECT 90.555 106.31 90.905 106.38 ;
      RECT 90.555 189.57 90.905 189.64 ;
      RECT 90.555 189.71 90.905 189.78 ;
      RECT 90.55 122.85 90.9 122.92 ;
      RECT 90.55 122.99 90.9 123.06 ;
      RECT 90.55 150.65 90.9 150.72 ;
      RECT 90.55 150.79 90.9 150.86 ;
      RECT 90.545 11.65 90.895 11.72 ;
      RECT 90.545 11.79 90.895 11.86 ;
      RECT 90.545 167.33 90.895 167.4 ;
      RECT 90.545 167.47 90.895 167.54 ;
      RECT 90.545 195.13 90.895 195.2 ;
      RECT 90.545 195.27 90.895 195.34 ;
      RECT 90.54 56.13 90.89 56.2 ;
      RECT 90.54 56.27 90.89 56.34 ;
      RECT 90.54 323.01 90.89 323.08 ;
      RECT 90.54 323.15 90.89 323.22 ;
      RECT 90.535 100.61 90.885 100.68 ;
      RECT 90.535 100.75 90.885 100.82 ;
      RECT 90.535 184.01 90.885 184.08 ;
      RECT 90.535 184.15 90.885 184.22 ;
      RECT 90.535 245.17 90.885 245.24 ;
      RECT 90.535 245.31 90.885 245.38 ;
      RECT 90.53 228.49 90.88 228.56 ;
      RECT 90.53 228.63 90.88 228.7 ;
      RECT 90.525 45.01 90.875 45.08 ;
      RECT 90.525 45.15 90.875 45.22 ;
      RECT 90.525 145.09 90.875 145.16 ;
      RECT 90.525 145.23 90.875 145.3 ;
      RECT 90.52 89.49 90.87 89.56 ;
      RECT 90.52 89.63 90.87 89.7 ;
      RECT 90.52 172.89 90.87 172.96 ;
      RECT 90.52 173.03 90.87 173.1 ;
      RECT 90.515 33.89 90.865 33.96 ;
      RECT 90.515 34.03 90.865 34.1 ;
      RECT 90.515 95.05 90.865 95.12 ;
      RECT 90.515 95.19 90.865 95.26 ;
      RECT 90.515 133.97 90.865 134.04 ;
      RECT 90.515 134.11 90.865 134.18 ;
      RECT 90.515 217.37 90.865 217.44 ;
      RECT 90.515 217.51 90.865 217.58 ;
      RECT 90.51 261.85 90.86 261.92 ;
      RECT 90.51 261.99 90.86 262.06 ;
      RECT 90.505 306.33 90.855 306.4 ;
      RECT 90.505 306.47 90.855 306.54 ;
      RECT 90.5 6.09 90.85 6.16 ;
      RECT 90.5 6.23 90.85 6.3 ;
      RECT 90.5 39.45 90.85 39.52 ;
      RECT 90.5 39.59 90.85 39.66 ;
      RECT 90.5 250.73 90.85 250.8 ;
      RECT 90.5 250.87 90.85 250.94 ;
      RECT 90.495 67.25 90.845 67.32 ;
      RECT 90.495 67.39 90.845 67.46 ;
      RECT 90.49 111.73 90.84 111.8 ;
      RECT 90.49 111.87 90.84 111.94 ;
      RECT 90.49 178.45 90.84 178.52 ;
      RECT 90.49 178.59 90.84 178.66 ;
      RECT 90.49 211.81 90.84 211.88 ;
      RECT 90.49 211.95 90.84 212.02 ;
      RECT 90.485 156.21 90.835 156.28 ;
      RECT 90.485 156.35 90.835 156.42 ;
      RECT 90.485 239.61 90.835 239.68 ;
      RECT 90.485 239.75 90.835 239.82 ;
      RECT 90.485 339.69 90.835 339.76 ;
      RECT 90.485 339.83 90.835 339.9 ;
      RECT 90.48 284.09 90.83 284.16 ;
      RECT 90.48 284.23 90.83 284.3 ;
      RECT 90.475 328.57 90.825 328.64 ;
      RECT 90.475 328.71 90.825 328.78 ;
      RECT 90.47 61.69 90.82 61.76 ;
      RECT 90.47 61.83 90.82 61.9 ;
      RECT 90.47 78.37 90.82 78.44 ;
      RECT 90.47 78.51 90.82 78.58 ;
      RECT 90.435 234.07 90.785 234.14 ;
      RECT 90.435 234.21 90.785 234.28 ;
      RECT 90.435 278.6 90.785 278.67 ;
      RECT 90.4 128.41 90.75 128.48 ;
      RECT 90.4 128.55 90.75 128.62 ;
      RECT 90.37 334.13 90.72 334.2 ;
      RECT 90.37 334.27 90.72 334.34 ;
      RECT 90.32 256.29 90.67 256.36 ;
      RECT 90.32 256.43 90.67 256.5 ;
      RECT 90.315 50.57 90.665 50.64 ;
      RECT 90.315 50.71 90.665 50.78 ;
      RECT 90.31 200.69 90.66 200.76 ;
      RECT 90.31 200.83 90.66 200.9 ;
      RECT 90.31 295.21 90.66 295.28 ;
      RECT 90.31 295.35 90.66 295.42 ;
      RECT 90.19 17.265 90.54 17.335 ;
      RECT 90.145 72.82 90.495 72.89 ;
      RECT 90.145 72.96 90.495 73.03 ;
      RECT 90.145 84.06 90.495 84.13 ;
      RECT 90.145 139.665 90.495 139.735 ;
      RECT 90.145 223 90.495 223.07 ;
      RECT 90.145 267.53 90.495 267.6 ;
      RECT 90.145 311.92 90.495 311.99 ;
      RECT 90.12 117.29 90.47 117.36 ;
      RECT 90.12 117.43 90.47 117.5 ;
      RECT 90.12 272.97 90.47 273.04 ;
      RECT 90.12 273.11 90.47 273.18 ;
      RECT 90.12 300.77 90.47 300.84 ;
      RECT 90.12 300.91 90.47 300.98 ;
      RECT 90.115 161.77 90.465 161.84 ;
      RECT 90.115 161.91 90.465 161.98 ;
      RECT 90.115 317.45 90.465 317.52 ;
      RECT 90.115 317.59 90.465 317.66 ;
      RECT 90.11 206.25 90.46 206.32 ;
      RECT 90.11 206.39 90.46 206.46 ;
      RECT 90.11 289.65 90.46 289.72 ;
      RECT 90.11 289.79 90.46 289.86 ;
      RECT 90.105 106.17 90.455 106.24 ;
      RECT 90.105 106.31 90.455 106.38 ;
      RECT 90.105 189.57 90.455 189.64 ;
      RECT 90.105 189.71 90.455 189.78 ;
      RECT 90.1 122.85 90.45 122.92 ;
      RECT 90.1 122.99 90.45 123.06 ;
      RECT 90.1 150.65 90.45 150.72 ;
      RECT 90.1 150.79 90.45 150.86 ;
      RECT 90.095 11.65 90.445 11.72 ;
      RECT 90.095 11.79 90.445 11.86 ;
      RECT 90.095 167.33 90.445 167.4 ;
      RECT 90.095 167.47 90.445 167.54 ;
      RECT 90.095 195.13 90.445 195.2 ;
      RECT 90.095 195.27 90.445 195.34 ;
      RECT 90.09 56.13 90.44 56.2 ;
      RECT 90.09 56.27 90.44 56.34 ;
      RECT 90.09 323.01 90.44 323.08 ;
      RECT 90.09 323.15 90.44 323.22 ;
      RECT 90.085 100.61 90.435 100.68 ;
      RECT 90.085 100.75 90.435 100.82 ;
      RECT 90.085 184.01 90.435 184.08 ;
      RECT 90.085 184.15 90.435 184.22 ;
      RECT 90.085 245.17 90.435 245.24 ;
      RECT 90.085 245.31 90.435 245.38 ;
      RECT 90.08 228.49 90.43 228.56 ;
      RECT 90.08 228.63 90.43 228.7 ;
      RECT 90.075 45.01 90.425 45.08 ;
      RECT 90.075 45.15 90.425 45.22 ;
      RECT 90.075 145.09 90.425 145.16 ;
      RECT 90.075 145.23 90.425 145.3 ;
      RECT 90.07 89.49 90.42 89.56 ;
      RECT 90.07 89.63 90.42 89.7 ;
      RECT 90.07 172.89 90.42 172.96 ;
      RECT 90.07 173.03 90.42 173.1 ;
      RECT 90.065 33.89 90.415 33.96 ;
      RECT 90.065 34.03 90.415 34.1 ;
      RECT 90.065 95.05 90.415 95.12 ;
      RECT 90.065 95.19 90.415 95.26 ;
      RECT 90.065 133.97 90.415 134.04 ;
      RECT 90.065 134.11 90.415 134.18 ;
      RECT 90.065 217.37 90.415 217.44 ;
      RECT 90.065 217.51 90.415 217.58 ;
      RECT 90.06 261.85 90.41 261.92 ;
      RECT 90.06 261.99 90.41 262.06 ;
      RECT 90.055 306.33 90.405 306.4 ;
      RECT 90.055 306.47 90.405 306.54 ;
      RECT 90.05 6.09 90.4 6.16 ;
      RECT 90.05 6.23 90.4 6.3 ;
      RECT 90.05 39.45 90.4 39.52 ;
      RECT 90.05 39.59 90.4 39.66 ;
      RECT 90.05 250.73 90.4 250.8 ;
      RECT 90.05 250.87 90.4 250.94 ;
      RECT 90.045 67.25 90.395 67.32 ;
      RECT 90.045 67.39 90.395 67.46 ;
      RECT 90.04 111.73 90.39 111.8 ;
      RECT 90.04 111.87 90.39 111.94 ;
      RECT 90.04 178.45 90.39 178.52 ;
      RECT 90.04 178.59 90.39 178.66 ;
      RECT 90.04 211.81 90.39 211.88 ;
      RECT 90.04 211.95 90.39 212.02 ;
      RECT 90.035 156.21 90.385 156.28 ;
      RECT 90.035 156.35 90.385 156.42 ;
      RECT 90.035 239.61 90.385 239.68 ;
      RECT 90.035 239.75 90.385 239.82 ;
      RECT 90.035 339.69 90.385 339.76 ;
      RECT 90.035 339.83 90.385 339.9 ;
      RECT 90.03 284.09 90.38 284.16 ;
      RECT 90.03 284.23 90.38 284.3 ;
      RECT 90.025 328.57 90.375 328.64 ;
      RECT 90.025 328.71 90.375 328.78 ;
      RECT 90.02 61.69 90.37 61.76 ;
      RECT 90.02 61.83 90.37 61.9 ;
      RECT 90.02 78.37 90.37 78.44 ;
      RECT 90.02 78.51 90.37 78.58 ;
      RECT 89.985 234.07 90.335 234.14 ;
      RECT 89.985 234.21 90.335 234.28 ;
      RECT 89.985 278.6 90.335 278.67 ;
      RECT 89.95 128.41 90.3 128.48 ;
      RECT 89.95 128.55 90.3 128.62 ;
      RECT 89.92 334.13 90.27 334.2 ;
      RECT 89.92 334.27 90.27 334.34 ;
      RECT 89.87 256.29 90.22 256.36 ;
      RECT 89.87 256.43 90.22 256.5 ;
      RECT 89.865 50.57 90.215 50.64 ;
      RECT 89.865 50.71 90.215 50.78 ;
      RECT 89.86 200.69 90.21 200.76 ;
      RECT 89.86 200.83 90.21 200.9 ;
      RECT 89.86 295.21 90.21 295.28 ;
      RECT 89.86 295.35 90.21 295.42 ;
      RECT 89.74 17.265 90.09 17.335 ;
      RECT 89.695 72.82 90.045 72.89 ;
      RECT 89.695 72.96 90.045 73.03 ;
      RECT 89.695 84.06 90.045 84.13 ;
      RECT 89.695 139.665 90.045 139.735 ;
      RECT 89.695 223 90.045 223.07 ;
      RECT 89.695 267.53 90.045 267.6 ;
      RECT 89.695 311.92 90.045 311.99 ;
      RECT 89.67 117.29 90.02 117.36 ;
      RECT 89.67 117.43 90.02 117.5 ;
      RECT 89.67 272.97 90.02 273.04 ;
      RECT 89.67 273.11 90.02 273.18 ;
      RECT 89.67 300.77 90.02 300.84 ;
      RECT 89.67 300.91 90.02 300.98 ;
      RECT 89.665 161.77 90.015 161.84 ;
      RECT 89.665 161.91 90.015 161.98 ;
      RECT 89.665 317.45 90.015 317.52 ;
      RECT 89.665 317.59 90.015 317.66 ;
      RECT 89.66 206.25 90.01 206.32 ;
      RECT 89.66 206.39 90.01 206.46 ;
      RECT 89.66 289.65 90.01 289.72 ;
      RECT 89.66 289.79 90.01 289.86 ;
      RECT 89.655 106.17 90.005 106.24 ;
      RECT 89.655 106.31 90.005 106.38 ;
      RECT 89.655 189.57 90.005 189.64 ;
      RECT 89.655 189.71 90.005 189.78 ;
      RECT 89.65 122.85 90 122.92 ;
      RECT 89.65 122.99 90 123.06 ;
      RECT 89.65 150.65 90 150.72 ;
      RECT 89.65 150.79 90 150.86 ;
      RECT 89.645 11.65 89.995 11.72 ;
      RECT 89.645 11.79 89.995 11.86 ;
      RECT 89.645 167.33 89.995 167.4 ;
      RECT 89.645 167.47 89.995 167.54 ;
      RECT 89.645 195.13 89.995 195.2 ;
      RECT 89.645 195.27 89.995 195.34 ;
      RECT 89.64 56.13 89.99 56.2 ;
      RECT 89.64 56.27 89.99 56.34 ;
      RECT 89.64 323.01 89.99 323.08 ;
      RECT 89.64 323.15 89.99 323.22 ;
      RECT 89.635 100.61 89.985 100.68 ;
      RECT 89.635 100.75 89.985 100.82 ;
      RECT 89.635 184.01 89.985 184.08 ;
      RECT 89.635 184.15 89.985 184.22 ;
      RECT 89.635 245.17 89.985 245.24 ;
      RECT 89.635 245.31 89.985 245.38 ;
      RECT 89.63 228.49 89.98 228.56 ;
      RECT 89.63 228.63 89.98 228.7 ;
      RECT 89.625 45.01 89.975 45.08 ;
      RECT 89.625 45.15 89.975 45.22 ;
      RECT 89.625 145.09 89.975 145.16 ;
      RECT 89.625 145.23 89.975 145.3 ;
      RECT 89.62 89.49 89.97 89.56 ;
      RECT 89.62 89.63 89.97 89.7 ;
      RECT 89.62 172.89 89.97 172.96 ;
      RECT 89.62 173.03 89.97 173.1 ;
      RECT 89.615 33.89 89.965 33.96 ;
      RECT 89.615 34.03 89.965 34.1 ;
      RECT 89.615 95.05 89.965 95.12 ;
      RECT 89.615 95.19 89.965 95.26 ;
      RECT 89.615 133.97 89.965 134.04 ;
      RECT 89.615 134.11 89.965 134.18 ;
      RECT 89.615 217.37 89.965 217.44 ;
      RECT 89.615 217.51 89.965 217.58 ;
      RECT 89.61 261.85 89.96 261.92 ;
      RECT 89.61 261.99 89.96 262.06 ;
      RECT 89.605 306.33 89.955 306.4 ;
      RECT 89.605 306.47 89.955 306.54 ;
      RECT 89.6 6.09 89.95 6.16 ;
      RECT 89.6 6.23 89.95 6.3 ;
      RECT 89.6 39.45 89.95 39.52 ;
      RECT 89.6 39.59 89.95 39.66 ;
      RECT 89.6 250.73 89.95 250.8 ;
      RECT 89.6 250.87 89.95 250.94 ;
      RECT 89.595 67.25 89.945 67.32 ;
      RECT 89.595 67.39 89.945 67.46 ;
      RECT 89.59 111.73 89.94 111.8 ;
      RECT 89.59 111.87 89.94 111.94 ;
      RECT 89.59 178.45 89.94 178.52 ;
      RECT 89.59 178.59 89.94 178.66 ;
      RECT 89.59 211.81 89.94 211.88 ;
      RECT 89.59 211.95 89.94 212.02 ;
      RECT 89.585 156.21 89.935 156.28 ;
      RECT 89.585 156.35 89.935 156.42 ;
      RECT 89.585 239.61 89.935 239.68 ;
      RECT 89.585 239.75 89.935 239.82 ;
      RECT 89.585 339.69 89.935 339.76 ;
      RECT 89.585 339.83 89.935 339.9 ;
      RECT 89.58 284.09 89.93 284.16 ;
      RECT 89.58 284.23 89.93 284.3 ;
      RECT 89.575 328.57 89.925 328.64 ;
      RECT 89.575 328.71 89.925 328.78 ;
      RECT 89.57 61.69 89.92 61.76 ;
      RECT 89.57 61.83 89.92 61.9 ;
      RECT 89.57 78.37 89.92 78.44 ;
      RECT 89.57 78.51 89.92 78.58 ;
      RECT 89.535 234.07 89.885 234.14 ;
      RECT 89.535 234.21 89.885 234.28 ;
      RECT 89.535 278.6 89.885 278.67 ;
      RECT 89.5 128.41 89.85 128.48 ;
      RECT 89.5 128.55 89.85 128.62 ;
      RECT 89.47 334.13 89.82 334.2 ;
      RECT 89.47 334.27 89.82 334.34 ;
      RECT 89.42 256.29 89.77 256.36 ;
      RECT 89.42 256.43 89.77 256.5 ;
      RECT 89.415 50.57 89.765 50.64 ;
      RECT 89.415 50.71 89.765 50.78 ;
      RECT 89.41 200.69 89.76 200.76 ;
      RECT 89.41 200.83 89.76 200.9 ;
      RECT 89.41 295.21 89.76 295.28 ;
      RECT 89.41 295.35 89.76 295.42 ;
      RECT 89.29 17.265 89.64 17.335 ;
      RECT 89.245 72.82 89.595 72.89 ;
      RECT 89.245 72.96 89.595 73.03 ;
      RECT 89.245 84.06 89.595 84.13 ;
      RECT 89.245 139.665 89.595 139.735 ;
      RECT 89.245 223 89.595 223.07 ;
      RECT 89.245 267.53 89.595 267.6 ;
      RECT 89.245 311.92 89.595 311.99 ;
      RECT 89.22 117.29 89.57 117.36 ;
      RECT 89.22 117.43 89.57 117.5 ;
      RECT 89.22 272.97 89.57 273.04 ;
      RECT 89.22 273.11 89.57 273.18 ;
      RECT 89.22 300.77 89.57 300.84 ;
      RECT 89.22 300.91 89.57 300.98 ;
      RECT 89.215 161.77 89.565 161.84 ;
      RECT 89.215 161.91 89.565 161.98 ;
      RECT 89.215 317.45 89.565 317.52 ;
      RECT 89.215 317.59 89.565 317.66 ;
      RECT 89.21 206.25 89.56 206.32 ;
      RECT 89.21 206.39 89.56 206.46 ;
      RECT 89.21 289.65 89.56 289.72 ;
      RECT 89.21 289.79 89.56 289.86 ;
      RECT 89.205 106.17 89.555 106.24 ;
      RECT 89.205 106.31 89.555 106.38 ;
      RECT 89.205 189.57 89.555 189.64 ;
      RECT 89.205 189.71 89.555 189.78 ;
      RECT 89.2 122.85 89.55 122.92 ;
      RECT 89.2 122.99 89.55 123.06 ;
      RECT 89.2 150.65 89.55 150.72 ;
      RECT 89.2 150.79 89.55 150.86 ;
      RECT 89.195 11.65 89.545 11.72 ;
      RECT 89.195 11.79 89.545 11.86 ;
      RECT 89.195 167.33 89.545 167.4 ;
      RECT 89.195 167.47 89.545 167.54 ;
      RECT 89.195 195.13 89.545 195.2 ;
      RECT 89.195 195.27 89.545 195.34 ;
      RECT 89.19 56.13 89.54 56.2 ;
      RECT 89.19 56.27 89.54 56.34 ;
      RECT 89.19 323.01 89.54 323.08 ;
      RECT 89.19 323.15 89.54 323.22 ;
      RECT 89.185 100.61 89.535 100.68 ;
      RECT 89.185 100.75 89.535 100.82 ;
      RECT 89.185 184.01 89.535 184.08 ;
      RECT 89.185 184.15 89.535 184.22 ;
      RECT 89.185 245.17 89.535 245.24 ;
      RECT 89.185 245.31 89.535 245.38 ;
      RECT 89.18 228.49 89.53 228.56 ;
      RECT 89.18 228.63 89.53 228.7 ;
      RECT 89.175 45.01 89.525 45.08 ;
      RECT 89.175 45.15 89.525 45.22 ;
      RECT 89.175 145.09 89.525 145.16 ;
      RECT 89.175 145.23 89.525 145.3 ;
      RECT 89.17 89.49 89.52 89.56 ;
      RECT 89.17 89.63 89.52 89.7 ;
      RECT 89.17 172.89 89.52 172.96 ;
      RECT 89.17 173.03 89.52 173.1 ;
      RECT 89.165 33.89 89.515 33.96 ;
      RECT 89.165 34.03 89.515 34.1 ;
      RECT 89.165 95.05 89.515 95.12 ;
      RECT 89.165 95.19 89.515 95.26 ;
      RECT 89.165 133.97 89.515 134.04 ;
      RECT 89.165 134.11 89.515 134.18 ;
      RECT 89.165 217.37 89.515 217.44 ;
      RECT 89.165 217.51 89.515 217.58 ;
      RECT 89.16 261.85 89.51 261.92 ;
      RECT 89.16 261.99 89.51 262.06 ;
      RECT 89.155 306.33 89.505 306.4 ;
      RECT 89.155 306.47 89.505 306.54 ;
      RECT 89.15 6.09 89.5 6.16 ;
      RECT 89.15 6.23 89.5 6.3 ;
      RECT 89.15 39.45 89.5 39.52 ;
      RECT 89.15 39.59 89.5 39.66 ;
      RECT 89.15 250.73 89.5 250.8 ;
      RECT 89.15 250.87 89.5 250.94 ;
      RECT 89.145 67.25 89.495 67.32 ;
      RECT 89.145 67.39 89.495 67.46 ;
      RECT 89.14 111.73 89.49 111.8 ;
      RECT 89.14 111.87 89.49 111.94 ;
      RECT 89.14 178.45 89.49 178.52 ;
      RECT 89.14 178.59 89.49 178.66 ;
      RECT 89.14 211.81 89.49 211.88 ;
      RECT 89.14 211.95 89.49 212.02 ;
      RECT 89.135 156.21 89.485 156.28 ;
      RECT 89.135 156.35 89.485 156.42 ;
      RECT 89.135 239.61 89.485 239.68 ;
      RECT 89.135 239.75 89.485 239.82 ;
      RECT 89.135 339.69 89.485 339.76 ;
      RECT 89.135 339.83 89.485 339.9 ;
      RECT 89.13 284.09 89.48 284.16 ;
      RECT 89.13 284.23 89.48 284.3 ;
      RECT 89.125 328.57 89.475 328.64 ;
      RECT 89.125 328.71 89.475 328.78 ;
      RECT 89.12 61.69 89.47 61.76 ;
      RECT 89.12 61.83 89.47 61.9 ;
      RECT 89.12 78.37 89.47 78.44 ;
      RECT 89.12 78.51 89.47 78.58 ;
      RECT 89.085 234.07 89.435 234.14 ;
      RECT 89.085 234.21 89.435 234.28 ;
      RECT 89.085 278.6 89.435 278.67 ;
      RECT 89.05 128.41 89.4 128.48 ;
      RECT 89.05 128.55 89.4 128.62 ;
      RECT 89.02 334.13 89.37 334.2 ;
      RECT 89.02 334.27 89.37 334.34 ;
      RECT 88.97 256.29 89.32 256.36 ;
      RECT 88.97 256.43 89.32 256.5 ;
      RECT 88.965 50.57 89.315 50.64 ;
      RECT 88.965 50.71 89.315 50.78 ;
      RECT 88.96 200.69 89.31 200.76 ;
      RECT 88.96 200.83 89.31 200.9 ;
      RECT 88.96 295.21 89.31 295.28 ;
      RECT 88.96 295.35 89.31 295.42 ;
      RECT 88.84 17.265 89.19 17.335 ;
      RECT 88.795 72.82 89.145 72.89 ;
      RECT 88.795 72.96 89.145 73.03 ;
      RECT 88.795 84.06 89.145 84.13 ;
      RECT 88.795 139.665 89.145 139.735 ;
      RECT 88.795 223 89.145 223.07 ;
      RECT 88.795 267.53 89.145 267.6 ;
      RECT 88.795 311.92 89.145 311.99 ;
      RECT 88.77 117.29 89.12 117.36 ;
      RECT 88.77 117.43 89.12 117.5 ;
      RECT 88.77 272.97 89.12 273.04 ;
      RECT 88.77 273.11 89.12 273.18 ;
      RECT 88.77 300.77 89.12 300.84 ;
      RECT 88.77 300.91 89.12 300.98 ;
      RECT 88.765 161.77 89.115 161.84 ;
      RECT 88.765 161.91 89.115 161.98 ;
      RECT 88.765 317.45 89.115 317.52 ;
      RECT 88.765 317.59 89.115 317.66 ;
      RECT 88.76 206.25 89.11 206.32 ;
      RECT 88.76 206.39 89.11 206.46 ;
      RECT 88.76 289.65 89.11 289.72 ;
      RECT 88.76 289.79 89.11 289.86 ;
      RECT 88.755 106.17 89.105 106.24 ;
      RECT 88.755 106.31 89.105 106.38 ;
      RECT 88.755 189.57 89.105 189.64 ;
      RECT 88.755 189.71 89.105 189.78 ;
      RECT 88.75 122.85 89.1 122.92 ;
      RECT 88.75 122.99 89.1 123.06 ;
      RECT 88.75 150.65 89.1 150.72 ;
      RECT 88.75 150.79 89.1 150.86 ;
      RECT 88.745 11.65 89.095 11.72 ;
      RECT 88.745 11.79 89.095 11.86 ;
      RECT 88.745 167.33 89.095 167.4 ;
      RECT 88.745 167.47 89.095 167.54 ;
      RECT 88.745 195.13 89.095 195.2 ;
      RECT 88.745 195.27 89.095 195.34 ;
      RECT 88.74 56.13 89.09 56.2 ;
      RECT 88.74 56.27 89.09 56.34 ;
      RECT 88.74 323.01 89.09 323.08 ;
      RECT 88.74 323.15 89.09 323.22 ;
      RECT 88.735 100.61 89.085 100.68 ;
      RECT 88.735 100.75 89.085 100.82 ;
      RECT 88.735 184.01 89.085 184.08 ;
      RECT 88.735 184.15 89.085 184.22 ;
      RECT 88.735 245.17 89.085 245.24 ;
      RECT 88.735 245.31 89.085 245.38 ;
      RECT 88.73 228.49 89.08 228.56 ;
      RECT 88.73 228.63 89.08 228.7 ;
      RECT 88.725 45.01 89.075 45.08 ;
      RECT 88.725 45.15 89.075 45.22 ;
      RECT 88.725 145.09 89.075 145.16 ;
      RECT 88.725 145.23 89.075 145.3 ;
      RECT 88.72 89.49 89.07 89.56 ;
      RECT 88.72 89.63 89.07 89.7 ;
      RECT 88.72 172.89 89.07 172.96 ;
      RECT 88.72 173.03 89.07 173.1 ;
      RECT 88.715 33.89 89.065 33.96 ;
      RECT 88.715 34.03 89.065 34.1 ;
      RECT 88.715 95.05 89.065 95.12 ;
      RECT 88.715 95.19 89.065 95.26 ;
      RECT 88.715 133.97 89.065 134.04 ;
      RECT 88.715 134.11 89.065 134.18 ;
      RECT 88.715 217.37 89.065 217.44 ;
      RECT 88.715 217.51 89.065 217.58 ;
      RECT 88.71 261.85 89.06 261.92 ;
      RECT 88.71 261.99 89.06 262.06 ;
      RECT 88.705 306.33 89.055 306.4 ;
      RECT 88.705 306.47 89.055 306.54 ;
      RECT 88.7 6.09 89.05 6.16 ;
      RECT 88.7 6.23 89.05 6.3 ;
      RECT 88.7 39.45 89.05 39.52 ;
      RECT 88.7 39.59 89.05 39.66 ;
      RECT 88.7 250.73 89.05 250.8 ;
      RECT 88.7 250.87 89.05 250.94 ;
      RECT 88.695 67.25 89.045 67.32 ;
      RECT 88.695 67.39 89.045 67.46 ;
      RECT 88.69 111.73 89.04 111.8 ;
      RECT 88.69 111.87 89.04 111.94 ;
      RECT 88.69 178.45 89.04 178.52 ;
      RECT 88.69 178.59 89.04 178.66 ;
      RECT 88.69 211.81 89.04 211.88 ;
      RECT 88.69 211.95 89.04 212.02 ;
      RECT 88.685 156.21 89.035 156.28 ;
      RECT 88.685 156.35 89.035 156.42 ;
      RECT 88.685 239.61 89.035 239.68 ;
      RECT 88.685 239.75 89.035 239.82 ;
      RECT 88.685 339.69 89.035 339.76 ;
      RECT 88.685 339.83 89.035 339.9 ;
      RECT 88.68 284.09 89.03 284.16 ;
      RECT 88.68 284.23 89.03 284.3 ;
      RECT 88.675 328.57 89.025 328.64 ;
      RECT 88.675 328.71 89.025 328.78 ;
      RECT 88.67 61.69 89.02 61.76 ;
      RECT 88.67 61.83 89.02 61.9 ;
      RECT 88.67 78.37 89.02 78.44 ;
      RECT 88.67 78.51 89.02 78.58 ;
      RECT 88.635 234.07 88.985 234.14 ;
      RECT 88.635 234.21 88.985 234.28 ;
      RECT 88.635 278.6 88.985 278.67 ;
      RECT 88.6 128.41 88.95 128.48 ;
      RECT 88.6 128.55 88.95 128.62 ;
      RECT 88.57 334.13 88.92 334.2 ;
      RECT 88.57 334.27 88.92 334.34 ;
      RECT 88.52 256.29 88.87 256.36 ;
      RECT 88.52 256.43 88.87 256.5 ;
      RECT 88.515 50.57 88.865 50.64 ;
      RECT 88.515 50.71 88.865 50.78 ;
      RECT 88.51 200.69 88.86 200.76 ;
      RECT 88.51 200.83 88.86 200.9 ;
      RECT 88.51 295.21 88.86 295.28 ;
      RECT 88.51 295.35 88.86 295.42 ;
      RECT 88.39 17.265 88.74 17.335 ;
      RECT 88.345 72.82 88.695 72.89 ;
      RECT 88.345 72.96 88.695 73.03 ;
      RECT 88.345 84.06 88.695 84.13 ;
      RECT 88.345 139.665 88.695 139.735 ;
      RECT 88.345 223 88.695 223.07 ;
      RECT 88.345 267.53 88.695 267.6 ;
      RECT 88.345 311.92 88.695 311.99 ;
      RECT 88.32 117.29 88.67 117.36 ;
      RECT 88.32 117.43 88.67 117.5 ;
      RECT 88.32 272.97 88.67 273.04 ;
      RECT 88.32 273.11 88.67 273.18 ;
      RECT 88.32 300.77 88.67 300.84 ;
      RECT 88.32 300.91 88.67 300.98 ;
      RECT 88.315 161.77 88.665 161.84 ;
      RECT 88.315 161.91 88.665 161.98 ;
      RECT 88.315 317.45 88.665 317.52 ;
      RECT 88.315 317.59 88.665 317.66 ;
      RECT 88.31 206.25 88.66 206.32 ;
      RECT 88.31 206.39 88.66 206.46 ;
      RECT 88.31 289.65 88.66 289.72 ;
      RECT 88.31 289.79 88.66 289.86 ;
      RECT 88.305 106.17 88.655 106.24 ;
      RECT 88.305 106.31 88.655 106.38 ;
      RECT 88.305 189.57 88.655 189.64 ;
      RECT 88.305 189.71 88.655 189.78 ;
      RECT 88.3 122.85 88.65 122.92 ;
      RECT 88.3 122.99 88.65 123.06 ;
      RECT 88.3 150.65 88.65 150.72 ;
      RECT 88.3 150.79 88.65 150.86 ;
      RECT 88.295 11.65 88.645 11.72 ;
      RECT 88.295 11.79 88.645 11.86 ;
      RECT 88.295 167.33 88.645 167.4 ;
      RECT 88.295 167.47 88.645 167.54 ;
      RECT 88.295 195.13 88.645 195.2 ;
      RECT 88.295 195.27 88.645 195.34 ;
      RECT 88.29 56.13 88.64 56.2 ;
      RECT 88.29 56.27 88.64 56.34 ;
      RECT 88.29 323.01 88.64 323.08 ;
      RECT 88.29 323.15 88.64 323.22 ;
      RECT 88.285 100.61 88.635 100.68 ;
      RECT 88.285 100.75 88.635 100.82 ;
      RECT 88.285 184.01 88.635 184.08 ;
      RECT 88.285 184.15 88.635 184.22 ;
      RECT 88.285 245.17 88.635 245.24 ;
      RECT 88.285 245.31 88.635 245.38 ;
      RECT 88.28 228.49 88.63 228.56 ;
      RECT 88.28 228.63 88.63 228.7 ;
      RECT 88.275 45.01 88.625 45.08 ;
      RECT 88.275 45.15 88.625 45.22 ;
      RECT 88.275 145.09 88.625 145.16 ;
      RECT 88.275 145.23 88.625 145.3 ;
      RECT 88.27 89.49 88.62 89.56 ;
      RECT 88.27 89.63 88.62 89.7 ;
      RECT 88.27 172.89 88.62 172.96 ;
      RECT 88.27 173.03 88.62 173.1 ;
      RECT 88.265 33.89 88.615 33.96 ;
      RECT 88.265 34.03 88.615 34.1 ;
      RECT 88.265 95.05 88.615 95.12 ;
      RECT 88.265 95.19 88.615 95.26 ;
      RECT 88.265 133.97 88.615 134.04 ;
      RECT 88.265 134.11 88.615 134.18 ;
      RECT 88.265 217.37 88.615 217.44 ;
      RECT 88.265 217.51 88.615 217.58 ;
      RECT 88.26 261.85 88.61 261.92 ;
      RECT 88.26 261.99 88.61 262.06 ;
      RECT 88.255 306.33 88.605 306.4 ;
      RECT 88.255 306.47 88.605 306.54 ;
      RECT 88.25 6.09 88.6 6.16 ;
      RECT 88.25 6.23 88.6 6.3 ;
      RECT 88.25 39.45 88.6 39.52 ;
      RECT 88.25 39.59 88.6 39.66 ;
      RECT 88.25 250.73 88.6 250.8 ;
      RECT 88.25 250.87 88.6 250.94 ;
      RECT 88.245 67.25 88.595 67.32 ;
      RECT 88.245 67.39 88.595 67.46 ;
      RECT 88.24 111.73 88.59 111.8 ;
      RECT 88.24 111.87 88.59 111.94 ;
      RECT 88.24 178.45 88.59 178.52 ;
      RECT 88.24 178.59 88.59 178.66 ;
      RECT 88.24 211.81 88.59 211.88 ;
      RECT 88.24 211.95 88.59 212.02 ;
      RECT 88.235 156.21 88.585 156.28 ;
      RECT 88.235 156.35 88.585 156.42 ;
      RECT 88.235 239.61 88.585 239.68 ;
      RECT 88.235 239.75 88.585 239.82 ;
      RECT 88.235 339.69 88.585 339.76 ;
      RECT 88.235 339.83 88.585 339.9 ;
      RECT 88.23 284.09 88.58 284.16 ;
      RECT 88.23 284.23 88.58 284.3 ;
      RECT 88.225 328.57 88.575 328.64 ;
      RECT 88.225 328.71 88.575 328.78 ;
      RECT 88.22 61.69 88.57 61.76 ;
      RECT 88.22 61.83 88.57 61.9 ;
      RECT 88.22 78.37 88.57 78.44 ;
      RECT 88.22 78.51 88.57 78.58 ;
      RECT 88.185 234.07 88.535 234.14 ;
      RECT 88.185 234.21 88.535 234.28 ;
      RECT 88.185 278.6 88.535 278.67 ;
      RECT 88.15 128.41 88.5 128.48 ;
      RECT 88.15 128.55 88.5 128.62 ;
      RECT 88.12 334.13 88.47 334.2 ;
      RECT 88.12 334.27 88.47 334.34 ;
      RECT 88.07 256.29 88.42 256.36 ;
      RECT 88.07 256.43 88.42 256.5 ;
      RECT 88.065 50.57 88.415 50.64 ;
      RECT 88.065 50.71 88.415 50.78 ;
      RECT 88.06 200.69 88.41 200.76 ;
      RECT 88.06 200.83 88.41 200.9 ;
      RECT 88.06 295.21 88.41 295.28 ;
      RECT 88.06 295.35 88.41 295.42 ;
      RECT 87.94 17.265 88.29 17.335 ;
      RECT 87.895 72.82 88.245 72.89 ;
      RECT 87.895 72.96 88.245 73.03 ;
      RECT 87.895 84.06 88.245 84.13 ;
      RECT 87.895 139.665 88.245 139.735 ;
      RECT 87.895 223 88.245 223.07 ;
      RECT 87.895 267.53 88.245 267.6 ;
      RECT 87.895 311.92 88.245 311.99 ;
      RECT 87.87 117.29 88.22 117.36 ;
      RECT 87.87 117.43 88.22 117.5 ;
      RECT 87.87 272.97 88.22 273.04 ;
      RECT 87.87 273.11 88.22 273.18 ;
      RECT 87.87 300.77 88.22 300.84 ;
      RECT 87.87 300.91 88.22 300.98 ;
      RECT 87.865 161.77 88.215 161.84 ;
      RECT 87.865 161.91 88.215 161.98 ;
      RECT 87.865 317.45 88.215 317.52 ;
      RECT 87.865 317.59 88.215 317.66 ;
      RECT 87.86 206.25 88.21 206.32 ;
      RECT 87.86 206.39 88.21 206.46 ;
      RECT 87.86 289.65 88.21 289.72 ;
      RECT 87.86 289.79 88.21 289.86 ;
      RECT 87.855 106.17 88.205 106.24 ;
      RECT 87.855 106.31 88.205 106.38 ;
      RECT 87.855 189.57 88.205 189.64 ;
      RECT 87.855 189.71 88.205 189.78 ;
      RECT 87.85 122.85 88.2 122.92 ;
      RECT 87.85 122.99 88.2 123.06 ;
      RECT 87.85 150.65 88.2 150.72 ;
      RECT 87.85 150.79 88.2 150.86 ;
      RECT 87.845 11.65 88.195 11.72 ;
      RECT 87.845 11.79 88.195 11.86 ;
      RECT 87.845 167.33 88.195 167.4 ;
      RECT 87.845 167.47 88.195 167.54 ;
      RECT 87.845 195.13 88.195 195.2 ;
      RECT 87.845 195.27 88.195 195.34 ;
      RECT 87.84 56.13 88.19 56.2 ;
      RECT 87.84 56.27 88.19 56.34 ;
      RECT 87.84 323.01 88.19 323.08 ;
      RECT 87.84 323.15 88.19 323.22 ;
      RECT 87.835 100.61 88.185 100.68 ;
      RECT 87.835 100.75 88.185 100.82 ;
      RECT 87.835 184.01 88.185 184.08 ;
      RECT 87.835 184.15 88.185 184.22 ;
      RECT 87.835 245.17 88.185 245.24 ;
      RECT 87.835 245.31 88.185 245.38 ;
      RECT 87.83 228.49 88.18 228.56 ;
      RECT 87.83 228.63 88.18 228.7 ;
      RECT 87.825 45.01 88.175 45.08 ;
      RECT 87.825 45.15 88.175 45.22 ;
      RECT 87.825 145.09 88.175 145.16 ;
      RECT 87.825 145.23 88.175 145.3 ;
      RECT 87.82 89.49 88.17 89.56 ;
      RECT 87.82 89.63 88.17 89.7 ;
      RECT 87.82 172.89 88.17 172.96 ;
      RECT 87.82 173.03 88.17 173.1 ;
      RECT 87.815 33.89 88.165 33.96 ;
      RECT 87.815 34.03 88.165 34.1 ;
      RECT 87.815 95.05 88.165 95.12 ;
      RECT 87.815 95.19 88.165 95.26 ;
      RECT 87.815 133.97 88.165 134.04 ;
      RECT 87.815 134.11 88.165 134.18 ;
      RECT 87.815 217.37 88.165 217.44 ;
      RECT 87.815 217.51 88.165 217.58 ;
      RECT 87.81 261.85 88.16 261.92 ;
      RECT 87.81 261.99 88.16 262.06 ;
      RECT 87.805 306.33 88.155 306.4 ;
      RECT 87.805 306.47 88.155 306.54 ;
      RECT 87.8 6.09 88.15 6.16 ;
      RECT 87.8 6.23 88.15 6.3 ;
      RECT 87.8 39.45 88.15 39.52 ;
      RECT 87.8 39.59 88.15 39.66 ;
      RECT 87.8 250.73 88.15 250.8 ;
      RECT 87.8 250.87 88.15 250.94 ;
      RECT 87.795 67.25 88.145 67.32 ;
      RECT 87.795 67.39 88.145 67.46 ;
      RECT 87.79 111.73 88.14 111.8 ;
      RECT 87.79 111.87 88.14 111.94 ;
      RECT 87.79 178.45 88.14 178.52 ;
      RECT 87.79 178.59 88.14 178.66 ;
      RECT 87.79 211.81 88.14 211.88 ;
      RECT 87.79 211.95 88.14 212.02 ;
      RECT 87.785 156.21 88.135 156.28 ;
      RECT 87.785 156.35 88.135 156.42 ;
      RECT 87.785 239.61 88.135 239.68 ;
      RECT 87.785 239.75 88.135 239.82 ;
      RECT 87.785 339.69 88.135 339.76 ;
      RECT 87.785 339.83 88.135 339.9 ;
      RECT 87.78 284.09 88.13 284.16 ;
      RECT 87.78 284.23 88.13 284.3 ;
      RECT 87.775 328.57 88.125 328.64 ;
      RECT 87.775 328.71 88.125 328.78 ;
      RECT 87.77 61.69 88.12 61.76 ;
      RECT 87.77 61.83 88.12 61.9 ;
      RECT 87.77 78.37 88.12 78.44 ;
      RECT 87.77 78.51 88.12 78.58 ;
      RECT 87.735 234.07 88.085 234.14 ;
      RECT 87.735 234.21 88.085 234.28 ;
      RECT 87.735 278.6 88.085 278.67 ;
      RECT 87.7 128.41 88.05 128.48 ;
      RECT 87.7 128.55 88.05 128.62 ;
      RECT 87.67 334.13 88.02 334.2 ;
      RECT 87.67 334.27 88.02 334.34 ;
      RECT 87.62 256.29 87.97 256.36 ;
      RECT 87.62 256.43 87.97 256.5 ;
      RECT 87.615 50.57 87.965 50.64 ;
      RECT 87.615 50.71 87.965 50.78 ;
      RECT 87.61 200.69 87.96 200.76 ;
      RECT 87.61 200.83 87.96 200.9 ;
      RECT 87.61 295.21 87.96 295.28 ;
      RECT 87.61 295.35 87.96 295.42 ;
      RECT 87.49 17.265 87.84 17.335 ;
    LAYER M6 SPACING 0.05 ;
      RECT 0 0 92.2 346 ;
    LAYER M7 ;
      RECT 67.545 56.345 67.665 57.345 ;
      RECT 67.545 138.7 67.665 139.7 ;
      RECT 67.545 221.055 67.665 222.055 ;
      RECT 67.545 303.41 67.665 304.41 ;
      RECT 67.54 18.8 67.66 19.8 ;
      RECT 67.54 101.155 67.66 102.155 ;
      RECT 67.54 183.51 67.66 184.51 ;
      RECT 67.54 265.865 67.66 266.865 ;
      RECT 67.535 63.61 67.655 64.61 ;
      RECT 67.535 145.965 67.655 146.965 ;
      RECT 67.535 228.32 67.655 229.32 ;
      RECT 67.535 310.675 67.655 311.675 ;
      RECT 67.53 26.065 67.65 27.065 ;
      RECT 67.53 108.42 67.65 109.42 ;
      RECT 67.53 190.775 67.65 191.775 ;
      RECT 67.53 273.13 67.65 274.13 ;
      RECT 67.525 70.875 67.645 71.875 ;
      RECT 67.525 153.23 67.645 154.23 ;
      RECT 67.525 235.585 67.645 236.585 ;
      RECT 67.525 317.94 67.645 318.94 ;
      RECT 67.52 33.33 67.64 34.33 ;
      RECT 67.52 115.685 67.64 116.685 ;
      RECT 67.52 198.04 67.64 199.04 ;
      RECT 67.52 280.395 67.64 281.395 ;
      RECT 67.515 78.14 67.635 79.14 ;
      RECT 67.515 160.495 67.635 161.495 ;
      RECT 67.515 242.85 67.635 243.85 ;
      RECT 67.515 325.205 67.635 326.205 ;
      RECT 67.51 40.595 67.63 41.595 ;
      RECT 67.51 122.95 67.63 123.95 ;
      RECT 67.51 205.305 67.63 206.305 ;
      RECT 67.51 287.66 67.63 288.66 ;
      RECT 67.505 3.05 67.625 4.05 ;
      RECT 67.505 85.405 67.625 86.405 ;
      RECT 67.505 167.76 67.625 168.76 ;
      RECT 67.505 250.115 67.625 251.115 ;
      RECT 67.505 332.47 67.625 333.47 ;
      RECT 67.5 47.86 67.62 48.86 ;
      RECT 67.5 130.215 67.62 131.215 ;
      RECT 67.5 212.57 67.62 213.57 ;
      RECT 67.5 294.925 67.62 295.925 ;
      RECT 67.495 10.315 67.615 11.315 ;
      RECT 67.495 92.67 67.615 93.67 ;
      RECT 67.495 175.025 67.615 176.025 ;
      RECT 67.495 257.38 67.615 258.38 ;
      RECT 67.495 339.735 67.615 340.735 ;
      RECT 67.49 55.125 67.61 56.125 ;
      RECT 67.49 137.48 67.61 138.48 ;
      RECT 67.49 219.835 67.61 220.835 ;
      RECT 67.49 302.19 67.61 303.19 ;
      RECT 67.485 17.58 67.605 18.58 ;
      RECT 67.485 99.935 67.605 100.935 ;
      RECT 67.485 182.29 67.605 183.29 ;
      RECT 67.485 264.645 67.605 265.645 ;
      RECT 67.48 62.39 67.6 63.39 ;
      RECT 67.48 144.745 67.6 145.745 ;
      RECT 67.48 227.1 67.6 228.1 ;
      RECT 67.48 309.455 67.6 310.455 ;
      RECT 67.475 24.845 67.595 25.845 ;
      RECT 67.475 107.2 67.595 108.2 ;
      RECT 67.475 189.555 67.595 190.555 ;
      RECT 67.475 271.91 67.595 272.91 ;
      RECT 67.47 69.655 67.59 70.655 ;
      RECT 67.47 152.01 67.59 153.01 ;
      RECT 67.47 234.365 67.59 235.365 ;
      RECT 67.47 316.72 67.59 317.72 ;
      RECT 67.465 32.11 67.585 33.11 ;
      RECT 67.465 114.465 67.585 115.465 ;
      RECT 67.465 196.82 67.585 197.82 ;
      RECT 67.465 279.175 67.585 280.175 ;
      RECT 67.46 76.92 67.58 77.92 ;
      RECT 67.46 159.275 67.58 160.275 ;
      RECT 67.46 241.63 67.58 242.63 ;
      RECT 67.46 323.985 67.58 324.985 ;
      RECT 67.455 39.375 67.575 40.375 ;
      RECT 67.455 121.73 67.575 122.73 ;
      RECT 67.455 204.085 67.575 205.085 ;
      RECT 67.455 286.44 67.575 287.44 ;
      RECT 67.45 1.83 67.57 2.83 ;
      RECT 67.45 84.185 67.57 85.185 ;
      RECT 67.45 166.54 67.57 167.54 ;
      RECT 67.45 248.895 67.57 249.895 ;
      RECT 67.45 331.25 67.57 332.25 ;
      RECT 67.445 46.64 67.565 47.64 ;
      RECT 67.445 128.995 67.565 129.995 ;
      RECT 67.445 211.35 67.565 212.35 ;
      RECT 67.445 293.705 67.565 294.705 ;
      RECT 67.44 9.095 67.56 10.095 ;
      RECT 67.44 91.45 67.56 92.45 ;
      RECT 67.44 173.805 67.56 174.805 ;
      RECT 67.44 256.16 67.56 257.16 ;
      RECT 67.44 338.515 67.56 339.515 ;
      RECT 67.435 53.905 67.555 54.905 ;
      RECT 67.435 136.26 67.555 137.26 ;
      RECT 67.435 218.615 67.555 219.615 ;
      RECT 67.435 300.97 67.555 301.97 ;
      RECT 67.43 16.36 67.55 17.36 ;
      RECT 67.43 98.715 67.55 99.715 ;
      RECT 67.43 181.07 67.55 182.07 ;
      RECT 67.43 263.425 67.55 264.425 ;
      RECT 67.425 61.17 67.545 62.17 ;
      RECT 67.425 143.525 67.545 144.525 ;
      RECT 67.425 225.88 67.545 226.88 ;
      RECT 67.425 308.235 67.545 309.235 ;
      RECT 67.42 23.625 67.54 24.625 ;
      RECT 67.42 105.98 67.54 106.98 ;
      RECT 67.42 188.335 67.54 189.335 ;
      RECT 67.42 270.69 67.54 271.69 ;
      RECT 67.415 68.435 67.535 69.435 ;
      RECT 67.415 150.79 67.535 151.79 ;
      RECT 67.415 233.145 67.535 234.145 ;
      RECT 67.415 315.5 67.535 316.5 ;
      RECT 67.41 30.89 67.53 31.89 ;
      RECT 67.41 113.245 67.53 114.245 ;
      RECT 67.41 195.6 67.53 196.6 ;
      RECT 67.41 277.955 67.53 278.955 ;
      RECT 67.405 75.7 67.525 76.7 ;
      RECT 67.405 158.055 67.525 159.055 ;
      RECT 67.405 240.41 67.525 241.41 ;
      RECT 67.405 322.765 67.525 323.765 ;
      RECT 67.4 38.155 67.52 39.155 ;
      RECT 67.17 46.195 67.52 46.265 ;
      RECT 67.17 46.335 67.52 46.405 ;
      RECT 67.17 53.46 67.52 53.53 ;
      RECT 67.17 53.6 67.52 53.67 ;
      RECT 67.4 120.51 67.52 121.51 ;
      RECT 67.17 128.55 67.52 128.62 ;
      RECT 67.17 128.69 67.52 128.76 ;
      RECT 67.17 135.815 67.52 135.885 ;
      RECT 67.17 135.955 67.52 136.025 ;
      RECT 67.4 202.865 67.52 203.865 ;
      RECT 67.17 210.905 67.52 210.975 ;
      RECT 67.17 211.045 67.52 211.115 ;
      RECT 67.17 218.17 67.52 218.24 ;
      RECT 67.17 218.31 67.52 218.38 ;
      RECT 67.4 285.22 67.52 286.22 ;
      RECT 67.17 293.26 67.52 293.33 ;
      RECT 67.17 293.4 67.52 293.47 ;
      RECT 67.17 300.525 67.52 300.595 ;
      RECT 67.17 300.665 67.52 300.735 ;
      RECT 67.395 0.61 67.515 1.61 ;
      RECT 67.395 7.905 67.515 8.405 ;
      RECT 67.395 15.17 67.515 15.67 ;
      RECT 67.395 45.45 67.515 45.95 ;
      RECT 67.395 52.715 67.515 53.215 ;
      RECT 67.395 59.98 67.515 60.48 ;
      RECT 67.395 82.965 67.515 83.965 ;
      RECT 67.395 90.26 67.515 90.76 ;
      RECT 67.395 97.525 67.515 98.025 ;
      RECT 67.395 127.805 67.515 128.305 ;
      RECT 67.395 135.07 67.515 135.57 ;
      RECT 67.395 142.335 67.515 142.835 ;
      RECT 67.395 165.32 67.515 166.32 ;
      RECT 67.395 172.615 67.515 173.115 ;
      RECT 67.395 179.88 67.515 180.38 ;
      RECT 67.395 210.16 67.515 210.66 ;
      RECT 67.395 217.425 67.515 217.925 ;
      RECT 67.395 224.69 67.515 225.19 ;
      RECT 67.395 247.675 67.515 248.675 ;
      RECT 67.395 254.97 67.515 255.47 ;
      RECT 67.395 262.235 67.515 262.735 ;
      RECT 67.395 292.515 67.515 293.015 ;
      RECT 67.395 299.78 67.515 300.28 ;
      RECT 67.395 307.045 67.515 307.545 ;
      RECT 67.395 330.03 67.515 331.03 ;
      RECT 67.395 337.325 67.515 337.825 ;
      RECT 67.395 344.745 67.515 345.245 ;
      RECT 67.31 5.555 67.38 5.905 ;
      RECT 67.31 6.005 67.38 6.355 ;
      RECT 67.31 6.455 67.38 6.805 ;
      RECT 67.31 6.905 67.38 7.255 ;
      RECT 67.31 7.355 67.38 7.705 ;
      RECT 67.31 12.755 67.38 13.105 ;
      RECT 67.31 13.205 67.38 13.555 ;
      RECT 67.31 13.655 67.38 14.005 ;
      RECT 67.31 14.105 67.38 14.455 ;
      RECT 67.31 14.555 67.38 14.905 ;
      RECT 67.31 20.405 67.38 20.755 ;
      RECT 67.31 20.855 67.38 21.205 ;
      RECT 67.31 21.305 67.38 21.655 ;
      RECT 67.31 21.755 67.38 22.105 ;
      RECT 67.31 22.205 67.38 22.555 ;
      RECT 67.31 22.655 67.38 23.005 ;
      RECT 67.31 27.605 67.38 27.955 ;
      RECT 67.31 28.055 67.38 28.405 ;
      RECT 67.31 28.505 67.38 28.855 ;
      RECT 67.31 28.955 67.38 29.305 ;
      RECT 67.31 29.405 67.38 29.755 ;
      RECT 67.31 29.855 67.38 30.205 ;
      RECT 67.31 30.305 67.38 30.655 ;
      RECT 67.31 36.155 67.38 36.505 ;
      RECT 67.31 36.605 67.38 36.955 ;
      RECT 67.31 37.055 67.38 37.405 ;
      RECT 67.31 37.505 67.38 37.855 ;
      RECT 67.31 43.355 67.38 43.705 ;
      RECT 67.31 43.805 67.38 44.155 ;
      RECT 67.31 44.255 67.38 44.605 ;
      RECT 67.31 44.705 67.38 45.055 ;
      RECT 67.31 50.555 67.38 50.905 ;
      RECT 67.31 51.005 67.38 51.355 ;
      RECT 67.31 51.455 67.38 51.805 ;
      RECT 67.31 51.905 67.38 52.255 ;
      RECT 67.31 57.755 67.38 58.105 ;
      RECT 67.31 58.205 67.38 58.555 ;
      RECT 67.31 58.655 67.38 59.005 ;
      RECT 67.31 59.105 67.38 59.455 ;
      RECT 67.31 64.955 67.38 65.305 ;
      RECT 67.31 65.405 67.38 65.755 ;
      RECT 67.31 65.855 67.38 66.205 ;
      RECT 67.31 66.305 67.38 66.655 ;
      RECT 67.31 66.755 67.38 67.105 ;
      RECT 67.31 67.205 67.38 67.555 ;
      RECT 67.31 67.655 67.38 68.005 ;
      RECT 67.31 72.155 67.38 72.505 ;
      RECT 67.31 72.605 67.38 72.955 ;
      RECT 67.31 73.055 67.38 73.405 ;
      RECT 67.31 73.505 67.38 73.855 ;
      RECT 67.31 73.955 67.38 74.305 ;
      RECT 67.31 74.405 67.38 74.755 ;
      RECT 67.31 74.855 67.38 75.205 ;
      RECT 67.31 80.705 67.38 81.055 ;
      RECT 67.31 81.155 67.38 81.505 ;
      RECT 67.31 81.605 67.38 81.955 ;
      RECT 67.31 82.055 67.38 82.405 ;
      RECT 67.31 87.905 67.38 88.255 ;
      RECT 67.31 88.355 67.38 88.705 ;
      RECT 67.31 88.805 67.38 89.155 ;
      RECT 67.31 89.255 67.38 89.605 ;
      RECT 67.31 89.705 67.38 90.055 ;
      RECT 67.31 95.105 67.38 95.455 ;
      RECT 67.31 95.555 67.38 95.905 ;
      RECT 67.31 96.005 67.38 96.355 ;
      RECT 67.31 96.455 67.38 96.805 ;
      RECT 67.31 96.905 67.38 97.255 ;
      RECT 67.31 102.755 67.38 103.105 ;
      RECT 67.31 103.205 67.38 103.555 ;
      RECT 67.31 103.655 67.38 104.005 ;
      RECT 67.31 104.105 67.38 104.455 ;
      RECT 67.31 104.555 67.38 104.905 ;
      RECT 67.31 105.005 67.38 105.355 ;
      RECT 67.31 109.955 67.38 110.305 ;
      RECT 67.31 110.405 67.38 110.755 ;
      RECT 67.31 110.855 67.38 111.205 ;
      RECT 67.31 111.305 67.38 111.655 ;
      RECT 67.31 111.755 67.38 112.105 ;
      RECT 67.31 112.205 67.38 112.555 ;
      RECT 67.31 112.655 67.38 113.005 ;
      RECT 67.31 118.505 67.38 118.855 ;
      RECT 67.31 118.955 67.38 119.305 ;
      RECT 67.31 119.405 67.38 119.755 ;
      RECT 67.31 119.855 67.38 120.205 ;
      RECT 67.31 125.705 67.38 126.055 ;
      RECT 67.31 126.155 67.38 126.505 ;
      RECT 67.31 126.605 67.38 126.955 ;
      RECT 67.31 127.055 67.38 127.405 ;
      RECT 67.31 132.905 67.38 133.255 ;
      RECT 67.31 133.355 67.38 133.705 ;
      RECT 67.31 133.805 67.38 134.155 ;
      RECT 67.31 134.255 67.38 134.605 ;
      RECT 67.31 140.105 67.38 140.455 ;
      RECT 67.31 140.555 67.38 140.905 ;
      RECT 67.31 141.005 67.38 141.355 ;
      RECT 67.31 141.455 67.38 141.805 ;
      RECT 67.31 147.305 67.38 147.655 ;
      RECT 67.31 147.755 67.38 148.105 ;
      RECT 67.31 148.205 67.38 148.555 ;
      RECT 67.31 148.655 67.38 149.005 ;
      RECT 67.31 149.105 67.38 149.455 ;
      RECT 67.31 149.555 67.38 149.905 ;
      RECT 67.31 150.005 67.38 150.355 ;
      RECT 67.31 154.505 67.38 154.855 ;
      RECT 67.31 154.955 67.38 155.305 ;
      RECT 67.31 155.405 67.38 155.755 ;
      RECT 67.31 155.855 67.38 156.205 ;
      RECT 67.31 156.305 67.38 156.655 ;
      RECT 67.31 156.755 67.38 157.105 ;
      RECT 67.31 157.205 67.38 157.555 ;
      RECT 67.31 163.055 67.38 163.405 ;
      RECT 67.31 163.505 67.38 163.855 ;
      RECT 67.31 163.955 67.38 164.305 ;
      RECT 67.31 164.405 67.38 164.755 ;
      RECT 67.31 170.255 67.38 170.605 ;
      RECT 67.31 170.705 67.38 171.055 ;
      RECT 67.31 171.155 67.38 171.505 ;
      RECT 67.31 171.605 67.38 171.955 ;
      RECT 67.31 172.055 67.38 172.405 ;
      RECT 67.31 177.455 67.38 177.805 ;
      RECT 67.31 177.905 67.38 178.255 ;
      RECT 67.31 178.355 67.38 178.705 ;
      RECT 67.31 178.805 67.38 179.155 ;
      RECT 67.31 179.255 67.38 179.605 ;
      RECT 67.31 185.105 67.38 185.455 ;
      RECT 67.31 185.555 67.38 185.905 ;
      RECT 67.31 186.005 67.38 186.355 ;
      RECT 67.31 186.455 67.38 186.805 ;
      RECT 67.31 186.905 67.38 187.255 ;
      RECT 67.31 187.355 67.38 187.705 ;
      RECT 67.31 192.305 67.38 192.655 ;
      RECT 67.31 192.755 67.38 193.105 ;
      RECT 67.31 193.205 67.38 193.555 ;
      RECT 67.31 193.655 67.38 194.005 ;
      RECT 67.31 194.105 67.38 194.455 ;
      RECT 67.31 194.555 67.38 194.905 ;
      RECT 67.31 195.005 67.38 195.355 ;
      RECT 67.31 200.855 67.38 201.205 ;
      RECT 67.31 201.305 67.38 201.655 ;
      RECT 67.31 201.755 67.38 202.105 ;
      RECT 67.31 202.205 67.38 202.555 ;
      RECT 67.31 208.055 67.38 208.405 ;
      RECT 67.31 208.505 67.38 208.855 ;
      RECT 67.31 208.955 67.38 209.305 ;
      RECT 67.31 209.405 67.38 209.755 ;
      RECT 67.31 215.255 67.38 215.605 ;
      RECT 67.31 215.705 67.38 216.055 ;
      RECT 67.31 216.155 67.38 216.505 ;
      RECT 67.31 216.605 67.38 216.955 ;
      RECT 67.31 222.455 67.38 222.805 ;
      RECT 67.31 222.905 67.38 223.255 ;
      RECT 67.31 223.355 67.38 223.705 ;
      RECT 67.31 223.805 67.38 224.155 ;
      RECT 67.31 229.655 67.38 230.005 ;
      RECT 67.31 230.105 67.38 230.455 ;
      RECT 67.31 230.555 67.38 230.905 ;
      RECT 67.31 231.005 67.38 231.355 ;
      RECT 67.31 231.455 67.38 231.805 ;
      RECT 67.31 231.905 67.38 232.255 ;
      RECT 67.31 232.355 67.38 232.705 ;
      RECT 67.31 236.855 67.38 237.205 ;
      RECT 67.31 237.305 67.38 237.655 ;
      RECT 67.31 237.755 67.38 238.105 ;
      RECT 67.31 238.205 67.38 238.555 ;
      RECT 67.31 238.655 67.38 239.005 ;
      RECT 67.31 239.105 67.38 239.455 ;
      RECT 67.31 239.555 67.38 239.905 ;
      RECT 67.31 245.405 67.38 245.755 ;
      RECT 67.31 245.855 67.38 246.205 ;
      RECT 67.31 246.305 67.38 246.655 ;
      RECT 67.31 246.755 67.38 247.105 ;
      RECT 67.31 252.605 67.38 252.955 ;
      RECT 67.31 253.055 67.38 253.405 ;
      RECT 67.31 253.505 67.38 253.855 ;
      RECT 67.31 253.955 67.38 254.305 ;
      RECT 67.31 254.405 67.38 254.755 ;
      RECT 67.31 259.805 67.38 260.155 ;
      RECT 67.31 260.255 67.38 260.605 ;
      RECT 67.31 260.705 67.38 261.055 ;
      RECT 67.31 261.155 67.38 261.505 ;
      RECT 67.31 261.605 67.38 261.955 ;
      RECT 67.31 267.455 67.38 267.805 ;
      RECT 67.31 267.905 67.38 268.255 ;
      RECT 67.31 268.355 67.38 268.705 ;
      RECT 67.31 268.805 67.38 269.155 ;
      RECT 67.31 269.255 67.38 269.605 ;
      RECT 67.31 269.705 67.38 270.055 ;
      RECT 67.31 274.655 67.38 275.005 ;
      RECT 67.31 275.105 67.38 275.455 ;
      RECT 67.31 275.555 67.38 275.905 ;
      RECT 67.31 276.005 67.38 276.355 ;
      RECT 67.31 276.455 67.38 276.805 ;
      RECT 67.31 276.905 67.38 277.255 ;
      RECT 67.31 277.355 67.38 277.705 ;
      RECT 67.31 283.205 67.38 283.555 ;
      RECT 67.31 283.655 67.38 284.005 ;
      RECT 67.31 284.105 67.38 284.455 ;
      RECT 67.31 284.555 67.38 284.905 ;
      RECT 67.31 290.405 67.38 290.755 ;
      RECT 67.31 290.855 67.38 291.205 ;
      RECT 67.31 291.305 67.38 291.655 ;
      RECT 67.31 291.755 67.38 292.105 ;
      RECT 67.31 297.605 67.38 297.955 ;
      RECT 67.31 298.055 67.38 298.405 ;
      RECT 67.31 298.505 67.38 298.855 ;
      RECT 67.31 298.955 67.38 299.305 ;
      RECT 67.31 304.805 67.38 305.155 ;
      RECT 67.31 305.255 67.38 305.605 ;
      RECT 67.31 305.705 67.38 306.055 ;
      RECT 67.31 306.155 67.38 306.505 ;
      RECT 67.31 312.005 67.38 312.355 ;
      RECT 67.31 312.455 67.38 312.805 ;
      RECT 67.31 312.905 67.38 313.255 ;
      RECT 67.31 313.355 67.38 313.705 ;
      RECT 67.31 313.805 67.38 314.155 ;
      RECT 67.31 314.255 67.38 314.605 ;
      RECT 67.31 314.705 67.38 315.055 ;
      RECT 67.31 319.205 67.38 319.555 ;
      RECT 67.31 319.655 67.38 320.005 ;
      RECT 67.31 320.105 67.38 320.455 ;
      RECT 67.31 320.555 67.38 320.905 ;
      RECT 67.31 321.005 67.38 321.355 ;
      RECT 67.31 321.455 67.38 321.805 ;
      RECT 67.31 321.905 67.38 322.255 ;
      RECT 67.31 327.755 67.38 328.105 ;
      RECT 67.31 328.205 67.38 328.555 ;
      RECT 67.31 328.655 67.38 329.005 ;
      RECT 67.31 329.105 67.38 329.455 ;
      RECT 67.31 334.955 67.38 335.305 ;
      RECT 67.31 335.405 67.38 335.755 ;
      RECT 67.31 335.855 67.38 336.205 ;
      RECT 67.31 336.305 67.38 336.655 ;
      RECT 67.31 336.755 67.38 337.105 ;
      RECT 67.31 342.155 67.38 342.505 ;
      RECT 67.31 342.605 67.38 342.955 ;
      RECT 67.31 343.055 67.38 343.405 ;
      RECT 67.31 343.505 67.38 343.855 ;
      RECT 67.31 343.955 67.38 344.305 ;
      RECT 67.17 1.955 67.24 2.305 ;
      RECT 67.17 2.405 67.24 2.755 ;
      RECT 67.17 2.855 67.24 3.205 ;
      RECT 67.17 3.305 67.24 3.655 ;
      RECT 67.17 3.755 67.24 4.105 ;
      RECT 67.17 4.205 67.24 4.555 ;
      RECT 67.17 4.655 67.24 5.005 ;
      RECT 67.17 5.105 67.24 5.455 ;
      RECT 67.17 5.555 67.24 5.905 ;
      RECT 67.17 6.005 67.24 6.355 ;
      RECT 67.17 6.455 67.24 6.805 ;
      RECT 67.17 6.905 67.24 7.255 ;
      RECT 67.17 7.355 67.24 7.705 ;
      RECT 67.17 8.705 67.24 9.055 ;
      RECT 67.17 9.155 67.24 9.505 ;
      RECT 67.17 9.605 67.24 9.955 ;
      RECT 67.17 10.055 67.24 10.405 ;
      RECT 67.17 10.505 67.24 10.855 ;
      RECT 67.17 10.955 67.24 11.305 ;
      RECT 67.17 11.405 67.24 11.755 ;
      RECT 67.17 11.855 67.24 12.205 ;
      RECT 67.17 12.305 67.24 12.655 ;
      RECT 67.17 12.755 67.24 13.105 ;
      RECT 67.17 13.205 67.24 13.555 ;
      RECT 67.17 13.655 67.24 14.005 ;
      RECT 67.17 14.105 67.24 14.455 ;
      RECT 67.17 14.555 67.24 14.905 ;
      RECT 67.17 17.705 67.24 18.055 ;
      RECT 67.17 18.155 67.24 18.505 ;
      RECT 67.17 18.605 67.24 18.955 ;
      RECT 67.17 19.055 67.24 19.405 ;
      RECT 67.17 19.505 67.24 19.855 ;
      RECT 67.17 19.955 67.24 20.305 ;
      RECT 67.17 20.405 67.24 20.755 ;
      RECT 67.17 20.855 67.24 21.205 ;
      RECT 67.17 21.305 67.24 21.655 ;
      RECT 67.17 21.755 67.24 22.105 ;
      RECT 67.17 22.205 67.24 22.555 ;
      RECT 67.17 22.655 67.24 23.005 ;
      RECT 67.17 24.905 67.24 25.255 ;
      RECT 67.17 25.355 67.24 25.705 ;
      RECT 67.17 25.805 67.24 26.155 ;
      RECT 67.17 26.255 67.24 26.605 ;
      RECT 67.17 26.705 67.24 27.055 ;
      RECT 67.17 27.155 67.24 27.505 ;
      RECT 67.17 27.605 67.24 27.955 ;
      RECT 67.17 28.055 67.24 28.405 ;
      RECT 67.17 28.505 67.24 28.855 ;
      RECT 67.17 28.955 67.24 29.305 ;
      RECT 67.17 29.405 67.24 29.755 ;
      RECT 67.17 29.855 67.24 30.205 ;
      RECT 67.17 30.305 67.24 30.655 ;
      RECT 67.17 32.105 67.24 32.455 ;
      RECT 67.17 32.555 67.24 32.905 ;
      RECT 67.17 33.005 67.24 33.355 ;
      RECT 67.17 33.455 67.24 33.805 ;
      RECT 67.17 33.905 67.24 34.255 ;
      RECT 67.17 34.355 67.24 34.705 ;
      RECT 67.17 34.805 67.24 35.155 ;
      RECT 67.17 35.255 67.24 35.605 ;
      RECT 67.17 35.705 67.24 36.055 ;
      RECT 67.17 36.155 67.24 36.505 ;
      RECT 67.17 36.605 67.24 36.955 ;
      RECT 67.17 37.055 67.24 37.405 ;
      RECT 67.17 37.505 67.24 37.855 ;
      RECT 67.17 39.755 67.24 40.105 ;
      RECT 67.17 40.205 67.24 40.555 ;
      RECT 67.17 40.655 67.24 41.005 ;
      RECT 67.17 41.105 67.24 41.455 ;
      RECT 67.17 41.555 67.24 41.905 ;
      RECT 67.17 42.005 67.24 42.355 ;
      RECT 67.17 42.455 67.24 42.805 ;
      RECT 67.17 42.905 67.24 43.255 ;
      RECT 67.17 43.355 67.24 43.705 ;
      RECT 67.17 43.805 67.24 44.155 ;
      RECT 67.17 44.255 67.24 44.605 ;
      RECT 67.17 44.705 67.24 45.055 ;
      RECT 67.17 46.505 67.24 46.855 ;
      RECT 67.17 46.955 67.24 47.305 ;
      RECT 67.17 47.405 67.24 47.755 ;
      RECT 67.17 47.855 67.24 48.205 ;
      RECT 67.17 48.305 67.24 48.655 ;
      RECT 67.17 48.755 67.24 49.105 ;
      RECT 67.17 49.205 67.24 49.555 ;
      RECT 67.17 49.655 67.24 50.005 ;
      RECT 67.17 50.105 67.24 50.455 ;
      RECT 67.17 50.555 67.24 50.905 ;
      RECT 67.17 51.005 67.24 51.355 ;
      RECT 67.17 51.455 67.24 51.805 ;
      RECT 67.17 51.905 67.24 52.255 ;
      RECT 67.17 55.505 67.24 55.855 ;
      RECT 67.17 55.955 67.24 56.305 ;
      RECT 67.17 56.405 67.24 56.755 ;
      RECT 67.17 56.855 67.24 57.205 ;
      RECT 67.17 57.305 67.24 57.655 ;
      RECT 67.17 57.755 67.24 58.105 ;
      RECT 67.17 58.205 67.24 58.555 ;
      RECT 67.17 58.655 67.24 59.005 ;
      RECT 67.17 59.105 67.24 59.455 ;
      RECT 67.17 62.705 67.24 63.055 ;
      RECT 67.17 63.155 67.24 63.505 ;
      RECT 67.17 63.605 67.24 63.955 ;
      RECT 67.17 64.055 67.24 64.405 ;
      RECT 67.17 64.505 67.24 64.855 ;
      RECT 67.17 64.955 67.24 65.305 ;
      RECT 67.17 65.405 67.24 65.755 ;
      RECT 67.17 65.855 67.24 66.205 ;
      RECT 67.17 66.305 67.24 66.655 ;
      RECT 67.17 66.755 67.24 67.105 ;
      RECT 67.17 67.205 67.24 67.555 ;
      RECT 67.17 67.655 67.24 68.005 ;
      RECT 67.17 69.905 67.24 70.255 ;
      RECT 67.17 70.355 67.24 70.705 ;
      RECT 67.17 70.805 67.24 71.155 ;
      RECT 67.17 71.255 67.24 71.605 ;
      RECT 67.17 71.705 67.24 72.055 ;
      RECT 67.17 72.155 67.24 72.505 ;
      RECT 67.17 72.605 67.24 72.955 ;
      RECT 67.17 73.055 67.24 73.405 ;
      RECT 67.17 73.505 67.24 73.855 ;
      RECT 67.17 73.955 67.24 74.305 ;
      RECT 67.17 74.405 67.24 74.755 ;
      RECT 67.17 74.855 67.24 75.205 ;
      RECT 67.17 77.105 67.24 77.455 ;
      RECT 67.17 77.555 67.24 77.905 ;
      RECT 67.17 78.005 67.24 78.355 ;
      RECT 67.17 78.455 67.24 78.805 ;
      RECT 67.17 78.905 67.24 79.255 ;
      RECT 67.17 79.355 67.24 79.705 ;
      RECT 67.17 79.805 67.24 80.155 ;
      RECT 67.17 80.255 67.24 80.605 ;
      RECT 67.17 80.705 67.24 81.055 ;
      RECT 67.17 81.155 67.24 81.505 ;
      RECT 67.17 81.605 67.24 81.955 ;
      RECT 67.17 82.055 67.24 82.405 ;
      RECT 67.17 84.305 67.24 84.655 ;
      RECT 67.17 84.755 67.24 85.105 ;
      RECT 67.17 85.205 67.24 85.555 ;
      RECT 67.17 85.655 67.24 86.005 ;
      RECT 67.17 86.105 67.24 86.455 ;
      RECT 67.17 86.555 67.24 86.905 ;
      RECT 67.17 87.005 67.24 87.355 ;
      RECT 67.17 87.455 67.24 87.805 ;
      RECT 67.17 87.905 67.24 88.255 ;
      RECT 67.17 88.355 67.24 88.705 ;
      RECT 67.17 88.805 67.24 89.155 ;
      RECT 67.17 89.255 67.24 89.605 ;
      RECT 67.17 89.705 67.24 90.055 ;
      RECT 67.17 91.055 67.24 91.405 ;
      RECT 67.17 91.505 67.24 91.855 ;
      RECT 67.17 91.955 67.24 92.305 ;
      RECT 67.17 92.405 67.24 92.755 ;
      RECT 67.17 92.855 67.24 93.205 ;
      RECT 67.17 93.305 67.24 93.655 ;
      RECT 67.17 93.755 67.24 94.105 ;
      RECT 67.17 94.205 67.24 94.555 ;
      RECT 67.17 94.655 67.24 95.005 ;
      RECT 67.17 95.105 67.24 95.455 ;
      RECT 67.17 95.555 67.24 95.905 ;
      RECT 67.17 96.005 67.24 96.355 ;
      RECT 67.17 96.455 67.24 96.805 ;
      RECT 67.17 96.905 67.24 97.255 ;
      RECT 67.17 100.055 67.24 100.405 ;
      RECT 67.17 100.505 67.24 100.855 ;
      RECT 67.17 100.955 67.24 101.305 ;
      RECT 67.17 101.405 67.24 101.755 ;
      RECT 67.17 101.855 67.24 102.205 ;
      RECT 67.17 102.305 67.24 102.655 ;
      RECT 67.17 102.755 67.24 103.105 ;
      RECT 67.17 103.205 67.24 103.555 ;
      RECT 67.17 103.655 67.24 104.005 ;
      RECT 67.17 104.105 67.24 104.455 ;
      RECT 67.17 104.555 67.24 104.905 ;
      RECT 67.17 105.005 67.24 105.355 ;
      RECT 67.17 107.255 67.24 107.605 ;
      RECT 67.17 107.705 67.24 108.055 ;
      RECT 67.17 108.155 67.24 108.505 ;
      RECT 67.17 108.605 67.24 108.955 ;
      RECT 67.17 109.055 67.24 109.405 ;
      RECT 67.17 109.505 67.24 109.855 ;
      RECT 67.17 109.955 67.24 110.305 ;
      RECT 67.17 110.405 67.24 110.755 ;
      RECT 67.17 110.855 67.24 111.205 ;
      RECT 67.17 111.305 67.24 111.655 ;
      RECT 67.17 111.755 67.24 112.105 ;
      RECT 67.17 112.205 67.24 112.555 ;
      RECT 67.17 112.655 67.24 113.005 ;
      RECT 67.17 114.455 67.24 114.805 ;
      RECT 67.17 114.905 67.24 115.255 ;
      RECT 67.17 115.355 67.24 115.705 ;
      RECT 67.17 115.805 67.24 116.155 ;
      RECT 67.17 116.255 67.24 116.605 ;
      RECT 67.17 116.705 67.24 117.055 ;
      RECT 67.17 117.155 67.24 117.505 ;
      RECT 67.17 117.605 67.24 117.955 ;
      RECT 67.17 118.055 67.24 118.405 ;
      RECT 67.17 118.505 67.24 118.855 ;
      RECT 67.17 118.955 67.24 119.305 ;
      RECT 67.17 119.405 67.24 119.755 ;
      RECT 67.17 119.855 67.24 120.205 ;
      RECT 67.17 122.105 67.24 122.455 ;
      RECT 67.17 122.555 67.24 122.905 ;
      RECT 67.17 123.005 67.24 123.355 ;
      RECT 67.17 123.455 67.24 123.805 ;
      RECT 67.17 123.905 67.24 124.255 ;
      RECT 67.17 124.355 67.24 124.705 ;
      RECT 67.17 124.805 67.24 125.155 ;
      RECT 67.17 125.255 67.24 125.605 ;
      RECT 67.17 125.705 67.24 126.055 ;
      RECT 67.17 126.155 67.24 126.505 ;
      RECT 67.17 126.605 67.24 126.955 ;
      RECT 67.17 127.055 67.24 127.405 ;
      RECT 67.17 128.855 67.24 129.205 ;
      RECT 67.17 129.305 67.24 129.655 ;
      RECT 67.17 129.755 67.24 130.105 ;
      RECT 67.17 130.205 67.24 130.555 ;
      RECT 67.17 130.655 67.24 131.005 ;
      RECT 67.17 131.105 67.24 131.455 ;
      RECT 67.17 131.555 67.24 131.905 ;
      RECT 67.17 132.005 67.24 132.355 ;
      RECT 67.17 132.455 67.24 132.805 ;
      RECT 67.17 132.905 67.24 133.255 ;
      RECT 67.17 133.355 67.24 133.705 ;
      RECT 67.17 133.805 67.24 134.155 ;
      RECT 67.17 134.255 67.24 134.605 ;
      RECT 67.17 137.855 67.24 138.205 ;
      RECT 67.17 138.305 67.24 138.655 ;
      RECT 67.17 138.755 67.24 139.105 ;
      RECT 67.17 139.205 67.24 139.555 ;
      RECT 67.17 139.655 67.24 140.005 ;
      RECT 67.17 140.105 67.24 140.455 ;
      RECT 67.17 140.555 67.24 140.905 ;
      RECT 67.17 141.005 67.24 141.355 ;
      RECT 67.17 141.455 67.24 141.805 ;
      RECT 67.17 145.055 67.24 145.405 ;
      RECT 67.17 145.505 67.24 145.855 ;
      RECT 67.17 145.955 67.24 146.305 ;
      RECT 67.17 146.405 67.24 146.755 ;
      RECT 67.17 146.855 67.24 147.205 ;
      RECT 67.17 147.305 67.24 147.655 ;
      RECT 67.17 147.755 67.24 148.105 ;
      RECT 67.17 148.205 67.24 148.555 ;
      RECT 67.17 148.655 67.24 149.005 ;
      RECT 67.17 149.105 67.24 149.455 ;
      RECT 67.17 149.555 67.24 149.905 ;
      RECT 67.17 150.005 67.24 150.355 ;
      RECT 67.17 152.255 67.24 152.605 ;
      RECT 67.17 152.705 67.24 153.055 ;
      RECT 67.17 153.155 67.24 153.505 ;
      RECT 67.17 153.605 67.24 153.955 ;
      RECT 67.17 154.055 67.24 154.405 ;
      RECT 67.17 154.505 67.24 154.855 ;
      RECT 67.17 154.955 67.24 155.305 ;
      RECT 67.17 155.405 67.24 155.755 ;
      RECT 67.17 155.855 67.24 156.205 ;
      RECT 67.17 156.305 67.24 156.655 ;
      RECT 67.17 156.755 67.24 157.105 ;
      RECT 67.17 157.205 67.24 157.555 ;
      RECT 67.17 159.455 67.24 159.805 ;
      RECT 67.17 159.905 67.24 160.255 ;
      RECT 67.17 160.355 67.24 160.705 ;
      RECT 67.17 160.805 67.24 161.155 ;
      RECT 67.17 161.255 67.24 161.605 ;
      RECT 67.17 161.705 67.24 162.055 ;
      RECT 67.17 162.155 67.24 162.505 ;
      RECT 67.17 162.605 67.24 162.955 ;
      RECT 67.17 163.055 67.24 163.405 ;
      RECT 67.17 163.505 67.24 163.855 ;
      RECT 67.17 163.955 67.24 164.305 ;
      RECT 67.17 164.405 67.24 164.755 ;
      RECT 67.17 166.655 67.24 167.005 ;
      RECT 67.17 167.105 67.24 167.455 ;
      RECT 67.17 167.555 67.24 167.905 ;
      RECT 67.17 168.005 67.24 168.355 ;
      RECT 67.17 168.455 67.24 168.805 ;
      RECT 67.17 168.905 67.24 169.255 ;
      RECT 67.17 169.355 67.24 169.705 ;
      RECT 67.17 169.805 67.24 170.155 ;
      RECT 67.17 170.255 67.24 170.605 ;
      RECT 67.17 170.705 67.24 171.055 ;
      RECT 67.17 171.155 67.24 171.505 ;
      RECT 67.17 171.605 67.24 171.955 ;
      RECT 67.17 172.055 67.24 172.405 ;
      RECT 67.17 173.405 67.24 173.755 ;
      RECT 67.17 173.855 67.24 174.205 ;
      RECT 67.17 174.305 67.24 174.655 ;
      RECT 67.17 174.755 67.24 175.105 ;
      RECT 67.17 175.205 67.24 175.555 ;
      RECT 67.17 175.655 67.24 176.005 ;
      RECT 67.17 176.105 67.24 176.455 ;
      RECT 67.17 176.555 67.24 176.905 ;
      RECT 67.17 177.005 67.24 177.355 ;
      RECT 67.17 177.455 67.24 177.805 ;
      RECT 67.17 177.905 67.24 178.255 ;
      RECT 67.17 178.355 67.24 178.705 ;
      RECT 67.17 178.805 67.24 179.155 ;
      RECT 67.17 179.255 67.24 179.605 ;
      RECT 67.17 182.405 67.24 182.755 ;
      RECT 67.17 182.855 67.24 183.205 ;
      RECT 67.17 183.305 67.24 183.655 ;
      RECT 67.17 183.755 67.24 184.105 ;
      RECT 67.17 184.205 67.24 184.555 ;
      RECT 67.17 184.655 67.24 185.005 ;
      RECT 67.17 185.105 67.24 185.455 ;
      RECT 67.17 185.555 67.24 185.905 ;
      RECT 67.17 186.005 67.24 186.355 ;
      RECT 67.17 186.455 67.24 186.805 ;
      RECT 67.17 186.905 67.24 187.255 ;
      RECT 67.17 187.355 67.24 187.705 ;
      RECT 67.17 189.605 67.24 189.955 ;
      RECT 67.17 190.055 67.24 190.405 ;
      RECT 67.17 190.505 67.24 190.855 ;
      RECT 67.17 190.955 67.24 191.305 ;
      RECT 67.17 191.405 67.24 191.755 ;
      RECT 67.17 191.855 67.24 192.205 ;
      RECT 67.17 192.305 67.24 192.655 ;
      RECT 67.17 192.755 67.24 193.105 ;
      RECT 67.17 193.205 67.24 193.555 ;
      RECT 67.17 193.655 67.24 194.005 ;
      RECT 67.17 194.105 67.24 194.455 ;
      RECT 67.17 194.555 67.24 194.905 ;
      RECT 67.17 195.005 67.24 195.355 ;
      RECT 67.17 196.805 67.24 197.155 ;
      RECT 67.17 197.255 67.24 197.605 ;
      RECT 67.17 197.705 67.24 198.055 ;
      RECT 67.17 198.155 67.24 198.505 ;
      RECT 67.17 198.605 67.24 198.955 ;
      RECT 67.17 199.055 67.24 199.405 ;
      RECT 67.17 199.505 67.24 199.855 ;
      RECT 67.17 199.955 67.24 200.305 ;
      RECT 67.17 200.405 67.24 200.755 ;
      RECT 67.17 200.855 67.24 201.205 ;
      RECT 67.17 201.305 67.24 201.655 ;
      RECT 67.17 201.755 67.24 202.105 ;
      RECT 67.17 202.205 67.24 202.555 ;
      RECT 67.17 204.455 67.24 204.805 ;
      RECT 67.17 204.905 67.24 205.255 ;
      RECT 67.17 205.355 67.24 205.705 ;
      RECT 67.17 205.805 67.24 206.155 ;
      RECT 67.17 206.255 67.24 206.605 ;
      RECT 67.17 206.705 67.24 207.055 ;
      RECT 67.17 207.155 67.24 207.505 ;
      RECT 67.17 207.605 67.24 207.955 ;
      RECT 67.17 208.055 67.24 208.405 ;
      RECT 67.17 208.505 67.24 208.855 ;
      RECT 67.17 208.955 67.24 209.305 ;
      RECT 67.17 209.405 67.24 209.755 ;
      RECT 67.17 211.205 67.24 211.555 ;
      RECT 67.17 211.655 67.24 212.005 ;
      RECT 67.17 212.105 67.24 212.455 ;
      RECT 67.17 212.555 67.24 212.905 ;
      RECT 67.17 213.005 67.24 213.355 ;
      RECT 67.17 213.455 67.24 213.805 ;
      RECT 67.17 213.905 67.24 214.255 ;
      RECT 67.17 214.355 67.24 214.705 ;
      RECT 67.17 214.805 67.24 215.155 ;
      RECT 67.17 215.255 67.24 215.605 ;
      RECT 67.17 215.705 67.24 216.055 ;
      RECT 67.17 216.155 67.24 216.505 ;
      RECT 67.17 216.605 67.24 216.955 ;
      RECT 67.17 220.205 67.24 220.555 ;
      RECT 67.17 220.655 67.24 221.005 ;
      RECT 67.17 221.105 67.24 221.455 ;
      RECT 67.17 221.555 67.24 221.905 ;
      RECT 67.17 222.005 67.24 222.355 ;
      RECT 67.17 222.455 67.24 222.805 ;
      RECT 67.17 222.905 67.24 223.255 ;
      RECT 67.17 223.355 67.24 223.705 ;
      RECT 67.17 223.805 67.24 224.155 ;
      RECT 67.17 227.405 67.24 227.755 ;
      RECT 67.17 227.855 67.24 228.205 ;
      RECT 67.17 228.305 67.24 228.655 ;
      RECT 67.17 228.755 67.24 229.105 ;
      RECT 67.17 229.205 67.24 229.555 ;
      RECT 67.17 229.655 67.24 230.005 ;
      RECT 67.17 230.105 67.24 230.455 ;
      RECT 67.17 230.555 67.24 230.905 ;
      RECT 67.17 231.005 67.24 231.355 ;
      RECT 67.17 231.455 67.24 231.805 ;
      RECT 67.17 231.905 67.24 232.255 ;
      RECT 67.17 232.355 67.24 232.705 ;
      RECT 67.17 234.605 67.24 234.955 ;
      RECT 67.17 235.055 67.24 235.405 ;
      RECT 67.17 235.505 67.24 235.855 ;
      RECT 67.17 235.955 67.24 236.305 ;
      RECT 67.17 236.405 67.24 236.755 ;
      RECT 67.17 236.855 67.24 237.205 ;
      RECT 67.17 237.305 67.24 237.655 ;
      RECT 67.17 237.755 67.24 238.105 ;
      RECT 67.17 238.205 67.24 238.555 ;
      RECT 67.17 238.655 67.24 239.005 ;
      RECT 67.17 239.105 67.24 239.455 ;
      RECT 67.17 239.555 67.24 239.905 ;
      RECT 67.17 241.805 67.24 242.155 ;
      RECT 67.17 242.255 67.24 242.605 ;
      RECT 67.17 242.705 67.24 243.055 ;
      RECT 67.17 243.155 67.24 243.505 ;
      RECT 67.17 243.605 67.24 243.955 ;
      RECT 67.17 244.055 67.24 244.405 ;
      RECT 67.17 244.505 67.24 244.855 ;
      RECT 67.17 244.955 67.24 245.305 ;
      RECT 67.17 245.405 67.24 245.755 ;
      RECT 67.17 245.855 67.24 246.205 ;
      RECT 67.17 246.305 67.24 246.655 ;
      RECT 67.17 246.755 67.24 247.105 ;
      RECT 67.17 249.005 67.24 249.355 ;
      RECT 67.17 249.455 67.24 249.805 ;
      RECT 67.17 249.905 67.24 250.255 ;
      RECT 67.17 250.355 67.24 250.705 ;
      RECT 67.17 250.805 67.24 251.155 ;
      RECT 67.17 251.255 67.24 251.605 ;
      RECT 67.17 251.705 67.24 252.055 ;
      RECT 67.17 252.155 67.24 252.505 ;
      RECT 67.17 252.605 67.24 252.955 ;
      RECT 67.17 253.055 67.24 253.405 ;
      RECT 67.17 253.505 67.24 253.855 ;
      RECT 67.17 253.955 67.24 254.305 ;
      RECT 67.17 254.405 67.24 254.755 ;
      RECT 67.17 255.755 67.24 256.105 ;
      RECT 67.17 256.205 67.24 256.555 ;
      RECT 67.17 256.655 67.24 257.005 ;
      RECT 67.17 257.105 67.24 257.455 ;
      RECT 67.17 257.555 67.24 257.905 ;
      RECT 67.17 258.005 67.24 258.355 ;
      RECT 67.17 258.455 67.24 258.805 ;
      RECT 67.17 258.905 67.24 259.255 ;
      RECT 67.17 259.355 67.24 259.705 ;
      RECT 67.17 259.805 67.24 260.155 ;
      RECT 67.17 260.255 67.24 260.605 ;
      RECT 67.17 260.705 67.24 261.055 ;
      RECT 67.17 261.155 67.24 261.505 ;
      RECT 67.17 261.605 67.24 261.955 ;
      RECT 67.17 264.755 67.24 265.105 ;
      RECT 67.17 265.205 67.24 265.555 ;
      RECT 67.17 265.655 67.24 266.005 ;
      RECT 67.17 266.105 67.24 266.455 ;
      RECT 67.17 266.555 67.24 266.905 ;
      RECT 67.17 267.005 67.24 267.355 ;
      RECT 67.17 267.455 67.24 267.805 ;
      RECT 67.17 267.905 67.24 268.255 ;
      RECT 67.17 268.355 67.24 268.705 ;
      RECT 67.17 268.805 67.24 269.155 ;
      RECT 67.17 269.255 67.24 269.605 ;
      RECT 67.17 269.705 67.24 270.055 ;
      RECT 67.17 271.955 67.24 272.305 ;
      RECT 67.17 272.405 67.24 272.755 ;
      RECT 67.17 272.855 67.24 273.205 ;
      RECT 67.17 273.305 67.24 273.655 ;
      RECT 67.17 273.755 67.24 274.105 ;
      RECT 67.17 274.205 67.24 274.555 ;
      RECT 67.17 274.655 67.24 275.005 ;
      RECT 67.17 275.105 67.24 275.455 ;
      RECT 67.17 275.555 67.24 275.905 ;
      RECT 67.17 276.005 67.24 276.355 ;
      RECT 67.17 276.455 67.24 276.805 ;
      RECT 67.17 276.905 67.24 277.255 ;
      RECT 67.17 277.355 67.24 277.705 ;
      RECT 67.17 279.155 67.24 279.505 ;
      RECT 67.17 279.605 67.24 279.955 ;
      RECT 67.17 280.055 67.24 280.405 ;
      RECT 67.17 280.505 67.24 280.855 ;
      RECT 67.17 280.955 67.24 281.305 ;
      RECT 67.17 281.405 67.24 281.755 ;
      RECT 67.17 281.855 67.24 282.205 ;
      RECT 67.17 282.305 67.24 282.655 ;
      RECT 67.17 282.755 67.24 283.105 ;
      RECT 67.17 283.205 67.24 283.555 ;
      RECT 67.17 283.655 67.24 284.005 ;
      RECT 67.17 284.105 67.24 284.455 ;
      RECT 67.17 284.555 67.24 284.905 ;
      RECT 67.17 286.805 67.24 287.155 ;
      RECT 67.17 287.255 67.24 287.605 ;
      RECT 67.17 287.705 67.24 288.055 ;
      RECT 67.17 288.155 67.24 288.505 ;
      RECT 67.17 288.605 67.24 288.955 ;
      RECT 67.17 289.055 67.24 289.405 ;
      RECT 67.17 289.505 67.24 289.855 ;
      RECT 67.17 289.955 67.24 290.305 ;
      RECT 67.17 290.405 67.24 290.755 ;
      RECT 67.17 290.855 67.24 291.205 ;
      RECT 67.17 291.305 67.24 291.655 ;
      RECT 67.17 291.755 67.24 292.105 ;
      RECT 67.17 293.555 67.24 293.905 ;
      RECT 67.17 294.005 67.24 294.355 ;
      RECT 67.17 294.455 67.24 294.805 ;
      RECT 67.17 294.905 67.24 295.255 ;
      RECT 67.17 295.355 67.24 295.705 ;
      RECT 67.17 295.805 67.24 296.155 ;
      RECT 67.17 296.255 67.24 296.605 ;
      RECT 67.17 296.705 67.24 297.055 ;
      RECT 67.17 297.155 67.24 297.505 ;
      RECT 67.17 297.605 67.24 297.955 ;
      RECT 67.17 298.055 67.24 298.405 ;
      RECT 67.17 298.505 67.24 298.855 ;
      RECT 67.17 298.955 67.24 299.305 ;
      RECT 67.17 302.555 67.24 302.905 ;
      RECT 67.17 303.005 67.24 303.355 ;
      RECT 67.17 303.455 67.24 303.805 ;
      RECT 67.17 303.905 67.24 304.255 ;
      RECT 67.17 304.355 67.24 304.705 ;
      RECT 67.17 304.805 67.24 305.155 ;
      RECT 67.17 305.255 67.24 305.605 ;
      RECT 67.17 305.705 67.24 306.055 ;
      RECT 67.17 306.155 67.24 306.505 ;
      RECT 67.17 309.755 67.24 310.105 ;
      RECT 67.17 310.205 67.24 310.555 ;
      RECT 67.17 310.655 67.24 311.005 ;
      RECT 67.17 311.105 67.24 311.455 ;
      RECT 67.17 311.555 67.24 311.905 ;
      RECT 67.17 312.005 67.24 312.355 ;
      RECT 67.17 312.455 67.24 312.805 ;
      RECT 67.17 312.905 67.24 313.255 ;
      RECT 67.17 313.355 67.24 313.705 ;
      RECT 67.17 313.805 67.24 314.155 ;
      RECT 67.17 314.255 67.24 314.605 ;
      RECT 67.17 314.705 67.24 315.055 ;
      RECT 67.17 316.955 67.24 317.305 ;
      RECT 67.17 317.405 67.24 317.755 ;
      RECT 67.17 317.855 67.24 318.205 ;
      RECT 67.17 318.305 67.24 318.655 ;
      RECT 67.17 318.755 67.24 319.105 ;
      RECT 67.17 319.205 67.24 319.555 ;
      RECT 67.17 319.655 67.24 320.005 ;
      RECT 67.17 320.105 67.24 320.455 ;
      RECT 67.17 320.555 67.24 320.905 ;
      RECT 67.17 321.005 67.24 321.355 ;
      RECT 67.17 321.455 67.24 321.805 ;
      RECT 67.17 321.905 67.24 322.255 ;
      RECT 67.17 324.155 67.24 324.505 ;
      RECT 67.17 324.605 67.24 324.955 ;
      RECT 67.17 325.055 67.24 325.405 ;
      RECT 67.17 325.505 67.24 325.855 ;
      RECT 67.17 325.955 67.24 326.305 ;
      RECT 67.17 326.405 67.24 326.755 ;
      RECT 67.17 326.855 67.24 327.205 ;
      RECT 67.17 327.305 67.24 327.655 ;
      RECT 67.17 327.755 67.24 328.105 ;
      RECT 67.17 328.205 67.24 328.555 ;
      RECT 67.17 328.655 67.24 329.005 ;
      RECT 67.17 329.105 67.24 329.455 ;
      RECT 67.17 331.355 67.24 331.705 ;
      RECT 67.17 331.805 67.24 332.155 ;
      RECT 67.17 332.255 67.24 332.605 ;
      RECT 67.17 332.705 67.24 333.055 ;
      RECT 67.17 333.155 67.24 333.505 ;
      RECT 67.17 333.605 67.24 333.955 ;
      RECT 67.17 334.055 67.24 334.405 ;
      RECT 67.17 334.505 67.24 334.855 ;
      RECT 67.17 334.955 67.24 335.305 ;
      RECT 67.17 335.405 67.24 335.755 ;
      RECT 67.17 335.855 67.24 336.205 ;
      RECT 67.17 336.305 67.24 336.655 ;
      RECT 67.17 336.755 67.24 337.105 ;
      RECT 67.17 338.105 67.24 338.455 ;
      RECT 67.17 338.555 67.24 338.905 ;
      RECT 67.17 339.005 67.24 339.355 ;
      RECT 67.17 339.455 67.24 339.805 ;
      RECT 67.17 339.905 67.24 340.255 ;
      RECT 67.17 340.355 67.24 340.705 ;
      RECT 67.17 340.805 67.24 341.155 ;
      RECT 67.17 341.255 67.24 341.605 ;
      RECT 67.17 341.705 67.24 342.055 ;
      RECT 67.17 342.155 67.24 342.505 ;
      RECT 67.17 342.605 67.24 342.955 ;
      RECT 67.17 343.055 67.24 343.405 ;
      RECT 67.17 343.505 67.24 343.855 ;
      RECT 67.17 343.955 67.24 344.305 ;
      RECT 24.92 0.605 24.99 0.955 ;
      RECT 24.92 1.055 24.99 1.405 ;
      RECT 24.92 1.505 24.99 1.855 ;
      RECT 24.92 3.305 24.99 3.655 ;
      RECT 24.92 3.755 24.99 4.105 ;
      RECT 24.92 4.205 24.99 4.555 ;
      RECT 24.92 4.655 24.99 5.005 ;
      RECT 24.92 5.105 24.99 5.455 ;
      RECT 24.92 5.555 24.99 5.905 ;
      RECT 24.92 6.005 24.99 6.355 ;
      RECT 24.92 6.455 24.99 6.805 ;
      RECT 24.92 6.905 24.99 7.255 ;
      RECT 24.92 7.355 24.99 7.705 ;
      RECT 24.92 7.805 24.99 8.155 ;
      RECT 24.92 8.255 24.99 8.605 ;
      RECT 24.92 8.705 24.99 9.055 ;
      RECT 24.92 10.955 24.99 11.305 ;
      RECT 24.92 11.405 24.99 11.755 ;
      RECT 24.92 11.855 24.99 12.205 ;
      RECT 24.92 12.305 24.99 12.655 ;
      RECT 24.92 12.755 24.99 13.105 ;
      RECT 24.92 13.205 24.99 13.555 ;
      RECT 24.92 13.655 24.99 14.005 ;
      RECT 24.92 14.105 24.99 14.455 ;
      RECT 24.92 14.555 24.99 14.905 ;
      RECT 24.92 15.005 24.99 15.355 ;
      RECT 24.92 15.455 24.99 15.805 ;
      RECT 24.92 15.905 24.99 16.255 ;
      RECT 24.92 18.605 24.99 18.955 ;
      RECT 24.92 19.055 24.99 19.405 ;
      RECT 24.92 19.505 24.99 19.855 ;
      RECT 24.92 19.955 24.99 20.305 ;
      RECT 24.92 20.405 24.99 20.755 ;
      RECT 24.92 20.855 24.99 21.205 ;
      RECT 24.92 21.305 24.99 21.655 ;
      RECT 24.92 21.755 24.99 22.105 ;
      RECT 24.92 22.205 24.99 22.555 ;
      RECT 24.92 22.655 24.99 23.005 ;
      RECT 24.92 23.105 24.99 23.455 ;
      RECT 24.92 25.805 24.99 26.155 ;
      RECT 24.92 26.255 24.99 26.605 ;
      RECT 24.92 26.705 24.99 27.055 ;
      RECT 24.92 27.155 24.99 27.505 ;
      RECT 24.92 27.605 24.99 27.955 ;
      RECT 24.92 28.055 24.99 28.405 ;
      RECT 24.92 28.505 24.99 28.855 ;
      RECT 24.92 28.955 24.99 29.305 ;
      RECT 24.92 29.405 24.99 29.755 ;
      RECT 24.92 29.855 24.99 30.205 ;
      RECT 24.92 30.305 24.99 30.655 ;
      RECT 24.92 30.755 24.99 31.105 ;
      RECT 24.92 31.205 24.99 31.555 ;
      RECT 24.92 31.655 24.99 32.005 ;
      RECT 24.92 33.905 24.99 34.255 ;
      RECT 24.92 34.355 24.99 34.705 ;
      RECT 24.92 34.805 24.99 35.155 ;
      RECT 24.92 35.255 24.99 35.605 ;
      RECT 24.92 35.705 24.99 36.055 ;
      RECT 24.92 36.155 24.99 36.505 ;
      RECT 24.92 36.605 24.99 36.955 ;
      RECT 24.92 37.055 24.99 37.405 ;
      RECT 24.92 37.505 24.99 37.855 ;
      RECT 24.92 37.955 24.99 38.305 ;
      RECT 24.92 38.405 24.99 38.755 ;
      RECT 24.92 38.855 24.99 39.205 ;
      RECT 24.92 41.105 24.99 41.455 ;
      RECT 24.92 41.555 24.99 41.905 ;
      RECT 24.92 42.005 24.99 42.355 ;
      RECT 24.92 42.455 24.99 42.805 ;
      RECT 24.92 42.905 24.99 43.255 ;
      RECT 24.92 43.355 24.99 43.705 ;
      RECT 24.92 43.805 24.99 44.155 ;
      RECT 24.92 44.255 24.99 44.605 ;
      RECT 24.92 44.705 24.99 45.055 ;
      RECT 24.92 45.155 24.99 45.505 ;
      RECT 24.92 45.605 24.99 45.955 ;
      RECT 24.92 46.055 24.99 46.405 ;
      RECT 24.92 48.305 24.99 48.655 ;
      RECT 24.92 48.755 24.99 49.105 ;
      RECT 24.92 49.205 24.99 49.555 ;
      RECT 24.92 49.655 24.99 50.005 ;
      RECT 24.92 50.105 24.99 50.455 ;
      RECT 24.92 50.555 24.99 50.905 ;
      RECT 24.92 51.005 24.99 51.355 ;
      RECT 24.92 51.455 24.99 51.805 ;
      RECT 24.92 51.905 24.99 52.255 ;
      RECT 24.92 52.355 24.99 52.705 ;
      RECT 24.92 52.805 24.99 53.155 ;
      RECT 24.92 53.255 24.99 53.605 ;
      RECT 24.92 56.405 24.99 56.755 ;
      RECT 24.92 56.855 24.99 57.205 ;
      RECT 24.92 57.305 24.99 57.655 ;
      RECT 24.92 57.755 24.99 58.105 ;
      RECT 24.92 58.205 24.99 58.555 ;
      RECT 24.92 58.655 24.99 59.005 ;
      RECT 24.92 59.105 24.99 59.455 ;
      RECT 24.92 59.555 24.99 59.905 ;
      RECT 24.92 60.005 24.99 60.355 ;
      RECT 24.92 60.455 24.99 60.805 ;
      RECT 24.92 63.605 24.99 63.955 ;
      RECT 24.92 64.055 24.99 64.405 ;
      RECT 24.92 64.505 24.99 64.855 ;
      RECT 24.92 64.955 24.99 65.305 ;
      RECT 24.92 65.405 24.99 65.755 ;
      RECT 24.92 65.855 24.99 66.205 ;
      RECT 24.92 66.305 24.99 66.655 ;
      RECT 24.92 66.755 24.99 67.105 ;
      RECT 24.92 67.205 24.99 67.555 ;
      RECT 24.92 67.655 24.99 68.005 ;
      RECT 24.92 68.105 24.99 68.455 ;
      RECT 24.64 70.625 24.99 70.695 ;
      RECT 24.92 70.805 24.99 71.155 ;
      RECT 24.92 71.255 24.99 71.605 ;
      RECT 24.92 71.705 24.99 72.055 ;
      RECT 24.92 72.155 24.99 72.505 ;
      RECT 24.92 72.605 24.99 72.955 ;
      RECT 24.92 73.055 24.99 73.405 ;
      RECT 24.92 73.505 24.99 73.855 ;
      RECT 24.92 73.955 24.99 74.305 ;
      RECT 24.92 74.405 24.99 74.755 ;
      RECT 24.92 74.855 24.99 75.205 ;
      RECT 24.92 75.305 24.99 75.655 ;
      RECT 24.92 75.755 24.99 76.105 ;
      RECT 24.92 76.205 24.99 76.555 ;
      RECT 24.92 78.455 24.99 78.805 ;
      RECT 24.92 78.905 24.99 79.255 ;
      RECT 24.92 79.355 24.99 79.705 ;
      RECT 24.92 79.805 24.99 80.155 ;
      RECT 24.92 80.255 24.99 80.605 ;
      RECT 24.92 80.705 24.99 81.055 ;
      RECT 24.92 81.155 24.99 81.505 ;
      RECT 24.92 81.605 24.99 81.955 ;
      RECT 24.92 82.055 24.99 82.405 ;
      RECT 24.92 82.505 24.99 82.855 ;
      RECT 24.92 82.955 24.99 83.305 ;
      RECT 24.92 83.405 24.99 83.755 ;
      RECT 24.92 83.855 24.99 84.205 ;
      RECT 24.92 85.655 24.99 86.005 ;
      RECT 24.92 86.105 24.99 86.455 ;
      RECT 24.92 86.555 24.99 86.905 ;
      RECT 24.92 87.005 24.99 87.355 ;
      RECT 24.92 87.455 24.99 87.805 ;
      RECT 24.92 87.905 24.99 88.255 ;
      RECT 24.92 88.355 24.99 88.705 ;
      RECT 24.92 88.805 24.99 89.155 ;
      RECT 24.92 89.255 24.99 89.605 ;
      RECT 24.92 89.705 24.99 90.055 ;
      RECT 24.92 90.155 24.99 90.505 ;
      RECT 24.92 90.605 24.99 90.955 ;
      RECT 24.92 91.055 24.99 91.405 ;
      RECT 24.92 93.305 24.99 93.655 ;
      RECT 24.92 93.755 24.99 94.105 ;
      RECT 24.92 94.205 24.99 94.555 ;
      RECT 24.92 94.655 24.99 95.005 ;
      RECT 24.92 95.105 24.99 95.455 ;
      RECT 24.92 95.555 24.99 95.905 ;
      RECT 24.92 96.005 24.99 96.355 ;
      RECT 24.92 96.455 24.99 96.805 ;
      RECT 24.92 96.905 24.99 97.255 ;
      RECT 24.92 97.355 24.99 97.705 ;
      RECT 24.92 97.805 24.99 98.155 ;
      RECT 24.92 98.255 24.99 98.605 ;
      RECT 24.92 100.955 24.99 101.305 ;
      RECT 24.92 101.405 24.99 101.755 ;
      RECT 24.92 101.855 24.99 102.205 ;
      RECT 24.92 102.305 24.99 102.655 ;
      RECT 24.92 102.755 24.99 103.105 ;
      RECT 24.92 103.205 24.99 103.555 ;
      RECT 24.92 103.655 24.99 104.005 ;
      RECT 24.92 104.105 24.99 104.455 ;
      RECT 24.92 104.555 24.99 104.905 ;
      RECT 24.92 105.005 24.99 105.355 ;
      RECT 24.92 105.455 24.99 105.805 ;
      RECT 24.92 108.155 24.99 108.505 ;
      RECT 24.92 108.605 24.99 108.955 ;
      RECT 24.92 109.055 24.99 109.405 ;
      RECT 24.92 109.505 24.99 109.855 ;
      RECT 24.92 109.955 24.99 110.305 ;
      RECT 24.92 110.405 24.99 110.755 ;
      RECT 24.92 110.855 24.99 111.205 ;
      RECT 24.92 111.305 24.99 111.655 ;
      RECT 24.92 111.755 24.99 112.105 ;
      RECT 24.92 112.205 24.99 112.555 ;
      RECT 24.92 112.655 24.99 113.005 ;
      RECT 24.92 113.105 24.99 113.455 ;
      RECT 24.92 113.555 24.99 113.905 ;
      RECT 24.92 114.005 24.99 114.355 ;
      RECT 24.92 116.255 24.99 116.605 ;
      RECT 24.92 116.705 24.99 117.055 ;
      RECT 24.92 117.155 24.99 117.505 ;
      RECT 24.92 117.605 24.99 117.955 ;
      RECT 24.92 118.055 24.99 118.405 ;
      RECT 24.92 118.505 24.99 118.855 ;
      RECT 24.92 118.955 24.99 119.305 ;
      RECT 24.92 119.405 24.99 119.755 ;
      RECT 24.92 119.855 24.99 120.205 ;
      RECT 24.92 120.305 24.99 120.655 ;
      RECT 24.92 120.755 24.99 121.105 ;
      RECT 24.92 121.205 24.99 121.555 ;
      RECT 24.92 123.455 24.99 123.805 ;
      RECT 24.92 123.905 24.99 124.255 ;
      RECT 24.92 124.355 24.99 124.705 ;
      RECT 24.92 124.805 24.99 125.155 ;
      RECT 24.92 125.255 24.99 125.605 ;
      RECT 24.92 125.705 24.99 126.055 ;
      RECT 24.92 126.155 24.99 126.505 ;
      RECT 24.92 126.605 24.99 126.955 ;
      RECT 24.92 127.055 24.99 127.405 ;
      RECT 24.92 127.505 24.99 127.855 ;
      RECT 24.92 127.955 24.99 128.305 ;
      RECT 24.92 128.405 24.99 128.755 ;
      RECT 24.92 130.655 24.99 131.005 ;
      RECT 24.92 131.105 24.99 131.455 ;
      RECT 24.92 131.555 24.99 131.905 ;
      RECT 24.92 132.005 24.99 132.355 ;
      RECT 24.92 132.455 24.99 132.805 ;
      RECT 24.92 132.905 24.99 133.255 ;
      RECT 24.92 133.355 24.99 133.705 ;
      RECT 24.92 133.805 24.99 134.155 ;
      RECT 24.92 134.255 24.99 134.605 ;
      RECT 24.92 134.705 24.99 135.055 ;
      RECT 24.92 135.155 24.99 135.505 ;
      RECT 24.92 135.605 24.99 135.955 ;
      RECT 24.92 138.755 24.99 139.105 ;
      RECT 24.92 139.205 24.99 139.555 ;
      RECT 24.92 139.655 24.99 140.005 ;
      RECT 24.92 140.105 24.99 140.455 ;
      RECT 24.92 140.555 24.99 140.905 ;
      RECT 24.92 141.005 24.99 141.355 ;
      RECT 24.92 141.455 24.99 141.805 ;
      RECT 24.92 141.905 24.99 142.255 ;
      RECT 24.92 142.355 24.99 142.705 ;
      RECT 24.92 142.805 24.99 143.155 ;
      RECT 24.92 145.955 24.99 146.305 ;
      RECT 24.92 146.405 24.99 146.755 ;
      RECT 24.92 146.855 24.99 147.205 ;
      RECT 24.92 147.305 24.99 147.655 ;
      RECT 24.92 147.755 24.99 148.105 ;
      RECT 24.92 148.205 24.99 148.555 ;
      RECT 24.92 148.655 24.99 149.005 ;
      RECT 24.92 149.105 24.99 149.455 ;
      RECT 24.92 149.555 24.99 149.905 ;
      RECT 24.92 150.005 24.99 150.355 ;
      RECT 24.92 150.455 24.99 150.805 ;
      RECT 24.64 152.975 24.99 153.045 ;
      RECT 24.92 153.155 24.99 153.505 ;
      RECT 24.92 153.605 24.99 153.955 ;
      RECT 24.92 154.055 24.99 154.405 ;
      RECT 24.92 154.505 24.99 154.855 ;
      RECT 24.92 154.955 24.99 155.305 ;
      RECT 24.92 155.405 24.99 155.755 ;
      RECT 24.92 155.855 24.99 156.205 ;
      RECT 24.92 156.305 24.99 156.655 ;
      RECT 24.92 156.755 24.99 157.105 ;
      RECT 24.92 157.205 24.99 157.555 ;
      RECT 24.92 157.655 24.99 158.005 ;
      RECT 24.92 158.105 24.99 158.455 ;
      RECT 24.92 158.555 24.99 158.905 ;
      RECT 24.92 160.805 24.99 161.155 ;
      RECT 24.92 161.255 24.99 161.605 ;
      RECT 24.92 161.705 24.99 162.055 ;
      RECT 24.92 162.155 24.99 162.505 ;
      RECT 24.92 162.605 24.99 162.955 ;
      RECT 24.92 163.055 24.99 163.405 ;
      RECT 24.92 163.505 24.99 163.855 ;
      RECT 24.92 163.955 24.99 164.305 ;
      RECT 24.92 164.405 24.99 164.755 ;
      RECT 24.92 164.855 24.99 165.205 ;
      RECT 24.92 165.305 24.99 165.655 ;
      RECT 24.92 165.755 24.99 166.105 ;
      RECT 24.92 166.205 24.99 166.555 ;
      RECT 24.92 168.005 24.99 168.355 ;
      RECT 24.92 168.455 24.99 168.805 ;
      RECT 24.92 168.905 24.99 169.255 ;
      RECT 24.92 169.355 24.99 169.705 ;
      RECT 24.92 169.805 24.99 170.155 ;
      RECT 24.92 170.255 24.99 170.605 ;
      RECT 24.92 170.705 24.99 171.055 ;
      RECT 24.92 171.155 24.99 171.505 ;
      RECT 24.92 171.605 24.99 171.955 ;
      RECT 24.92 172.055 24.99 172.405 ;
      RECT 24.92 172.505 24.99 172.855 ;
      RECT 24.92 172.955 24.99 173.305 ;
      RECT 24.92 173.405 24.99 173.755 ;
      RECT 24.92 175.655 24.99 176.005 ;
      RECT 24.92 176.105 24.99 176.455 ;
      RECT 24.92 176.555 24.99 176.905 ;
      RECT 24.92 177.005 24.99 177.355 ;
      RECT 24.92 177.455 24.99 177.805 ;
      RECT 24.92 177.905 24.99 178.255 ;
      RECT 24.92 178.355 24.99 178.705 ;
      RECT 24.92 178.805 24.99 179.155 ;
      RECT 24.92 179.255 24.99 179.605 ;
      RECT 24.92 179.705 24.99 180.055 ;
      RECT 24.92 180.155 24.99 180.505 ;
      RECT 24.92 180.605 24.99 180.955 ;
      RECT 24.92 183.305 24.99 183.655 ;
      RECT 24.92 183.755 24.99 184.105 ;
      RECT 24.92 184.205 24.99 184.555 ;
      RECT 24.92 184.655 24.99 185.005 ;
      RECT 24.92 185.105 24.99 185.455 ;
      RECT 24.92 185.555 24.99 185.905 ;
      RECT 24.92 186.005 24.99 186.355 ;
      RECT 24.92 186.455 24.99 186.805 ;
      RECT 24.92 186.905 24.99 187.255 ;
      RECT 24.92 187.355 24.99 187.705 ;
      RECT 24.92 187.805 24.99 188.155 ;
      RECT 24.92 190.505 24.99 190.855 ;
      RECT 24.92 190.955 24.99 191.305 ;
      RECT 24.92 191.405 24.99 191.755 ;
      RECT 24.92 191.855 24.99 192.205 ;
      RECT 24.92 192.305 24.99 192.655 ;
      RECT 24.92 192.755 24.99 193.105 ;
      RECT 24.92 193.205 24.99 193.555 ;
      RECT 24.92 193.655 24.99 194.005 ;
      RECT 24.92 194.105 24.99 194.455 ;
      RECT 24.92 194.555 24.99 194.905 ;
      RECT 24.92 195.005 24.99 195.355 ;
      RECT 24.92 195.455 24.99 195.805 ;
      RECT 24.92 195.905 24.99 196.255 ;
      RECT 24.92 196.355 24.99 196.705 ;
      RECT 24.92 198.605 24.99 198.955 ;
      RECT 24.92 199.055 24.99 199.405 ;
      RECT 24.92 199.505 24.99 199.855 ;
      RECT 24.92 199.955 24.99 200.305 ;
      RECT 24.92 200.405 24.99 200.755 ;
      RECT 24.92 200.855 24.99 201.205 ;
      RECT 24.92 201.305 24.99 201.655 ;
      RECT 24.92 201.755 24.99 202.105 ;
      RECT 24.92 202.205 24.99 202.555 ;
      RECT 24.92 202.655 24.99 203.005 ;
      RECT 24.92 203.105 24.99 203.455 ;
      RECT 24.92 203.555 24.99 203.905 ;
      RECT 24.92 205.805 24.99 206.155 ;
      RECT 24.92 206.255 24.99 206.605 ;
      RECT 24.92 206.705 24.99 207.055 ;
      RECT 24.92 207.155 24.99 207.505 ;
      RECT 24.92 207.605 24.99 207.955 ;
      RECT 24.92 208.055 24.99 208.405 ;
      RECT 24.92 208.505 24.99 208.855 ;
      RECT 24.92 208.955 24.99 209.305 ;
      RECT 24.92 209.405 24.99 209.755 ;
      RECT 24.92 209.855 24.99 210.205 ;
      RECT 24.92 210.305 24.99 210.655 ;
      RECT 24.92 210.755 24.99 211.105 ;
      RECT 24.92 213.005 24.99 213.355 ;
      RECT 24.92 213.455 24.99 213.805 ;
      RECT 24.92 213.905 24.99 214.255 ;
      RECT 24.92 214.355 24.99 214.705 ;
      RECT 24.92 214.805 24.99 215.155 ;
      RECT 24.92 215.255 24.99 215.605 ;
      RECT 24.92 215.705 24.99 216.055 ;
      RECT 24.92 216.155 24.99 216.505 ;
      RECT 24.92 216.605 24.99 216.955 ;
      RECT 24.92 217.055 24.99 217.405 ;
      RECT 24.92 217.505 24.99 217.855 ;
      RECT 24.92 217.955 24.99 218.305 ;
      RECT 24.92 221.105 24.99 221.455 ;
      RECT 24.92 221.555 24.99 221.905 ;
      RECT 24.92 222.005 24.99 222.355 ;
      RECT 24.92 222.455 24.99 222.805 ;
      RECT 24.92 222.905 24.99 223.255 ;
      RECT 24.92 223.355 24.99 223.705 ;
      RECT 24.92 223.805 24.99 224.155 ;
      RECT 24.92 224.255 24.99 224.605 ;
      RECT 24.92 224.705 24.99 225.055 ;
      RECT 24.92 225.155 24.99 225.505 ;
      RECT 24.92 228.305 24.99 228.655 ;
      RECT 24.92 228.755 24.99 229.105 ;
      RECT 24.92 229.205 24.99 229.555 ;
      RECT 24.92 229.655 24.99 230.005 ;
      RECT 24.92 230.105 24.99 230.455 ;
      RECT 24.92 230.555 24.99 230.905 ;
      RECT 24.92 231.005 24.99 231.355 ;
      RECT 24.92 231.455 24.99 231.805 ;
      RECT 24.92 231.905 24.99 232.255 ;
      RECT 24.92 232.355 24.99 232.705 ;
      RECT 24.92 232.805 24.99 233.155 ;
      RECT 24.64 235.325 24.99 235.395 ;
      RECT 24.92 235.505 24.99 235.855 ;
      RECT 24.92 235.955 24.99 236.305 ;
      RECT 24.92 236.405 24.99 236.755 ;
      RECT 24.92 236.855 24.99 237.205 ;
      RECT 24.92 237.305 24.99 237.655 ;
      RECT 24.92 237.755 24.99 238.105 ;
      RECT 24.92 238.205 24.99 238.555 ;
      RECT 24.92 238.655 24.99 239.005 ;
      RECT 24.92 239.105 24.99 239.455 ;
      RECT 24.92 239.555 24.99 239.905 ;
      RECT 24.92 240.005 24.99 240.355 ;
      RECT 24.92 240.455 24.99 240.805 ;
      RECT 24.92 240.905 24.99 241.255 ;
      RECT 24.92 243.155 24.99 243.505 ;
      RECT 24.92 243.605 24.99 243.955 ;
      RECT 24.92 244.055 24.99 244.405 ;
      RECT 24.92 244.505 24.99 244.855 ;
      RECT 24.92 244.955 24.99 245.305 ;
      RECT 24.92 245.405 24.99 245.755 ;
      RECT 24.92 245.855 24.99 246.205 ;
      RECT 24.92 246.305 24.99 246.655 ;
      RECT 24.92 246.755 24.99 247.105 ;
      RECT 24.92 247.205 24.99 247.555 ;
      RECT 24.92 247.655 24.99 248.005 ;
      RECT 24.92 248.105 24.99 248.455 ;
      RECT 24.92 248.555 24.99 248.905 ;
      RECT 24.92 250.355 24.99 250.705 ;
      RECT 24.92 250.805 24.99 251.155 ;
      RECT 24.92 251.255 24.99 251.605 ;
      RECT 24.92 251.705 24.99 252.055 ;
      RECT 24.92 252.155 24.99 252.505 ;
      RECT 24.92 252.605 24.99 252.955 ;
      RECT 24.92 253.055 24.99 253.405 ;
      RECT 24.92 253.505 24.99 253.855 ;
      RECT 24.92 253.955 24.99 254.305 ;
      RECT 24.92 254.405 24.99 254.755 ;
      RECT 24.92 254.855 24.99 255.205 ;
      RECT 24.92 255.305 24.99 255.655 ;
      RECT 24.92 255.755 24.99 256.105 ;
      RECT 24.92 258.005 24.99 258.355 ;
      RECT 24.92 258.455 24.99 258.805 ;
      RECT 24.92 258.905 24.99 259.255 ;
      RECT 24.92 259.355 24.99 259.705 ;
      RECT 24.92 259.805 24.99 260.155 ;
      RECT 24.92 260.255 24.99 260.605 ;
      RECT 24.92 260.705 24.99 261.055 ;
      RECT 24.92 261.155 24.99 261.505 ;
      RECT 24.92 261.605 24.99 261.955 ;
      RECT 24.92 262.055 24.99 262.405 ;
      RECT 24.92 262.505 24.99 262.855 ;
      RECT 24.92 262.955 24.99 263.305 ;
      RECT 24.92 265.655 24.99 266.005 ;
      RECT 24.92 266.105 24.99 266.455 ;
      RECT 24.92 266.555 24.99 266.905 ;
      RECT 24.92 267.005 24.99 267.355 ;
      RECT 24.92 267.455 24.99 267.805 ;
      RECT 24.92 267.905 24.99 268.255 ;
      RECT 24.92 268.355 24.99 268.705 ;
      RECT 24.92 268.805 24.99 269.155 ;
      RECT 24.92 269.255 24.99 269.605 ;
      RECT 24.92 269.705 24.99 270.055 ;
      RECT 24.92 270.155 24.99 270.505 ;
      RECT 24.92 272.855 24.99 273.205 ;
      RECT 24.92 273.305 24.99 273.655 ;
      RECT 24.92 273.755 24.99 274.105 ;
      RECT 24.92 274.205 24.99 274.555 ;
      RECT 24.92 274.655 24.99 275.005 ;
      RECT 24.92 275.105 24.99 275.455 ;
      RECT 24.92 275.555 24.99 275.905 ;
      RECT 24.92 276.005 24.99 276.355 ;
      RECT 24.92 276.455 24.99 276.805 ;
      RECT 24.92 276.905 24.99 277.255 ;
      RECT 24.92 277.355 24.99 277.705 ;
      RECT 24.92 277.805 24.99 278.155 ;
      RECT 24.92 278.255 24.99 278.605 ;
      RECT 24.92 278.705 24.99 279.055 ;
      RECT 24.92 280.955 24.99 281.305 ;
      RECT 24.92 281.405 24.99 281.755 ;
      RECT 24.92 281.855 24.99 282.205 ;
      RECT 24.92 282.305 24.99 282.655 ;
      RECT 24.92 282.755 24.99 283.105 ;
      RECT 24.92 283.205 24.99 283.555 ;
      RECT 24.92 283.655 24.99 284.005 ;
      RECT 24.92 284.105 24.99 284.455 ;
      RECT 24.92 284.555 24.99 284.905 ;
      RECT 24.92 285.005 24.99 285.355 ;
      RECT 24.92 285.455 24.99 285.805 ;
      RECT 24.92 285.905 24.99 286.255 ;
      RECT 24.92 288.155 24.99 288.505 ;
      RECT 24.92 288.605 24.99 288.955 ;
      RECT 24.92 289.055 24.99 289.405 ;
      RECT 24.92 289.505 24.99 289.855 ;
      RECT 24.92 289.955 24.99 290.305 ;
      RECT 24.92 290.405 24.99 290.755 ;
      RECT 24.92 290.855 24.99 291.205 ;
      RECT 24.92 291.305 24.99 291.655 ;
      RECT 24.92 291.755 24.99 292.105 ;
      RECT 24.92 292.205 24.99 292.555 ;
      RECT 24.92 292.655 24.99 293.005 ;
      RECT 24.92 293.105 24.99 293.455 ;
      RECT 24.92 295.355 24.99 295.705 ;
      RECT 24.92 295.805 24.99 296.155 ;
      RECT 24.92 296.255 24.99 296.605 ;
      RECT 24.92 296.705 24.99 297.055 ;
      RECT 24.92 297.155 24.99 297.505 ;
      RECT 24.92 297.605 24.99 297.955 ;
      RECT 24.92 298.055 24.99 298.405 ;
      RECT 24.92 298.505 24.99 298.855 ;
      RECT 24.92 298.955 24.99 299.305 ;
      RECT 24.92 299.405 24.99 299.755 ;
      RECT 24.92 299.855 24.99 300.205 ;
      RECT 24.92 300.305 24.99 300.655 ;
      RECT 24.92 303.455 24.99 303.805 ;
      RECT 24.92 303.905 24.99 304.255 ;
      RECT 24.92 304.355 24.99 304.705 ;
      RECT 24.92 304.805 24.99 305.155 ;
      RECT 24.92 305.255 24.99 305.605 ;
      RECT 24.92 305.705 24.99 306.055 ;
      RECT 24.92 306.155 24.99 306.505 ;
      RECT 24.92 306.605 24.99 306.955 ;
      RECT 24.92 307.055 24.99 307.405 ;
      RECT 24.92 307.505 24.99 307.855 ;
      RECT 24.92 310.655 24.99 311.005 ;
      RECT 24.92 311.105 24.99 311.455 ;
      RECT 24.92 311.555 24.99 311.905 ;
      RECT 24.92 312.005 24.99 312.355 ;
      RECT 24.92 312.455 24.99 312.805 ;
      RECT 24.92 312.905 24.99 313.255 ;
      RECT 24.92 313.355 24.99 313.705 ;
      RECT 24.92 313.805 24.99 314.155 ;
      RECT 24.92 314.255 24.99 314.605 ;
      RECT 24.92 314.705 24.99 315.055 ;
      RECT 24.92 315.155 24.99 315.505 ;
      RECT 24.64 317.675 24.99 317.745 ;
      RECT 24.92 317.855 24.99 318.205 ;
      RECT 24.92 318.305 24.99 318.655 ;
      RECT 24.92 318.755 24.99 319.105 ;
      RECT 24.92 319.205 24.99 319.555 ;
      RECT 24.92 319.655 24.99 320.005 ;
      RECT 24.92 320.105 24.99 320.455 ;
      RECT 24.92 320.555 24.99 320.905 ;
      RECT 24.92 321.005 24.99 321.355 ;
      RECT 24.92 321.455 24.99 321.805 ;
      RECT 24.92 321.905 24.99 322.255 ;
      RECT 24.92 322.355 24.99 322.705 ;
      RECT 24.92 322.805 24.99 323.155 ;
      RECT 24.92 323.255 24.99 323.605 ;
      RECT 24.92 325.505 24.99 325.855 ;
      RECT 24.92 325.955 24.99 326.305 ;
      RECT 24.92 326.405 24.99 326.755 ;
      RECT 24.92 326.855 24.99 327.205 ;
      RECT 24.92 327.305 24.99 327.655 ;
      RECT 24.92 327.755 24.99 328.105 ;
      RECT 24.92 328.205 24.99 328.555 ;
      RECT 24.92 328.655 24.99 329.005 ;
      RECT 24.92 329.105 24.99 329.455 ;
      RECT 24.92 329.555 24.99 329.905 ;
      RECT 24.92 330.005 24.99 330.355 ;
      RECT 24.92 330.455 24.99 330.805 ;
      RECT 24.92 330.905 24.99 331.255 ;
      RECT 24.92 332.705 24.99 333.055 ;
      RECT 24.92 333.155 24.99 333.505 ;
      RECT 24.92 333.605 24.99 333.955 ;
      RECT 24.92 334.055 24.99 334.405 ;
      RECT 24.92 334.505 24.99 334.855 ;
      RECT 24.92 334.955 24.99 335.305 ;
      RECT 24.92 335.405 24.99 335.755 ;
      RECT 24.92 335.855 24.99 336.205 ;
      RECT 24.92 336.305 24.99 336.655 ;
      RECT 24.92 336.755 24.99 337.105 ;
      RECT 24.92 337.205 24.99 337.555 ;
      RECT 24.92 337.655 24.99 338.005 ;
      RECT 24.92 338.105 24.99 338.455 ;
      RECT 24.92 340.355 24.99 340.705 ;
      RECT 24.92 340.805 24.99 341.155 ;
      RECT 24.92 341.255 24.99 341.605 ;
      RECT 24.92 341.705 24.99 342.055 ;
      RECT 24.92 342.155 24.99 342.505 ;
      RECT 24.92 342.605 24.99 342.955 ;
      RECT 24.92 343.055 24.99 343.405 ;
      RECT 24.92 343.505 24.99 343.855 ;
      RECT 24.92 343.955 24.99 344.305 ;
      RECT 24.92 344.405 24.99 344.755 ;
      RECT 24.92 344.855 24.99 345.205 ;
      RECT 24.78 3.305 24.85 3.655 ;
      RECT 24.78 3.755 24.85 4.105 ;
      RECT 24.78 4.205 24.85 4.555 ;
      RECT 24.78 4.655 24.85 5.005 ;
      RECT 24.78 5.105 24.85 5.455 ;
      RECT 24.78 10.955 24.85 11.305 ;
      RECT 24.78 11.405 24.85 11.755 ;
      RECT 24.78 11.855 24.85 12.205 ;
      RECT 24.78 12.305 24.85 12.655 ;
      RECT 24.78 12.755 24.85 13.105 ;
      RECT 24.78 13.205 24.85 13.555 ;
      RECT 24.78 18.605 24.85 18.955 ;
      RECT 24.78 19.055 24.85 19.405 ;
      RECT 24.78 19.505 24.85 19.855 ;
      RECT 24.78 19.955 24.85 20.305 ;
      RECT 24.78 20.405 24.85 20.755 ;
      RECT 24.78 20.855 24.85 21.205 ;
      RECT 24.78 25.805 24.85 26.155 ;
      RECT 24.78 26.255 24.85 26.605 ;
      RECT 24.78 26.705 24.85 27.055 ;
      RECT 24.78 27.155 24.85 27.505 ;
      RECT 24.78 27.605 24.85 27.955 ;
      RECT 24.78 28.055 24.85 28.405 ;
      RECT 24.78 33.905 24.85 34.255 ;
      RECT 24.78 34.355 24.85 34.705 ;
      RECT 24.78 34.805 24.85 35.155 ;
      RECT 24.78 35.255 24.85 35.605 ;
      RECT 24.78 41.105 24.85 41.455 ;
      RECT 24.78 41.555 24.85 41.905 ;
      RECT 24.78 42.005 24.85 42.355 ;
      RECT 24.78 42.455 24.85 42.805 ;
      RECT 24.78 48.305 24.85 48.655 ;
      RECT 24.78 48.755 24.85 49.105 ;
      RECT 24.78 49.205 24.85 49.555 ;
      RECT 24.78 49.655 24.85 50.005 ;
      RECT 24.78 50.105 24.85 50.455 ;
      RECT 24.78 50.555 24.85 50.905 ;
      RECT 24.78 51.005 24.85 51.355 ;
      RECT 24.78 56.405 24.85 56.755 ;
      RECT 24.78 56.855 24.85 57.205 ;
      RECT 24.78 57.305 24.85 57.655 ;
      RECT 24.78 57.755 24.85 58.105 ;
      RECT 24.78 58.205 24.85 58.555 ;
      RECT 24.78 63.605 24.85 63.955 ;
      RECT 24.78 64.055 24.85 64.405 ;
      RECT 24.78 64.505 24.85 64.855 ;
      RECT 24.78 64.955 24.85 65.305 ;
      RECT 24.78 65.405 24.85 65.755 ;
      RECT 24.78 70.805 24.85 71.155 ;
      RECT 24.78 71.255 24.85 71.605 ;
      RECT 24.78 71.705 24.85 72.055 ;
      RECT 24.78 72.155 24.85 72.505 ;
      RECT 24.78 72.605 24.85 72.955 ;
      RECT 24.78 78.455 24.85 78.805 ;
      RECT 24.78 78.905 24.85 79.255 ;
      RECT 24.78 79.355 24.85 79.705 ;
      RECT 24.78 79.805 24.85 80.155 ;
      RECT 24.78 85.655 24.85 86.005 ;
      RECT 24.78 86.105 24.85 86.455 ;
      RECT 24.78 86.555 24.85 86.905 ;
      RECT 24.78 87.005 24.85 87.355 ;
      RECT 24.78 87.455 24.85 87.805 ;
      RECT 24.78 93.305 24.85 93.655 ;
      RECT 24.78 93.755 24.85 94.105 ;
      RECT 24.78 94.205 24.85 94.555 ;
      RECT 24.78 94.655 24.85 95.005 ;
      RECT 24.78 95.105 24.85 95.455 ;
      RECT 24.78 95.555 24.85 95.905 ;
      RECT 24.78 100.955 24.85 101.305 ;
      RECT 24.78 101.405 24.85 101.755 ;
      RECT 24.78 101.855 24.85 102.205 ;
      RECT 24.78 102.305 24.85 102.655 ;
      RECT 24.78 102.755 24.85 103.105 ;
      RECT 24.78 103.205 24.85 103.555 ;
      RECT 24.78 108.155 24.85 108.505 ;
      RECT 24.78 108.605 24.85 108.955 ;
      RECT 24.78 109.055 24.85 109.405 ;
      RECT 24.78 109.505 24.85 109.855 ;
      RECT 24.78 109.955 24.85 110.305 ;
      RECT 24.78 110.405 24.85 110.755 ;
      RECT 24.78 116.255 24.85 116.605 ;
      RECT 24.78 116.705 24.85 117.055 ;
      RECT 24.78 117.155 24.85 117.505 ;
      RECT 24.78 117.605 24.85 117.955 ;
      RECT 24.78 123.455 24.85 123.805 ;
      RECT 24.78 123.905 24.85 124.255 ;
      RECT 24.78 124.355 24.85 124.705 ;
      RECT 24.78 124.805 24.85 125.155 ;
      RECT 24.78 130.655 24.85 131.005 ;
      RECT 24.78 131.105 24.85 131.455 ;
      RECT 24.78 131.555 24.85 131.905 ;
      RECT 24.78 132.005 24.85 132.355 ;
      RECT 24.78 132.455 24.85 132.805 ;
      RECT 24.78 132.905 24.85 133.255 ;
      RECT 24.78 133.355 24.85 133.705 ;
      RECT 24.78 138.755 24.85 139.105 ;
      RECT 24.78 139.205 24.85 139.555 ;
      RECT 24.78 139.655 24.85 140.005 ;
      RECT 24.78 140.105 24.85 140.455 ;
      RECT 24.78 140.555 24.85 140.905 ;
      RECT 24.78 145.955 24.85 146.305 ;
      RECT 24.78 146.405 24.85 146.755 ;
      RECT 24.78 146.855 24.85 147.205 ;
      RECT 24.78 147.305 24.85 147.655 ;
      RECT 24.78 147.755 24.85 148.105 ;
      RECT 24.78 153.155 24.85 153.505 ;
      RECT 24.78 153.605 24.85 153.955 ;
      RECT 24.78 154.055 24.85 154.405 ;
      RECT 24.78 154.505 24.85 154.855 ;
      RECT 24.78 154.955 24.85 155.305 ;
      RECT 24.78 160.805 24.85 161.155 ;
      RECT 24.78 161.255 24.85 161.605 ;
      RECT 24.78 161.705 24.85 162.055 ;
      RECT 24.78 162.155 24.85 162.505 ;
      RECT 24.78 168.005 24.85 168.355 ;
      RECT 24.78 168.455 24.85 168.805 ;
      RECT 24.78 168.905 24.85 169.255 ;
      RECT 24.78 169.355 24.85 169.705 ;
      RECT 24.78 169.805 24.85 170.155 ;
      RECT 24.78 175.655 24.85 176.005 ;
      RECT 24.78 176.105 24.85 176.455 ;
      RECT 24.78 176.555 24.85 176.905 ;
      RECT 24.78 177.005 24.85 177.355 ;
      RECT 24.78 177.455 24.85 177.805 ;
      RECT 24.78 177.905 24.85 178.255 ;
      RECT 24.78 183.305 24.85 183.655 ;
      RECT 24.78 183.755 24.85 184.105 ;
      RECT 24.78 184.205 24.85 184.555 ;
      RECT 24.78 184.655 24.85 185.005 ;
      RECT 24.78 185.105 24.85 185.455 ;
      RECT 24.78 185.555 24.85 185.905 ;
      RECT 24.78 190.505 24.85 190.855 ;
      RECT 24.78 190.955 24.85 191.305 ;
      RECT 24.78 191.405 24.85 191.755 ;
      RECT 24.78 191.855 24.85 192.205 ;
      RECT 24.78 192.305 24.85 192.655 ;
      RECT 24.78 192.755 24.85 193.105 ;
      RECT 24.78 198.605 24.85 198.955 ;
      RECT 24.78 199.055 24.85 199.405 ;
      RECT 24.78 199.505 24.85 199.855 ;
      RECT 24.78 199.955 24.85 200.305 ;
      RECT 24.78 205.805 24.85 206.155 ;
      RECT 24.78 206.255 24.85 206.605 ;
      RECT 24.78 206.705 24.85 207.055 ;
      RECT 24.78 207.155 24.85 207.505 ;
      RECT 24.78 213.005 24.85 213.355 ;
      RECT 24.78 213.455 24.85 213.805 ;
      RECT 24.78 213.905 24.85 214.255 ;
      RECT 24.78 214.355 24.85 214.705 ;
      RECT 24.78 214.805 24.85 215.155 ;
      RECT 24.78 215.255 24.85 215.605 ;
      RECT 24.78 215.705 24.85 216.055 ;
      RECT 24.78 221.105 24.85 221.455 ;
      RECT 24.78 221.555 24.85 221.905 ;
      RECT 24.78 222.005 24.85 222.355 ;
      RECT 24.78 222.455 24.85 222.805 ;
      RECT 24.78 222.905 24.85 223.255 ;
      RECT 24.78 228.305 24.85 228.655 ;
      RECT 24.78 228.755 24.85 229.105 ;
      RECT 24.78 229.205 24.85 229.555 ;
      RECT 24.78 229.655 24.85 230.005 ;
      RECT 24.78 230.105 24.85 230.455 ;
      RECT 24.78 235.505 24.85 235.855 ;
      RECT 24.78 235.955 24.85 236.305 ;
      RECT 24.78 236.405 24.85 236.755 ;
      RECT 24.78 236.855 24.85 237.205 ;
      RECT 24.78 237.305 24.85 237.655 ;
      RECT 24.78 243.155 24.85 243.505 ;
      RECT 24.78 243.605 24.85 243.955 ;
      RECT 24.78 244.055 24.85 244.405 ;
      RECT 24.78 244.505 24.85 244.855 ;
      RECT 24.78 250.355 24.85 250.705 ;
      RECT 24.78 250.805 24.85 251.155 ;
      RECT 24.78 251.255 24.85 251.605 ;
      RECT 24.78 251.705 24.85 252.055 ;
      RECT 24.78 252.155 24.85 252.505 ;
      RECT 24.78 258.005 24.85 258.355 ;
      RECT 24.78 258.455 24.85 258.805 ;
      RECT 24.78 258.905 24.85 259.255 ;
      RECT 24.78 259.355 24.85 259.705 ;
      RECT 24.78 259.805 24.85 260.155 ;
      RECT 24.78 260.255 24.85 260.605 ;
      RECT 24.78 265.655 24.85 266.005 ;
      RECT 24.78 266.105 24.85 266.455 ;
      RECT 24.78 266.555 24.85 266.905 ;
      RECT 24.78 267.005 24.85 267.355 ;
      RECT 24.78 267.455 24.85 267.805 ;
      RECT 24.78 267.905 24.85 268.255 ;
      RECT 24.78 272.855 24.85 273.205 ;
      RECT 24.78 273.305 24.85 273.655 ;
      RECT 24.78 273.755 24.85 274.105 ;
      RECT 24.78 274.205 24.85 274.555 ;
      RECT 24.78 274.655 24.85 275.005 ;
      RECT 24.78 275.105 24.85 275.455 ;
      RECT 24.78 280.955 24.85 281.305 ;
      RECT 24.78 281.405 24.85 281.755 ;
      RECT 24.78 281.855 24.85 282.205 ;
      RECT 24.78 282.305 24.85 282.655 ;
      RECT 24.78 288.155 24.85 288.505 ;
      RECT 24.78 288.605 24.85 288.955 ;
      RECT 24.78 289.055 24.85 289.405 ;
      RECT 24.78 289.505 24.85 289.855 ;
      RECT 24.78 295.355 24.85 295.705 ;
      RECT 24.78 295.805 24.85 296.155 ;
      RECT 24.78 296.255 24.85 296.605 ;
      RECT 24.78 296.705 24.85 297.055 ;
      RECT 24.78 297.155 24.85 297.505 ;
      RECT 24.78 297.605 24.85 297.955 ;
      RECT 24.78 298.055 24.85 298.405 ;
      RECT 24.78 303.455 24.85 303.805 ;
      RECT 24.78 303.905 24.85 304.255 ;
      RECT 24.78 304.355 24.85 304.705 ;
      RECT 24.78 304.805 24.85 305.155 ;
      RECT 24.78 305.255 24.85 305.605 ;
      RECT 24.78 310.655 24.85 311.005 ;
      RECT 24.78 311.105 24.85 311.455 ;
      RECT 24.78 311.555 24.85 311.905 ;
      RECT 24.78 312.005 24.85 312.355 ;
      RECT 24.78 312.455 24.85 312.805 ;
      RECT 24.78 317.855 24.85 318.205 ;
      RECT 24.78 318.305 24.85 318.655 ;
      RECT 24.78 318.755 24.85 319.105 ;
      RECT 24.78 319.205 24.85 319.555 ;
      RECT 24.78 319.655 24.85 320.005 ;
      RECT 24.78 325.505 24.85 325.855 ;
      RECT 24.78 325.955 24.85 326.305 ;
      RECT 24.78 326.405 24.85 326.755 ;
      RECT 24.78 326.855 24.85 327.205 ;
      RECT 24.78 332.705 24.85 333.055 ;
      RECT 24.78 333.155 24.85 333.505 ;
      RECT 24.78 333.605 24.85 333.955 ;
      RECT 24.78 334.055 24.85 334.405 ;
      RECT 24.78 334.505 24.85 334.855 ;
      RECT 24.78 340.355 24.85 340.705 ;
      RECT 24.78 340.805 24.85 341.155 ;
      RECT 24.78 341.255 24.85 341.605 ;
      RECT 24.78 341.705 24.85 342.055 ;
      RECT 24.78 342.155 24.85 342.505 ;
      RECT 24.78 342.605 24.85 342.955 ;
      RECT 24.655 32.355 24.775 33.355 ;
      RECT 24.655 55.345 24.775 55.845 ;
      RECT 24.655 114.71 24.775 115.71 ;
      RECT 24.655 137.7 24.775 138.2 ;
      RECT 24.655 197.065 24.775 198.065 ;
      RECT 24.655 220.055 24.775 220.555 ;
      RECT 24.655 279.42 24.775 280.42 ;
      RECT 24.655 302.41 24.775 302.91 ;
      RECT 24.65 17.8 24.77 18.3 ;
      RECT 24.65 77.165 24.77 78.165 ;
      RECT 24.65 100.155 24.77 100.655 ;
      RECT 24.65 159.52 24.77 160.52 ;
      RECT 24.65 182.51 24.77 183.01 ;
      RECT 24.65 241.875 24.77 242.875 ;
      RECT 24.65 264.865 24.77 265.365 ;
      RECT 24.65 324.23 24.77 325.23 ;
      RECT 24.645 39.62 24.765 40.62 ;
      RECT 24.645 62.61 24.765 63.11 ;
      RECT 24.645 121.975 24.765 122.975 ;
      RECT 24.645 144.965 24.765 145.465 ;
      RECT 24.645 204.33 24.765 205.33 ;
      RECT 24.645 227.32 24.765 227.82 ;
      RECT 24.645 286.685 24.765 287.685 ;
      RECT 24.645 309.675 24.765 310.175 ;
      RECT 24.64 2.075 24.76 3.075 ;
      RECT 24.64 25.065 24.76 25.565 ;
      RECT 24.64 84.43 24.76 85.43 ;
      RECT 24.64 107.42 24.76 107.92 ;
      RECT 24.64 166.785 24.76 167.785 ;
      RECT 24.64 189.775 24.76 190.275 ;
      RECT 24.64 249.14 24.76 250.14 ;
      RECT 24.64 272.13 24.76 272.63 ;
      RECT 24.64 331.495 24.76 332.495 ;
      RECT 24.635 46.885 24.755 47.885 ;
      RECT 24.635 69.875 24.755 70.375 ;
      RECT 24.635 129.24 24.755 130.24 ;
      RECT 24.635 152.23 24.755 152.73 ;
      RECT 24.635 211.595 24.755 212.595 ;
      RECT 24.635 234.585 24.755 235.085 ;
      RECT 24.635 293.95 24.755 294.95 ;
      RECT 24.635 316.94 24.755 317.44 ;
      RECT 24.63 9.34 24.75 10.34 ;
      RECT 24.63 91.695 24.75 92.695 ;
      RECT 24.63 174.05 24.75 175.05 ;
      RECT 24.63 256.405 24.75 257.405 ;
      RECT 24.63 338.76 24.75 339.76 ;
      RECT 24.625 54.15 24.745 55.15 ;
      RECT 24.625 136.505 24.745 137.505 ;
      RECT 24.625 218.86 24.745 219.86 ;
      RECT 24.625 301.215 24.745 302.215 ;
      RECT 24.62 16.605 24.74 17.605 ;
      RECT 24.62 98.96 24.74 99.96 ;
      RECT 24.62 181.315 24.74 182.315 ;
      RECT 24.62 263.67 24.74 264.67 ;
      RECT 24.615 61.415 24.735 62.415 ;
      RECT 24.615 143.77 24.735 144.77 ;
      RECT 24.615 226.125 24.735 227.125 ;
      RECT 24.615 308.48 24.735 309.48 ;
      RECT 24.61 23.87 24.73 24.87 ;
      RECT 24.61 106.225 24.73 107.225 ;
      RECT 24.61 188.58 24.73 189.58 ;
      RECT 24.61 270.935 24.73 271.935 ;
      RECT 24.605 68.68 24.725 69.68 ;
      RECT 24.605 151.035 24.725 152.035 ;
      RECT 24.605 233.39 24.725 234.39 ;
      RECT 24.605 315.745 24.725 316.745 ;
      RECT 24.6 31.135 24.72 32.135 ;
      RECT 24.6 113.49 24.72 114.49 ;
      RECT 24.6 195.845 24.72 196.845 ;
      RECT 24.6 278.2 24.72 279.2 ;
      RECT 24.595 75.945 24.715 76.945 ;
      RECT 24.595 158.3 24.715 159.3 ;
      RECT 24.595 240.655 24.715 241.655 ;
      RECT 24.595 323.01 24.715 324.01 ;
      RECT 24.59 38.4 24.71 39.4 ;
      RECT 24.59 120.755 24.71 121.755 ;
      RECT 24.59 203.11 24.71 204.11 ;
      RECT 24.59 285.465 24.71 286.465 ;
      RECT 24.585 0.855 24.705 1.855 ;
      RECT 24.585 83.21 24.705 84.21 ;
      RECT 24.585 165.565 24.705 166.565 ;
      RECT 24.585 247.92 24.705 248.92 ;
      RECT 24.585 330.275 24.705 331.275 ;
      RECT 24.58 45.665 24.7 46.665 ;
      RECT 24.58 128.02 24.7 129.02 ;
      RECT 24.58 210.375 24.7 211.375 ;
      RECT 24.58 292.73 24.7 293.73 ;
      RECT 24.575 8.12 24.695 9.12 ;
      RECT 24.575 90.475 24.695 91.475 ;
      RECT 24.575 172.83 24.695 173.83 ;
      RECT 24.575 255.185 24.695 256.185 ;
      RECT 24.575 337.54 24.695 338.54 ;
      RECT 24.57 52.93 24.69 53.93 ;
      RECT 24.57 135.285 24.69 136.285 ;
      RECT 24.57 217.64 24.69 218.64 ;
      RECT 24.57 299.995 24.69 300.995 ;
      RECT 24.565 15.385 24.685 16.385 ;
      RECT 24.565 97.74 24.685 98.74 ;
      RECT 24.565 180.095 24.685 181.095 ;
      RECT 24.565 262.45 24.685 263.45 ;
      RECT 24.56 60.195 24.68 61.195 ;
      RECT 24.56 142.55 24.68 143.55 ;
      RECT 24.56 224.905 24.68 225.905 ;
      RECT 24.56 307.26 24.68 308.26 ;
      RECT 24.555 22.65 24.675 23.65 ;
      RECT 24.555 105.005 24.675 106.005 ;
      RECT 24.555 187.36 24.675 188.36 ;
      RECT 24.555 269.715 24.675 270.715 ;
      RECT 24.55 67.46 24.67 68.46 ;
      RECT 24.55 149.815 24.67 150.815 ;
      RECT 24.55 232.17 24.67 233.17 ;
      RECT 24.55 314.525 24.67 315.525 ;
      RECT 24.545 29.915 24.665 30.915 ;
      RECT 24.545 112.27 24.665 113.27 ;
      RECT 24.545 194.625 24.665 195.625 ;
      RECT 24.545 276.98 24.665 277.98 ;
      RECT 24.54 74.725 24.66 75.725 ;
      RECT 24.54 157.08 24.66 158.08 ;
      RECT 24.54 239.435 24.66 240.435 ;
      RECT 24.54 321.79 24.66 322.79 ;
      RECT 24.535 37.18 24.655 38.18 ;
      RECT 24.535 119.535 24.655 120.535 ;
      RECT 24.535 201.89 24.655 202.89 ;
      RECT 24.535 284.245 24.655 285.245 ;
      RECT 24.53 81.99 24.65 82.99 ;
      RECT 24.53 164.345 24.65 165.345 ;
      RECT 24.53 246.7 24.65 247.7 ;
      RECT 24.53 329.055 24.65 330.055 ;
      RECT 24.525 44.445 24.645 45.445 ;
      RECT 24.525 126.8 24.645 127.8 ;
      RECT 24.525 209.155 24.645 210.155 ;
      RECT 24.525 291.51 24.645 292.51 ;
      RECT 24.52 6.9 24.64 7.9 ;
      RECT 24.52 89.255 24.64 90.255 ;
      RECT 24.52 171.61 24.64 172.61 ;
      RECT 24.52 253.965 24.64 254.965 ;
      RECT 24.52 336.32 24.64 337.32 ;
      RECT 24.515 51.71 24.635 52.71 ;
      RECT 24.515 134.065 24.635 135.065 ;
      RECT 24.515 216.42 24.635 217.42 ;
      RECT 24.515 298.775 24.635 299.775 ;
      RECT 24.51 14.165 24.63 15.165 ;
      RECT 24.51 96.52 24.63 97.52 ;
      RECT 24.51 178.875 24.63 179.875 ;
      RECT 24.51 261.23 24.63 262.23 ;
      RECT 24.51 343.585 24.63 344.585 ;
      RECT 24.505 58.975 24.625 59.975 ;
      RECT 24.505 141.33 24.625 142.33 ;
      RECT 24.505 223.685 24.625 224.685 ;
      RECT 24.505 306.04 24.625 307.04 ;
    LAYER M7 SPACING 0.05 ;
      RECT 67.095 0 92.2 346 ;
      RECT 0 0 25.075 346 ;
  END
  PROPERTY CatenaDesignType "chipAssembly" ;
END phy_spine_u

END LIBRARY
